VERSION 5.7 ;
BUSBITCHARS "[]" ;
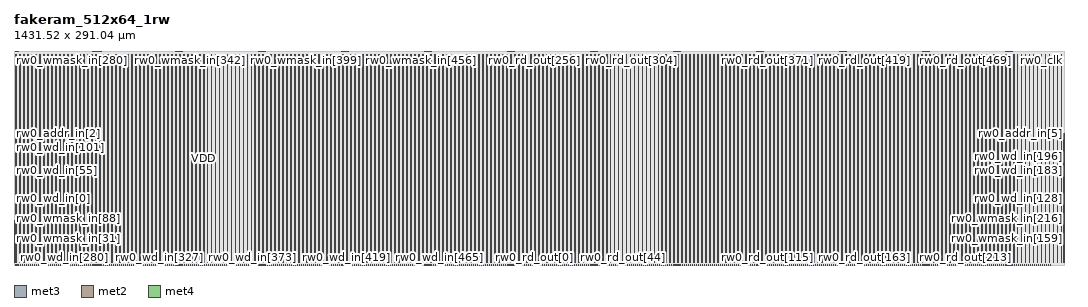
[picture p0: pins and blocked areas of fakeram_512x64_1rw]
MACRO fakeram_512x64_1rw
  FOREIGN fakeram_512x64_1rw 0 0 ;
  SYMMETRY X Y R90 ;
  SIZE 1431.520 BY 291.040 ;
  CLASS BLOCK ;
  PIN rw0_wmask_in[0]
    DIRECTION INPUT ;
    USE SIGNAL ;
    SHAPE ABUTMENT ;
    PORT
      LAYER met3 ;
      RECT 0.000 3.930 0.900 4.230 ;
    END
  END rw0_wmask_in[0]
  PIN rw0_wmask_in[1]
    DIRECTION INPUT ;
    USE SIGNAL ;
    SHAPE ABUTMENT ;
    PORT
      LAYER met3 ;
      RECT 0.000 4.610 0.900 4.910 ;
    END
  END rw0_wmask_in[1]
  PIN rw0_wmask_in[2]
    DIRECTION INPUT ;
    USE SIGNAL ;
    SHAPE ABUTMENT ;
    PORT
      LAYER met3 ;
      RECT 0.000 5.290 0.900 5.590 ;
    END
  END rw0_wmask_in[2]
  PIN rw0_wmask_in[3]
    DIRECTION INPUT ;
    USE SIGNAL ;
    SHAPE ABUTMENT ;
    PORT
      LAYER met3 ;
      RECT 0.000 5.970 0.900 6.270 ;
    END
  END rw0_wmask_in[3]
  PIN rw0_wmask_in[4]
    DIRECTION INPUT ;
    USE SIGNAL ;
    SHAPE ABUTMENT ;
    PORT
      LAYER met3 ;
      RECT 0.000 6.650 0.900 6.950 ;
    END
  END rw0_wmask_in[4]
  PIN rw0_wmask_in[5]
    DIRECTION INPUT ;
    USE SIGNAL ;
    SHAPE ABUTMENT ;
    PORT
      LAYER met3 ;
      RECT 0.000 7.330 0.900 7.630 ;
    END
  END rw0_wmask_in[5]
  PIN rw0_wmask_in[6]
    DIRECTION INPUT ;
    USE SIGNAL ;
    SHAPE ABUTMENT ;
    PORT
      LAYER met3 ;
      RECT 0.000 8.010 0.900 8.310 ;
    END
  END rw0_wmask_in[6]
  PIN rw0_wmask_in[7]
    DIRECTION INPUT ;
    USE SIGNAL ;
    SHAPE ABUTMENT ;
    PORT
      LAYER met3 ;
      RECT 0.000 8.690 0.900 8.990 ;
    END
  END rw0_wmask_in[7]
  PIN rw0_wmask_in[8]
    DIRECTION INPUT ;
    USE SIGNAL ;
    SHAPE ABUTMENT ;
    PORT
      LAYER met3 ;
      RECT 0.000 9.370 0.900 9.670 ;
    END
  END rw0_wmask_in[8]
  PIN rw0_wmask_in[9]
    DIRECTION INPUT ;
    USE SIGNAL ;
    SHAPE ABUTMENT ;
    PORT
      LAYER met3 ;
      RECT 0.000 10.050 0.900 10.350 ;
    END
  END rw0_wmask_in[9]
  PIN rw0_wmask_in[10]
    DIRECTION INPUT ;
    USE SIGNAL ;
    SHAPE ABUTMENT ;
    PORT
      LAYER met3 ;
      RECT 0.000 10.730 0.900 11.030 ;
    END
  END rw0_wmask_in[10]
  PIN rw0_wmask_in[11]
    DIRECTION INPUT ;
    USE SIGNAL ;
    SHAPE ABUTMENT ;
    PORT
      LAYER met3 ;
      RECT 0.000 11.410 0.900 11.710 ;
    END
  END rw0_wmask_in[11]
  PIN rw0_wmask_in[12]
    DIRECTION INPUT ;
    USE SIGNAL ;
    SHAPE ABUTMENT ;
    PORT
      LAYER met3 ;
      RECT 0.000 12.090 0.900 12.390 ;
    END
  END rw0_wmask_in[12]
  PIN rw0_wmask_in[13]
    DIRECTION INPUT ;
    USE SIGNAL ;
    SHAPE ABUTMENT ;
    PORT
      LAYER met3 ;
      RECT 0.000 12.770 0.900 13.070 ;
    END
  END rw0_wmask_in[13]
  PIN rw0_wmask_in[14]
    DIRECTION INPUT ;
    USE SIGNAL ;
    SHAPE ABUTMENT ;
    PORT
      LAYER met3 ;
      RECT 0.000 13.450 0.900 13.750 ;
    END
  END rw0_wmask_in[14]
  PIN rw0_wmask_in[15]
    DIRECTION INPUT ;
    USE SIGNAL ;
    SHAPE ABUTMENT ;
    PORT
      LAYER met3 ;
      RECT 0.000 14.130 0.900 14.430 ;
    END
  END rw0_wmask_in[15]
  PIN rw0_wmask_in[16]
    DIRECTION INPUT ;
    USE SIGNAL ;
    SHAPE ABUTMENT ;
    PORT
      LAYER met3 ;
      RECT 0.000 14.810 0.900 15.110 ;
    END
  END rw0_wmask_in[16]
  PIN rw0_wmask_in[17]
    DIRECTION INPUT ;
    USE SIGNAL ;
    SHAPE ABUTMENT ;
    PORT
      LAYER met3 ;
      RECT 0.000 15.490 0.900 15.790 ;
    END
  END rw0_wmask_in[17]
  PIN rw0_wmask_in[18]
    DIRECTION INPUT ;
    USE SIGNAL ;
    SHAPE ABUTMENT ;
    PORT
      LAYER met3 ;
      RECT 0.000 16.170 0.900 16.470 ;
    END
  END rw0_wmask_in[18]
  PIN rw0_wmask_in[19]
    DIRECTION INPUT ;
    USE SIGNAL ;
    SHAPE ABUTMENT ;
    PORT
      LAYER met3 ;
      RECT 0.000 16.850 0.900 17.150 ;
    END
  END rw0_wmask_in[19]
  PIN rw0_wmask_in[20]
    DIRECTION INPUT ;
    USE SIGNAL ;
    SHAPE ABUTMENT ;
    PORT
      LAYER met3 ;
      RECT 0.000 17.530 0.900 17.830 ;
    END
  END rw0_wmask_in[20]
  PIN rw0_wmask_in[21]
    DIRECTION INPUT ;
    USE SIGNAL ;
    SHAPE ABUTMENT ;
    PORT
      LAYER met3 ;
      RECT 0.000 18.210 0.900 18.510 ;
    END
  END rw0_wmask_in[21]
  PIN rw0_wmask_in[22]
    DIRECTION INPUT ;
    USE SIGNAL ;
    SHAPE ABUTMENT ;
    PORT
      LAYER met3 ;
      RECT 0.000 18.890 0.900 19.190 ;
    END
  END rw0_wmask_in[22]
  PIN rw0_wmask_in[23]
    DIRECTION INPUT ;
    USE SIGNAL ;
    SHAPE ABUTMENT ;
    PORT
      LAYER met3 ;
      RECT 0.000 19.570 0.900 19.870 ;
    END
  END rw0_wmask_in[23]
  PIN rw0_wmask_in[24]
    DIRECTION INPUT ;
    USE SIGNAL ;
    SHAPE ABUTMENT ;
    PORT
      LAYER met3 ;
      RECT 0.000 20.250 0.900 20.550 ;
    END
  END rw0_wmask_in[24]
  PIN rw0_wmask_in[25]
    DIRECTION INPUT ;
    USE SIGNAL ;
    SHAPE ABUTMENT ;
    PORT
      LAYER met3 ;
      RECT 0.000 20.930 0.900 21.230 ;
    END
  END rw0_wmask_in[25]
  PIN rw0_wmask_in[26]
    DIRECTION INPUT ;
    USE SIGNAL ;
    SHAPE ABUTMENT ;
    PORT
      LAYER met3 ;
      RECT 0.000 21.610 0.900 21.910 ;
    END
  END rw0_wmask_in[26]
  PIN rw0_wmask_in[27]
    DIRECTION INPUT ;
    USE SIGNAL ;
    SHAPE ABUTMENT ;
    PORT
      LAYER met3 ;
      RECT 0.000 22.290 0.900 22.590 ;
    END
  END rw0_wmask_in[27]
  PIN rw0_wmask_in[28]
    DIRECTION INPUT ;
    USE SIGNAL ;
    SHAPE ABUTMENT ;
    PORT
      LAYER met3 ;
      RECT 0.000 22.970 0.900 23.270 ;
    END
  END rw0_wmask_in[28]
  PIN rw0_wmask_in[29]
    DIRECTION INPUT ;
    USE SIGNAL ;
    SHAPE ABUTMENT ;
    PORT
      LAYER met3 ;
      RECT 0.000 23.650 0.900 23.950 ;
    END
  END rw0_wmask_in[29]
  PIN rw0_wmask_in[30]
    DIRECTION INPUT ;
    USE SIGNAL ;
    SHAPE ABUTMENT ;
    PORT
      LAYER met3 ;
      RECT 0.000 24.330 0.900 24.630 ;
    END
  END rw0_wmask_in[30]
  PIN rw0_wmask_in[31]
    DIRECTION INPUT ;
    USE SIGNAL ;
    SHAPE ABUTMENT ;
    PORT
      LAYER met3 ;
      RECT 0.000 25.010 0.900 25.310 ;
    END
  END rw0_wmask_in[31]
  PIN rw0_wmask_in[32]
    DIRECTION INPUT ;
    USE SIGNAL ;
    SHAPE ABUTMENT ;
    PORT
      LAYER met3 ;
      RECT 0.000 25.690 0.900 25.990 ;
    END
  END rw0_wmask_in[32]
  PIN rw0_wmask_in[33]
    DIRECTION INPUT ;
    USE SIGNAL ;
    SHAPE ABUTMENT ;
    PORT
      LAYER met3 ;
      RECT 0.000 26.370 0.900 26.670 ;
    END
  END rw0_wmask_in[33]
  PIN rw0_wmask_in[34]
    DIRECTION INPUT ;
    USE SIGNAL ;
    SHAPE ABUTMENT ;
    PORT
      LAYER met3 ;
      RECT 0.000 27.050 0.900 27.350 ;
    END
  END rw0_wmask_in[34]
  PIN rw0_wmask_in[35]
    DIRECTION INPUT ;
    USE SIGNAL ;
    SHAPE ABUTMENT ;
    PORT
      LAYER met3 ;
      RECT 0.000 27.730 0.900 28.030 ;
    END
  END rw0_wmask_in[35]
  PIN rw0_wmask_in[36]
    DIRECTION INPUT ;
    USE SIGNAL ;
    SHAPE ABUTMENT ;
    PORT
      LAYER met3 ;
      RECT 0.000 28.410 0.900 28.710 ;
    END
  END rw0_wmask_in[36]
  PIN rw0_wmask_in[37]
    DIRECTION INPUT ;
    USE SIGNAL ;
    SHAPE ABUTMENT ;
    PORT
      LAYER met3 ;
      RECT 0.000 29.090 0.900 29.390 ;
    END
  END rw0_wmask_in[37]
  PIN rw0_wmask_in[38]
    DIRECTION INPUT ;
    USE SIGNAL ;
    SHAPE ABUTMENT ;
    PORT
      LAYER met3 ;
      RECT 0.000 29.770 0.900 30.070 ;
    END
  END rw0_wmask_in[38]
  PIN rw0_wmask_in[39]
    DIRECTION INPUT ;
    USE SIGNAL ;
    SHAPE ABUTMENT ;
    PORT
      LAYER met3 ;
      RECT 0.000 30.450 0.900 30.750 ;
    END
  END rw0_wmask_in[39]
  PIN rw0_wmask_in[40]
    DIRECTION INPUT ;
    USE SIGNAL ;
    SHAPE ABUTMENT ;
    PORT
      LAYER met3 ;
      RECT 0.000 31.130 0.900 31.430 ;
    END
  END rw0_wmask_in[40]
  PIN rw0_wmask_in[41]
    DIRECTION INPUT ;
    USE SIGNAL ;
    SHAPE ABUTMENT ;
    PORT
      LAYER met3 ;
      RECT 0.000 31.810 0.900 32.110 ;
    END
  END rw0_wmask_in[41]
  PIN rw0_wmask_in[42]
    DIRECTION INPUT ;
    USE SIGNAL ;
    SHAPE ABUTMENT ;
    PORT
      LAYER met3 ;
      RECT 0.000 32.490 0.900 32.790 ;
    END
  END rw0_wmask_in[42]
  PIN rw0_wmask_in[43]
    DIRECTION INPUT ;
    USE SIGNAL ;
    SHAPE ABUTMENT ;
    PORT
      LAYER met3 ;
      RECT 0.000 33.170 0.900 33.470 ;
    END
  END rw0_wmask_in[43]
  PIN rw0_wmask_in[44]
    DIRECTION INPUT ;
    USE SIGNAL ;
    SHAPE ABUTMENT ;
    PORT
      LAYER met3 ;
      RECT 0.000 33.850 0.900 34.150 ;
    END
  END rw0_wmask_in[44]
  PIN rw0_wmask_in[45]
    DIRECTION INPUT ;
    USE SIGNAL ;
    SHAPE ABUTMENT ;
    PORT
      LAYER met3 ;
      RECT 0.000 34.530 0.900 34.830 ;
    END
  END rw0_wmask_in[45]
  PIN rw0_wmask_in[46]
    DIRECTION INPUT ;
    USE SIGNAL ;
    SHAPE ABUTMENT ;
    PORT
      LAYER met3 ;
      RECT 0.000 35.210 0.900 35.510 ;
    END
  END rw0_wmask_in[46]
  PIN rw0_wmask_in[47]
    DIRECTION INPUT ;
    USE SIGNAL ;
    SHAPE ABUTMENT ;
    PORT
      LAYER met3 ;
      RECT 0.000 35.890 0.900 36.190 ;
    END
  END rw0_wmask_in[47]
  PIN rw0_wmask_in[48]
    DIRECTION INPUT ;
    USE SIGNAL ;
    SHAPE ABUTMENT ;
    PORT
      LAYER met3 ;
      RECT 0.000 36.570 0.900 36.870 ;
    END
  END rw0_wmask_in[48]
  PIN rw0_wmask_in[49]
    DIRECTION INPUT ;
    USE SIGNAL ;
    SHAPE ABUTMENT ;
    PORT
      LAYER met3 ;
      RECT 0.000 37.250 0.900 37.550 ;
    END
  END rw0_wmask_in[49]
  PIN rw0_wmask_in[50]
    DIRECTION INPUT ;
    USE SIGNAL ;
    SHAPE ABUTMENT ;
    PORT
      LAYER met3 ;
      RECT 0.000 37.930 0.900 38.230 ;
    END
  END rw0_wmask_in[50]
  PIN rw0_wmask_in[51]
    DIRECTION INPUT ;
    USE SIGNAL ;
    SHAPE ABUTMENT ;
    PORT
      LAYER met3 ;
      RECT 0.000 38.610 0.900 38.910 ;
    END
  END rw0_wmask_in[51]
  PIN rw0_wmask_in[52]
    DIRECTION INPUT ;
    USE SIGNAL ;
    SHAPE ABUTMENT ;
    PORT
      LAYER met3 ;
      RECT 0.000 39.290 0.900 39.590 ;
    END
  END rw0_wmask_in[52]
  PIN rw0_wmask_in[53]
    DIRECTION INPUT ;
    USE SIGNAL ;
    SHAPE ABUTMENT ;
    PORT
      LAYER met3 ;
      RECT 0.000 39.970 0.900 40.270 ;
    END
  END rw0_wmask_in[53]
  PIN rw0_wmask_in[54]
    DIRECTION INPUT ;
    USE SIGNAL ;
    SHAPE ABUTMENT ;
    PORT
      LAYER met3 ;
      RECT 0.000 40.650 0.900 40.950 ;
    END
  END rw0_wmask_in[54]
  PIN rw0_wmask_in[55]
    DIRECTION INPUT ;
    USE SIGNAL ;
    SHAPE ABUTMENT ;
    PORT
      LAYER met3 ;
      RECT 0.000 41.330 0.900 41.630 ;
    END
  END rw0_wmask_in[55]
  PIN rw0_wmask_in[56]
    DIRECTION INPUT ;
    USE SIGNAL ;
    SHAPE ABUTMENT ;
    PORT
      LAYER met3 ;
      RECT 0.000 42.010 0.900 42.310 ;
    END
  END rw0_wmask_in[56]
  PIN rw0_wmask_in[57]
    DIRECTION INPUT ;
    USE SIGNAL ;
    SHAPE ABUTMENT ;
    PORT
      LAYER met3 ;
      RECT 0.000 42.690 0.900 42.990 ;
    END
  END rw0_wmask_in[57]
  PIN rw0_wmask_in[58]
    DIRECTION INPUT ;
    USE SIGNAL ;
    SHAPE ABUTMENT ;
    PORT
      LAYER met3 ;
      RECT 0.000 43.370 0.900 43.670 ;
    END
  END rw0_wmask_in[58]
  PIN rw0_wmask_in[59]
    DIRECTION INPUT ;
    USE SIGNAL ;
    SHAPE ABUTMENT ;
    PORT
      LAYER met3 ;
      RECT 0.000 44.050 0.900 44.350 ;
    END
  END rw0_wmask_in[59]
  PIN rw0_wmask_in[60]
    DIRECTION INPUT ;
    USE SIGNAL ;
    SHAPE ABUTMENT ;
    PORT
      LAYER met3 ;
      RECT 0.000 44.730 0.900 45.030 ;
    END
  END rw0_wmask_in[60]
  PIN rw0_wmask_in[61]
    DIRECTION INPUT ;
    USE SIGNAL ;
    SHAPE ABUTMENT ;
    PORT
      LAYER met3 ;
      RECT 0.000 45.410 0.900 45.710 ;
    END
  END rw0_wmask_in[61]
  PIN rw0_wmask_in[62]
    DIRECTION INPUT ;
    USE SIGNAL ;
    SHAPE ABUTMENT ;
    PORT
      LAYER met3 ;
      RECT 0.000 46.090 0.900 46.390 ;
    END
  END rw0_wmask_in[62]
  PIN rw0_wmask_in[63]
    DIRECTION INPUT ;
    USE SIGNAL ;
    SHAPE ABUTMENT ;
    PORT
      LAYER met3 ;
      RECT 0.000 46.770 0.900 47.070 ;
    END
  END rw0_wmask_in[63]
  PIN rw0_wmask_in[64]
    DIRECTION INPUT ;
    USE SIGNAL ;
    SHAPE ABUTMENT ;
    PORT
      LAYER met3 ;
      RECT 0.000 47.450 0.900 47.750 ;
    END
  END rw0_wmask_in[64]
  PIN rw0_wmask_in[65]
    DIRECTION INPUT ;
    USE SIGNAL ;
    SHAPE ABUTMENT ;
    PORT
      LAYER met3 ;
      RECT 0.000 48.130 0.900 48.430 ;
    END
  END rw0_wmask_in[65]
  PIN rw0_wmask_in[66]
    DIRECTION INPUT ;
    USE SIGNAL ;
    SHAPE ABUTMENT ;
    PORT
      LAYER met3 ;
      RECT 0.000 48.810 0.900 49.110 ;
    END
  END rw0_wmask_in[66]
  PIN rw0_wmask_in[67]
    DIRECTION INPUT ;
    USE SIGNAL ;
    SHAPE ABUTMENT ;
    PORT
      LAYER met3 ;
      RECT 0.000 49.490 0.900 49.790 ;
    END
  END rw0_wmask_in[67]
  PIN rw0_wmask_in[68]
    DIRECTION INPUT ;
    USE SIGNAL ;
    SHAPE ABUTMENT ;
    PORT
      LAYER met3 ;
      RECT 0.000 50.170 0.900 50.470 ;
    END
  END rw0_wmask_in[68]
  PIN rw0_wmask_in[69]
    DIRECTION INPUT ;
    USE SIGNAL ;
    SHAPE ABUTMENT ;
    PORT
      LAYER met3 ;
      RECT 0.000 50.850 0.900 51.150 ;
    END
  END rw0_wmask_in[69]
  PIN rw0_wmask_in[70]
    DIRECTION INPUT ;
    USE SIGNAL ;
    SHAPE ABUTMENT ;
    PORT
      LAYER met3 ;
      RECT 0.000 51.530 0.900 51.830 ;
    END
  END rw0_wmask_in[70]
  PIN rw0_wmask_in[71]
    DIRECTION INPUT ;
    USE SIGNAL ;
    SHAPE ABUTMENT ;
    PORT
      LAYER met3 ;
      RECT 0.000 52.210 0.900 52.510 ;
    END
  END rw0_wmask_in[71]
  PIN rw0_wmask_in[72]
    DIRECTION INPUT ;
    USE SIGNAL ;
    SHAPE ABUTMENT ;
    PORT
      LAYER met3 ;
      RECT 0.000 52.890 0.900 53.190 ;
    END
  END rw0_wmask_in[72]
  PIN rw0_wmask_in[73]
    DIRECTION INPUT ;
    USE SIGNAL ;
    SHAPE ABUTMENT ;
    PORT
      LAYER met3 ;
      RECT 0.000 53.570 0.900 53.870 ;
    END
  END rw0_wmask_in[73]
  PIN rw0_wmask_in[74]
    DIRECTION INPUT ;
    USE SIGNAL ;
    SHAPE ABUTMENT ;
    PORT
      LAYER met3 ;
      RECT 0.000 54.250 0.900 54.550 ;
    END
  END rw0_wmask_in[74]
  PIN rw0_wmask_in[75]
    DIRECTION INPUT ;
    USE SIGNAL ;
    SHAPE ABUTMENT ;
    PORT
      LAYER met3 ;
      RECT 0.000 54.930 0.900 55.230 ;
    END
  END rw0_wmask_in[75]
  PIN rw0_wmask_in[76]
    DIRECTION INPUT ;
    USE SIGNAL ;
    SHAPE ABUTMENT ;
    PORT
      LAYER met3 ;
      RECT 0.000 55.610 0.900 55.910 ;
    END
  END rw0_wmask_in[76]
  PIN rw0_wmask_in[77]
    DIRECTION INPUT ;
    USE SIGNAL ;
    SHAPE ABUTMENT ;
    PORT
      LAYER met3 ;
      RECT 0.000 56.290 0.900 56.590 ;
    END
  END rw0_wmask_in[77]
  PIN rw0_wmask_in[78]
    DIRECTION INPUT ;
    USE SIGNAL ;
    SHAPE ABUTMENT ;
    PORT
      LAYER met3 ;
      RECT 0.000 56.970 0.900 57.270 ;
    END
  END rw0_wmask_in[78]
  PIN rw0_wmask_in[79]
    DIRECTION INPUT ;
    USE SIGNAL ;
    SHAPE ABUTMENT ;
    PORT
      LAYER met3 ;
      RECT 0.000 57.650 0.900 57.950 ;
    END
  END rw0_wmask_in[79]
  PIN rw0_wmask_in[80]
    DIRECTION INPUT ;
    USE SIGNAL ;
    SHAPE ABUTMENT ;
    PORT
      LAYER met3 ;
      RECT 0.000 58.330 0.900 58.630 ;
    END
  END rw0_wmask_in[80]
  PIN rw0_wmask_in[81]
    DIRECTION INPUT ;
    USE SIGNAL ;
    SHAPE ABUTMENT ;
    PORT
      LAYER met3 ;
      RECT 0.000 59.010 0.900 59.310 ;
    END
  END rw0_wmask_in[81]
  PIN rw0_wmask_in[82]
    DIRECTION INPUT ;
    USE SIGNAL ;
    SHAPE ABUTMENT ;
    PORT
      LAYER met3 ;
      RECT 0.000 59.690 0.900 59.990 ;
    END
  END rw0_wmask_in[82]
  PIN rw0_wmask_in[83]
    DIRECTION INPUT ;
    USE SIGNAL ;
    SHAPE ABUTMENT ;
    PORT
      LAYER met3 ;
      RECT 0.000 60.370 0.900 60.670 ;
    END
  END rw0_wmask_in[83]
  PIN rw0_wmask_in[84]
    DIRECTION INPUT ;
    USE SIGNAL ;
    SHAPE ABUTMENT ;
    PORT
      LAYER met3 ;
      RECT 0.000 61.050 0.900 61.350 ;
    END
  END rw0_wmask_in[84]
  PIN rw0_wmask_in[85]
    DIRECTION INPUT ;
    USE SIGNAL ;
    SHAPE ABUTMENT ;
    PORT
      LAYER met3 ;
      RECT 0.000 61.730 0.900 62.030 ;
    END
  END rw0_wmask_in[85]
  PIN rw0_wmask_in[86]
    DIRECTION INPUT ;
    USE SIGNAL ;
    SHAPE ABUTMENT ;
    PORT
      LAYER met3 ;
      RECT 0.000 62.410 0.900 62.710 ;
    END
  END rw0_wmask_in[86]
  PIN rw0_wmask_in[87]
    DIRECTION INPUT ;
    USE SIGNAL ;
    SHAPE ABUTMENT ;
    PORT
      LAYER met3 ;
      RECT 0.000 63.090 0.900 63.390 ;
    END
  END rw0_wmask_in[87]
  PIN rw0_wmask_in[88]
    DIRECTION INPUT ;
    USE SIGNAL ;
    SHAPE ABUTMENT ;
    PORT
      LAYER met3 ;
      RECT 0.000 63.770 0.900 64.070 ;
    END
  END rw0_wmask_in[88]
  PIN rw0_wmask_in[89]
    DIRECTION INPUT ;
    USE SIGNAL ;
    SHAPE ABUTMENT ;
    PORT
      LAYER met3 ;
      RECT 0.000 64.450 0.900 64.750 ;
    END
  END rw0_wmask_in[89]
  PIN rw0_wmask_in[90]
    DIRECTION INPUT ;
    USE SIGNAL ;
    SHAPE ABUTMENT ;
    PORT
      LAYER met3 ;
      RECT 0.000 65.130 0.900 65.430 ;
    END
  END rw0_wmask_in[90]
  PIN rw0_wmask_in[91]
    DIRECTION INPUT ;
    USE SIGNAL ;
    SHAPE ABUTMENT ;
    PORT
      LAYER met3 ;
      RECT 0.000 65.810 0.900 66.110 ;
    END
  END rw0_wmask_in[91]
  PIN rw0_wmask_in[92]
    DIRECTION INPUT ;
    USE SIGNAL ;
    SHAPE ABUTMENT ;
    PORT
      LAYER met3 ;
      RECT 0.000 66.490 0.900 66.790 ;
    END
  END rw0_wmask_in[92]
  PIN rw0_wmask_in[93]
    DIRECTION INPUT ;
    USE SIGNAL ;
    SHAPE ABUTMENT ;
    PORT
      LAYER met3 ;
      RECT 0.000 67.170 0.900 67.470 ;
    END
  END rw0_wmask_in[93]
  PIN rw0_wmask_in[94]
    DIRECTION INPUT ;
    USE SIGNAL ;
    SHAPE ABUTMENT ;
    PORT
      LAYER met3 ;
      RECT 0.000 67.850 0.900 68.150 ;
    END
  END rw0_wmask_in[94]
  PIN rw0_wmask_in[95]
    DIRECTION INPUT ;
    USE SIGNAL ;
    SHAPE ABUTMENT ;
    PORT
      LAYER met3 ;
      RECT 0.000 68.530 0.900 68.830 ;
    END
  END rw0_wmask_in[95]
  PIN rw0_wmask_in[96]
    DIRECTION INPUT ;
    USE SIGNAL ;
    SHAPE ABUTMENT ;
    PORT
      LAYER met3 ;
      RECT 0.000 69.210 0.900 69.510 ;
    END
  END rw0_wmask_in[96]
  PIN rw0_wmask_in[97]
    DIRECTION INPUT ;
    USE SIGNAL ;
    SHAPE ABUTMENT ;
    PORT
      LAYER met3 ;
      RECT 0.000 69.890 0.900 70.190 ;
    END
  END rw0_wmask_in[97]
  PIN rw0_wmask_in[98]
    DIRECTION INPUT ;
    USE SIGNAL ;
    SHAPE ABUTMENT ;
    PORT
      LAYER met3 ;
      RECT 0.000 70.570 0.900 70.870 ;
    END
  END rw0_wmask_in[98]
  PIN rw0_wmask_in[99]
    DIRECTION INPUT ;
    USE SIGNAL ;
    SHAPE ABUTMENT ;
    PORT
      LAYER met3 ;
      RECT 0.000 71.250 0.900 71.550 ;
    END
  END rw0_wmask_in[99]
  PIN rw0_wmask_in[100]
    DIRECTION INPUT ;
    USE SIGNAL ;
    SHAPE ABUTMENT ;
    PORT
      LAYER met3 ;
      RECT 0.000 71.930 0.900 72.230 ;
    END
  END rw0_wmask_in[100]
  PIN rw0_wmask_in[101]
    DIRECTION INPUT ;
    USE SIGNAL ;
    SHAPE ABUTMENT ;
    PORT
      LAYER met3 ;
      RECT 0.000 72.610 0.900 72.910 ;
    END
  END rw0_wmask_in[101]
  PIN rw0_wmask_in[102]
    DIRECTION INPUT ;
    USE SIGNAL ;
    SHAPE ABUTMENT ;
    PORT
      LAYER met3 ;
      RECT 0.000 73.290 0.900 73.590 ;
    END
  END rw0_wmask_in[102]
  PIN rw0_wmask_in[103]
    DIRECTION INPUT ;
    USE SIGNAL ;
    SHAPE ABUTMENT ;
    PORT
      LAYER met3 ;
      RECT 0.000 73.970 0.900 74.270 ;
    END
  END rw0_wmask_in[103]
  PIN rw0_wmask_in[104]
    DIRECTION INPUT ;
    USE SIGNAL ;
    SHAPE ABUTMENT ;
    PORT
      LAYER met3 ;
      RECT 0.000 74.650 0.900 74.950 ;
    END
  END rw0_wmask_in[104]
  PIN rw0_wmask_in[105]
    DIRECTION INPUT ;
    USE SIGNAL ;
    SHAPE ABUTMENT ;
    PORT
      LAYER met3 ;
      RECT 0.000 75.330 0.900 75.630 ;
    END
  END rw0_wmask_in[105]
  PIN rw0_wmask_in[106]
    DIRECTION INPUT ;
    USE SIGNAL ;
    SHAPE ABUTMENT ;
    PORT
      LAYER met3 ;
      RECT 0.000 76.010 0.900 76.310 ;
    END
  END rw0_wmask_in[106]
  PIN rw0_wmask_in[107]
    DIRECTION INPUT ;
    USE SIGNAL ;
    SHAPE ABUTMENT ;
    PORT
      LAYER met3 ;
      RECT 0.000 76.690 0.900 76.990 ;
    END
  END rw0_wmask_in[107]
  PIN rw0_wmask_in[108]
    DIRECTION INPUT ;
    USE SIGNAL ;
    SHAPE ABUTMENT ;
    PORT
      LAYER met3 ;
      RECT 0.000 77.370 0.900 77.670 ;
    END
  END rw0_wmask_in[108]
  PIN rw0_wmask_in[109]
    DIRECTION INPUT ;
    USE SIGNAL ;
    SHAPE ABUTMENT ;
    PORT
      LAYER met3 ;
      RECT 0.000 78.050 0.900 78.350 ;
    END
  END rw0_wmask_in[109]
  PIN rw0_wmask_in[110]
    DIRECTION INPUT ;
    USE SIGNAL ;
    SHAPE ABUTMENT ;
    PORT
      LAYER met3 ;
      RECT 0.000 78.730 0.900 79.030 ;
    END
  END rw0_wmask_in[110]
  PIN rw0_wmask_in[111]
    DIRECTION INPUT ;
    USE SIGNAL ;
    SHAPE ABUTMENT ;
    PORT
      LAYER met3 ;
      RECT 0.000 79.410 0.900 79.710 ;
    END
  END rw0_wmask_in[111]
  PIN rw0_wmask_in[112]
    DIRECTION INPUT ;
    USE SIGNAL ;
    SHAPE ABUTMENT ;
    PORT
      LAYER met3 ;
      RECT 0.000 80.090 0.900 80.390 ;
    END
  END rw0_wmask_in[112]
  PIN rw0_wmask_in[113]
    DIRECTION INPUT ;
    USE SIGNAL ;
    SHAPE ABUTMENT ;
    PORT
      LAYER met3 ;
      RECT 0.000 80.770 0.900 81.070 ;
    END
  END rw0_wmask_in[113]
  PIN rw0_wmask_in[114]
    DIRECTION INPUT ;
    USE SIGNAL ;
    SHAPE ABUTMENT ;
    PORT
      LAYER met3 ;
      RECT 0.000 81.450 0.900 81.750 ;
    END
  END rw0_wmask_in[114]
  PIN rw0_wmask_in[115]
    DIRECTION INPUT ;
    USE SIGNAL ;
    SHAPE ABUTMENT ;
    PORT
      LAYER met3 ;
      RECT 0.000 82.130 0.900 82.430 ;
    END
  END rw0_wmask_in[115]
  PIN rw0_wmask_in[116]
    DIRECTION INPUT ;
    USE SIGNAL ;
    SHAPE ABUTMENT ;
    PORT
      LAYER met3 ;
      RECT 0.000 82.810 0.900 83.110 ;
    END
  END rw0_wmask_in[116]
  PIN rw0_wmask_in[117]
    DIRECTION INPUT ;
    USE SIGNAL ;
    SHAPE ABUTMENT ;
    PORT
      LAYER met3 ;
      RECT 0.000 83.490 0.900 83.790 ;
    END
  END rw0_wmask_in[117]
  PIN rw0_wmask_in[118]
    DIRECTION INPUT ;
    USE SIGNAL ;
    SHAPE ABUTMENT ;
    PORT
      LAYER met3 ;
      RECT 0.000 84.170 0.900 84.470 ;
    END
  END rw0_wmask_in[118]
  PIN rw0_wmask_in[119]
    DIRECTION INPUT ;
    USE SIGNAL ;
    SHAPE ABUTMENT ;
    PORT
      LAYER met3 ;
      RECT 0.000 84.850 0.900 85.150 ;
    END
  END rw0_wmask_in[119]
  PIN rw0_wmask_in[120]
    DIRECTION INPUT ;
    USE SIGNAL ;
    SHAPE ABUTMENT ;
    PORT
      LAYER met3 ;
      RECT 0.000 85.530 0.900 85.830 ;
    END
  END rw0_wmask_in[120]
  PIN rw0_wmask_in[121]
    DIRECTION INPUT ;
    USE SIGNAL ;
    SHAPE ABUTMENT ;
    PORT
      LAYER met3 ;
      RECT 0.000 86.210 0.900 86.510 ;
    END
  END rw0_wmask_in[121]
  PIN rw0_wmask_in[122]
    DIRECTION INPUT ;
    USE SIGNAL ;
    SHAPE ABUTMENT ;
    PORT
      LAYER met3 ;
      RECT 0.000 86.890 0.900 87.190 ;
    END
  END rw0_wmask_in[122]
  PIN rw0_wmask_in[123]
    DIRECTION INPUT ;
    USE SIGNAL ;
    SHAPE ABUTMENT ;
    PORT
      LAYER met3 ;
      RECT 0.000 87.570 0.900 87.870 ;
    END
  END rw0_wmask_in[123]
  PIN rw0_wmask_in[124]
    DIRECTION INPUT ;
    USE SIGNAL ;
    SHAPE ABUTMENT ;
    PORT
      LAYER met3 ;
      RECT 0.000 88.250 0.900 88.550 ;
    END
  END rw0_wmask_in[124]
  PIN rw0_wmask_in[125]
    DIRECTION INPUT ;
    USE SIGNAL ;
    SHAPE ABUTMENT ;
    PORT
      LAYER met3 ;
      RECT 0.000 88.930 0.900 89.230 ;
    END
  END rw0_wmask_in[125]
  PIN rw0_wmask_in[126]
    DIRECTION INPUT ;
    USE SIGNAL ;
    SHAPE ABUTMENT ;
    PORT
      LAYER met3 ;
      RECT 0.000 89.610 0.900 89.910 ;
    END
  END rw0_wmask_in[126]
  PIN rw0_wmask_in[127]
    DIRECTION INPUT ;
    USE SIGNAL ;
    SHAPE ABUTMENT ;
    PORT
      LAYER met3 ;
      RECT 0.000 90.290 0.900 90.590 ;
    END
  END rw0_wmask_in[127]
  PIN rw0_wmask_in[128]
    DIRECTION INPUT ;
    USE SIGNAL ;
    SHAPE ABUTMENT ;
    PORT
      LAYER met3 ;
      RECT 1430.620 3.930 1431.520 4.230 ;
    END
  END rw0_wmask_in[128]
  PIN rw0_wmask_in[129]
    DIRECTION INPUT ;
    USE SIGNAL ;
    SHAPE ABUTMENT ;
    PORT
      LAYER met3 ;
      RECT 1430.620 4.610 1431.520 4.910 ;
    END
  END rw0_wmask_in[129]
  PIN rw0_wmask_in[130]
    DIRECTION INPUT ;
    USE SIGNAL ;
    SHAPE ABUTMENT ;
    PORT
      LAYER met3 ;
      RECT 1430.620 5.290 1431.520 5.590 ;
    END
  END rw0_wmask_in[130]
  PIN rw0_wmask_in[131]
    DIRECTION INPUT ;
    USE SIGNAL ;
    SHAPE ABUTMENT ;
    PORT
      LAYER met3 ;
      RECT 1430.620 5.970 1431.520 6.270 ;
    END
  END rw0_wmask_in[131]
  PIN rw0_wmask_in[132]
    DIRECTION INPUT ;
    USE SIGNAL ;
    SHAPE ABUTMENT ;
    PORT
      LAYER met3 ;
      RECT 1430.620 6.650 1431.520 6.950 ;
    END
  END rw0_wmask_in[132]
  PIN rw0_wmask_in[133]
    DIRECTION INPUT ;
    USE SIGNAL ;
    SHAPE ABUTMENT ;
    PORT
      LAYER met3 ;
      RECT 1430.620 7.330 1431.520 7.630 ;
    END
  END rw0_wmask_in[133]
  PIN rw0_wmask_in[134]
    DIRECTION INPUT ;
    USE SIGNAL ;
    SHAPE ABUTMENT ;
    PORT
      LAYER met3 ;
      RECT 1430.620 8.010 1431.520 8.310 ;
    END
  END rw0_wmask_in[134]
  PIN rw0_wmask_in[135]
    DIRECTION INPUT ;
    USE SIGNAL ;
    SHAPE ABUTMENT ;
    PORT
      LAYER met3 ;
      RECT 1430.620 8.690 1431.520 8.990 ;
    END
  END rw0_wmask_in[135]
  PIN rw0_wmask_in[136]
    DIRECTION INPUT ;
    USE SIGNAL ;
    SHAPE ABUTMENT ;
    PORT
      LAYER met3 ;
      RECT 1430.620 9.370 1431.520 9.670 ;
    END
  END rw0_wmask_in[136]
  PIN rw0_wmask_in[137]
    DIRECTION INPUT ;
    USE SIGNAL ;
    SHAPE ABUTMENT ;
    PORT
      LAYER met3 ;
      RECT 1430.620 10.050 1431.520 10.350 ;
    END
  END rw0_wmask_in[137]
  PIN rw0_wmask_in[138]
    DIRECTION INPUT ;
    USE SIGNAL ;
    SHAPE ABUTMENT ;
    PORT
      LAYER met3 ;
      RECT 1430.620 10.730 1431.520 11.030 ;
    END
  END rw0_wmask_in[138]
  PIN rw0_wmask_in[139]
    DIRECTION INPUT ;
    USE SIGNAL ;
    SHAPE ABUTMENT ;
    PORT
      LAYER met3 ;
      RECT 1430.620 11.410 1431.520 11.710 ;
    END
  END rw0_wmask_in[139]
  PIN rw0_wmask_in[140]
    DIRECTION INPUT ;
    USE SIGNAL ;
    SHAPE ABUTMENT ;
    PORT
      LAYER met3 ;
      RECT 1430.620 12.090 1431.520 12.390 ;
    END
  END rw0_wmask_in[140]
  PIN rw0_wmask_in[141]
    DIRECTION INPUT ;
    USE SIGNAL ;
    SHAPE ABUTMENT ;
    PORT
      LAYER met3 ;
      RECT 1430.620 12.770 1431.520 13.070 ;
    END
  END rw0_wmask_in[141]
  PIN rw0_wmask_in[142]
    DIRECTION INPUT ;
    USE SIGNAL ;
    SHAPE ABUTMENT ;
    PORT
      LAYER met3 ;
      RECT 1430.620 13.450 1431.520 13.750 ;
    END
  END rw0_wmask_in[142]
  PIN rw0_wmask_in[143]
    DIRECTION INPUT ;
    USE SIGNAL ;
    SHAPE ABUTMENT ;
    PORT
      LAYER met3 ;
      RECT 1430.620 14.130 1431.520 14.430 ;
    END
  END rw0_wmask_in[143]
  PIN rw0_wmask_in[144]
    DIRECTION INPUT ;
    USE SIGNAL ;
    SHAPE ABUTMENT ;
    PORT
      LAYER met3 ;
      RECT 1430.620 14.810 1431.520 15.110 ;
    END
  END rw0_wmask_in[144]
  PIN rw0_wmask_in[145]
    DIRECTION INPUT ;
    USE SIGNAL ;
    SHAPE ABUTMENT ;
    PORT
      LAYER met3 ;
      RECT 1430.620 15.490 1431.520 15.790 ;
    END
  END rw0_wmask_in[145]
  PIN rw0_wmask_in[146]
    DIRECTION INPUT ;
    USE SIGNAL ;
    SHAPE ABUTMENT ;
    PORT
      LAYER met3 ;
      RECT 1430.620 16.170 1431.520 16.470 ;
    END
  END rw0_wmask_in[146]
  PIN rw0_wmask_in[147]
    DIRECTION INPUT ;
    USE SIGNAL ;
    SHAPE ABUTMENT ;
    PORT
      LAYER met3 ;
      RECT 1430.620 16.850 1431.520 17.150 ;
    END
  END rw0_wmask_in[147]
  PIN rw0_wmask_in[148]
    DIRECTION INPUT ;
    USE SIGNAL ;
    SHAPE ABUTMENT ;
    PORT
      LAYER met3 ;
      RECT 1430.620 17.530 1431.520 17.830 ;
    END
  END rw0_wmask_in[148]
  PIN rw0_wmask_in[149]
    DIRECTION INPUT ;
    USE SIGNAL ;
    SHAPE ABUTMENT ;
    PORT
      LAYER met3 ;
      RECT 1430.620 18.210 1431.520 18.510 ;
    END
  END rw0_wmask_in[149]
  PIN rw0_wmask_in[150]
    DIRECTION INPUT ;
    USE SIGNAL ;
    SHAPE ABUTMENT ;
    PORT
      LAYER met3 ;
      RECT 1430.620 18.890 1431.520 19.190 ;
    END
  END rw0_wmask_in[150]
  PIN rw0_wmask_in[151]
    DIRECTION INPUT ;
    USE SIGNAL ;
    SHAPE ABUTMENT ;
    PORT
      LAYER met3 ;
      RECT 1430.620 19.570 1431.520 19.870 ;
    END
  END rw0_wmask_in[151]
  PIN rw0_wmask_in[152]
    DIRECTION INPUT ;
    USE SIGNAL ;
    SHAPE ABUTMENT ;
    PORT
      LAYER met3 ;
      RECT 1430.620 20.250 1431.520 20.550 ;
    END
  END rw0_wmask_in[152]
  PIN rw0_wmask_in[153]
    DIRECTION INPUT ;
    USE SIGNAL ;
    SHAPE ABUTMENT ;
    PORT
      LAYER met3 ;
      RECT 1430.620 20.930 1431.520 21.230 ;
    END
  END rw0_wmask_in[153]
  PIN rw0_wmask_in[154]
    DIRECTION INPUT ;
    USE SIGNAL ;
    SHAPE ABUTMENT ;
    PORT
      LAYER met3 ;
      RECT 1430.620 21.610 1431.520 21.910 ;
    END
  END rw0_wmask_in[154]
  PIN rw0_wmask_in[155]
    DIRECTION INPUT ;
    USE SIGNAL ;
    SHAPE ABUTMENT ;
    PORT
      LAYER met3 ;
      RECT 1430.620 22.290 1431.520 22.590 ;
    END
  END rw0_wmask_in[155]
  PIN rw0_wmask_in[156]
    DIRECTION INPUT ;
    USE SIGNAL ;
    SHAPE ABUTMENT ;
    PORT
      LAYER met3 ;
      RECT 1430.620 22.970 1431.520 23.270 ;
    END
  END rw0_wmask_in[156]
  PIN rw0_wmask_in[157]
    DIRECTION INPUT ;
    USE SIGNAL ;
    SHAPE ABUTMENT ;
    PORT
      LAYER met3 ;
      RECT 1430.620 23.650 1431.520 23.950 ;
    END
  END rw0_wmask_in[157]
  PIN rw0_wmask_in[158]
    DIRECTION INPUT ;
    USE SIGNAL ;
    SHAPE ABUTMENT ;
    PORT
      LAYER met3 ;
      RECT 1430.620 24.330 1431.520 24.630 ;
    END
  END rw0_wmask_in[158]
  PIN rw0_wmask_in[159]
    DIRECTION INPUT ;
    USE SIGNAL ;
    SHAPE ABUTMENT ;
    PORT
      LAYER met3 ;
      RECT 1430.620 25.010 1431.520 25.310 ;
    END
  END rw0_wmask_in[159]
  PIN rw0_wmask_in[160]
    DIRECTION INPUT ;
    USE SIGNAL ;
    SHAPE ABUTMENT ;
    PORT
      LAYER met3 ;
      RECT 1430.620 25.690 1431.520 25.990 ;
    END
  END rw0_wmask_in[160]
  PIN rw0_wmask_in[161]
    DIRECTION INPUT ;
    USE SIGNAL ;
    SHAPE ABUTMENT ;
    PORT
      LAYER met3 ;
      RECT 1430.620 26.370 1431.520 26.670 ;
    END
  END rw0_wmask_in[161]
  PIN rw0_wmask_in[162]
    DIRECTION INPUT ;
    USE SIGNAL ;
    SHAPE ABUTMENT ;
    PORT
      LAYER met3 ;
      RECT 1430.620 27.050 1431.520 27.350 ;
    END
  END rw0_wmask_in[162]
  PIN rw0_wmask_in[163]
    DIRECTION INPUT ;
    USE SIGNAL ;
    SHAPE ABUTMENT ;
    PORT
      LAYER met3 ;
      RECT 1430.620 27.730 1431.520 28.030 ;
    END
  END rw0_wmask_in[163]
  PIN rw0_wmask_in[164]
    DIRECTION INPUT ;
    USE SIGNAL ;
    SHAPE ABUTMENT ;
    PORT
      LAYER met3 ;
      RECT 1430.620 28.410 1431.520 28.710 ;
    END
  END rw0_wmask_in[164]
  PIN rw0_wmask_in[165]
    DIRECTION INPUT ;
    USE SIGNAL ;
    SHAPE ABUTMENT ;
    PORT
      LAYER met3 ;
      RECT 1430.620 29.090 1431.520 29.390 ;
    END
  END rw0_wmask_in[165]
  PIN rw0_wmask_in[166]
    DIRECTION INPUT ;
    USE SIGNAL ;
    SHAPE ABUTMENT ;
    PORT
      LAYER met3 ;
      RECT 1430.620 29.770 1431.520 30.070 ;
    END
  END rw0_wmask_in[166]
  PIN rw0_wmask_in[167]
    DIRECTION INPUT ;
    USE SIGNAL ;
    SHAPE ABUTMENT ;
    PORT
      LAYER met3 ;
      RECT 1430.620 30.450 1431.520 30.750 ;
    END
  END rw0_wmask_in[167]
  PIN rw0_wmask_in[168]
    DIRECTION INPUT ;
    USE SIGNAL ;
    SHAPE ABUTMENT ;
    PORT
      LAYER met3 ;
      RECT 1430.620 31.130 1431.520 31.430 ;
    END
  END rw0_wmask_in[168]
  PIN rw0_wmask_in[169]
    DIRECTION INPUT ;
    USE SIGNAL ;
    SHAPE ABUTMENT ;
    PORT
      LAYER met3 ;
      RECT 1430.620 31.810 1431.520 32.110 ;
    END
  END rw0_wmask_in[169]
  PIN rw0_wmask_in[170]
    DIRECTION INPUT ;
    USE SIGNAL ;
    SHAPE ABUTMENT ;
    PORT
      LAYER met3 ;
      RECT 1430.620 32.490 1431.520 32.790 ;
    END
  END rw0_wmask_in[170]
  PIN rw0_wmask_in[171]
    DIRECTION INPUT ;
    USE SIGNAL ;
    SHAPE ABUTMENT ;
    PORT
      LAYER met3 ;
      RECT 1430.620 33.170 1431.520 33.470 ;
    END
  END rw0_wmask_in[171]
  PIN rw0_wmask_in[172]
    DIRECTION INPUT ;
    USE SIGNAL ;
    SHAPE ABUTMENT ;
    PORT
      LAYER met3 ;
      RECT 1430.620 33.850 1431.520 34.150 ;
    END
  END rw0_wmask_in[172]
  PIN rw0_wmask_in[173]
    DIRECTION INPUT ;
    USE SIGNAL ;
    SHAPE ABUTMENT ;
    PORT
      LAYER met3 ;
      RECT 1430.620 34.530 1431.520 34.830 ;
    END
  END rw0_wmask_in[173]
  PIN rw0_wmask_in[174]
    DIRECTION INPUT ;
    USE SIGNAL ;
    SHAPE ABUTMENT ;
    PORT
      LAYER met3 ;
      RECT 1430.620 35.210 1431.520 35.510 ;
    END
  END rw0_wmask_in[174]
  PIN rw0_wmask_in[175]
    DIRECTION INPUT ;
    USE SIGNAL ;
    SHAPE ABUTMENT ;
    PORT
      LAYER met3 ;
      RECT 1430.620 35.890 1431.520 36.190 ;
    END
  END rw0_wmask_in[175]
  PIN rw0_wmask_in[176]
    DIRECTION INPUT ;
    USE SIGNAL ;
    SHAPE ABUTMENT ;
    PORT
      LAYER met3 ;
      RECT 1430.620 36.570 1431.520 36.870 ;
    END
  END rw0_wmask_in[176]
  PIN rw0_wmask_in[177]
    DIRECTION INPUT ;
    USE SIGNAL ;
    SHAPE ABUTMENT ;
    PORT
      LAYER met3 ;
      RECT 1430.620 37.250 1431.520 37.550 ;
    END
  END rw0_wmask_in[177]
  PIN rw0_wmask_in[178]
    DIRECTION INPUT ;
    USE SIGNAL ;
    SHAPE ABUTMENT ;
    PORT
      LAYER met3 ;
      RECT 1430.620 37.930 1431.520 38.230 ;
    END
  END rw0_wmask_in[178]
  PIN rw0_wmask_in[179]
    DIRECTION INPUT ;
    USE SIGNAL ;
    SHAPE ABUTMENT ;
    PORT
      LAYER met3 ;
      RECT 1430.620 38.610 1431.520 38.910 ;
    END
  END rw0_wmask_in[179]
  PIN rw0_wmask_in[180]
    DIRECTION INPUT ;
    USE SIGNAL ;
    SHAPE ABUTMENT ;
    PORT
      LAYER met3 ;
      RECT 1430.620 39.290 1431.520 39.590 ;
    END
  END rw0_wmask_in[180]
  PIN rw0_wmask_in[181]
    DIRECTION INPUT ;
    USE SIGNAL ;
    SHAPE ABUTMENT ;
    PORT
      LAYER met3 ;
      RECT 1430.620 39.970 1431.520 40.270 ;
    END
  END rw0_wmask_in[181]
  PIN rw0_wmask_in[182]
    DIRECTION INPUT ;
    USE SIGNAL ;
    SHAPE ABUTMENT ;
    PORT
      LAYER met3 ;
      RECT 1430.620 40.650 1431.520 40.950 ;
    END
  END rw0_wmask_in[182]
  PIN rw0_wmask_in[183]
    DIRECTION INPUT ;
    USE SIGNAL ;
    SHAPE ABUTMENT ;
    PORT
      LAYER met3 ;
      RECT 1430.620 41.330 1431.520 41.630 ;
    END
  END rw0_wmask_in[183]
  PIN rw0_wmask_in[184]
    DIRECTION INPUT ;
    USE SIGNAL ;
    SHAPE ABUTMENT ;
    PORT
      LAYER met3 ;
      RECT 1430.620 42.010 1431.520 42.310 ;
    END
  END rw0_wmask_in[184]
  PIN rw0_wmask_in[185]
    DIRECTION INPUT ;
    USE SIGNAL ;
    SHAPE ABUTMENT ;
    PORT
      LAYER met3 ;
      RECT 1430.620 42.690 1431.520 42.990 ;
    END
  END rw0_wmask_in[185]
  PIN rw0_wmask_in[186]
    DIRECTION INPUT ;
    USE SIGNAL ;
    SHAPE ABUTMENT ;
    PORT
      LAYER met3 ;
      RECT 1430.620 43.370 1431.520 43.670 ;
    END
  END rw0_wmask_in[186]
  PIN rw0_wmask_in[187]
    DIRECTION INPUT ;
    USE SIGNAL ;
    SHAPE ABUTMENT ;
    PORT
      LAYER met3 ;
      RECT 1430.620 44.050 1431.520 44.350 ;
    END
  END rw0_wmask_in[187]
  PIN rw0_wmask_in[188]
    DIRECTION INPUT ;
    USE SIGNAL ;
    SHAPE ABUTMENT ;
    PORT
      LAYER met3 ;
      RECT 1430.620 44.730 1431.520 45.030 ;
    END
  END rw0_wmask_in[188]
  PIN rw0_wmask_in[189]
    DIRECTION INPUT ;
    USE SIGNAL ;
    SHAPE ABUTMENT ;
    PORT
      LAYER met3 ;
      RECT 1430.620 45.410 1431.520 45.710 ;
    END
  END rw0_wmask_in[189]
  PIN rw0_wmask_in[190]
    DIRECTION INPUT ;
    USE SIGNAL ;
    SHAPE ABUTMENT ;
    PORT
      LAYER met3 ;
      RECT 1430.620 46.090 1431.520 46.390 ;
    END
  END rw0_wmask_in[190]
  PIN rw0_wmask_in[191]
    DIRECTION INPUT ;
    USE SIGNAL ;
    SHAPE ABUTMENT ;
    PORT
      LAYER met3 ;
      RECT 1430.620 46.770 1431.520 47.070 ;
    END
  END rw0_wmask_in[191]
  PIN rw0_wmask_in[192]
    DIRECTION INPUT ;
    USE SIGNAL ;
    SHAPE ABUTMENT ;
    PORT
      LAYER met3 ;
      RECT 1430.620 47.450 1431.520 47.750 ;
    END
  END rw0_wmask_in[192]
  PIN rw0_wmask_in[193]
    DIRECTION INPUT ;
    USE SIGNAL ;
    SHAPE ABUTMENT ;
    PORT
      LAYER met3 ;
      RECT 1430.620 48.130 1431.520 48.430 ;
    END
  END rw0_wmask_in[193]
  PIN rw0_wmask_in[194]
    DIRECTION INPUT ;
    USE SIGNAL ;
    SHAPE ABUTMENT ;
    PORT
      LAYER met3 ;
      RECT 1430.620 48.810 1431.520 49.110 ;
    END
  END rw0_wmask_in[194]
  PIN rw0_wmask_in[195]
    DIRECTION INPUT ;
    USE SIGNAL ;
    SHAPE ABUTMENT ;
    PORT
      LAYER met3 ;
      RECT 1430.620 49.490 1431.520 49.790 ;
    END
  END rw0_wmask_in[195]
  PIN rw0_wmask_in[196]
    DIRECTION INPUT ;
    USE SIGNAL ;
    SHAPE ABUTMENT ;
    PORT
      LAYER met3 ;
      RECT 1430.620 50.170 1431.520 50.470 ;
    END
  END rw0_wmask_in[196]
  PIN rw0_wmask_in[197]
    DIRECTION INPUT ;
    USE SIGNAL ;
    SHAPE ABUTMENT ;
    PORT
      LAYER met3 ;
      RECT 1430.620 50.850 1431.520 51.150 ;
    END
  END rw0_wmask_in[197]
  PIN rw0_wmask_in[198]
    DIRECTION INPUT ;
    USE SIGNAL ;
    SHAPE ABUTMENT ;
    PORT
      LAYER met3 ;
      RECT 1430.620 51.530 1431.520 51.830 ;
    END
  END rw0_wmask_in[198]
  PIN rw0_wmask_in[199]
    DIRECTION INPUT ;
    USE SIGNAL ;
    SHAPE ABUTMENT ;
    PORT
      LAYER met3 ;
      RECT 1430.620 52.210 1431.520 52.510 ;
    END
  END rw0_wmask_in[199]
  PIN rw0_wmask_in[200]
    DIRECTION INPUT ;
    USE SIGNAL ;
    SHAPE ABUTMENT ;
    PORT
      LAYER met3 ;
      RECT 1430.620 52.890 1431.520 53.190 ;
    END
  END rw0_wmask_in[200]
  PIN rw0_wmask_in[201]
    DIRECTION INPUT ;
    USE SIGNAL ;
    SHAPE ABUTMENT ;
    PORT
      LAYER met3 ;
      RECT 1430.620 53.570 1431.520 53.870 ;
    END
  END rw0_wmask_in[201]
  PIN rw0_wmask_in[202]
    DIRECTION INPUT ;
    USE SIGNAL ;
    SHAPE ABUTMENT ;
    PORT
      LAYER met3 ;
      RECT 1430.620 54.250 1431.520 54.550 ;
    END
  END rw0_wmask_in[202]
  PIN rw0_wmask_in[203]
    DIRECTION INPUT ;
    USE SIGNAL ;
    SHAPE ABUTMENT ;
    PORT
      LAYER met3 ;
      RECT 1430.620 54.930 1431.520 55.230 ;
    END
  END rw0_wmask_in[203]
  PIN rw0_wmask_in[204]
    DIRECTION INPUT ;
    USE SIGNAL ;
    SHAPE ABUTMENT ;
    PORT
      LAYER met3 ;
      RECT 1430.620 55.610 1431.520 55.910 ;
    END
  END rw0_wmask_in[204]
  PIN rw0_wmask_in[205]
    DIRECTION INPUT ;
    USE SIGNAL ;
    SHAPE ABUTMENT ;
    PORT
      LAYER met3 ;
      RECT 1430.620 56.290 1431.520 56.590 ;
    END
  END rw0_wmask_in[205]
  PIN rw0_wmask_in[206]
    DIRECTION INPUT ;
    USE SIGNAL ;
    SHAPE ABUTMENT ;
    PORT
      LAYER met3 ;
      RECT 1430.620 56.970 1431.520 57.270 ;
    END
  END rw0_wmask_in[206]
  PIN rw0_wmask_in[207]
    DIRECTION INPUT ;
    USE SIGNAL ;
    SHAPE ABUTMENT ;
    PORT
      LAYER met3 ;
      RECT 1430.620 57.650 1431.520 57.950 ;
    END
  END rw0_wmask_in[207]
  PIN rw0_wmask_in[208]
    DIRECTION INPUT ;
    USE SIGNAL ;
    SHAPE ABUTMENT ;
    PORT
      LAYER met3 ;
      RECT 1430.620 58.330 1431.520 58.630 ;
    END
  END rw0_wmask_in[208]
  PIN rw0_wmask_in[209]
    DIRECTION INPUT ;
    USE SIGNAL ;
    SHAPE ABUTMENT ;
    PORT
      LAYER met3 ;
      RECT 1430.620 59.010 1431.520 59.310 ;
    END
  END rw0_wmask_in[209]
  PIN rw0_wmask_in[210]
    DIRECTION INPUT ;
    USE SIGNAL ;
    SHAPE ABUTMENT ;
    PORT
      LAYER met3 ;
      RECT 1430.620 59.690 1431.520 59.990 ;
    END
  END rw0_wmask_in[210]
  PIN rw0_wmask_in[211]
    DIRECTION INPUT ;
    USE SIGNAL ;
    SHAPE ABUTMENT ;
    PORT
      LAYER met3 ;
      RECT 1430.620 60.370 1431.520 60.670 ;
    END
  END rw0_wmask_in[211]
  PIN rw0_wmask_in[212]
    DIRECTION INPUT ;
    USE SIGNAL ;
    SHAPE ABUTMENT ;
    PORT
      LAYER met3 ;
      RECT 1430.620 61.050 1431.520 61.350 ;
    END
  END rw0_wmask_in[212]
  PIN rw0_wmask_in[213]
    DIRECTION INPUT ;
    USE SIGNAL ;
    SHAPE ABUTMENT ;
    PORT
      LAYER met3 ;
      RECT 1430.620 61.730 1431.520 62.030 ;
    END
  END rw0_wmask_in[213]
  PIN rw0_wmask_in[214]
    DIRECTION INPUT ;
    USE SIGNAL ;
    SHAPE ABUTMENT ;
    PORT
      LAYER met3 ;
      RECT 1430.620 62.410 1431.520 62.710 ;
    END
  END rw0_wmask_in[214]
  PIN rw0_wmask_in[215]
    DIRECTION INPUT ;
    USE SIGNAL ;
    SHAPE ABUTMENT ;
    PORT
      LAYER met3 ;
      RECT 1430.620 63.090 1431.520 63.390 ;
    END
  END rw0_wmask_in[215]
  PIN rw0_wmask_in[216]
    DIRECTION INPUT ;
    USE SIGNAL ;
    SHAPE ABUTMENT ;
    PORT
      LAYER met3 ;
      RECT 1430.620 63.770 1431.520 64.070 ;
    END
  END rw0_wmask_in[216]
  PIN rw0_wmask_in[217]
    DIRECTION INPUT ;
    USE SIGNAL ;
    SHAPE ABUTMENT ;
    PORT
      LAYER met3 ;
      RECT 1430.620 64.450 1431.520 64.750 ;
    END
  END rw0_wmask_in[217]
  PIN rw0_wmask_in[218]
    DIRECTION INPUT ;
    USE SIGNAL ;
    SHAPE ABUTMENT ;
    PORT
      LAYER met3 ;
      RECT 1430.620 65.130 1431.520 65.430 ;
    END
  END rw0_wmask_in[218]
  PIN rw0_wmask_in[219]
    DIRECTION INPUT ;
    USE SIGNAL ;
    SHAPE ABUTMENT ;
    PORT
      LAYER met3 ;
      RECT 1430.620 65.810 1431.520 66.110 ;
    END
  END rw0_wmask_in[219]
  PIN rw0_wmask_in[220]
    DIRECTION INPUT ;
    USE SIGNAL ;
    SHAPE ABUTMENT ;
    PORT
      LAYER met3 ;
      RECT 1430.620 66.490 1431.520 66.790 ;
    END
  END rw0_wmask_in[220]
  PIN rw0_wmask_in[221]
    DIRECTION INPUT ;
    USE SIGNAL ;
    SHAPE ABUTMENT ;
    PORT
      LAYER met3 ;
      RECT 1430.620 67.170 1431.520 67.470 ;
    END
  END rw0_wmask_in[221]
  PIN rw0_wmask_in[222]
    DIRECTION INPUT ;
    USE SIGNAL ;
    SHAPE ABUTMENT ;
    PORT
      LAYER met3 ;
      RECT 1430.620 67.850 1431.520 68.150 ;
    END
  END rw0_wmask_in[222]
  PIN rw0_wmask_in[223]
    DIRECTION INPUT ;
    USE SIGNAL ;
    SHAPE ABUTMENT ;
    PORT
      LAYER met3 ;
      RECT 1430.620 68.530 1431.520 68.830 ;
    END
  END rw0_wmask_in[223]
  PIN rw0_wmask_in[224]
    DIRECTION INPUT ;
    USE SIGNAL ;
    SHAPE ABUTMENT ;
    PORT
      LAYER met3 ;
      RECT 1430.620 69.210 1431.520 69.510 ;
    END
  END rw0_wmask_in[224]
  PIN rw0_wmask_in[225]
    DIRECTION INPUT ;
    USE SIGNAL ;
    SHAPE ABUTMENT ;
    PORT
      LAYER met3 ;
      RECT 1430.620 69.890 1431.520 70.190 ;
    END
  END rw0_wmask_in[225]
  PIN rw0_wmask_in[226]
    DIRECTION INPUT ;
    USE SIGNAL ;
    SHAPE ABUTMENT ;
    PORT
      LAYER met3 ;
      RECT 1430.620 70.570 1431.520 70.870 ;
    END
  END rw0_wmask_in[226]
  PIN rw0_wmask_in[227]
    DIRECTION INPUT ;
    USE SIGNAL ;
    SHAPE ABUTMENT ;
    PORT
      LAYER met3 ;
      RECT 1430.620 71.250 1431.520 71.550 ;
    END
  END rw0_wmask_in[227]
  PIN rw0_wmask_in[228]
    DIRECTION INPUT ;
    USE SIGNAL ;
    SHAPE ABUTMENT ;
    PORT
      LAYER met3 ;
      RECT 1430.620 71.930 1431.520 72.230 ;
    END
  END rw0_wmask_in[228]
  PIN rw0_wmask_in[229]
    DIRECTION INPUT ;
    USE SIGNAL ;
    SHAPE ABUTMENT ;
    PORT
      LAYER met3 ;
      RECT 1430.620 72.610 1431.520 72.910 ;
    END
  END rw0_wmask_in[229]
  PIN rw0_wmask_in[230]
    DIRECTION INPUT ;
    USE SIGNAL ;
    SHAPE ABUTMENT ;
    PORT
      LAYER met3 ;
      RECT 1430.620 73.290 1431.520 73.590 ;
    END
  END rw0_wmask_in[230]
  PIN rw0_wmask_in[231]
    DIRECTION INPUT ;
    USE SIGNAL ;
    SHAPE ABUTMENT ;
    PORT
      LAYER met3 ;
      RECT 1430.620 73.970 1431.520 74.270 ;
    END
  END rw0_wmask_in[231]
  PIN rw0_wmask_in[232]
    DIRECTION INPUT ;
    USE SIGNAL ;
    SHAPE ABUTMENT ;
    PORT
      LAYER met3 ;
      RECT 1430.620 74.650 1431.520 74.950 ;
    END
  END rw0_wmask_in[232]
  PIN rw0_wmask_in[233]
    DIRECTION INPUT ;
    USE SIGNAL ;
    SHAPE ABUTMENT ;
    PORT
      LAYER met3 ;
      RECT 1430.620 75.330 1431.520 75.630 ;
    END
  END rw0_wmask_in[233]
  PIN rw0_wmask_in[234]
    DIRECTION INPUT ;
    USE SIGNAL ;
    SHAPE ABUTMENT ;
    PORT
      LAYER met3 ;
      RECT 1430.620 76.010 1431.520 76.310 ;
    END
  END rw0_wmask_in[234]
  PIN rw0_wmask_in[235]
    DIRECTION INPUT ;
    USE SIGNAL ;
    SHAPE ABUTMENT ;
    PORT
      LAYER met3 ;
      RECT 1430.620 76.690 1431.520 76.990 ;
    END
  END rw0_wmask_in[235]
  PIN rw0_wmask_in[236]
    DIRECTION INPUT ;
    USE SIGNAL ;
    SHAPE ABUTMENT ;
    PORT
      LAYER met3 ;
      RECT 1430.620 77.370 1431.520 77.670 ;
    END
  END rw0_wmask_in[236]
  PIN rw0_wmask_in[237]
    DIRECTION INPUT ;
    USE SIGNAL ;
    SHAPE ABUTMENT ;
    PORT
      LAYER met3 ;
      RECT 1430.620 78.050 1431.520 78.350 ;
    END
  END rw0_wmask_in[237]
  PIN rw0_wmask_in[238]
    DIRECTION INPUT ;
    USE SIGNAL ;
    SHAPE ABUTMENT ;
    PORT
      LAYER met3 ;
      RECT 1430.620 78.730 1431.520 79.030 ;
    END
  END rw0_wmask_in[238]
  PIN rw0_wmask_in[239]
    DIRECTION INPUT ;
    USE SIGNAL ;
    SHAPE ABUTMENT ;
    PORT
      LAYER met3 ;
      RECT 1430.620 79.410 1431.520 79.710 ;
    END
  END rw0_wmask_in[239]
  PIN rw0_wmask_in[240]
    DIRECTION INPUT ;
    USE SIGNAL ;
    SHAPE ABUTMENT ;
    PORT
      LAYER met3 ;
      RECT 1430.620 80.090 1431.520 80.390 ;
    END
  END rw0_wmask_in[240]
  PIN rw0_wmask_in[241]
    DIRECTION INPUT ;
    USE SIGNAL ;
    SHAPE ABUTMENT ;
    PORT
      LAYER met3 ;
      RECT 1430.620 80.770 1431.520 81.070 ;
    END
  END rw0_wmask_in[241]
  PIN rw0_wmask_in[242]
    DIRECTION INPUT ;
    USE SIGNAL ;
    SHAPE ABUTMENT ;
    PORT
      LAYER met3 ;
      RECT 1430.620 81.450 1431.520 81.750 ;
    END
  END rw0_wmask_in[242]
  PIN rw0_wmask_in[243]
    DIRECTION INPUT ;
    USE SIGNAL ;
    SHAPE ABUTMENT ;
    PORT
      LAYER met3 ;
      RECT 1430.620 82.130 1431.520 82.430 ;
    END
  END rw0_wmask_in[243]
  PIN rw0_wmask_in[244]
    DIRECTION INPUT ;
    USE SIGNAL ;
    SHAPE ABUTMENT ;
    PORT
      LAYER met3 ;
      RECT 1430.620 82.810 1431.520 83.110 ;
    END
  END rw0_wmask_in[244]
  PIN rw0_wmask_in[245]
    DIRECTION INPUT ;
    USE SIGNAL ;
    SHAPE ABUTMENT ;
    PORT
      LAYER met3 ;
      RECT 1430.620 83.490 1431.520 83.790 ;
    END
  END rw0_wmask_in[245]
  PIN rw0_wmask_in[246]
    DIRECTION INPUT ;
    USE SIGNAL ;
    SHAPE ABUTMENT ;
    PORT
      LAYER met3 ;
      RECT 1430.620 84.170 1431.520 84.470 ;
    END
  END rw0_wmask_in[246]
  PIN rw0_wmask_in[247]
    DIRECTION INPUT ;
    USE SIGNAL ;
    SHAPE ABUTMENT ;
    PORT
      LAYER met3 ;
      RECT 1430.620 84.850 1431.520 85.150 ;
    END
  END rw0_wmask_in[247]
  PIN rw0_wmask_in[248]
    DIRECTION INPUT ;
    USE SIGNAL ;
    SHAPE ABUTMENT ;
    PORT
      LAYER met3 ;
      RECT 1430.620 85.530 1431.520 85.830 ;
    END
  END rw0_wmask_in[248]
  PIN rw0_wmask_in[249]
    DIRECTION INPUT ;
    USE SIGNAL ;
    SHAPE ABUTMENT ;
    PORT
      LAYER met3 ;
      RECT 1430.620 86.210 1431.520 86.510 ;
    END
  END rw0_wmask_in[249]
  PIN rw0_wmask_in[250]
    DIRECTION INPUT ;
    USE SIGNAL ;
    SHAPE ABUTMENT ;
    PORT
      LAYER met3 ;
      RECT 1430.620 86.890 1431.520 87.190 ;
    END
  END rw0_wmask_in[250]
  PIN rw0_wmask_in[251]
    DIRECTION INPUT ;
    USE SIGNAL ;
    SHAPE ABUTMENT ;
    PORT
      LAYER met3 ;
      RECT 1430.620 87.570 1431.520 87.870 ;
    END
  END rw0_wmask_in[251]
  PIN rw0_wmask_in[252]
    DIRECTION INPUT ;
    USE SIGNAL ;
    SHAPE ABUTMENT ;
    PORT
      LAYER met3 ;
      RECT 1430.620 88.250 1431.520 88.550 ;
    END
  END rw0_wmask_in[252]
  PIN rw0_wmask_in[253]
    DIRECTION INPUT ;
    USE SIGNAL ;
    SHAPE ABUTMENT ;
    PORT
      LAYER met3 ;
      RECT 1430.620 88.930 1431.520 89.230 ;
    END
  END rw0_wmask_in[253]
  PIN rw0_wmask_in[254]
    DIRECTION INPUT ;
    USE SIGNAL ;
    SHAPE ABUTMENT ;
    PORT
      LAYER met3 ;
      RECT 1430.620 89.610 1431.520 89.910 ;
    END
  END rw0_wmask_in[254]
  PIN rw0_wmask_in[255]
    DIRECTION INPUT ;
    USE SIGNAL ;
    SHAPE ABUTMENT ;
    PORT
      LAYER met3 ;
      RECT 1430.620 90.290 1431.520 90.590 ;
    END
  END rw0_wmask_in[255]
  PIN rw0_wmask_in[256]
    DIRECTION INPUT ;
    USE SIGNAL ;
    SHAPE ABUTMENT ;
    PORT
      LAYER met2 ;
      RECT 2.690 290.620 2.830 291.040 ;
    END
  END rw0_wmask_in[256]
  PIN rw0_wmask_in[257]
    DIRECTION INPUT ;
    USE SIGNAL ;
    SHAPE ABUTMENT ;
    PORT
      LAYER met2 ;
      RECT 5.450 290.620 5.590 291.040 ;
    END
  END rw0_wmask_in[257]
  PIN rw0_wmask_in[258]
    DIRECTION INPUT ;
    USE SIGNAL ;
    SHAPE ABUTMENT ;
    PORT
      LAYER met2 ;
      RECT 8.210 290.620 8.350 291.040 ;
    END
  END rw0_wmask_in[258]
  PIN rw0_wmask_in[259]
    DIRECTION INPUT ;
    USE SIGNAL ;
    SHAPE ABUTMENT ;
    PORT
      LAYER met2 ;
      RECT 10.970 290.620 11.110 291.040 ;
    END
  END rw0_wmask_in[259]
  PIN rw0_wmask_in[260]
    DIRECTION INPUT ;
    USE SIGNAL ;
    SHAPE ABUTMENT ;
    PORT
      LAYER met2 ;
      RECT 13.730 290.620 13.870 291.040 ;
    END
  END rw0_wmask_in[260]
  PIN rw0_wmask_in[261]
    DIRECTION INPUT ;
    USE SIGNAL ;
    SHAPE ABUTMENT ;
    PORT
      LAYER met2 ;
      RECT 16.490 290.620 16.630 291.040 ;
    END
  END rw0_wmask_in[261]
  PIN rw0_wmask_in[262]
    DIRECTION INPUT ;
    USE SIGNAL ;
    SHAPE ABUTMENT ;
    PORT
      LAYER met2 ;
      RECT 19.250 290.620 19.390 291.040 ;
    END
  END rw0_wmask_in[262]
  PIN rw0_wmask_in[263]
    DIRECTION INPUT ;
    USE SIGNAL ;
    SHAPE ABUTMENT ;
    PORT
      LAYER met2 ;
      RECT 22.010 290.620 22.150 291.040 ;
    END
  END rw0_wmask_in[263]
  PIN rw0_wmask_in[264]
    DIRECTION INPUT ;
    USE SIGNAL ;
    SHAPE ABUTMENT ;
    PORT
      LAYER met2 ;
      RECT 24.770 290.620 24.910 291.040 ;
    END
  END rw0_wmask_in[264]
  PIN rw0_wmask_in[265]
    DIRECTION INPUT ;
    USE SIGNAL ;
    SHAPE ABUTMENT ;
    PORT
      LAYER met2 ;
      RECT 27.530 290.620 27.670 291.040 ;
    END
  END rw0_wmask_in[265]
  PIN rw0_wmask_in[266]
    DIRECTION INPUT ;
    USE SIGNAL ;
    SHAPE ABUTMENT ;
    PORT
      LAYER met2 ;
      RECT 30.290 290.620 30.430 291.040 ;
    END
  END rw0_wmask_in[266]
  PIN rw0_wmask_in[267]
    DIRECTION INPUT ;
    USE SIGNAL ;
    SHAPE ABUTMENT ;
    PORT
      LAYER met2 ;
      RECT 33.050 290.620 33.190 291.040 ;
    END
  END rw0_wmask_in[267]
  PIN rw0_wmask_in[268]
    DIRECTION INPUT ;
    USE SIGNAL ;
    SHAPE ABUTMENT ;
    PORT
      LAYER met2 ;
      RECT 35.810 290.620 35.950 291.040 ;
    END
  END rw0_wmask_in[268]
  PIN rw0_wmask_in[269]
    DIRECTION INPUT ;
    USE SIGNAL ;
    SHAPE ABUTMENT ;
    PORT
      LAYER met2 ;
      RECT 38.570 290.620 38.710 291.040 ;
    END
  END rw0_wmask_in[269]
  PIN rw0_wmask_in[270]
    DIRECTION INPUT ;
    USE SIGNAL ;
    SHAPE ABUTMENT ;
    PORT
      LAYER met2 ;
      RECT 41.330 290.620 41.470 291.040 ;
    END
  END rw0_wmask_in[270]
  PIN rw0_wmask_in[271]
    DIRECTION INPUT ;
    USE SIGNAL ;
    SHAPE ABUTMENT ;
    PORT
      LAYER met2 ;
      RECT 44.090 290.620 44.230 291.040 ;
    END
  END rw0_wmask_in[271]
  PIN rw0_wmask_in[272]
    DIRECTION INPUT ;
    USE SIGNAL ;
    SHAPE ABUTMENT ;
    PORT
      LAYER met2 ;
      RECT 46.850 290.620 46.990 291.040 ;
    END
  END rw0_wmask_in[272]
  PIN rw0_wmask_in[273]
    DIRECTION INPUT ;
    USE SIGNAL ;
    SHAPE ABUTMENT ;
    PORT
      LAYER met2 ;
      RECT 49.610 290.620 49.750 291.040 ;
    END
  END rw0_wmask_in[273]
  PIN rw0_wmask_in[274]
    DIRECTION INPUT ;
    USE SIGNAL ;
    SHAPE ABUTMENT ;
    PORT
      LAYER met2 ;
      RECT 52.370 290.620 52.510 291.040 ;
    END
  END rw0_wmask_in[274]
  PIN rw0_wmask_in[275]
    DIRECTION INPUT ;
    USE SIGNAL ;
    SHAPE ABUTMENT ;
    PORT
      LAYER met2 ;
      RECT 55.130 290.620 55.270 291.040 ;
    END
  END rw0_wmask_in[275]
  PIN rw0_wmask_in[276]
    DIRECTION INPUT ;
    USE SIGNAL ;
    SHAPE ABUTMENT ;
    PORT
      LAYER met2 ;
      RECT 57.890 290.620 58.030 291.040 ;
    END
  END rw0_wmask_in[276]
  PIN rw0_wmask_in[277]
    DIRECTION INPUT ;
    USE SIGNAL ;
    SHAPE ABUTMENT ;
    PORT
      LAYER met2 ;
      RECT 60.650 290.620 60.790 291.040 ;
    END
  END rw0_wmask_in[277]
  PIN rw0_wmask_in[278]
    DIRECTION INPUT ;
    USE SIGNAL ;
    SHAPE ABUTMENT ;
    PORT
      LAYER met2 ;
      RECT 63.410 290.620 63.550 291.040 ;
    END
  END rw0_wmask_in[278]
  PIN rw0_wmask_in[279]
    DIRECTION INPUT ;
    USE SIGNAL ;
    SHAPE ABUTMENT ;
    PORT
      LAYER met2 ;
      RECT 66.170 290.620 66.310 291.040 ;
    END
  END rw0_wmask_in[279]
  PIN rw0_wmask_in[280]
    DIRECTION INPUT ;
    USE SIGNAL ;
    SHAPE ABUTMENT ;
    PORT
      LAYER met2 ;
      RECT 68.930 290.620 69.070 291.040 ;
    END
  END rw0_wmask_in[280]
  PIN rw0_wmask_in[281]
    DIRECTION INPUT ;
    USE SIGNAL ;
    SHAPE ABUTMENT ;
    PORT
      LAYER met2 ;
      RECT 71.690 290.620 71.830 291.040 ;
    END
  END rw0_wmask_in[281]
  PIN rw0_wmask_in[282]
    DIRECTION INPUT ;
    USE SIGNAL ;
    SHAPE ABUTMENT ;
    PORT
      LAYER met2 ;
      RECT 74.450 290.620 74.590 291.040 ;
    END
  END rw0_wmask_in[282]
  PIN rw0_wmask_in[283]
    DIRECTION INPUT ;
    USE SIGNAL ;
    SHAPE ABUTMENT ;
    PORT
      LAYER met2 ;
      RECT 77.210 290.620 77.350 291.040 ;
    END
  END rw0_wmask_in[283]
  PIN rw0_wmask_in[284]
    DIRECTION INPUT ;
    USE SIGNAL ;
    SHAPE ABUTMENT ;
    PORT
      LAYER met2 ;
      RECT 79.970 290.620 80.110 291.040 ;
    END
  END rw0_wmask_in[284]
  PIN rw0_wmask_in[285]
    DIRECTION INPUT ;
    USE SIGNAL ;
    SHAPE ABUTMENT ;
    PORT
      LAYER met2 ;
      RECT 82.730 290.620 82.870 291.040 ;
    END
  END rw0_wmask_in[285]
  PIN rw0_wmask_in[286]
    DIRECTION INPUT ;
    USE SIGNAL ;
    SHAPE ABUTMENT ;
    PORT
      LAYER met2 ;
      RECT 85.490 290.620 85.630 291.040 ;
    END
  END rw0_wmask_in[286]
  PIN rw0_wmask_in[287]
    DIRECTION INPUT ;
    USE SIGNAL ;
    SHAPE ABUTMENT ;
    PORT
      LAYER met2 ;
      RECT 88.250 290.620 88.390 291.040 ;
    END
  END rw0_wmask_in[287]
  PIN rw0_wmask_in[288]
    DIRECTION INPUT ;
    USE SIGNAL ;
    SHAPE ABUTMENT ;
    PORT
      LAYER met2 ;
      RECT 91.010 290.620 91.150 291.040 ;
    END
  END rw0_wmask_in[288]
  PIN rw0_wmask_in[289]
    DIRECTION INPUT ;
    USE SIGNAL ;
    SHAPE ABUTMENT ;
    PORT
      LAYER met2 ;
      RECT 93.770 290.620 93.910 291.040 ;
    END
  END rw0_wmask_in[289]
  PIN rw0_wmask_in[290]
    DIRECTION INPUT ;
    USE SIGNAL ;
    SHAPE ABUTMENT ;
    PORT
      LAYER met2 ;
      RECT 96.530 290.620 96.670 291.040 ;
    END
  END rw0_wmask_in[290]
  PIN rw0_wmask_in[291]
    DIRECTION INPUT ;
    USE SIGNAL ;
    SHAPE ABUTMENT ;
    PORT
      LAYER met2 ;
      RECT 99.290 290.620 99.430 291.040 ;
    END
  END rw0_wmask_in[291]
  PIN rw0_wmask_in[292]
    DIRECTION INPUT ;
    USE SIGNAL ;
    SHAPE ABUTMENT ;
    PORT
      LAYER met2 ;
      RECT 102.050 290.620 102.190 291.040 ;
    END
  END rw0_wmask_in[292]
  PIN rw0_wmask_in[293]
    DIRECTION INPUT ;
    USE SIGNAL ;
    SHAPE ABUTMENT ;
    PORT
      LAYER met2 ;
      RECT 104.810 290.620 104.950 291.040 ;
    END
  END rw0_wmask_in[293]
  PIN rw0_wmask_in[294]
    DIRECTION INPUT ;
    USE SIGNAL ;
    SHAPE ABUTMENT ;
    PORT
      LAYER met2 ;
      RECT 107.570 290.620 107.710 291.040 ;
    END
  END rw0_wmask_in[294]
  PIN rw0_wmask_in[295]
    DIRECTION INPUT ;
    USE SIGNAL ;
    SHAPE ABUTMENT ;
    PORT
      LAYER met2 ;
      RECT 110.330 290.620 110.470 291.040 ;
    END
  END rw0_wmask_in[295]
  PIN rw0_wmask_in[296]
    DIRECTION INPUT ;
    USE SIGNAL ;
    SHAPE ABUTMENT ;
    PORT
      LAYER met2 ;
      RECT 113.090 290.620 113.230 291.040 ;
    END
  END rw0_wmask_in[296]
  PIN rw0_wmask_in[297]
    DIRECTION INPUT ;
    USE SIGNAL ;
    SHAPE ABUTMENT ;
    PORT
      LAYER met2 ;
      RECT 115.850 290.620 115.990 291.040 ;
    END
  END rw0_wmask_in[297]
  PIN rw0_wmask_in[298]
    DIRECTION INPUT ;
    USE SIGNAL ;
    SHAPE ABUTMENT ;
    PORT
      LAYER met2 ;
      RECT 118.610 290.620 118.750 291.040 ;
    END
  END rw0_wmask_in[298]
  PIN rw0_wmask_in[299]
    DIRECTION INPUT ;
    USE SIGNAL ;
    SHAPE ABUTMENT ;
    PORT
      LAYER met2 ;
      RECT 121.370 290.620 121.510 291.040 ;
    END
  END rw0_wmask_in[299]
  PIN rw0_wmask_in[300]
    DIRECTION INPUT ;
    USE SIGNAL ;
    SHAPE ABUTMENT ;
    PORT
      LAYER met2 ;
      RECT 124.130 290.620 124.270 291.040 ;
    END
  END rw0_wmask_in[300]
  PIN rw0_wmask_in[301]
    DIRECTION INPUT ;
    USE SIGNAL ;
    SHAPE ABUTMENT ;
    PORT
      LAYER met2 ;
      RECT 126.890 290.620 127.030 291.040 ;
    END
  END rw0_wmask_in[301]
  PIN rw0_wmask_in[302]
    DIRECTION INPUT ;
    USE SIGNAL ;
    SHAPE ABUTMENT ;
    PORT
      LAYER met2 ;
      RECT 129.650 290.620 129.790 291.040 ;
    END
  END rw0_wmask_in[302]
  PIN rw0_wmask_in[303]
    DIRECTION INPUT ;
    USE SIGNAL ;
    SHAPE ABUTMENT ;
    PORT
      LAYER met2 ;
      RECT 132.410 290.620 132.550 291.040 ;
    END
  END rw0_wmask_in[303]
  PIN rw0_wmask_in[304]
    DIRECTION INPUT ;
    USE SIGNAL ;
    SHAPE ABUTMENT ;
    PORT
      LAYER met2 ;
      RECT 135.170 290.620 135.310 291.040 ;
    END
  END rw0_wmask_in[304]
  PIN rw0_wmask_in[305]
    DIRECTION INPUT ;
    USE SIGNAL ;
    SHAPE ABUTMENT ;
    PORT
      LAYER met2 ;
      RECT 137.930 290.620 138.070 291.040 ;
    END
  END rw0_wmask_in[305]
  PIN rw0_wmask_in[306]
    DIRECTION INPUT ;
    USE SIGNAL ;
    SHAPE ABUTMENT ;
    PORT
      LAYER met2 ;
      RECT 140.690 290.620 140.830 291.040 ;
    END
  END rw0_wmask_in[306]
  PIN rw0_wmask_in[307]
    DIRECTION INPUT ;
    USE SIGNAL ;
    SHAPE ABUTMENT ;
    PORT
      LAYER met2 ;
      RECT 143.450 290.620 143.590 291.040 ;
    END
  END rw0_wmask_in[307]
  PIN rw0_wmask_in[308]
    DIRECTION INPUT ;
    USE SIGNAL ;
    SHAPE ABUTMENT ;
    PORT
      LAYER met2 ;
      RECT 146.210 290.620 146.350 291.040 ;
    END
  END rw0_wmask_in[308]
  PIN rw0_wmask_in[309]
    DIRECTION INPUT ;
    USE SIGNAL ;
    SHAPE ABUTMENT ;
    PORT
      LAYER met2 ;
      RECT 148.970 290.620 149.110 291.040 ;
    END
  END rw0_wmask_in[309]
  PIN rw0_wmask_in[310]
    DIRECTION INPUT ;
    USE SIGNAL ;
    SHAPE ABUTMENT ;
    PORT
      LAYER met2 ;
      RECT 151.730 290.620 151.870 291.040 ;
    END
  END rw0_wmask_in[310]
  PIN rw0_wmask_in[311]
    DIRECTION INPUT ;
    USE SIGNAL ;
    SHAPE ABUTMENT ;
    PORT
      LAYER met2 ;
      RECT 154.490 290.620 154.630 291.040 ;
    END
  END rw0_wmask_in[311]
  PIN rw0_wmask_in[312]
    DIRECTION INPUT ;
    USE SIGNAL ;
    SHAPE ABUTMENT ;
    PORT
      LAYER met2 ;
      RECT 157.250 290.620 157.390 291.040 ;
    END
  END rw0_wmask_in[312]
  PIN rw0_wmask_in[313]
    DIRECTION INPUT ;
    USE SIGNAL ;
    SHAPE ABUTMENT ;
    PORT
      LAYER met2 ;
      RECT 160.010 290.620 160.150 291.040 ;
    END
  END rw0_wmask_in[313]
  PIN rw0_wmask_in[314]
    DIRECTION INPUT ;
    USE SIGNAL ;
    SHAPE ABUTMENT ;
    PORT
      LAYER met2 ;
      RECT 162.770 290.620 162.910 291.040 ;
    END
  END rw0_wmask_in[314]
  PIN rw0_wmask_in[315]
    DIRECTION INPUT ;
    USE SIGNAL ;
    SHAPE ABUTMENT ;
    PORT
      LAYER met2 ;
      RECT 165.530 290.620 165.670 291.040 ;
    END
  END rw0_wmask_in[315]
  PIN rw0_wmask_in[316]
    DIRECTION INPUT ;
    USE SIGNAL ;
    SHAPE ABUTMENT ;
    PORT
      LAYER met2 ;
      RECT 168.290 290.620 168.430 291.040 ;
    END
  END rw0_wmask_in[316]
  PIN rw0_wmask_in[317]
    DIRECTION INPUT ;
    USE SIGNAL ;
    SHAPE ABUTMENT ;
    PORT
      LAYER met2 ;
      RECT 171.050 290.620 171.190 291.040 ;
    END
  END rw0_wmask_in[317]
  PIN rw0_wmask_in[318]
    DIRECTION INPUT ;
    USE SIGNAL ;
    SHAPE ABUTMENT ;
    PORT
      LAYER met2 ;
      RECT 173.810 290.620 173.950 291.040 ;
    END
  END rw0_wmask_in[318]
  PIN rw0_wmask_in[319]
    DIRECTION INPUT ;
    USE SIGNAL ;
    SHAPE ABUTMENT ;
    PORT
      LAYER met2 ;
      RECT 176.570 290.620 176.710 291.040 ;
    END
  END rw0_wmask_in[319]
  PIN rw0_wmask_in[320]
    DIRECTION INPUT ;
    USE SIGNAL ;
    SHAPE ABUTMENT ;
    PORT
      LAYER met2 ;
      RECT 179.330 290.620 179.470 291.040 ;
    END
  END rw0_wmask_in[320]
  PIN rw0_wmask_in[321]
    DIRECTION INPUT ;
    USE SIGNAL ;
    SHAPE ABUTMENT ;
    PORT
      LAYER met2 ;
      RECT 182.090 290.620 182.230 291.040 ;
    END
  END rw0_wmask_in[321]
  PIN rw0_wmask_in[322]
    DIRECTION INPUT ;
    USE SIGNAL ;
    SHAPE ABUTMENT ;
    PORT
      LAYER met2 ;
      RECT 184.850 290.620 184.990 291.040 ;
    END
  END rw0_wmask_in[322]
  PIN rw0_wmask_in[323]
    DIRECTION INPUT ;
    USE SIGNAL ;
    SHAPE ABUTMENT ;
    PORT
      LAYER met2 ;
      RECT 187.610 290.620 187.750 291.040 ;
    END
  END rw0_wmask_in[323]
  PIN rw0_wmask_in[324]
    DIRECTION INPUT ;
    USE SIGNAL ;
    SHAPE ABUTMENT ;
    PORT
      LAYER met2 ;
      RECT 190.370 290.620 190.510 291.040 ;
    END
  END rw0_wmask_in[324]
  PIN rw0_wmask_in[325]
    DIRECTION INPUT ;
    USE SIGNAL ;
    SHAPE ABUTMENT ;
    PORT
      LAYER met2 ;
      RECT 193.130 290.620 193.270 291.040 ;
    END
  END rw0_wmask_in[325]
  PIN rw0_wmask_in[326]
    DIRECTION INPUT ;
    USE SIGNAL ;
    SHAPE ABUTMENT ;
    PORT
      LAYER met2 ;
      RECT 195.890 290.620 196.030 291.040 ;
    END
  END rw0_wmask_in[326]
  PIN rw0_wmask_in[327]
    DIRECTION INPUT ;
    USE SIGNAL ;
    SHAPE ABUTMENT ;
    PORT
      LAYER met2 ;
      RECT 198.650 290.620 198.790 291.040 ;
    END
  END rw0_wmask_in[327]
  PIN rw0_wmask_in[328]
    DIRECTION INPUT ;
    USE SIGNAL ;
    SHAPE ABUTMENT ;
    PORT
      LAYER met2 ;
      RECT 201.410 290.620 201.550 291.040 ;
    END
  END rw0_wmask_in[328]
  PIN rw0_wmask_in[329]
    DIRECTION INPUT ;
    USE SIGNAL ;
    SHAPE ABUTMENT ;
    PORT
      LAYER met2 ;
      RECT 204.170 290.620 204.310 291.040 ;
    END
  END rw0_wmask_in[329]
  PIN rw0_wmask_in[330]
    DIRECTION INPUT ;
    USE SIGNAL ;
    SHAPE ABUTMENT ;
    PORT
      LAYER met2 ;
      RECT 206.930 290.620 207.070 291.040 ;
    END
  END rw0_wmask_in[330]
  PIN rw0_wmask_in[331]
    DIRECTION INPUT ;
    USE SIGNAL ;
    SHAPE ABUTMENT ;
    PORT
      LAYER met2 ;
      RECT 209.690 290.620 209.830 291.040 ;
    END
  END rw0_wmask_in[331]
  PIN rw0_wmask_in[332]
    DIRECTION INPUT ;
    USE SIGNAL ;
    SHAPE ABUTMENT ;
    PORT
      LAYER met2 ;
      RECT 212.450 290.620 212.590 291.040 ;
    END
  END rw0_wmask_in[332]
  PIN rw0_wmask_in[333]
    DIRECTION INPUT ;
    USE SIGNAL ;
    SHAPE ABUTMENT ;
    PORT
      LAYER met2 ;
      RECT 215.210 290.620 215.350 291.040 ;
    END
  END rw0_wmask_in[333]
  PIN rw0_wmask_in[334]
    DIRECTION INPUT ;
    USE SIGNAL ;
    SHAPE ABUTMENT ;
    PORT
      LAYER met2 ;
      RECT 217.970 290.620 218.110 291.040 ;
    END
  END rw0_wmask_in[334]
  PIN rw0_wmask_in[335]
    DIRECTION INPUT ;
    USE SIGNAL ;
    SHAPE ABUTMENT ;
    PORT
      LAYER met2 ;
      RECT 220.730 290.620 220.870 291.040 ;
    END
  END rw0_wmask_in[335]
  PIN rw0_wmask_in[336]
    DIRECTION INPUT ;
    USE SIGNAL ;
    SHAPE ABUTMENT ;
    PORT
      LAYER met2 ;
      RECT 223.490 290.620 223.630 291.040 ;
    END
  END rw0_wmask_in[336]
  PIN rw0_wmask_in[337]
    DIRECTION INPUT ;
    USE SIGNAL ;
    SHAPE ABUTMENT ;
    PORT
      LAYER met2 ;
      RECT 226.250 290.620 226.390 291.040 ;
    END
  END rw0_wmask_in[337]
  PIN rw0_wmask_in[338]
    DIRECTION INPUT ;
    USE SIGNAL ;
    SHAPE ABUTMENT ;
    PORT
      LAYER met2 ;
      RECT 229.010 290.620 229.150 291.040 ;
    END
  END rw0_wmask_in[338]
  PIN rw0_wmask_in[339]
    DIRECTION INPUT ;
    USE SIGNAL ;
    SHAPE ABUTMENT ;
    PORT
      LAYER met2 ;
      RECT 231.770 290.620 231.910 291.040 ;
    END
  END rw0_wmask_in[339]
  PIN rw0_wmask_in[340]
    DIRECTION INPUT ;
    USE SIGNAL ;
    SHAPE ABUTMENT ;
    PORT
      LAYER met2 ;
      RECT 234.530 290.620 234.670 291.040 ;
    END
  END rw0_wmask_in[340]
  PIN rw0_wmask_in[341]
    DIRECTION INPUT ;
    USE SIGNAL ;
    SHAPE ABUTMENT ;
    PORT
      LAYER met2 ;
      RECT 237.290 290.620 237.430 291.040 ;
    END
  END rw0_wmask_in[341]
  PIN rw0_wmask_in[342]
    DIRECTION INPUT ;
    USE SIGNAL ;
    SHAPE ABUTMENT ;
    PORT
      LAYER met2 ;
      RECT 240.050 290.620 240.190 291.040 ;
    END
  END rw0_wmask_in[342]
  PIN rw0_wmask_in[343]
    DIRECTION INPUT ;
    USE SIGNAL ;
    SHAPE ABUTMENT ;
    PORT
      LAYER met2 ;
      RECT 242.810 290.620 242.950 291.040 ;
    END
  END rw0_wmask_in[343]
  PIN rw0_wmask_in[344]
    DIRECTION INPUT ;
    USE SIGNAL ;
    SHAPE ABUTMENT ;
    PORT
      LAYER met2 ;
      RECT 245.570 290.620 245.710 291.040 ;
    END
  END rw0_wmask_in[344]
  PIN rw0_wmask_in[345]
    DIRECTION INPUT ;
    USE SIGNAL ;
    SHAPE ABUTMENT ;
    PORT
      LAYER met2 ;
      RECT 248.330 290.620 248.470 291.040 ;
    END
  END rw0_wmask_in[345]
  PIN rw0_wmask_in[346]
    DIRECTION INPUT ;
    USE SIGNAL ;
    SHAPE ABUTMENT ;
    PORT
      LAYER met2 ;
      RECT 251.090 290.620 251.230 291.040 ;
    END
  END rw0_wmask_in[346]
  PIN rw0_wmask_in[347]
    DIRECTION INPUT ;
    USE SIGNAL ;
    SHAPE ABUTMENT ;
    PORT
      LAYER met2 ;
      RECT 253.850 290.620 253.990 291.040 ;
    END
  END rw0_wmask_in[347]
  PIN rw0_wmask_in[348]
    DIRECTION INPUT ;
    USE SIGNAL ;
    SHAPE ABUTMENT ;
    PORT
      LAYER met2 ;
      RECT 256.610 290.620 256.750 291.040 ;
    END
  END rw0_wmask_in[348]
  PIN rw0_wmask_in[349]
    DIRECTION INPUT ;
    USE SIGNAL ;
    SHAPE ABUTMENT ;
    PORT
      LAYER met2 ;
      RECT 259.370 290.620 259.510 291.040 ;
    END
  END rw0_wmask_in[349]
  PIN rw0_wmask_in[350]
    DIRECTION INPUT ;
    USE SIGNAL ;
    SHAPE ABUTMENT ;
    PORT
      LAYER met2 ;
      RECT 262.130 290.620 262.270 291.040 ;
    END
  END rw0_wmask_in[350]
  PIN rw0_wmask_in[351]
    DIRECTION INPUT ;
    USE SIGNAL ;
    SHAPE ABUTMENT ;
    PORT
      LAYER met2 ;
      RECT 264.890 290.620 265.030 291.040 ;
    END
  END rw0_wmask_in[351]
  PIN rw0_wmask_in[352]
    DIRECTION INPUT ;
    USE SIGNAL ;
    SHAPE ABUTMENT ;
    PORT
      LAYER met2 ;
      RECT 267.650 290.620 267.790 291.040 ;
    END
  END rw0_wmask_in[352]
  PIN rw0_wmask_in[353]
    DIRECTION INPUT ;
    USE SIGNAL ;
    SHAPE ABUTMENT ;
    PORT
      LAYER met2 ;
      RECT 270.410 290.620 270.550 291.040 ;
    END
  END rw0_wmask_in[353]
  PIN rw0_wmask_in[354]
    DIRECTION INPUT ;
    USE SIGNAL ;
    SHAPE ABUTMENT ;
    PORT
      LAYER met2 ;
      RECT 273.170 290.620 273.310 291.040 ;
    END
  END rw0_wmask_in[354]
  PIN rw0_wmask_in[355]
    DIRECTION INPUT ;
    USE SIGNAL ;
    SHAPE ABUTMENT ;
    PORT
      LAYER met2 ;
      RECT 275.930 290.620 276.070 291.040 ;
    END
  END rw0_wmask_in[355]
  PIN rw0_wmask_in[356]
    DIRECTION INPUT ;
    USE SIGNAL ;
    SHAPE ABUTMENT ;
    PORT
      LAYER met2 ;
      RECT 278.690 290.620 278.830 291.040 ;
    END
  END rw0_wmask_in[356]
  PIN rw0_wmask_in[357]
    DIRECTION INPUT ;
    USE SIGNAL ;
    SHAPE ABUTMENT ;
    PORT
      LAYER met2 ;
      RECT 281.450 290.620 281.590 291.040 ;
    END
  END rw0_wmask_in[357]
  PIN rw0_wmask_in[358]
    DIRECTION INPUT ;
    USE SIGNAL ;
    SHAPE ABUTMENT ;
    PORT
      LAYER met2 ;
      RECT 284.210 290.620 284.350 291.040 ;
    END
  END rw0_wmask_in[358]
  PIN rw0_wmask_in[359]
    DIRECTION INPUT ;
    USE SIGNAL ;
    SHAPE ABUTMENT ;
    PORT
      LAYER met2 ;
      RECT 286.970 290.620 287.110 291.040 ;
    END
  END rw0_wmask_in[359]
  PIN rw0_wmask_in[360]
    DIRECTION INPUT ;
    USE SIGNAL ;
    SHAPE ABUTMENT ;
    PORT
      LAYER met2 ;
      RECT 289.730 290.620 289.870 291.040 ;
    END
  END rw0_wmask_in[360]
  PIN rw0_wmask_in[361]
    DIRECTION INPUT ;
    USE SIGNAL ;
    SHAPE ABUTMENT ;
    PORT
      LAYER met2 ;
      RECT 292.490 290.620 292.630 291.040 ;
    END
  END rw0_wmask_in[361]
  PIN rw0_wmask_in[362]
    DIRECTION INPUT ;
    USE SIGNAL ;
    SHAPE ABUTMENT ;
    PORT
      LAYER met2 ;
      RECT 295.250 290.620 295.390 291.040 ;
    END
  END rw0_wmask_in[362]
  PIN rw0_wmask_in[363]
    DIRECTION INPUT ;
    USE SIGNAL ;
    SHAPE ABUTMENT ;
    PORT
      LAYER met2 ;
      RECT 298.010 290.620 298.150 291.040 ;
    END
  END rw0_wmask_in[363]
  PIN rw0_wmask_in[364]
    DIRECTION INPUT ;
    USE SIGNAL ;
    SHAPE ABUTMENT ;
    PORT
      LAYER met2 ;
      RECT 300.770 290.620 300.910 291.040 ;
    END
  END rw0_wmask_in[364]
  PIN rw0_wmask_in[365]
    DIRECTION INPUT ;
    USE SIGNAL ;
    SHAPE ABUTMENT ;
    PORT
      LAYER met2 ;
      RECT 303.530 290.620 303.670 291.040 ;
    END
  END rw0_wmask_in[365]
  PIN rw0_wmask_in[366]
    DIRECTION INPUT ;
    USE SIGNAL ;
    SHAPE ABUTMENT ;
    PORT
      LAYER met2 ;
      RECT 306.290 290.620 306.430 291.040 ;
    END
  END rw0_wmask_in[366]
  PIN rw0_wmask_in[367]
    DIRECTION INPUT ;
    USE SIGNAL ;
    SHAPE ABUTMENT ;
    PORT
      LAYER met2 ;
      RECT 309.050 290.620 309.190 291.040 ;
    END
  END rw0_wmask_in[367]
  PIN rw0_wmask_in[368]
    DIRECTION INPUT ;
    USE SIGNAL ;
    SHAPE ABUTMENT ;
    PORT
      LAYER met2 ;
      RECT 311.810 290.620 311.950 291.040 ;
    END
  END rw0_wmask_in[368]
  PIN rw0_wmask_in[369]
    DIRECTION INPUT ;
    USE SIGNAL ;
    SHAPE ABUTMENT ;
    PORT
      LAYER met2 ;
      RECT 314.570 290.620 314.710 291.040 ;
    END
  END rw0_wmask_in[369]
  PIN rw0_wmask_in[370]
    DIRECTION INPUT ;
    USE SIGNAL ;
    SHAPE ABUTMENT ;
    PORT
      LAYER met2 ;
      RECT 317.330 290.620 317.470 291.040 ;
    END
  END rw0_wmask_in[370]
  PIN rw0_wmask_in[371]
    DIRECTION INPUT ;
    USE SIGNAL ;
    SHAPE ABUTMENT ;
    PORT
      LAYER met2 ;
      RECT 320.090 290.620 320.230 291.040 ;
    END
  END rw0_wmask_in[371]
  PIN rw0_wmask_in[372]
    DIRECTION INPUT ;
    USE SIGNAL ;
    SHAPE ABUTMENT ;
    PORT
      LAYER met2 ;
      RECT 322.850 290.620 322.990 291.040 ;
    END
  END rw0_wmask_in[372]
  PIN rw0_wmask_in[373]
    DIRECTION INPUT ;
    USE SIGNAL ;
    SHAPE ABUTMENT ;
    PORT
      LAYER met2 ;
      RECT 325.610 290.620 325.750 291.040 ;
    END
  END rw0_wmask_in[373]
  PIN rw0_wmask_in[374]
    DIRECTION INPUT ;
    USE SIGNAL ;
    SHAPE ABUTMENT ;
    PORT
      LAYER met2 ;
      RECT 328.370 290.620 328.510 291.040 ;
    END
  END rw0_wmask_in[374]
  PIN rw0_wmask_in[375]
    DIRECTION INPUT ;
    USE SIGNAL ;
    SHAPE ABUTMENT ;
    PORT
      LAYER met2 ;
      RECT 331.130 290.620 331.270 291.040 ;
    END
  END rw0_wmask_in[375]
  PIN rw0_wmask_in[376]
    DIRECTION INPUT ;
    USE SIGNAL ;
    SHAPE ABUTMENT ;
    PORT
      LAYER met2 ;
      RECT 333.890 290.620 334.030 291.040 ;
    END
  END rw0_wmask_in[376]
  PIN rw0_wmask_in[377]
    DIRECTION INPUT ;
    USE SIGNAL ;
    SHAPE ABUTMENT ;
    PORT
      LAYER met2 ;
      RECT 336.650 290.620 336.790 291.040 ;
    END
  END rw0_wmask_in[377]
  PIN rw0_wmask_in[378]
    DIRECTION INPUT ;
    USE SIGNAL ;
    SHAPE ABUTMENT ;
    PORT
      LAYER met2 ;
      RECT 339.410 290.620 339.550 291.040 ;
    END
  END rw0_wmask_in[378]
  PIN rw0_wmask_in[379]
    DIRECTION INPUT ;
    USE SIGNAL ;
    SHAPE ABUTMENT ;
    PORT
      LAYER met2 ;
      RECT 342.170 290.620 342.310 291.040 ;
    END
  END rw0_wmask_in[379]
  PIN rw0_wmask_in[380]
    DIRECTION INPUT ;
    USE SIGNAL ;
    SHAPE ABUTMENT ;
    PORT
      LAYER met2 ;
      RECT 344.930 290.620 345.070 291.040 ;
    END
  END rw0_wmask_in[380]
  PIN rw0_wmask_in[381]
    DIRECTION INPUT ;
    USE SIGNAL ;
    SHAPE ABUTMENT ;
    PORT
      LAYER met2 ;
      RECT 347.690 290.620 347.830 291.040 ;
    END
  END rw0_wmask_in[381]
  PIN rw0_wmask_in[382]
    DIRECTION INPUT ;
    USE SIGNAL ;
    SHAPE ABUTMENT ;
    PORT
      LAYER met2 ;
      RECT 350.450 290.620 350.590 291.040 ;
    END
  END rw0_wmask_in[382]
  PIN rw0_wmask_in[383]
    DIRECTION INPUT ;
    USE SIGNAL ;
    SHAPE ABUTMENT ;
    PORT
      LAYER met2 ;
      RECT 353.210 290.620 353.350 291.040 ;
    END
  END rw0_wmask_in[383]
  PIN rw0_wmask_in[384]
    DIRECTION INPUT ;
    USE SIGNAL ;
    SHAPE ABUTMENT ;
    PORT
      LAYER met2 ;
      RECT 355.970 290.620 356.110 291.040 ;
    END
  END rw0_wmask_in[384]
  PIN rw0_wmask_in[385]
    DIRECTION INPUT ;
    USE SIGNAL ;
    SHAPE ABUTMENT ;
    PORT
      LAYER met2 ;
      RECT 358.730 290.620 358.870 291.040 ;
    END
  END rw0_wmask_in[385]
  PIN rw0_wmask_in[386]
    DIRECTION INPUT ;
    USE SIGNAL ;
    SHAPE ABUTMENT ;
    PORT
      LAYER met2 ;
      RECT 361.490 290.620 361.630 291.040 ;
    END
  END rw0_wmask_in[386]
  PIN rw0_wmask_in[387]
    DIRECTION INPUT ;
    USE SIGNAL ;
    SHAPE ABUTMENT ;
    PORT
      LAYER met2 ;
      RECT 364.250 290.620 364.390 291.040 ;
    END
  END rw0_wmask_in[387]
  PIN rw0_wmask_in[388]
    DIRECTION INPUT ;
    USE SIGNAL ;
    SHAPE ABUTMENT ;
    PORT
      LAYER met2 ;
      RECT 367.010 290.620 367.150 291.040 ;
    END
  END rw0_wmask_in[388]
  PIN rw0_wmask_in[389]
    DIRECTION INPUT ;
    USE SIGNAL ;
    SHAPE ABUTMENT ;
    PORT
      LAYER met2 ;
      RECT 369.770 290.620 369.910 291.040 ;
    END
  END rw0_wmask_in[389]
  PIN rw0_wmask_in[390]
    DIRECTION INPUT ;
    USE SIGNAL ;
    SHAPE ABUTMENT ;
    PORT
      LAYER met2 ;
      RECT 372.530 290.620 372.670 291.040 ;
    END
  END rw0_wmask_in[390]
  PIN rw0_wmask_in[391]
    DIRECTION INPUT ;
    USE SIGNAL ;
    SHAPE ABUTMENT ;
    PORT
      LAYER met2 ;
      RECT 375.290 290.620 375.430 291.040 ;
    END
  END rw0_wmask_in[391]
  PIN rw0_wmask_in[392]
    DIRECTION INPUT ;
    USE SIGNAL ;
    SHAPE ABUTMENT ;
    PORT
      LAYER met2 ;
      RECT 378.050 290.620 378.190 291.040 ;
    END
  END rw0_wmask_in[392]
  PIN rw0_wmask_in[393]
    DIRECTION INPUT ;
    USE SIGNAL ;
    SHAPE ABUTMENT ;
    PORT
      LAYER met2 ;
      RECT 380.810 290.620 380.950 291.040 ;
    END
  END rw0_wmask_in[393]
  PIN rw0_wmask_in[394]
    DIRECTION INPUT ;
    USE SIGNAL ;
    SHAPE ABUTMENT ;
    PORT
      LAYER met2 ;
      RECT 383.570 290.620 383.710 291.040 ;
    END
  END rw0_wmask_in[394]
  PIN rw0_wmask_in[395]
    DIRECTION INPUT ;
    USE SIGNAL ;
    SHAPE ABUTMENT ;
    PORT
      LAYER met2 ;
      RECT 386.330 290.620 386.470 291.040 ;
    END
  END rw0_wmask_in[395]
  PIN rw0_wmask_in[396]
    DIRECTION INPUT ;
    USE SIGNAL ;
    SHAPE ABUTMENT ;
    PORT
      LAYER met2 ;
      RECT 389.090 290.620 389.230 291.040 ;
    END
  END rw0_wmask_in[396]
  PIN rw0_wmask_in[397]
    DIRECTION INPUT ;
    USE SIGNAL ;
    SHAPE ABUTMENT ;
    PORT
      LAYER met2 ;
      RECT 391.850 290.620 391.990 291.040 ;
    END
  END rw0_wmask_in[397]
  PIN rw0_wmask_in[398]
    DIRECTION INPUT ;
    USE SIGNAL ;
    SHAPE ABUTMENT ;
    PORT
      LAYER met2 ;
      RECT 394.610 290.620 394.750 291.040 ;
    END
  END rw0_wmask_in[398]
  PIN rw0_wmask_in[399]
    DIRECTION INPUT ;
    USE SIGNAL ;
    SHAPE ABUTMENT ;
    PORT
      LAYER met2 ;
      RECT 397.370 290.620 397.510 291.040 ;
    END
  END rw0_wmask_in[399]
  PIN rw0_wmask_in[400]
    DIRECTION INPUT ;
    USE SIGNAL ;
    SHAPE ABUTMENT ;
    PORT
      LAYER met2 ;
      RECT 400.130 290.620 400.270 291.040 ;
    END
  END rw0_wmask_in[400]
  PIN rw0_wmask_in[401]
    DIRECTION INPUT ;
    USE SIGNAL ;
    SHAPE ABUTMENT ;
    PORT
      LAYER met2 ;
      RECT 402.890 290.620 403.030 291.040 ;
    END
  END rw0_wmask_in[401]
  PIN rw0_wmask_in[402]
    DIRECTION INPUT ;
    USE SIGNAL ;
    SHAPE ABUTMENT ;
    PORT
      LAYER met2 ;
      RECT 405.650 290.620 405.790 291.040 ;
    END
  END rw0_wmask_in[402]
  PIN rw0_wmask_in[403]
    DIRECTION INPUT ;
    USE SIGNAL ;
    SHAPE ABUTMENT ;
    PORT
      LAYER met2 ;
      RECT 408.410 290.620 408.550 291.040 ;
    END
  END rw0_wmask_in[403]
  PIN rw0_wmask_in[404]
    DIRECTION INPUT ;
    USE SIGNAL ;
    SHAPE ABUTMENT ;
    PORT
      LAYER met2 ;
      RECT 411.170 290.620 411.310 291.040 ;
    END
  END rw0_wmask_in[404]
  PIN rw0_wmask_in[405]
    DIRECTION INPUT ;
    USE SIGNAL ;
    SHAPE ABUTMENT ;
    PORT
      LAYER met2 ;
      RECT 413.930 290.620 414.070 291.040 ;
    END
  END rw0_wmask_in[405]
  PIN rw0_wmask_in[406]
    DIRECTION INPUT ;
    USE SIGNAL ;
    SHAPE ABUTMENT ;
    PORT
      LAYER met2 ;
      RECT 416.690 290.620 416.830 291.040 ;
    END
  END rw0_wmask_in[406]
  PIN rw0_wmask_in[407]
    DIRECTION INPUT ;
    USE SIGNAL ;
    SHAPE ABUTMENT ;
    PORT
      LAYER met2 ;
      RECT 419.450 290.620 419.590 291.040 ;
    END
  END rw0_wmask_in[407]
  PIN rw0_wmask_in[408]
    DIRECTION INPUT ;
    USE SIGNAL ;
    SHAPE ABUTMENT ;
    PORT
      LAYER met2 ;
      RECT 422.210 290.620 422.350 291.040 ;
    END
  END rw0_wmask_in[408]
  PIN rw0_wmask_in[409]
    DIRECTION INPUT ;
    USE SIGNAL ;
    SHAPE ABUTMENT ;
    PORT
      LAYER met2 ;
      RECT 424.970 290.620 425.110 291.040 ;
    END
  END rw0_wmask_in[409]
  PIN rw0_wmask_in[410]
    DIRECTION INPUT ;
    USE SIGNAL ;
    SHAPE ABUTMENT ;
    PORT
      LAYER met2 ;
      RECT 427.730 290.620 427.870 291.040 ;
    END
  END rw0_wmask_in[410]
  PIN rw0_wmask_in[411]
    DIRECTION INPUT ;
    USE SIGNAL ;
    SHAPE ABUTMENT ;
    PORT
      LAYER met2 ;
      RECT 430.490 290.620 430.630 291.040 ;
    END
  END rw0_wmask_in[411]
  PIN rw0_wmask_in[412]
    DIRECTION INPUT ;
    USE SIGNAL ;
    SHAPE ABUTMENT ;
    PORT
      LAYER met2 ;
      RECT 433.250 290.620 433.390 291.040 ;
    END
  END rw0_wmask_in[412]
  PIN rw0_wmask_in[413]
    DIRECTION INPUT ;
    USE SIGNAL ;
    SHAPE ABUTMENT ;
    PORT
      LAYER met2 ;
      RECT 436.010 290.620 436.150 291.040 ;
    END
  END rw0_wmask_in[413]
  PIN rw0_wmask_in[414]
    DIRECTION INPUT ;
    USE SIGNAL ;
    SHAPE ABUTMENT ;
    PORT
      LAYER met2 ;
      RECT 438.770 290.620 438.910 291.040 ;
    END
  END rw0_wmask_in[414]
  PIN rw0_wmask_in[415]
    DIRECTION INPUT ;
    USE SIGNAL ;
    SHAPE ABUTMENT ;
    PORT
      LAYER met2 ;
      RECT 441.530 290.620 441.670 291.040 ;
    END
  END rw0_wmask_in[415]
  PIN rw0_wmask_in[416]
    DIRECTION INPUT ;
    USE SIGNAL ;
    SHAPE ABUTMENT ;
    PORT
      LAYER met2 ;
      RECT 444.290 290.620 444.430 291.040 ;
    END
  END rw0_wmask_in[416]
  PIN rw0_wmask_in[417]
    DIRECTION INPUT ;
    USE SIGNAL ;
    SHAPE ABUTMENT ;
    PORT
      LAYER met2 ;
      RECT 447.050 290.620 447.190 291.040 ;
    END
  END rw0_wmask_in[417]
  PIN rw0_wmask_in[418]
    DIRECTION INPUT ;
    USE SIGNAL ;
    SHAPE ABUTMENT ;
    PORT
      LAYER met2 ;
      RECT 449.810 290.620 449.950 291.040 ;
    END
  END rw0_wmask_in[418]
  PIN rw0_wmask_in[419]
    DIRECTION INPUT ;
    USE SIGNAL ;
    SHAPE ABUTMENT ;
    PORT
      LAYER met2 ;
      RECT 452.570 290.620 452.710 291.040 ;
    END
  END rw0_wmask_in[419]
  PIN rw0_wmask_in[420]
    DIRECTION INPUT ;
    USE SIGNAL ;
    SHAPE ABUTMENT ;
    PORT
      LAYER met2 ;
      RECT 455.330 290.620 455.470 291.040 ;
    END
  END rw0_wmask_in[420]
  PIN rw0_wmask_in[421]
    DIRECTION INPUT ;
    USE SIGNAL ;
    SHAPE ABUTMENT ;
    PORT
      LAYER met2 ;
      RECT 458.090 290.620 458.230 291.040 ;
    END
  END rw0_wmask_in[421]
  PIN rw0_wmask_in[422]
    DIRECTION INPUT ;
    USE SIGNAL ;
    SHAPE ABUTMENT ;
    PORT
      LAYER met2 ;
      RECT 460.850 290.620 460.990 291.040 ;
    END
  END rw0_wmask_in[422]
  PIN rw0_wmask_in[423]
    DIRECTION INPUT ;
    USE SIGNAL ;
    SHAPE ABUTMENT ;
    PORT
      LAYER met2 ;
      RECT 463.610 290.620 463.750 291.040 ;
    END
  END rw0_wmask_in[423]
  PIN rw0_wmask_in[424]
    DIRECTION INPUT ;
    USE SIGNAL ;
    SHAPE ABUTMENT ;
    PORT
      LAYER met2 ;
      RECT 466.370 290.620 466.510 291.040 ;
    END
  END rw0_wmask_in[424]
  PIN rw0_wmask_in[425]
    DIRECTION INPUT ;
    USE SIGNAL ;
    SHAPE ABUTMENT ;
    PORT
      LAYER met2 ;
      RECT 469.130 290.620 469.270 291.040 ;
    END
  END rw0_wmask_in[425]
  PIN rw0_wmask_in[426]
    DIRECTION INPUT ;
    USE SIGNAL ;
    SHAPE ABUTMENT ;
    PORT
      LAYER met2 ;
      RECT 471.890 290.620 472.030 291.040 ;
    END
  END rw0_wmask_in[426]
  PIN rw0_wmask_in[427]
    DIRECTION INPUT ;
    USE SIGNAL ;
    SHAPE ABUTMENT ;
    PORT
      LAYER met2 ;
      RECT 474.650 290.620 474.790 291.040 ;
    END
  END rw0_wmask_in[427]
  PIN rw0_wmask_in[428]
    DIRECTION INPUT ;
    USE SIGNAL ;
    SHAPE ABUTMENT ;
    PORT
      LAYER met2 ;
      RECT 477.410 290.620 477.550 291.040 ;
    END
  END rw0_wmask_in[428]
  PIN rw0_wmask_in[429]
    DIRECTION INPUT ;
    USE SIGNAL ;
    SHAPE ABUTMENT ;
    PORT
      LAYER met2 ;
      RECT 480.170 290.620 480.310 291.040 ;
    END
  END rw0_wmask_in[429]
  PIN rw0_wmask_in[430]
    DIRECTION INPUT ;
    USE SIGNAL ;
    SHAPE ABUTMENT ;
    PORT
      LAYER met2 ;
      RECT 482.930 290.620 483.070 291.040 ;
    END
  END rw0_wmask_in[430]
  PIN rw0_wmask_in[431]
    DIRECTION INPUT ;
    USE SIGNAL ;
    SHAPE ABUTMENT ;
    PORT
      LAYER met2 ;
      RECT 485.690 290.620 485.830 291.040 ;
    END
  END rw0_wmask_in[431]
  PIN rw0_wmask_in[432]
    DIRECTION INPUT ;
    USE SIGNAL ;
    SHAPE ABUTMENT ;
    PORT
      LAYER met2 ;
      RECT 488.450 290.620 488.590 291.040 ;
    END
  END rw0_wmask_in[432]
  PIN rw0_wmask_in[433]
    DIRECTION INPUT ;
    USE SIGNAL ;
    SHAPE ABUTMENT ;
    PORT
      LAYER met2 ;
      RECT 491.210 290.620 491.350 291.040 ;
    END
  END rw0_wmask_in[433]
  PIN rw0_wmask_in[434]
    DIRECTION INPUT ;
    USE SIGNAL ;
    SHAPE ABUTMENT ;
    PORT
      LAYER met2 ;
      RECT 493.970 290.620 494.110 291.040 ;
    END
  END rw0_wmask_in[434]
  PIN rw0_wmask_in[435]
    DIRECTION INPUT ;
    USE SIGNAL ;
    SHAPE ABUTMENT ;
    PORT
      LAYER met2 ;
      RECT 496.730 290.620 496.870 291.040 ;
    END
  END rw0_wmask_in[435]
  PIN rw0_wmask_in[436]
    DIRECTION INPUT ;
    USE SIGNAL ;
    SHAPE ABUTMENT ;
    PORT
      LAYER met2 ;
      RECT 499.490 290.620 499.630 291.040 ;
    END
  END rw0_wmask_in[436]
  PIN rw0_wmask_in[437]
    DIRECTION INPUT ;
    USE SIGNAL ;
    SHAPE ABUTMENT ;
    PORT
      LAYER met2 ;
      RECT 502.250 290.620 502.390 291.040 ;
    END
  END rw0_wmask_in[437]
  PIN rw0_wmask_in[438]
    DIRECTION INPUT ;
    USE SIGNAL ;
    SHAPE ABUTMENT ;
    PORT
      LAYER met2 ;
      RECT 505.010 290.620 505.150 291.040 ;
    END
  END rw0_wmask_in[438]
  PIN rw0_wmask_in[439]
    DIRECTION INPUT ;
    USE SIGNAL ;
    SHAPE ABUTMENT ;
    PORT
      LAYER met2 ;
      RECT 507.770 290.620 507.910 291.040 ;
    END
  END rw0_wmask_in[439]
  PIN rw0_wmask_in[440]
    DIRECTION INPUT ;
    USE SIGNAL ;
    SHAPE ABUTMENT ;
    PORT
      LAYER met2 ;
      RECT 510.530 290.620 510.670 291.040 ;
    END
  END rw0_wmask_in[440]
  PIN rw0_wmask_in[441]
    DIRECTION INPUT ;
    USE SIGNAL ;
    SHAPE ABUTMENT ;
    PORT
      LAYER met2 ;
      RECT 513.290 290.620 513.430 291.040 ;
    END
  END rw0_wmask_in[441]
  PIN rw0_wmask_in[442]
    DIRECTION INPUT ;
    USE SIGNAL ;
    SHAPE ABUTMENT ;
    PORT
      LAYER met2 ;
      RECT 516.050 290.620 516.190 291.040 ;
    END
  END rw0_wmask_in[442]
  PIN rw0_wmask_in[443]
    DIRECTION INPUT ;
    USE SIGNAL ;
    SHAPE ABUTMENT ;
    PORT
      LAYER met2 ;
      RECT 518.810 290.620 518.950 291.040 ;
    END
  END rw0_wmask_in[443]
  PIN rw0_wmask_in[444]
    DIRECTION INPUT ;
    USE SIGNAL ;
    SHAPE ABUTMENT ;
    PORT
      LAYER met2 ;
      RECT 521.570 290.620 521.710 291.040 ;
    END
  END rw0_wmask_in[444]
  PIN rw0_wmask_in[445]
    DIRECTION INPUT ;
    USE SIGNAL ;
    SHAPE ABUTMENT ;
    PORT
      LAYER met2 ;
      RECT 524.330 290.620 524.470 291.040 ;
    END
  END rw0_wmask_in[445]
  PIN rw0_wmask_in[446]
    DIRECTION INPUT ;
    USE SIGNAL ;
    SHAPE ABUTMENT ;
    PORT
      LAYER met2 ;
      RECT 527.090 290.620 527.230 291.040 ;
    END
  END rw0_wmask_in[446]
  PIN rw0_wmask_in[447]
    DIRECTION INPUT ;
    USE SIGNAL ;
    SHAPE ABUTMENT ;
    PORT
      LAYER met2 ;
      RECT 529.850 290.620 529.990 291.040 ;
    END
  END rw0_wmask_in[447]
  PIN rw0_wmask_in[448]
    DIRECTION INPUT ;
    USE SIGNAL ;
    SHAPE ABUTMENT ;
    PORT
      LAYER met2 ;
      RECT 532.610 290.620 532.750 291.040 ;
    END
  END rw0_wmask_in[448]
  PIN rw0_wmask_in[449]
    DIRECTION INPUT ;
    USE SIGNAL ;
    SHAPE ABUTMENT ;
    PORT
      LAYER met2 ;
      RECT 535.370 290.620 535.510 291.040 ;
    END
  END rw0_wmask_in[449]
  PIN rw0_wmask_in[450]
    DIRECTION INPUT ;
    USE SIGNAL ;
    SHAPE ABUTMENT ;
    PORT
      LAYER met2 ;
      RECT 538.130 290.620 538.270 291.040 ;
    END
  END rw0_wmask_in[450]
  PIN rw0_wmask_in[451]
    DIRECTION INPUT ;
    USE SIGNAL ;
    SHAPE ABUTMENT ;
    PORT
      LAYER met2 ;
      RECT 540.890 290.620 541.030 291.040 ;
    END
  END rw0_wmask_in[451]
  PIN rw0_wmask_in[452]
    DIRECTION INPUT ;
    USE SIGNAL ;
    SHAPE ABUTMENT ;
    PORT
      LAYER met2 ;
      RECT 543.650 290.620 543.790 291.040 ;
    END
  END rw0_wmask_in[452]
  PIN rw0_wmask_in[453]
    DIRECTION INPUT ;
    USE SIGNAL ;
    SHAPE ABUTMENT ;
    PORT
      LAYER met2 ;
      RECT 546.410 290.620 546.550 291.040 ;
    END
  END rw0_wmask_in[453]
  PIN rw0_wmask_in[454]
    DIRECTION INPUT ;
    USE SIGNAL ;
    SHAPE ABUTMENT ;
    PORT
      LAYER met2 ;
      RECT 549.170 290.620 549.310 291.040 ;
    END
  END rw0_wmask_in[454]
  PIN rw0_wmask_in[455]
    DIRECTION INPUT ;
    USE SIGNAL ;
    SHAPE ABUTMENT ;
    PORT
      LAYER met2 ;
      RECT 551.930 290.620 552.070 291.040 ;
    END
  END rw0_wmask_in[455]
  PIN rw0_wmask_in[456]
    DIRECTION INPUT ;
    USE SIGNAL ;
    SHAPE ABUTMENT ;
    PORT
      LAYER met2 ;
      RECT 554.690 290.620 554.830 291.040 ;
    END
  END rw0_wmask_in[456]
  PIN rw0_wmask_in[457]
    DIRECTION INPUT ;
    USE SIGNAL ;
    SHAPE ABUTMENT ;
    PORT
      LAYER met2 ;
      RECT 557.450 290.620 557.590 291.040 ;
    END
  END rw0_wmask_in[457]
  PIN rw0_wmask_in[458]
    DIRECTION INPUT ;
    USE SIGNAL ;
    SHAPE ABUTMENT ;
    PORT
      LAYER met2 ;
      RECT 560.210 290.620 560.350 291.040 ;
    END
  END rw0_wmask_in[458]
  PIN rw0_wmask_in[459]
    DIRECTION INPUT ;
    USE SIGNAL ;
    SHAPE ABUTMENT ;
    PORT
      LAYER met2 ;
      RECT 562.970 290.620 563.110 291.040 ;
    END
  END rw0_wmask_in[459]
  PIN rw0_wmask_in[460]
    DIRECTION INPUT ;
    USE SIGNAL ;
    SHAPE ABUTMENT ;
    PORT
      LAYER met2 ;
      RECT 565.730 290.620 565.870 291.040 ;
    END
  END rw0_wmask_in[460]
  PIN rw0_wmask_in[461]
    DIRECTION INPUT ;
    USE SIGNAL ;
    SHAPE ABUTMENT ;
    PORT
      LAYER met2 ;
      RECT 568.490 290.620 568.630 291.040 ;
    END
  END rw0_wmask_in[461]
  PIN rw0_wmask_in[462]
    DIRECTION INPUT ;
    USE SIGNAL ;
    SHAPE ABUTMENT ;
    PORT
      LAYER met2 ;
      RECT 571.250 290.620 571.390 291.040 ;
    END
  END rw0_wmask_in[462]
  PIN rw0_wmask_in[463]
    DIRECTION INPUT ;
    USE SIGNAL ;
    SHAPE ABUTMENT ;
    PORT
      LAYER met2 ;
      RECT 574.010 290.620 574.150 291.040 ;
    END
  END rw0_wmask_in[463]
  PIN rw0_wmask_in[464]
    DIRECTION INPUT ;
    USE SIGNAL ;
    SHAPE ABUTMENT ;
    PORT
      LAYER met2 ;
      RECT 576.770 290.620 576.910 291.040 ;
    END
  END rw0_wmask_in[464]
  PIN rw0_wmask_in[465]
    DIRECTION INPUT ;
    USE SIGNAL ;
    SHAPE ABUTMENT ;
    PORT
      LAYER met2 ;
      RECT 579.530 290.620 579.670 291.040 ;
    END
  END rw0_wmask_in[465]
  PIN rw0_wmask_in[466]
    DIRECTION INPUT ;
    USE SIGNAL ;
    SHAPE ABUTMENT ;
    PORT
      LAYER met2 ;
      RECT 582.290 290.620 582.430 291.040 ;
    END
  END rw0_wmask_in[466]
  PIN rw0_wmask_in[467]
    DIRECTION INPUT ;
    USE SIGNAL ;
    SHAPE ABUTMENT ;
    PORT
      LAYER met2 ;
      RECT 585.050 290.620 585.190 291.040 ;
    END
  END rw0_wmask_in[467]
  PIN rw0_wmask_in[468]
    DIRECTION INPUT ;
    USE SIGNAL ;
    SHAPE ABUTMENT ;
    PORT
      LAYER met2 ;
      RECT 587.810 290.620 587.950 291.040 ;
    END
  END rw0_wmask_in[468]
  PIN rw0_wmask_in[469]
    DIRECTION INPUT ;
    USE SIGNAL ;
    SHAPE ABUTMENT ;
    PORT
      LAYER met2 ;
      RECT 590.570 290.620 590.710 291.040 ;
    END
  END rw0_wmask_in[469]
  PIN rw0_wmask_in[470]
    DIRECTION INPUT ;
    USE SIGNAL ;
    SHAPE ABUTMENT ;
    PORT
      LAYER met2 ;
      RECT 593.330 290.620 593.470 291.040 ;
    END
  END rw0_wmask_in[470]
  PIN rw0_wmask_in[471]
    DIRECTION INPUT ;
    USE SIGNAL ;
    SHAPE ABUTMENT ;
    PORT
      LAYER met2 ;
      RECT 596.090 290.620 596.230 291.040 ;
    END
  END rw0_wmask_in[471]
  PIN rw0_wmask_in[472]
    DIRECTION INPUT ;
    USE SIGNAL ;
    SHAPE ABUTMENT ;
    PORT
      LAYER met2 ;
      RECT 598.850 290.620 598.990 291.040 ;
    END
  END rw0_wmask_in[472]
  PIN rw0_wmask_in[473]
    DIRECTION INPUT ;
    USE SIGNAL ;
    SHAPE ABUTMENT ;
    PORT
      LAYER met2 ;
      RECT 601.610 290.620 601.750 291.040 ;
    END
  END rw0_wmask_in[473]
  PIN rw0_wmask_in[474]
    DIRECTION INPUT ;
    USE SIGNAL ;
    SHAPE ABUTMENT ;
    PORT
      LAYER met2 ;
      RECT 604.370 290.620 604.510 291.040 ;
    END
  END rw0_wmask_in[474]
  PIN rw0_wmask_in[475]
    DIRECTION INPUT ;
    USE SIGNAL ;
    SHAPE ABUTMENT ;
    PORT
      LAYER met2 ;
      RECT 607.130 290.620 607.270 291.040 ;
    END
  END rw0_wmask_in[475]
  PIN rw0_wmask_in[476]
    DIRECTION INPUT ;
    USE SIGNAL ;
    SHAPE ABUTMENT ;
    PORT
      LAYER met2 ;
      RECT 609.890 290.620 610.030 291.040 ;
    END
  END rw0_wmask_in[476]
  PIN rw0_wmask_in[477]
    DIRECTION INPUT ;
    USE SIGNAL ;
    SHAPE ABUTMENT ;
    PORT
      LAYER met2 ;
      RECT 612.650 290.620 612.790 291.040 ;
    END
  END rw0_wmask_in[477]
  PIN rw0_wmask_in[478]
    DIRECTION INPUT ;
    USE SIGNAL ;
    SHAPE ABUTMENT ;
    PORT
      LAYER met2 ;
      RECT 615.410 290.620 615.550 291.040 ;
    END
  END rw0_wmask_in[478]
  PIN rw0_wmask_in[479]
    DIRECTION INPUT ;
    USE SIGNAL ;
    SHAPE ABUTMENT ;
    PORT
      LAYER met2 ;
      RECT 618.170 290.620 618.310 291.040 ;
    END
  END rw0_wmask_in[479]
  PIN rw0_wmask_in[480]
    DIRECTION INPUT ;
    USE SIGNAL ;
    SHAPE ABUTMENT ;
    PORT
      LAYER met2 ;
      RECT 620.930 290.620 621.070 291.040 ;
    END
  END rw0_wmask_in[480]
  PIN rw0_wmask_in[481]
    DIRECTION INPUT ;
    USE SIGNAL ;
    SHAPE ABUTMENT ;
    PORT
      LAYER met2 ;
      RECT 623.690 290.620 623.830 291.040 ;
    END
  END rw0_wmask_in[481]
  PIN rw0_wmask_in[482]
    DIRECTION INPUT ;
    USE SIGNAL ;
    SHAPE ABUTMENT ;
    PORT
      LAYER met2 ;
      RECT 626.450 290.620 626.590 291.040 ;
    END
  END rw0_wmask_in[482]
  PIN rw0_wmask_in[483]
    DIRECTION INPUT ;
    USE SIGNAL ;
    SHAPE ABUTMENT ;
    PORT
      LAYER met2 ;
      RECT 629.210 290.620 629.350 291.040 ;
    END
  END rw0_wmask_in[483]
  PIN rw0_wmask_in[484]
    DIRECTION INPUT ;
    USE SIGNAL ;
    SHAPE ABUTMENT ;
    PORT
      LAYER met2 ;
      RECT 631.970 290.620 632.110 291.040 ;
    END
  END rw0_wmask_in[484]
  PIN rw0_wmask_in[485]
    DIRECTION INPUT ;
    USE SIGNAL ;
    SHAPE ABUTMENT ;
    PORT
      LAYER met2 ;
      RECT 634.730 290.620 634.870 291.040 ;
    END
  END rw0_wmask_in[485]
  PIN rw0_wmask_in[486]
    DIRECTION INPUT ;
    USE SIGNAL ;
    SHAPE ABUTMENT ;
    PORT
      LAYER met2 ;
      RECT 637.490 290.620 637.630 291.040 ;
    END
  END rw0_wmask_in[486]
  PIN rw0_wmask_in[487]
    DIRECTION INPUT ;
    USE SIGNAL ;
    SHAPE ABUTMENT ;
    PORT
      LAYER met2 ;
      RECT 640.250 290.620 640.390 291.040 ;
    END
  END rw0_wmask_in[487]
  PIN rw0_wmask_in[488]
    DIRECTION INPUT ;
    USE SIGNAL ;
    SHAPE ABUTMENT ;
    PORT
      LAYER met2 ;
      RECT 643.010 290.620 643.150 291.040 ;
    END
  END rw0_wmask_in[488]
  PIN rw0_wmask_in[489]
    DIRECTION INPUT ;
    USE SIGNAL ;
    SHAPE ABUTMENT ;
    PORT
      LAYER met2 ;
      RECT 645.770 290.620 645.910 291.040 ;
    END
  END rw0_wmask_in[489]
  PIN rw0_wmask_in[490]
    DIRECTION INPUT ;
    USE SIGNAL ;
    SHAPE ABUTMENT ;
    PORT
      LAYER met2 ;
      RECT 648.530 290.620 648.670 291.040 ;
    END
  END rw0_wmask_in[490]
  PIN rw0_wmask_in[491]
    DIRECTION INPUT ;
    USE SIGNAL ;
    SHAPE ABUTMENT ;
    PORT
      LAYER met2 ;
      RECT 651.290 290.620 651.430 291.040 ;
    END
  END rw0_wmask_in[491]
  PIN rw0_wmask_in[492]
    DIRECTION INPUT ;
    USE SIGNAL ;
    SHAPE ABUTMENT ;
    PORT
      LAYER met2 ;
      RECT 654.050 290.620 654.190 291.040 ;
    END
  END rw0_wmask_in[492]
  PIN rw0_wmask_in[493]
    DIRECTION INPUT ;
    USE SIGNAL ;
    SHAPE ABUTMENT ;
    PORT
      LAYER met2 ;
      RECT 656.810 290.620 656.950 291.040 ;
    END
  END rw0_wmask_in[493]
  PIN rw0_wmask_in[494]
    DIRECTION INPUT ;
    USE SIGNAL ;
    SHAPE ABUTMENT ;
    PORT
      LAYER met2 ;
      RECT 659.570 290.620 659.710 291.040 ;
    END
  END rw0_wmask_in[494]
  PIN rw0_wmask_in[495]
    DIRECTION INPUT ;
    USE SIGNAL ;
    SHAPE ABUTMENT ;
    PORT
      LAYER met2 ;
      RECT 662.330 290.620 662.470 291.040 ;
    END
  END rw0_wmask_in[495]
  PIN rw0_wmask_in[496]
    DIRECTION INPUT ;
    USE SIGNAL ;
    SHAPE ABUTMENT ;
    PORT
      LAYER met2 ;
      RECT 665.090 290.620 665.230 291.040 ;
    END
  END rw0_wmask_in[496]
  PIN rw0_wmask_in[497]
    DIRECTION INPUT ;
    USE SIGNAL ;
    SHAPE ABUTMENT ;
    PORT
      LAYER met2 ;
      RECT 667.850 290.620 667.990 291.040 ;
    END
  END rw0_wmask_in[497]
  PIN rw0_wmask_in[498]
    DIRECTION INPUT ;
    USE SIGNAL ;
    SHAPE ABUTMENT ;
    PORT
      LAYER met2 ;
      RECT 670.610 290.620 670.750 291.040 ;
    END
  END rw0_wmask_in[498]
  PIN rw0_wmask_in[499]
    DIRECTION INPUT ;
    USE SIGNAL ;
    SHAPE ABUTMENT ;
    PORT
      LAYER met2 ;
      RECT 673.370 290.620 673.510 291.040 ;
    END
  END rw0_wmask_in[499]
  PIN rw0_wmask_in[500]
    DIRECTION INPUT ;
    USE SIGNAL ;
    SHAPE ABUTMENT ;
    PORT
      LAYER met2 ;
      RECT 676.130 290.620 676.270 291.040 ;
    END
  END rw0_wmask_in[500]
  PIN rw0_wmask_in[501]
    DIRECTION INPUT ;
    USE SIGNAL ;
    SHAPE ABUTMENT ;
    PORT
      LAYER met2 ;
      RECT 678.890 290.620 679.030 291.040 ;
    END
  END rw0_wmask_in[501]
  PIN rw0_wmask_in[502]
    DIRECTION INPUT ;
    USE SIGNAL ;
    SHAPE ABUTMENT ;
    PORT
      LAYER met2 ;
      RECT 681.650 290.620 681.790 291.040 ;
    END
  END rw0_wmask_in[502]
  PIN rw0_wmask_in[503]
    DIRECTION INPUT ;
    USE SIGNAL ;
    SHAPE ABUTMENT ;
    PORT
      LAYER met2 ;
      RECT 684.410 290.620 684.550 291.040 ;
    END
  END rw0_wmask_in[503]
  PIN rw0_wmask_in[504]
    DIRECTION INPUT ;
    USE SIGNAL ;
    SHAPE ABUTMENT ;
    PORT
      LAYER met2 ;
      RECT 687.170 290.620 687.310 291.040 ;
    END
  END rw0_wmask_in[504]
  PIN rw0_wmask_in[505]
    DIRECTION INPUT ;
    USE SIGNAL ;
    SHAPE ABUTMENT ;
    PORT
      LAYER met2 ;
      RECT 689.930 290.620 690.070 291.040 ;
    END
  END rw0_wmask_in[505]
  PIN rw0_wmask_in[506]
    DIRECTION INPUT ;
    USE SIGNAL ;
    SHAPE ABUTMENT ;
    PORT
      LAYER met2 ;
      RECT 692.690 290.620 692.830 291.040 ;
    END
  END rw0_wmask_in[506]
  PIN rw0_wmask_in[507]
    DIRECTION INPUT ;
    USE SIGNAL ;
    SHAPE ABUTMENT ;
    PORT
      LAYER met2 ;
      RECT 695.450 290.620 695.590 291.040 ;
    END
  END rw0_wmask_in[507]
  PIN rw0_wmask_in[508]
    DIRECTION INPUT ;
    USE SIGNAL ;
    SHAPE ABUTMENT ;
    PORT
      LAYER met2 ;
      RECT 698.210 290.620 698.350 291.040 ;
    END
  END rw0_wmask_in[508]
  PIN rw0_wmask_in[509]
    DIRECTION INPUT ;
    USE SIGNAL ;
    SHAPE ABUTMENT ;
    PORT
      LAYER met2 ;
      RECT 700.970 290.620 701.110 291.040 ;
    END
  END rw0_wmask_in[509]
  PIN rw0_wmask_in[510]
    DIRECTION INPUT ;
    USE SIGNAL ;
    SHAPE ABUTMENT ;
    PORT
      LAYER met2 ;
      RECT 703.730 290.620 703.870 291.040 ;
    END
  END rw0_wmask_in[510]
  PIN rw0_wmask_in[511]
    DIRECTION INPUT ;
    USE SIGNAL ;
    SHAPE ABUTMENT ;
    PORT
      LAYER met2 ;
      RECT 706.490 290.620 706.630 291.040 ;
    END
  END rw0_wmask_in[511]
  PIN rw0_wd_in[0]
    DIRECTION INPUT ;
    USE SIGNAL ;
    SHAPE ABUTMENT ;
    PORT
      LAYER met3 ;
      RECT 0.000 90.970 0.900 91.270 ;
    END
  END rw0_wd_in[0]
  PIN rw0_wd_in[1]
    DIRECTION INPUT ;
    USE SIGNAL ;
    SHAPE ABUTMENT ;
    PORT
      LAYER met3 ;
      RECT 0.000 91.650 0.900 91.950 ;
    END
  END rw0_wd_in[1]
  PIN rw0_wd_in[2]
    DIRECTION INPUT ;
    USE SIGNAL ;
    SHAPE ABUTMENT ;
    PORT
      LAYER met3 ;
      RECT 0.000 92.330 0.900 92.630 ;
    END
  END rw0_wd_in[2]
  PIN rw0_wd_in[3]
    DIRECTION INPUT ;
    USE SIGNAL ;
    SHAPE ABUTMENT ;
    PORT
      LAYER met3 ;
      RECT 0.000 93.010 0.900 93.310 ;
    END
  END rw0_wd_in[3]
  PIN rw0_wd_in[4]
    DIRECTION INPUT ;
    USE SIGNAL ;
    SHAPE ABUTMENT ;
    PORT
      LAYER met3 ;
      RECT 0.000 93.690 0.900 93.990 ;
    END
  END rw0_wd_in[4]
  PIN rw0_wd_in[5]
    DIRECTION INPUT ;
    USE SIGNAL ;
    SHAPE ABUTMENT ;
    PORT
      LAYER met3 ;
      RECT 0.000 94.370 0.900 94.670 ;
    END
  END rw0_wd_in[5]
  PIN rw0_wd_in[6]
    DIRECTION INPUT ;
    USE SIGNAL ;
    SHAPE ABUTMENT ;
    PORT
      LAYER met3 ;
      RECT 0.000 95.050 0.900 95.350 ;
    END
  END rw0_wd_in[6]
  PIN rw0_wd_in[7]
    DIRECTION INPUT ;
    USE SIGNAL ;
    SHAPE ABUTMENT ;
    PORT
      LAYER met3 ;
      RECT 0.000 95.730 0.900 96.030 ;
    END
  END rw0_wd_in[7]
  PIN rw0_wd_in[8]
    DIRECTION INPUT ;
    USE SIGNAL ;
    SHAPE ABUTMENT ;
    PORT
      LAYER met3 ;
      RECT 0.000 96.410 0.900 96.710 ;
    END
  END rw0_wd_in[8]
  PIN rw0_wd_in[9]
    DIRECTION INPUT ;
    USE SIGNAL ;
    SHAPE ABUTMENT ;
    PORT
      LAYER met3 ;
      RECT 0.000 97.090 0.900 97.390 ;
    END
  END rw0_wd_in[9]
  PIN rw0_wd_in[10]
    DIRECTION INPUT ;
    USE SIGNAL ;
    SHAPE ABUTMENT ;
    PORT
      LAYER met3 ;
      RECT 0.000 97.770 0.900 98.070 ;
    END
  END rw0_wd_in[10]
  PIN rw0_wd_in[11]
    DIRECTION INPUT ;
    USE SIGNAL ;
    SHAPE ABUTMENT ;
    PORT
      LAYER met3 ;
      RECT 0.000 98.450 0.900 98.750 ;
    END
  END rw0_wd_in[11]
  PIN rw0_wd_in[12]
    DIRECTION INPUT ;
    USE SIGNAL ;
    SHAPE ABUTMENT ;
    PORT
      LAYER met3 ;
      RECT 0.000 99.130 0.900 99.430 ;
    END
  END rw0_wd_in[12]
  PIN rw0_wd_in[13]
    DIRECTION INPUT ;
    USE SIGNAL ;
    SHAPE ABUTMENT ;
    PORT
      LAYER met3 ;
      RECT 0.000 99.810 0.900 100.110 ;
    END
  END rw0_wd_in[13]
  PIN rw0_wd_in[14]
    DIRECTION INPUT ;
    USE SIGNAL ;
    SHAPE ABUTMENT ;
    PORT
      LAYER met3 ;
      RECT 0.000 100.490 0.900 100.790 ;
    END
  END rw0_wd_in[14]
  PIN rw0_wd_in[15]
    DIRECTION INPUT ;
    USE SIGNAL ;
    SHAPE ABUTMENT ;
    PORT
      LAYER met3 ;
      RECT 0.000 101.170 0.900 101.470 ;
    END
  END rw0_wd_in[15]
  PIN rw0_wd_in[16]
    DIRECTION INPUT ;
    USE SIGNAL ;
    SHAPE ABUTMENT ;
    PORT
      LAYER met3 ;
      RECT 0.000 101.850 0.900 102.150 ;
    END
  END rw0_wd_in[16]
  PIN rw0_wd_in[17]
    DIRECTION INPUT ;
    USE SIGNAL ;
    SHAPE ABUTMENT ;
    PORT
      LAYER met3 ;
      RECT 0.000 102.530 0.900 102.830 ;
    END
  END rw0_wd_in[17]
  PIN rw0_wd_in[18]
    DIRECTION INPUT ;
    USE SIGNAL ;
    SHAPE ABUTMENT ;
    PORT
      LAYER met3 ;
      RECT 0.000 103.210 0.900 103.510 ;
    END
  END rw0_wd_in[18]
  PIN rw0_wd_in[19]
    DIRECTION INPUT ;
    USE SIGNAL ;
    SHAPE ABUTMENT ;
    PORT
      LAYER met3 ;
      RECT 0.000 103.890 0.900 104.190 ;
    END
  END rw0_wd_in[19]
  PIN rw0_wd_in[20]
    DIRECTION INPUT ;
    USE SIGNAL ;
    SHAPE ABUTMENT ;
    PORT
      LAYER met3 ;
      RECT 0.000 104.570 0.900 104.870 ;
    END
  END rw0_wd_in[20]
  PIN rw0_wd_in[21]
    DIRECTION INPUT ;
    USE SIGNAL ;
    SHAPE ABUTMENT ;
    PORT
      LAYER met3 ;
      RECT 0.000 105.250 0.900 105.550 ;
    END
  END rw0_wd_in[21]
  PIN rw0_wd_in[22]
    DIRECTION INPUT ;
    USE SIGNAL ;
    SHAPE ABUTMENT ;
    PORT
      LAYER met3 ;
      RECT 0.000 105.930 0.900 106.230 ;
    END
  END rw0_wd_in[22]
  PIN rw0_wd_in[23]
    DIRECTION INPUT ;
    USE SIGNAL ;
    SHAPE ABUTMENT ;
    PORT
      LAYER met3 ;
      RECT 0.000 106.610 0.900 106.910 ;
    END
  END rw0_wd_in[23]
  PIN rw0_wd_in[24]
    DIRECTION INPUT ;
    USE SIGNAL ;
    SHAPE ABUTMENT ;
    PORT
      LAYER met3 ;
      RECT 0.000 107.290 0.900 107.590 ;
    END
  END rw0_wd_in[24]
  PIN rw0_wd_in[25]
    DIRECTION INPUT ;
    USE SIGNAL ;
    SHAPE ABUTMENT ;
    PORT
      LAYER met3 ;
      RECT 0.000 107.970 0.900 108.270 ;
    END
  END rw0_wd_in[25]
  PIN rw0_wd_in[26]
    DIRECTION INPUT ;
    USE SIGNAL ;
    SHAPE ABUTMENT ;
    PORT
      LAYER met3 ;
      RECT 0.000 108.650 0.900 108.950 ;
    END
  END rw0_wd_in[26]
  PIN rw0_wd_in[27]
    DIRECTION INPUT ;
    USE SIGNAL ;
    SHAPE ABUTMENT ;
    PORT
      LAYER met3 ;
      RECT 0.000 109.330 0.900 109.630 ;
    END
  END rw0_wd_in[27]
  PIN rw0_wd_in[28]
    DIRECTION INPUT ;
    USE SIGNAL ;
    SHAPE ABUTMENT ;
    PORT
      LAYER met3 ;
      RECT 0.000 110.010 0.900 110.310 ;
    END
  END rw0_wd_in[28]
  PIN rw0_wd_in[29]
    DIRECTION INPUT ;
    USE SIGNAL ;
    SHAPE ABUTMENT ;
    PORT
      LAYER met3 ;
      RECT 0.000 110.690 0.900 110.990 ;
    END
  END rw0_wd_in[29]
  PIN rw0_wd_in[30]
    DIRECTION INPUT ;
    USE SIGNAL ;
    SHAPE ABUTMENT ;
    PORT
      LAYER met3 ;
      RECT 0.000 111.370 0.900 111.670 ;
    END
  END rw0_wd_in[30]
  PIN rw0_wd_in[31]
    DIRECTION INPUT ;
    USE SIGNAL ;
    SHAPE ABUTMENT ;
    PORT
      LAYER met3 ;
      RECT 0.000 112.050 0.900 112.350 ;
    END
  END rw0_wd_in[31]
  PIN rw0_wd_in[32]
    DIRECTION INPUT ;
    USE SIGNAL ;
    SHAPE ABUTMENT ;
    PORT
      LAYER met3 ;
      RECT 0.000 112.730 0.900 113.030 ;
    END
  END rw0_wd_in[32]
  PIN rw0_wd_in[33]
    DIRECTION INPUT ;
    USE SIGNAL ;
    SHAPE ABUTMENT ;
    PORT
      LAYER met3 ;
      RECT 0.000 113.410 0.900 113.710 ;
    END
  END rw0_wd_in[33]
  PIN rw0_wd_in[34]
    DIRECTION INPUT ;
    USE SIGNAL ;
    SHAPE ABUTMENT ;
    PORT
      LAYER met3 ;
      RECT 0.000 114.090 0.900 114.390 ;
    END
  END rw0_wd_in[34]
  PIN rw0_wd_in[35]
    DIRECTION INPUT ;
    USE SIGNAL ;
    SHAPE ABUTMENT ;
    PORT
      LAYER met3 ;
      RECT 0.000 114.770 0.900 115.070 ;
    END
  END rw0_wd_in[35]
  PIN rw0_wd_in[36]
    DIRECTION INPUT ;
    USE SIGNAL ;
    SHAPE ABUTMENT ;
    PORT
      LAYER met3 ;
      RECT 0.000 115.450 0.900 115.750 ;
    END
  END rw0_wd_in[36]
  PIN rw0_wd_in[37]
    DIRECTION INPUT ;
    USE SIGNAL ;
    SHAPE ABUTMENT ;
    PORT
      LAYER met3 ;
      RECT 0.000 116.130 0.900 116.430 ;
    END
  END rw0_wd_in[37]
  PIN rw0_wd_in[38]
    DIRECTION INPUT ;
    USE SIGNAL ;
    SHAPE ABUTMENT ;
    PORT
      LAYER met3 ;
      RECT 0.000 116.810 0.900 117.110 ;
    END
  END rw0_wd_in[38]
  PIN rw0_wd_in[39]
    DIRECTION INPUT ;
    USE SIGNAL ;
    SHAPE ABUTMENT ;
    PORT
      LAYER met3 ;
      RECT 0.000 117.490 0.900 117.790 ;
    END
  END rw0_wd_in[39]
  PIN rw0_wd_in[40]
    DIRECTION INPUT ;
    USE SIGNAL ;
    SHAPE ABUTMENT ;
    PORT
      LAYER met3 ;
      RECT 0.000 118.170 0.900 118.470 ;
    END
  END rw0_wd_in[40]
  PIN rw0_wd_in[41]
    DIRECTION INPUT ;
    USE SIGNAL ;
    SHAPE ABUTMENT ;
    PORT
      LAYER met3 ;
      RECT 0.000 118.850 0.900 119.150 ;
    END
  END rw0_wd_in[41]
  PIN rw0_wd_in[42]
    DIRECTION INPUT ;
    USE SIGNAL ;
    SHAPE ABUTMENT ;
    PORT
      LAYER met3 ;
      RECT 0.000 119.530 0.900 119.830 ;
    END
  END rw0_wd_in[42]
  PIN rw0_wd_in[43]
    DIRECTION INPUT ;
    USE SIGNAL ;
    SHAPE ABUTMENT ;
    PORT
      LAYER met3 ;
      RECT 0.000 120.210 0.900 120.510 ;
    END
  END rw0_wd_in[43]
  PIN rw0_wd_in[44]
    DIRECTION INPUT ;
    USE SIGNAL ;
    SHAPE ABUTMENT ;
    PORT
      LAYER met3 ;
      RECT 0.000 120.890 0.900 121.190 ;
    END
  END rw0_wd_in[44]
  PIN rw0_wd_in[45]
    DIRECTION INPUT ;
    USE SIGNAL ;
    SHAPE ABUTMENT ;
    PORT
      LAYER met3 ;
      RECT 0.000 121.570 0.900 121.870 ;
    END
  END rw0_wd_in[45]
  PIN rw0_wd_in[46]
    DIRECTION INPUT ;
    USE SIGNAL ;
    SHAPE ABUTMENT ;
    PORT
      LAYER met3 ;
      RECT 0.000 122.250 0.900 122.550 ;
    END
  END rw0_wd_in[46]
  PIN rw0_wd_in[47]
    DIRECTION INPUT ;
    USE SIGNAL ;
    SHAPE ABUTMENT ;
    PORT
      LAYER met3 ;
      RECT 0.000 122.930 0.900 123.230 ;
    END
  END rw0_wd_in[47]
  PIN rw0_wd_in[48]
    DIRECTION INPUT ;
    USE SIGNAL ;
    SHAPE ABUTMENT ;
    PORT
      LAYER met3 ;
      RECT 0.000 123.610 0.900 123.910 ;
    END
  END rw0_wd_in[48]
  PIN rw0_wd_in[49]
    DIRECTION INPUT ;
    USE SIGNAL ;
    SHAPE ABUTMENT ;
    PORT
      LAYER met3 ;
      RECT 0.000 124.290 0.900 124.590 ;
    END
  END rw0_wd_in[49]
  PIN rw0_wd_in[50]
    DIRECTION INPUT ;
    USE SIGNAL ;
    SHAPE ABUTMENT ;
    PORT
      LAYER met3 ;
      RECT 0.000 124.970 0.900 125.270 ;
    END
  END rw0_wd_in[50]
  PIN rw0_wd_in[51]
    DIRECTION INPUT ;
    USE SIGNAL ;
    SHAPE ABUTMENT ;
    PORT
      LAYER met3 ;
      RECT 0.000 125.650 0.900 125.950 ;
    END
  END rw0_wd_in[51]
  PIN rw0_wd_in[52]
    DIRECTION INPUT ;
    USE SIGNAL ;
    SHAPE ABUTMENT ;
    PORT
      LAYER met3 ;
      RECT 0.000 126.330 0.900 126.630 ;
    END
  END rw0_wd_in[52]
  PIN rw0_wd_in[53]
    DIRECTION INPUT ;
    USE SIGNAL ;
    SHAPE ABUTMENT ;
    PORT
      LAYER met3 ;
      RECT 0.000 127.010 0.900 127.310 ;
    END
  END rw0_wd_in[53]
  PIN rw0_wd_in[54]
    DIRECTION INPUT ;
    USE SIGNAL ;
    SHAPE ABUTMENT ;
    PORT
      LAYER met3 ;
      RECT 0.000 127.690 0.900 127.990 ;
    END
  END rw0_wd_in[54]
  PIN rw0_wd_in[55]
    DIRECTION INPUT ;
    USE SIGNAL ;
    SHAPE ABUTMENT ;
    PORT
      LAYER met3 ;
      RECT 0.000 128.370 0.900 128.670 ;
    END
  END rw0_wd_in[55]
  PIN rw0_wd_in[56]
    DIRECTION INPUT ;
    USE SIGNAL ;
    SHAPE ABUTMENT ;
    PORT
      LAYER met3 ;
      RECT 0.000 129.050 0.900 129.350 ;
    END
  END rw0_wd_in[56]
  PIN rw0_wd_in[57]
    DIRECTION INPUT ;
    USE SIGNAL ;
    SHAPE ABUTMENT ;
    PORT
      LAYER met3 ;
      RECT 0.000 129.730 0.900 130.030 ;
    END
  END rw0_wd_in[57]
  PIN rw0_wd_in[58]
    DIRECTION INPUT ;
    USE SIGNAL ;
    SHAPE ABUTMENT ;
    PORT
      LAYER met3 ;
      RECT 0.000 130.410 0.900 130.710 ;
    END
  END rw0_wd_in[58]
  PIN rw0_wd_in[59]
    DIRECTION INPUT ;
    USE SIGNAL ;
    SHAPE ABUTMENT ;
    PORT
      LAYER met3 ;
      RECT 0.000 131.090 0.900 131.390 ;
    END
  END rw0_wd_in[59]
  PIN rw0_wd_in[60]
    DIRECTION INPUT ;
    USE SIGNAL ;
    SHAPE ABUTMENT ;
    PORT
      LAYER met3 ;
      RECT 0.000 131.770 0.900 132.070 ;
    END
  END rw0_wd_in[60]
  PIN rw0_wd_in[61]
    DIRECTION INPUT ;
    USE SIGNAL ;
    SHAPE ABUTMENT ;
    PORT
      LAYER met3 ;
      RECT 0.000 132.450 0.900 132.750 ;
    END
  END rw0_wd_in[61]
  PIN rw0_wd_in[62]
    DIRECTION INPUT ;
    USE SIGNAL ;
    SHAPE ABUTMENT ;
    PORT
      LAYER met3 ;
      RECT 0.000 133.130 0.900 133.430 ;
    END
  END rw0_wd_in[62]
  PIN rw0_wd_in[63]
    DIRECTION INPUT ;
    USE SIGNAL ;
    SHAPE ABUTMENT ;
    PORT
      LAYER met3 ;
      RECT 0.000 133.810 0.900 134.110 ;
    END
  END rw0_wd_in[63]
  PIN rw0_wd_in[64]
    DIRECTION INPUT ;
    USE SIGNAL ;
    SHAPE ABUTMENT ;
    PORT
      LAYER met3 ;
      RECT 0.000 134.490 0.900 134.790 ;
    END
  END rw0_wd_in[64]
  PIN rw0_wd_in[65]
    DIRECTION INPUT ;
    USE SIGNAL ;
    SHAPE ABUTMENT ;
    PORT
      LAYER met3 ;
      RECT 0.000 135.170 0.900 135.470 ;
    END
  END rw0_wd_in[65]
  PIN rw0_wd_in[66]
    DIRECTION INPUT ;
    USE SIGNAL ;
    SHAPE ABUTMENT ;
    PORT
      LAYER met3 ;
      RECT 0.000 135.850 0.900 136.150 ;
    END
  END rw0_wd_in[66]
  PIN rw0_wd_in[67]
    DIRECTION INPUT ;
    USE SIGNAL ;
    SHAPE ABUTMENT ;
    PORT
      LAYER met3 ;
      RECT 0.000 136.530 0.900 136.830 ;
    END
  END rw0_wd_in[67]
  PIN rw0_wd_in[68]
    DIRECTION INPUT ;
    USE SIGNAL ;
    SHAPE ABUTMENT ;
    PORT
      LAYER met3 ;
      RECT 0.000 137.210 0.900 137.510 ;
    END
  END rw0_wd_in[68]
  PIN rw0_wd_in[69]
    DIRECTION INPUT ;
    USE SIGNAL ;
    SHAPE ABUTMENT ;
    PORT
      LAYER met3 ;
      RECT 0.000 137.890 0.900 138.190 ;
    END
  END rw0_wd_in[69]
  PIN rw0_wd_in[70]
    DIRECTION INPUT ;
    USE SIGNAL ;
    SHAPE ABUTMENT ;
    PORT
      LAYER met3 ;
      RECT 0.000 138.570 0.900 138.870 ;
    END
  END rw0_wd_in[70]
  PIN rw0_wd_in[71]
    DIRECTION INPUT ;
    USE SIGNAL ;
    SHAPE ABUTMENT ;
    PORT
      LAYER met3 ;
      RECT 0.000 139.250 0.900 139.550 ;
    END
  END rw0_wd_in[71]
  PIN rw0_wd_in[72]
    DIRECTION INPUT ;
    USE SIGNAL ;
    SHAPE ABUTMENT ;
    PORT
      LAYER met3 ;
      RECT 0.000 139.930 0.900 140.230 ;
    END
  END rw0_wd_in[72]
  PIN rw0_wd_in[73]
    DIRECTION INPUT ;
    USE SIGNAL ;
    SHAPE ABUTMENT ;
    PORT
      LAYER met3 ;
      RECT 0.000 140.610 0.900 140.910 ;
    END
  END rw0_wd_in[73]
  PIN rw0_wd_in[74]
    DIRECTION INPUT ;
    USE SIGNAL ;
    SHAPE ABUTMENT ;
    PORT
      LAYER met3 ;
      RECT 0.000 141.290 0.900 141.590 ;
    END
  END rw0_wd_in[74]
  PIN rw0_wd_in[75]
    DIRECTION INPUT ;
    USE SIGNAL ;
    SHAPE ABUTMENT ;
    PORT
      LAYER met3 ;
      RECT 0.000 141.970 0.900 142.270 ;
    END
  END rw0_wd_in[75]
  PIN rw0_wd_in[76]
    DIRECTION INPUT ;
    USE SIGNAL ;
    SHAPE ABUTMENT ;
    PORT
      LAYER met3 ;
      RECT 0.000 142.650 0.900 142.950 ;
    END
  END rw0_wd_in[76]
  PIN rw0_wd_in[77]
    DIRECTION INPUT ;
    USE SIGNAL ;
    SHAPE ABUTMENT ;
    PORT
      LAYER met3 ;
      RECT 0.000 143.330 0.900 143.630 ;
    END
  END rw0_wd_in[77]
  PIN rw0_wd_in[78]
    DIRECTION INPUT ;
    USE SIGNAL ;
    SHAPE ABUTMENT ;
    PORT
      LAYER met3 ;
      RECT 0.000 144.010 0.900 144.310 ;
    END
  END rw0_wd_in[78]
  PIN rw0_wd_in[79]
    DIRECTION INPUT ;
    USE SIGNAL ;
    SHAPE ABUTMENT ;
    PORT
      LAYER met3 ;
      RECT 0.000 144.690 0.900 144.990 ;
    END
  END rw0_wd_in[79]
  PIN rw0_wd_in[80]
    DIRECTION INPUT ;
    USE SIGNAL ;
    SHAPE ABUTMENT ;
    PORT
      LAYER met3 ;
      RECT 0.000 145.370 0.900 145.670 ;
    END
  END rw0_wd_in[80]
  PIN rw0_wd_in[81]
    DIRECTION INPUT ;
    USE SIGNAL ;
    SHAPE ABUTMENT ;
    PORT
      LAYER met3 ;
      RECT 0.000 146.050 0.900 146.350 ;
    END
  END rw0_wd_in[81]
  PIN rw0_wd_in[82]
    DIRECTION INPUT ;
    USE SIGNAL ;
    SHAPE ABUTMENT ;
    PORT
      LAYER met3 ;
      RECT 0.000 146.730 0.900 147.030 ;
    END
  END rw0_wd_in[82]
  PIN rw0_wd_in[83]
    DIRECTION INPUT ;
    USE SIGNAL ;
    SHAPE ABUTMENT ;
    PORT
      LAYER met3 ;
      RECT 0.000 147.410 0.900 147.710 ;
    END
  END rw0_wd_in[83]
  PIN rw0_wd_in[84]
    DIRECTION INPUT ;
    USE SIGNAL ;
    SHAPE ABUTMENT ;
    PORT
      LAYER met3 ;
      RECT 0.000 148.090 0.900 148.390 ;
    END
  END rw0_wd_in[84]
  PIN rw0_wd_in[85]
    DIRECTION INPUT ;
    USE SIGNAL ;
    SHAPE ABUTMENT ;
    PORT
      LAYER met3 ;
      RECT 0.000 148.770 0.900 149.070 ;
    END
  END rw0_wd_in[85]
  PIN rw0_wd_in[86]
    DIRECTION INPUT ;
    USE SIGNAL ;
    SHAPE ABUTMENT ;
    PORT
      LAYER met3 ;
      RECT 0.000 149.450 0.900 149.750 ;
    END
  END rw0_wd_in[86]
  PIN rw0_wd_in[87]
    DIRECTION INPUT ;
    USE SIGNAL ;
    SHAPE ABUTMENT ;
    PORT
      LAYER met3 ;
      RECT 0.000 150.130 0.900 150.430 ;
    END
  END rw0_wd_in[87]
  PIN rw0_wd_in[88]
    DIRECTION INPUT ;
    USE SIGNAL ;
    SHAPE ABUTMENT ;
    PORT
      LAYER met3 ;
      RECT 0.000 150.810 0.900 151.110 ;
    END
  END rw0_wd_in[88]
  PIN rw0_wd_in[89]
    DIRECTION INPUT ;
    USE SIGNAL ;
    SHAPE ABUTMENT ;
    PORT
      LAYER met3 ;
      RECT 0.000 151.490 0.900 151.790 ;
    END
  END rw0_wd_in[89]
  PIN rw0_wd_in[90]
    DIRECTION INPUT ;
    USE SIGNAL ;
    SHAPE ABUTMENT ;
    PORT
      LAYER met3 ;
      RECT 0.000 152.170 0.900 152.470 ;
    END
  END rw0_wd_in[90]
  PIN rw0_wd_in[91]
    DIRECTION INPUT ;
    USE SIGNAL ;
    SHAPE ABUTMENT ;
    PORT
      LAYER met3 ;
      RECT 0.000 152.850 0.900 153.150 ;
    END
  END rw0_wd_in[91]
  PIN rw0_wd_in[92]
    DIRECTION INPUT ;
    USE SIGNAL ;
    SHAPE ABUTMENT ;
    PORT
      LAYER met3 ;
      RECT 0.000 153.530 0.900 153.830 ;
    END
  END rw0_wd_in[92]
  PIN rw0_wd_in[93]
    DIRECTION INPUT ;
    USE SIGNAL ;
    SHAPE ABUTMENT ;
    PORT
      LAYER met3 ;
      RECT 0.000 154.210 0.900 154.510 ;
    END
  END rw0_wd_in[93]
  PIN rw0_wd_in[94]
    DIRECTION INPUT ;
    USE SIGNAL ;
    SHAPE ABUTMENT ;
    PORT
      LAYER met3 ;
      RECT 0.000 154.890 0.900 155.190 ;
    END
  END rw0_wd_in[94]
  PIN rw0_wd_in[95]
    DIRECTION INPUT ;
    USE SIGNAL ;
    SHAPE ABUTMENT ;
    PORT
      LAYER met3 ;
      RECT 0.000 155.570 0.900 155.870 ;
    END
  END rw0_wd_in[95]
  PIN rw0_wd_in[96]
    DIRECTION INPUT ;
    USE SIGNAL ;
    SHAPE ABUTMENT ;
    PORT
      LAYER met3 ;
      RECT 0.000 156.250 0.900 156.550 ;
    END
  END rw0_wd_in[96]
  PIN rw0_wd_in[97]
    DIRECTION INPUT ;
    USE SIGNAL ;
    SHAPE ABUTMENT ;
    PORT
      LAYER met3 ;
      RECT 0.000 156.930 0.900 157.230 ;
    END
  END rw0_wd_in[97]
  PIN rw0_wd_in[98]
    DIRECTION INPUT ;
    USE SIGNAL ;
    SHAPE ABUTMENT ;
    PORT
      LAYER met3 ;
      RECT 0.000 157.610 0.900 157.910 ;
    END
  END rw0_wd_in[98]
  PIN rw0_wd_in[99]
    DIRECTION INPUT ;
    USE SIGNAL ;
    SHAPE ABUTMENT ;
    PORT
      LAYER met3 ;
      RECT 0.000 158.290 0.900 158.590 ;
    END
  END rw0_wd_in[99]
  PIN rw0_wd_in[100]
    DIRECTION INPUT ;
    USE SIGNAL ;
    SHAPE ABUTMENT ;
    PORT
      LAYER met3 ;
      RECT 0.000 158.970 0.900 159.270 ;
    END
  END rw0_wd_in[100]
  PIN rw0_wd_in[101]
    DIRECTION INPUT ;
    USE SIGNAL ;
    SHAPE ABUTMENT ;
    PORT
      LAYER met3 ;
      RECT 0.000 159.650 0.900 159.950 ;
    END
  END rw0_wd_in[101]
  PIN rw0_wd_in[102]
    DIRECTION INPUT ;
    USE SIGNAL ;
    SHAPE ABUTMENT ;
    PORT
      LAYER met3 ;
      RECT 0.000 160.330 0.900 160.630 ;
    END
  END rw0_wd_in[102]
  PIN rw0_wd_in[103]
    DIRECTION INPUT ;
    USE SIGNAL ;
    SHAPE ABUTMENT ;
    PORT
      LAYER met3 ;
      RECT 0.000 161.010 0.900 161.310 ;
    END
  END rw0_wd_in[103]
  PIN rw0_wd_in[104]
    DIRECTION INPUT ;
    USE SIGNAL ;
    SHAPE ABUTMENT ;
    PORT
      LAYER met3 ;
      RECT 0.000 161.690 0.900 161.990 ;
    END
  END rw0_wd_in[104]
  PIN rw0_wd_in[105]
    DIRECTION INPUT ;
    USE SIGNAL ;
    SHAPE ABUTMENT ;
    PORT
      LAYER met3 ;
      RECT 0.000 162.370 0.900 162.670 ;
    END
  END rw0_wd_in[105]
  PIN rw0_wd_in[106]
    DIRECTION INPUT ;
    USE SIGNAL ;
    SHAPE ABUTMENT ;
    PORT
      LAYER met3 ;
      RECT 0.000 163.050 0.900 163.350 ;
    END
  END rw0_wd_in[106]
  PIN rw0_wd_in[107]
    DIRECTION INPUT ;
    USE SIGNAL ;
    SHAPE ABUTMENT ;
    PORT
      LAYER met3 ;
      RECT 0.000 163.730 0.900 164.030 ;
    END
  END rw0_wd_in[107]
  PIN rw0_wd_in[108]
    DIRECTION INPUT ;
    USE SIGNAL ;
    SHAPE ABUTMENT ;
    PORT
      LAYER met3 ;
      RECT 0.000 164.410 0.900 164.710 ;
    END
  END rw0_wd_in[108]
  PIN rw0_wd_in[109]
    DIRECTION INPUT ;
    USE SIGNAL ;
    SHAPE ABUTMENT ;
    PORT
      LAYER met3 ;
      RECT 0.000 165.090 0.900 165.390 ;
    END
  END rw0_wd_in[109]
  PIN rw0_wd_in[110]
    DIRECTION INPUT ;
    USE SIGNAL ;
    SHAPE ABUTMENT ;
    PORT
      LAYER met3 ;
      RECT 0.000 165.770 0.900 166.070 ;
    END
  END rw0_wd_in[110]
  PIN rw0_wd_in[111]
    DIRECTION INPUT ;
    USE SIGNAL ;
    SHAPE ABUTMENT ;
    PORT
      LAYER met3 ;
      RECT 0.000 166.450 0.900 166.750 ;
    END
  END rw0_wd_in[111]
  PIN rw0_wd_in[112]
    DIRECTION INPUT ;
    USE SIGNAL ;
    SHAPE ABUTMENT ;
    PORT
      LAYER met3 ;
      RECT 0.000 167.130 0.900 167.430 ;
    END
  END rw0_wd_in[112]
  PIN rw0_wd_in[113]
    DIRECTION INPUT ;
    USE SIGNAL ;
    SHAPE ABUTMENT ;
    PORT
      LAYER met3 ;
      RECT 0.000 167.810 0.900 168.110 ;
    END
  END rw0_wd_in[113]
  PIN rw0_wd_in[114]
    DIRECTION INPUT ;
    USE SIGNAL ;
    SHAPE ABUTMENT ;
    PORT
      LAYER met3 ;
      RECT 0.000 168.490 0.900 168.790 ;
    END
  END rw0_wd_in[114]
  PIN rw0_wd_in[115]
    DIRECTION INPUT ;
    USE SIGNAL ;
    SHAPE ABUTMENT ;
    PORT
      LAYER met3 ;
      RECT 0.000 169.170 0.900 169.470 ;
    END
  END rw0_wd_in[115]
  PIN rw0_wd_in[116]
    DIRECTION INPUT ;
    USE SIGNAL ;
    SHAPE ABUTMENT ;
    PORT
      LAYER met3 ;
      RECT 0.000 169.850 0.900 170.150 ;
    END
  END rw0_wd_in[116]
  PIN rw0_wd_in[117]
    DIRECTION INPUT ;
    USE SIGNAL ;
    SHAPE ABUTMENT ;
    PORT
      LAYER met3 ;
      RECT 0.000 170.530 0.900 170.830 ;
    END
  END rw0_wd_in[117]
  PIN rw0_wd_in[118]
    DIRECTION INPUT ;
    USE SIGNAL ;
    SHAPE ABUTMENT ;
    PORT
      LAYER met3 ;
      RECT 0.000 171.210 0.900 171.510 ;
    END
  END rw0_wd_in[118]
  PIN rw0_wd_in[119]
    DIRECTION INPUT ;
    USE SIGNAL ;
    SHAPE ABUTMENT ;
    PORT
      LAYER met3 ;
      RECT 0.000 171.890 0.900 172.190 ;
    END
  END rw0_wd_in[119]
  PIN rw0_wd_in[120]
    DIRECTION INPUT ;
    USE SIGNAL ;
    SHAPE ABUTMENT ;
    PORT
      LAYER met3 ;
      RECT 0.000 172.570 0.900 172.870 ;
    END
  END rw0_wd_in[120]
  PIN rw0_wd_in[121]
    DIRECTION INPUT ;
    USE SIGNAL ;
    SHAPE ABUTMENT ;
    PORT
      LAYER met3 ;
      RECT 0.000 173.250 0.900 173.550 ;
    END
  END rw0_wd_in[121]
  PIN rw0_wd_in[122]
    DIRECTION INPUT ;
    USE SIGNAL ;
    SHAPE ABUTMENT ;
    PORT
      LAYER met3 ;
      RECT 0.000 173.930 0.900 174.230 ;
    END
  END rw0_wd_in[122]
  PIN rw0_wd_in[123]
    DIRECTION INPUT ;
    USE SIGNAL ;
    SHAPE ABUTMENT ;
    PORT
      LAYER met3 ;
      RECT 0.000 174.610 0.900 174.910 ;
    END
  END rw0_wd_in[123]
  PIN rw0_wd_in[124]
    DIRECTION INPUT ;
    USE SIGNAL ;
    SHAPE ABUTMENT ;
    PORT
      LAYER met3 ;
      RECT 0.000 175.290 0.900 175.590 ;
    END
  END rw0_wd_in[124]
  PIN rw0_wd_in[125]
    DIRECTION INPUT ;
    USE SIGNAL ;
    SHAPE ABUTMENT ;
    PORT
      LAYER met3 ;
      RECT 0.000 175.970 0.900 176.270 ;
    END
  END rw0_wd_in[125]
  PIN rw0_wd_in[126]
    DIRECTION INPUT ;
    USE SIGNAL ;
    SHAPE ABUTMENT ;
    PORT
      LAYER met3 ;
      RECT 0.000 176.650 0.900 176.950 ;
    END
  END rw0_wd_in[126]
  PIN rw0_wd_in[127]
    DIRECTION INPUT ;
    USE SIGNAL ;
    SHAPE ABUTMENT ;
    PORT
      LAYER met3 ;
      RECT 0.000 177.330 0.900 177.630 ;
    END
  END rw0_wd_in[127]
  PIN rw0_wd_in[128]
    DIRECTION INPUT ;
    USE SIGNAL ;
    SHAPE ABUTMENT ;
    PORT
      LAYER met3 ;
      RECT 1430.620 90.970 1431.520 91.270 ;
    END
  END rw0_wd_in[128]
  PIN rw0_wd_in[129]
    DIRECTION INPUT ;
    USE SIGNAL ;
    SHAPE ABUTMENT ;
    PORT
      LAYER met3 ;
      RECT 1430.620 91.650 1431.520 91.950 ;
    END
  END rw0_wd_in[129]
  PIN rw0_wd_in[130]
    DIRECTION INPUT ;
    USE SIGNAL ;
    SHAPE ABUTMENT ;
    PORT
      LAYER met3 ;
      RECT 1430.620 92.330 1431.520 92.630 ;
    END
  END rw0_wd_in[130]
  PIN rw0_wd_in[131]
    DIRECTION INPUT ;
    USE SIGNAL ;
    SHAPE ABUTMENT ;
    PORT
      LAYER met3 ;
      RECT 1430.620 93.010 1431.520 93.310 ;
    END
  END rw0_wd_in[131]
  PIN rw0_wd_in[132]
    DIRECTION INPUT ;
    USE SIGNAL ;
    SHAPE ABUTMENT ;
    PORT
      LAYER met3 ;
      RECT 1430.620 93.690 1431.520 93.990 ;
    END
  END rw0_wd_in[132]
  PIN rw0_wd_in[133]
    DIRECTION INPUT ;
    USE SIGNAL ;
    SHAPE ABUTMENT ;
    PORT
      LAYER met3 ;
      RECT 1430.620 94.370 1431.520 94.670 ;
    END
  END rw0_wd_in[133]
  PIN rw0_wd_in[134]
    DIRECTION INPUT ;
    USE SIGNAL ;
    SHAPE ABUTMENT ;
    PORT
      LAYER met3 ;
      RECT 1430.620 95.050 1431.520 95.350 ;
    END
  END rw0_wd_in[134]
  PIN rw0_wd_in[135]
    DIRECTION INPUT ;
    USE SIGNAL ;
    SHAPE ABUTMENT ;
    PORT
      LAYER met3 ;
      RECT 1430.620 95.730 1431.520 96.030 ;
    END
  END rw0_wd_in[135]
  PIN rw0_wd_in[136]
    DIRECTION INPUT ;
    USE SIGNAL ;
    SHAPE ABUTMENT ;
    PORT
      LAYER met3 ;
      RECT 1430.620 96.410 1431.520 96.710 ;
    END
  END rw0_wd_in[136]
  PIN rw0_wd_in[137]
    DIRECTION INPUT ;
    USE SIGNAL ;
    SHAPE ABUTMENT ;
    PORT
      LAYER met3 ;
      RECT 1430.620 97.090 1431.520 97.390 ;
    END
  END rw0_wd_in[137]
  PIN rw0_wd_in[138]
    DIRECTION INPUT ;
    USE SIGNAL ;
    SHAPE ABUTMENT ;
    PORT
      LAYER met3 ;
      RECT 1430.620 97.770 1431.520 98.070 ;
    END
  END rw0_wd_in[138]
  PIN rw0_wd_in[139]
    DIRECTION INPUT ;
    USE SIGNAL ;
    SHAPE ABUTMENT ;
    PORT
      LAYER met3 ;
      RECT 1430.620 98.450 1431.520 98.750 ;
    END
  END rw0_wd_in[139]
  PIN rw0_wd_in[140]
    DIRECTION INPUT ;
    USE SIGNAL ;
    SHAPE ABUTMENT ;
    PORT
      LAYER met3 ;
      RECT 1430.620 99.130 1431.520 99.430 ;
    END
  END rw0_wd_in[140]
  PIN rw0_wd_in[141]
    DIRECTION INPUT ;
    USE SIGNAL ;
    SHAPE ABUTMENT ;
    PORT
      LAYER met3 ;
      RECT 1430.620 99.810 1431.520 100.110 ;
    END
  END rw0_wd_in[141]
  PIN rw0_wd_in[142]
    DIRECTION INPUT ;
    USE SIGNAL ;
    SHAPE ABUTMENT ;
    PORT
      LAYER met3 ;
      RECT 1430.620 100.490 1431.520 100.790 ;
    END
  END rw0_wd_in[142]
  PIN rw0_wd_in[143]
    DIRECTION INPUT ;
    USE SIGNAL ;
    SHAPE ABUTMENT ;
    PORT
      LAYER met3 ;
      RECT 1430.620 101.170 1431.520 101.470 ;
    END
  END rw0_wd_in[143]
  PIN rw0_wd_in[144]
    DIRECTION INPUT ;
    USE SIGNAL ;
    SHAPE ABUTMENT ;
    PORT
      LAYER met3 ;
      RECT 1430.620 101.850 1431.520 102.150 ;
    END
  END rw0_wd_in[144]
  PIN rw0_wd_in[145]
    DIRECTION INPUT ;
    USE SIGNAL ;
    SHAPE ABUTMENT ;
    PORT
      LAYER met3 ;
      RECT 1430.620 102.530 1431.520 102.830 ;
    END
  END rw0_wd_in[145]
  PIN rw0_wd_in[146]
    DIRECTION INPUT ;
    USE SIGNAL ;
    SHAPE ABUTMENT ;
    PORT
      LAYER met3 ;
      RECT 1430.620 103.210 1431.520 103.510 ;
    END
  END rw0_wd_in[146]
  PIN rw0_wd_in[147]
    DIRECTION INPUT ;
    USE SIGNAL ;
    SHAPE ABUTMENT ;
    PORT
      LAYER met3 ;
      RECT 1430.620 103.890 1431.520 104.190 ;
    END
  END rw0_wd_in[147]
  PIN rw0_wd_in[148]
    DIRECTION INPUT ;
    USE SIGNAL ;
    SHAPE ABUTMENT ;
    PORT
      LAYER met3 ;
      RECT 1430.620 104.570 1431.520 104.870 ;
    END
  END rw0_wd_in[148]
  PIN rw0_wd_in[149]
    DIRECTION INPUT ;
    USE SIGNAL ;
    SHAPE ABUTMENT ;
    PORT
      LAYER met3 ;
      RECT 1430.620 105.250 1431.520 105.550 ;
    END
  END rw0_wd_in[149]
  PIN rw0_wd_in[150]
    DIRECTION INPUT ;
    USE SIGNAL ;
    SHAPE ABUTMENT ;
    PORT
      LAYER met3 ;
      RECT 1430.620 105.930 1431.520 106.230 ;
    END
  END rw0_wd_in[150]
  PIN rw0_wd_in[151]
    DIRECTION INPUT ;
    USE SIGNAL ;
    SHAPE ABUTMENT ;
    PORT
      LAYER met3 ;
      RECT 1430.620 106.610 1431.520 106.910 ;
    END
  END rw0_wd_in[151]
  PIN rw0_wd_in[152]
    DIRECTION INPUT ;
    USE SIGNAL ;
    SHAPE ABUTMENT ;
    PORT
      LAYER met3 ;
      RECT 1430.620 107.290 1431.520 107.590 ;
    END
  END rw0_wd_in[152]
  PIN rw0_wd_in[153]
    DIRECTION INPUT ;
    USE SIGNAL ;
    SHAPE ABUTMENT ;
    PORT
      LAYER met3 ;
      RECT 1430.620 107.970 1431.520 108.270 ;
    END
  END rw0_wd_in[153]
  PIN rw0_wd_in[154]
    DIRECTION INPUT ;
    USE SIGNAL ;
    SHAPE ABUTMENT ;
    PORT
      LAYER met3 ;
      RECT 1430.620 108.650 1431.520 108.950 ;
    END
  END rw0_wd_in[154]
  PIN rw0_wd_in[155]
    DIRECTION INPUT ;
    USE SIGNAL ;
    SHAPE ABUTMENT ;
    PORT
      LAYER met3 ;
      RECT 1430.620 109.330 1431.520 109.630 ;
    END
  END rw0_wd_in[155]
  PIN rw0_wd_in[156]
    DIRECTION INPUT ;
    USE SIGNAL ;
    SHAPE ABUTMENT ;
    PORT
      LAYER met3 ;
      RECT 1430.620 110.010 1431.520 110.310 ;
    END
  END rw0_wd_in[156]
  PIN rw0_wd_in[157]
    DIRECTION INPUT ;
    USE SIGNAL ;
    SHAPE ABUTMENT ;
    PORT
      LAYER met3 ;
      RECT 1430.620 110.690 1431.520 110.990 ;
    END
  END rw0_wd_in[157]
  PIN rw0_wd_in[158]
    DIRECTION INPUT ;
    USE SIGNAL ;
    SHAPE ABUTMENT ;
    PORT
      LAYER met3 ;
      RECT 1430.620 111.370 1431.520 111.670 ;
    END
  END rw0_wd_in[158]
  PIN rw0_wd_in[159]
    DIRECTION INPUT ;
    USE SIGNAL ;
    SHAPE ABUTMENT ;
    PORT
      LAYER met3 ;
      RECT 1430.620 112.050 1431.520 112.350 ;
    END
  END rw0_wd_in[159]
  PIN rw0_wd_in[160]
    DIRECTION INPUT ;
    USE SIGNAL ;
    SHAPE ABUTMENT ;
    PORT
      LAYER met3 ;
      RECT 1430.620 112.730 1431.520 113.030 ;
    END
  END rw0_wd_in[160]
  PIN rw0_wd_in[161]
    DIRECTION INPUT ;
    USE SIGNAL ;
    SHAPE ABUTMENT ;
    PORT
      LAYER met3 ;
      RECT 1430.620 113.410 1431.520 113.710 ;
    END
  END rw0_wd_in[161]
  PIN rw0_wd_in[162]
    DIRECTION INPUT ;
    USE SIGNAL ;
    SHAPE ABUTMENT ;
    PORT
      LAYER met3 ;
      RECT 1430.620 114.090 1431.520 114.390 ;
    END
  END rw0_wd_in[162]
  PIN rw0_wd_in[163]
    DIRECTION INPUT ;
    USE SIGNAL ;
    SHAPE ABUTMENT ;
    PORT
      LAYER met3 ;
      RECT 1430.620 114.770 1431.520 115.070 ;
    END
  END rw0_wd_in[163]
  PIN rw0_wd_in[164]
    DIRECTION INPUT ;
    USE SIGNAL ;
    SHAPE ABUTMENT ;
    PORT
      LAYER met3 ;
      RECT 1430.620 115.450 1431.520 115.750 ;
    END
  END rw0_wd_in[164]
  PIN rw0_wd_in[165]
    DIRECTION INPUT ;
    USE SIGNAL ;
    SHAPE ABUTMENT ;
    PORT
      LAYER met3 ;
      RECT 1430.620 116.130 1431.520 116.430 ;
    END
  END rw0_wd_in[165]
  PIN rw0_wd_in[166]
    DIRECTION INPUT ;
    USE SIGNAL ;
    SHAPE ABUTMENT ;
    PORT
      LAYER met3 ;
      RECT 1430.620 116.810 1431.520 117.110 ;
    END
  END rw0_wd_in[166]
  PIN rw0_wd_in[167]
    DIRECTION INPUT ;
    USE SIGNAL ;
    SHAPE ABUTMENT ;
    PORT
      LAYER met3 ;
      RECT 1430.620 117.490 1431.520 117.790 ;
    END
  END rw0_wd_in[167]
  PIN rw0_wd_in[168]
    DIRECTION INPUT ;
    USE SIGNAL ;
    SHAPE ABUTMENT ;
    PORT
      LAYER met3 ;
      RECT 1430.620 118.170 1431.520 118.470 ;
    END
  END rw0_wd_in[168]
  PIN rw0_wd_in[169]
    DIRECTION INPUT ;
    USE SIGNAL ;
    SHAPE ABUTMENT ;
    PORT
      LAYER met3 ;
      RECT 1430.620 118.850 1431.520 119.150 ;
    END
  END rw0_wd_in[169]
  PIN rw0_wd_in[170]
    DIRECTION INPUT ;
    USE SIGNAL ;
    SHAPE ABUTMENT ;
    PORT
      LAYER met3 ;
      RECT 1430.620 119.530 1431.520 119.830 ;
    END
  END rw0_wd_in[170]
  PIN rw0_wd_in[171]
    DIRECTION INPUT ;
    USE SIGNAL ;
    SHAPE ABUTMENT ;
    PORT
      LAYER met3 ;
      RECT 1430.620 120.210 1431.520 120.510 ;
    END
  END rw0_wd_in[171]
  PIN rw0_wd_in[172]
    DIRECTION INPUT ;
    USE SIGNAL ;
    SHAPE ABUTMENT ;
    PORT
      LAYER met3 ;
      RECT 1430.620 120.890 1431.520 121.190 ;
    END
  END rw0_wd_in[172]
  PIN rw0_wd_in[173]
    DIRECTION INPUT ;
    USE SIGNAL ;
    SHAPE ABUTMENT ;
    PORT
      LAYER met3 ;
      RECT 1430.620 121.570 1431.520 121.870 ;
    END
  END rw0_wd_in[173]
  PIN rw0_wd_in[174]
    DIRECTION INPUT ;
    USE SIGNAL ;
    SHAPE ABUTMENT ;
    PORT
      LAYER met3 ;
      RECT 1430.620 122.250 1431.520 122.550 ;
    END
  END rw0_wd_in[174]
  PIN rw0_wd_in[175]
    DIRECTION INPUT ;
    USE SIGNAL ;
    SHAPE ABUTMENT ;
    PORT
      LAYER met3 ;
      RECT 1430.620 122.930 1431.520 123.230 ;
    END
  END rw0_wd_in[175]
  PIN rw0_wd_in[176]
    DIRECTION INPUT ;
    USE SIGNAL ;
    SHAPE ABUTMENT ;
    PORT
      LAYER met3 ;
      RECT 1430.620 123.610 1431.520 123.910 ;
    END
  END rw0_wd_in[176]
  PIN rw0_wd_in[177]
    DIRECTION INPUT ;
    USE SIGNAL ;
    SHAPE ABUTMENT ;
    PORT
      LAYER met3 ;
      RECT 1430.620 124.290 1431.520 124.590 ;
    END
  END rw0_wd_in[177]
  PIN rw0_wd_in[178]
    DIRECTION INPUT ;
    USE SIGNAL ;
    SHAPE ABUTMENT ;
    PORT
      LAYER met3 ;
      RECT 1430.620 124.970 1431.520 125.270 ;
    END
  END rw0_wd_in[178]
  PIN rw0_wd_in[179]
    DIRECTION INPUT ;
    USE SIGNAL ;
    SHAPE ABUTMENT ;
    PORT
      LAYER met3 ;
      RECT 1430.620 125.650 1431.520 125.950 ;
    END
  END rw0_wd_in[179]
  PIN rw0_wd_in[180]
    DIRECTION INPUT ;
    USE SIGNAL ;
    SHAPE ABUTMENT ;
    PORT
      LAYER met3 ;
      RECT 1430.620 126.330 1431.520 126.630 ;
    END
  END rw0_wd_in[180]
  PIN rw0_wd_in[181]
    DIRECTION INPUT ;
    USE SIGNAL ;
    SHAPE ABUTMENT ;
    PORT
      LAYER met3 ;
      RECT 1430.620 127.010 1431.520 127.310 ;
    END
  END rw0_wd_in[181]
  PIN rw0_wd_in[182]
    DIRECTION INPUT ;
    USE SIGNAL ;
    SHAPE ABUTMENT ;
    PORT
      LAYER met3 ;
      RECT 1430.620 127.690 1431.520 127.990 ;
    END
  END rw0_wd_in[182]
  PIN rw0_wd_in[183]
    DIRECTION INPUT ;
    USE SIGNAL ;
    SHAPE ABUTMENT ;
    PORT
      LAYER met3 ;
      RECT 1430.620 128.370 1431.520 128.670 ;
    END
  END rw0_wd_in[183]
  PIN rw0_wd_in[184]
    DIRECTION INPUT ;
    USE SIGNAL ;
    SHAPE ABUTMENT ;
    PORT
      LAYER met3 ;
      RECT 1430.620 129.050 1431.520 129.350 ;
    END
  END rw0_wd_in[184]
  PIN rw0_wd_in[185]
    DIRECTION INPUT ;
    USE SIGNAL ;
    SHAPE ABUTMENT ;
    PORT
      LAYER met3 ;
      RECT 1430.620 129.730 1431.520 130.030 ;
    END
  END rw0_wd_in[185]
  PIN rw0_wd_in[186]
    DIRECTION INPUT ;
    USE SIGNAL ;
    SHAPE ABUTMENT ;
    PORT
      LAYER met3 ;
      RECT 1430.620 130.410 1431.520 130.710 ;
    END
  END rw0_wd_in[186]
  PIN rw0_wd_in[187]
    DIRECTION INPUT ;
    USE SIGNAL ;
    SHAPE ABUTMENT ;
    PORT
      LAYER met3 ;
      RECT 1430.620 131.090 1431.520 131.390 ;
    END
  END rw0_wd_in[187]
  PIN rw0_wd_in[188]
    DIRECTION INPUT ;
    USE SIGNAL ;
    SHAPE ABUTMENT ;
    PORT
      LAYER met3 ;
      RECT 1430.620 131.770 1431.520 132.070 ;
    END
  END rw0_wd_in[188]
  PIN rw0_wd_in[189]
    DIRECTION INPUT ;
    USE SIGNAL ;
    SHAPE ABUTMENT ;
    PORT
      LAYER met3 ;
      RECT 1430.620 132.450 1431.520 132.750 ;
    END
  END rw0_wd_in[189]
  PIN rw0_wd_in[190]
    DIRECTION INPUT ;
    USE SIGNAL ;
    SHAPE ABUTMENT ;
    PORT
      LAYER met3 ;
      RECT 1430.620 133.130 1431.520 133.430 ;
    END
  END rw0_wd_in[190]
  PIN rw0_wd_in[191]
    DIRECTION INPUT ;
    USE SIGNAL ;
    SHAPE ABUTMENT ;
    PORT
      LAYER met3 ;
      RECT 1430.620 133.810 1431.520 134.110 ;
    END
  END rw0_wd_in[191]
  PIN rw0_wd_in[192]
    DIRECTION INPUT ;
    USE SIGNAL ;
    SHAPE ABUTMENT ;
    PORT
      LAYER met3 ;
      RECT 1430.620 134.490 1431.520 134.790 ;
    END
  END rw0_wd_in[192]
  PIN rw0_wd_in[193]
    DIRECTION INPUT ;
    USE SIGNAL ;
    SHAPE ABUTMENT ;
    PORT
      LAYER met3 ;
      RECT 1430.620 135.170 1431.520 135.470 ;
    END
  END rw0_wd_in[193]
  PIN rw0_wd_in[194]
    DIRECTION INPUT ;
    USE SIGNAL ;
    SHAPE ABUTMENT ;
    PORT
      LAYER met3 ;
      RECT 1430.620 135.850 1431.520 136.150 ;
    END
  END rw0_wd_in[194]
  PIN rw0_wd_in[195]
    DIRECTION INPUT ;
    USE SIGNAL ;
    SHAPE ABUTMENT ;
    PORT
      LAYER met3 ;
      RECT 1430.620 136.530 1431.520 136.830 ;
    END
  END rw0_wd_in[195]
  PIN rw0_wd_in[196]
    DIRECTION INPUT ;
    USE SIGNAL ;
    SHAPE ABUTMENT ;
    PORT
      LAYER met3 ;
      RECT 1430.620 137.210 1431.520 137.510 ;
    END
  END rw0_wd_in[196]
  PIN rw0_wd_in[197]
    DIRECTION INPUT ;
    USE SIGNAL ;
    SHAPE ABUTMENT ;
    PORT
      LAYER met3 ;
      RECT 1430.620 137.890 1431.520 138.190 ;
    END
  END rw0_wd_in[197]
  PIN rw0_wd_in[198]
    DIRECTION INPUT ;
    USE SIGNAL ;
    SHAPE ABUTMENT ;
    PORT
      LAYER met3 ;
      RECT 1430.620 138.570 1431.520 138.870 ;
    END
  END rw0_wd_in[198]
  PIN rw0_wd_in[199]
    DIRECTION INPUT ;
    USE SIGNAL ;
    SHAPE ABUTMENT ;
    PORT
      LAYER met3 ;
      RECT 1430.620 139.250 1431.520 139.550 ;
    END
  END rw0_wd_in[199]
  PIN rw0_wd_in[200]
    DIRECTION INPUT ;
    USE SIGNAL ;
    SHAPE ABUTMENT ;
    PORT
      LAYER met3 ;
      RECT 1430.620 139.930 1431.520 140.230 ;
    END
  END rw0_wd_in[200]
  PIN rw0_wd_in[201]
    DIRECTION INPUT ;
    USE SIGNAL ;
    SHAPE ABUTMENT ;
    PORT
      LAYER met3 ;
      RECT 1430.620 140.610 1431.520 140.910 ;
    END
  END rw0_wd_in[201]
  PIN rw0_wd_in[202]
    DIRECTION INPUT ;
    USE SIGNAL ;
    SHAPE ABUTMENT ;
    PORT
      LAYER met3 ;
      RECT 1430.620 141.290 1431.520 141.590 ;
    END
  END rw0_wd_in[202]
  PIN rw0_wd_in[203]
    DIRECTION INPUT ;
    USE SIGNAL ;
    SHAPE ABUTMENT ;
    PORT
      LAYER met3 ;
      RECT 1430.620 141.970 1431.520 142.270 ;
    END
  END rw0_wd_in[203]
  PIN rw0_wd_in[204]
    DIRECTION INPUT ;
    USE SIGNAL ;
    SHAPE ABUTMENT ;
    PORT
      LAYER met3 ;
      RECT 1430.620 142.650 1431.520 142.950 ;
    END
  END rw0_wd_in[204]
  PIN rw0_wd_in[205]
    DIRECTION INPUT ;
    USE SIGNAL ;
    SHAPE ABUTMENT ;
    PORT
      LAYER met3 ;
      RECT 1430.620 143.330 1431.520 143.630 ;
    END
  END rw0_wd_in[205]
  PIN rw0_wd_in[206]
    DIRECTION INPUT ;
    USE SIGNAL ;
    SHAPE ABUTMENT ;
    PORT
      LAYER met3 ;
      RECT 1430.620 144.010 1431.520 144.310 ;
    END
  END rw0_wd_in[206]
  PIN rw0_wd_in[207]
    DIRECTION INPUT ;
    USE SIGNAL ;
    SHAPE ABUTMENT ;
    PORT
      LAYER met3 ;
      RECT 1430.620 144.690 1431.520 144.990 ;
    END
  END rw0_wd_in[207]
  PIN rw0_wd_in[208]
    DIRECTION INPUT ;
    USE SIGNAL ;
    SHAPE ABUTMENT ;
    PORT
      LAYER met3 ;
      RECT 1430.620 145.370 1431.520 145.670 ;
    END
  END rw0_wd_in[208]
  PIN rw0_wd_in[209]
    DIRECTION INPUT ;
    USE SIGNAL ;
    SHAPE ABUTMENT ;
    PORT
      LAYER met3 ;
      RECT 1430.620 146.050 1431.520 146.350 ;
    END
  END rw0_wd_in[209]
  PIN rw0_wd_in[210]
    DIRECTION INPUT ;
    USE SIGNAL ;
    SHAPE ABUTMENT ;
    PORT
      LAYER met3 ;
      RECT 1430.620 146.730 1431.520 147.030 ;
    END
  END rw0_wd_in[210]
  PIN rw0_wd_in[211]
    DIRECTION INPUT ;
    USE SIGNAL ;
    SHAPE ABUTMENT ;
    PORT
      LAYER met3 ;
      RECT 1430.620 147.410 1431.520 147.710 ;
    END
  END rw0_wd_in[211]
  PIN rw0_wd_in[212]
    DIRECTION INPUT ;
    USE SIGNAL ;
    SHAPE ABUTMENT ;
    PORT
      LAYER met3 ;
      RECT 1430.620 148.090 1431.520 148.390 ;
    END
  END rw0_wd_in[212]
  PIN rw0_wd_in[213]
    DIRECTION INPUT ;
    USE SIGNAL ;
    SHAPE ABUTMENT ;
    PORT
      LAYER met3 ;
      RECT 1430.620 148.770 1431.520 149.070 ;
    END
  END rw0_wd_in[213]
  PIN rw0_wd_in[214]
    DIRECTION INPUT ;
    USE SIGNAL ;
    SHAPE ABUTMENT ;
    PORT
      LAYER met3 ;
      RECT 1430.620 149.450 1431.520 149.750 ;
    END
  END rw0_wd_in[214]
  PIN rw0_wd_in[215]
    DIRECTION INPUT ;
    USE SIGNAL ;
    SHAPE ABUTMENT ;
    PORT
      LAYER met3 ;
      RECT 1430.620 150.130 1431.520 150.430 ;
    END
  END rw0_wd_in[215]
  PIN rw0_wd_in[216]
    DIRECTION INPUT ;
    USE SIGNAL ;
    SHAPE ABUTMENT ;
    PORT
      LAYER met3 ;
      RECT 1430.620 150.810 1431.520 151.110 ;
    END
  END rw0_wd_in[216]
  PIN rw0_wd_in[217]
    DIRECTION INPUT ;
    USE SIGNAL ;
    SHAPE ABUTMENT ;
    PORT
      LAYER met3 ;
      RECT 1430.620 151.490 1431.520 151.790 ;
    END
  END rw0_wd_in[217]
  PIN rw0_wd_in[218]
    DIRECTION INPUT ;
    USE SIGNAL ;
    SHAPE ABUTMENT ;
    PORT
      LAYER met3 ;
      RECT 1430.620 152.170 1431.520 152.470 ;
    END
  END rw0_wd_in[218]
  PIN rw0_wd_in[219]
    DIRECTION INPUT ;
    USE SIGNAL ;
    SHAPE ABUTMENT ;
    PORT
      LAYER met3 ;
      RECT 1430.620 152.850 1431.520 153.150 ;
    END
  END rw0_wd_in[219]
  PIN rw0_wd_in[220]
    DIRECTION INPUT ;
    USE SIGNAL ;
    SHAPE ABUTMENT ;
    PORT
      LAYER met3 ;
      RECT 1430.620 153.530 1431.520 153.830 ;
    END
  END rw0_wd_in[220]
  PIN rw0_wd_in[221]
    DIRECTION INPUT ;
    USE SIGNAL ;
    SHAPE ABUTMENT ;
    PORT
      LAYER met3 ;
      RECT 1430.620 154.210 1431.520 154.510 ;
    END
  END rw0_wd_in[221]
  PIN rw0_wd_in[222]
    DIRECTION INPUT ;
    USE SIGNAL ;
    SHAPE ABUTMENT ;
    PORT
      LAYER met3 ;
      RECT 1430.620 154.890 1431.520 155.190 ;
    END
  END rw0_wd_in[222]
  PIN rw0_wd_in[223]
    DIRECTION INPUT ;
    USE SIGNAL ;
    SHAPE ABUTMENT ;
    PORT
      LAYER met3 ;
      RECT 1430.620 155.570 1431.520 155.870 ;
    END
  END rw0_wd_in[223]
  PIN rw0_wd_in[224]
    DIRECTION INPUT ;
    USE SIGNAL ;
    SHAPE ABUTMENT ;
    PORT
      LAYER met3 ;
      RECT 1430.620 156.250 1431.520 156.550 ;
    END
  END rw0_wd_in[224]
  PIN rw0_wd_in[225]
    DIRECTION INPUT ;
    USE SIGNAL ;
    SHAPE ABUTMENT ;
    PORT
      LAYER met3 ;
      RECT 1430.620 156.930 1431.520 157.230 ;
    END
  END rw0_wd_in[225]
  PIN rw0_wd_in[226]
    DIRECTION INPUT ;
    USE SIGNAL ;
    SHAPE ABUTMENT ;
    PORT
      LAYER met3 ;
      RECT 1430.620 157.610 1431.520 157.910 ;
    END
  END rw0_wd_in[226]
  PIN rw0_wd_in[227]
    DIRECTION INPUT ;
    USE SIGNAL ;
    SHAPE ABUTMENT ;
    PORT
      LAYER met3 ;
      RECT 1430.620 158.290 1431.520 158.590 ;
    END
  END rw0_wd_in[227]
  PIN rw0_wd_in[228]
    DIRECTION INPUT ;
    USE SIGNAL ;
    SHAPE ABUTMENT ;
    PORT
      LAYER met3 ;
      RECT 1430.620 158.970 1431.520 159.270 ;
    END
  END rw0_wd_in[228]
  PIN rw0_wd_in[229]
    DIRECTION INPUT ;
    USE SIGNAL ;
    SHAPE ABUTMENT ;
    PORT
      LAYER met3 ;
      RECT 1430.620 159.650 1431.520 159.950 ;
    END
  END rw0_wd_in[229]
  PIN rw0_wd_in[230]
    DIRECTION INPUT ;
    USE SIGNAL ;
    SHAPE ABUTMENT ;
    PORT
      LAYER met3 ;
      RECT 1430.620 160.330 1431.520 160.630 ;
    END
  END rw0_wd_in[230]
  PIN rw0_wd_in[231]
    DIRECTION INPUT ;
    USE SIGNAL ;
    SHAPE ABUTMENT ;
    PORT
      LAYER met3 ;
      RECT 1430.620 161.010 1431.520 161.310 ;
    END
  END rw0_wd_in[231]
  PIN rw0_wd_in[232]
    DIRECTION INPUT ;
    USE SIGNAL ;
    SHAPE ABUTMENT ;
    PORT
      LAYER met3 ;
      RECT 1430.620 161.690 1431.520 161.990 ;
    END
  END rw0_wd_in[232]
  PIN rw0_wd_in[233]
    DIRECTION INPUT ;
    USE SIGNAL ;
    SHAPE ABUTMENT ;
    PORT
      LAYER met3 ;
      RECT 1430.620 162.370 1431.520 162.670 ;
    END
  END rw0_wd_in[233]
  PIN rw0_wd_in[234]
    DIRECTION INPUT ;
    USE SIGNAL ;
    SHAPE ABUTMENT ;
    PORT
      LAYER met3 ;
      RECT 1430.620 163.050 1431.520 163.350 ;
    END
  END rw0_wd_in[234]
  PIN rw0_wd_in[235]
    DIRECTION INPUT ;
    USE SIGNAL ;
    SHAPE ABUTMENT ;
    PORT
      LAYER met3 ;
      RECT 1430.620 163.730 1431.520 164.030 ;
    END
  END rw0_wd_in[235]
  PIN rw0_wd_in[236]
    DIRECTION INPUT ;
    USE SIGNAL ;
    SHAPE ABUTMENT ;
    PORT
      LAYER met3 ;
      RECT 1430.620 164.410 1431.520 164.710 ;
    END
  END rw0_wd_in[236]
  PIN rw0_wd_in[237]
    DIRECTION INPUT ;
    USE SIGNAL ;
    SHAPE ABUTMENT ;
    PORT
      LAYER met3 ;
      RECT 1430.620 165.090 1431.520 165.390 ;
    END
  END rw0_wd_in[237]
  PIN rw0_wd_in[238]
    DIRECTION INPUT ;
    USE SIGNAL ;
    SHAPE ABUTMENT ;
    PORT
      LAYER met3 ;
      RECT 1430.620 165.770 1431.520 166.070 ;
    END
  END rw0_wd_in[238]
  PIN rw0_wd_in[239]
    DIRECTION INPUT ;
    USE SIGNAL ;
    SHAPE ABUTMENT ;
    PORT
      LAYER met3 ;
      RECT 1430.620 166.450 1431.520 166.750 ;
    END
  END rw0_wd_in[239]
  PIN rw0_wd_in[240]
    DIRECTION INPUT ;
    USE SIGNAL ;
    SHAPE ABUTMENT ;
    PORT
      LAYER met3 ;
      RECT 1430.620 167.130 1431.520 167.430 ;
    END
  END rw0_wd_in[240]
  PIN rw0_wd_in[241]
    DIRECTION INPUT ;
    USE SIGNAL ;
    SHAPE ABUTMENT ;
    PORT
      LAYER met3 ;
      RECT 1430.620 167.810 1431.520 168.110 ;
    END
  END rw0_wd_in[241]
  PIN rw0_wd_in[242]
    DIRECTION INPUT ;
    USE SIGNAL ;
    SHAPE ABUTMENT ;
    PORT
      LAYER met3 ;
      RECT 1430.620 168.490 1431.520 168.790 ;
    END
  END rw0_wd_in[242]
  PIN rw0_wd_in[243]
    DIRECTION INPUT ;
    USE SIGNAL ;
    SHAPE ABUTMENT ;
    PORT
      LAYER met3 ;
      RECT 1430.620 169.170 1431.520 169.470 ;
    END
  END rw0_wd_in[243]
  PIN rw0_wd_in[244]
    DIRECTION INPUT ;
    USE SIGNAL ;
    SHAPE ABUTMENT ;
    PORT
      LAYER met3 ;
      RECT 1430.620 169.850 1431.520 170.150 ;
    END
  END rw0_wd_in[244]
  PIN rw0_wd_in[245]
    DIRECTION INPUT ;
    USE SIGNAL ;
    SHAPE ABUTMENT ;
    PORT
      LAYER met3 ;
      RECT 1430.620 170.530 1431.520 170.830 ;
    END
  END rw0_wd_in[245]
  PIN rw0_wd_in[246]
    DIRECTION INPUT ;
    USE SIGNAL ;
    SHAPE ABUTMENT ;
    PORT
      LAYER met3 ;
      RECT 1430.620 171.210 1431.520 171.510 ;
    END
  END rw0_wd_in[246]
  PIN rw0_wd_in[247]
    DIRECTION INPUT ;
    USE SIGNAL ;
    SHAPE ABUTMENT ;
    PORT
      LAYER met3 ;
      RECT 1430.620 171.890 1431.520 172.190 ;
    END
  END rw0_wd_in[247]
  PIN rw0_wd_in[248]
    DIRECTION INPUT ;
    USE SIGNAL ;
    SHAPE ABUTMENT ;
    PORT
      LAYER met3 ;
      RECT 1430.620 172.570 1431.520 172.870 ;
    END
  END rw0_wd_in[248]
  PIN rw0_wd_in[249]
    DIRECTION INPUT ;
    USE SIGNAL ;
    SHAPE ABUTMENT ;
    PORT
      LAYER met3 ;
      RECT 1430.620 173.250 1431.520 173.550 ;
    END
  END rw0_wd_in[249]
  PIN rw0_wd_in[250]
    DIRECTION INPUT ;
    USE SIGNAL ;
    SHAPE ABUTMENT ;
    PORT
      LAYER met3 ;
      RECT 1430.620 173.930 1431.520 174.230 ;
    END
  END rw0_wd_in[250]
  PIN rw0_wd_in[251]
    DIRECTION INPUT ;
    USE SIGNAL ;
    SHAPE ABUTMENT ;
    PORT
      LAYER met3 ;
      RECT 1430.620 174.610 1431.520 174.910 ;
    END
  END rw0_wd_in[251]
  PIN rw0_wd_in[252]
    DIRECTION INPUT ;
    USE SIGNAL ;
    SHAPE ABUTMENT ;
    PORT
      LAYER met3 ;
      RECT 1430.620 175.290 1431.520 175.590 ;
    END
  END rw0_wd_in[252]
  PIN rw0_wd_in[253]
    DIRECTION INPUT ;
    USE SIGNAL ;
    SHAPE ABUTMENT ;
    PORT
      LAYER met3 ;
      RECT 1430.620 175.970 1431.520 176.270 ;
    END
  END rw0_wd_in[253]
  PIN rw0_wd_in[254]
    DIRECTION INPUT ;
    USE SIGNAL ;
    SHAPE ABUTMENT ;
    PORT
      LAYER met3 ;
      RECT 1430.620 176.650 1431.520 176.950 ;
    END
  END rw0_wd_in[254]
  PIN rw0_wd_in[255]
    DIRECTION INPUT ;
    USE SIGNAL ;
    SHAPE ABUTMENT ;
    PORT
      LAYER met3 ;
      RECT 1430.620 177.330 1431.520 177.630 ;
    END
  END rw0_wd_in[255]
  PIN rw0_wd_in[256]
    DIRECTION INPUT ;
    USE SIGNAL ;
    SHAPE ABUTMENT ;
    PORT
      LAYER met2 ;
      RECT 2.690 0.000 2.830 0.420 ;
    END
  END rw0_wd_in[256]
  PIN rw0_wd_in[257]
    DIRECTION INPUT ;
    USE SIGNAL ;
    SHAPE ABUTMENT ;
    PORT
      LAYER met2 ;
      RECT 5.450 0.000 5.590 0.420 ;
    END
  END rw0_wd_in[257]
  PIN rw0_wd_in[258]
    DIRECTION INPUT ;
    USE SIGNAL ;
    SHAPE ABUTMENT ;
    PORT
      LAYER met2 ;
      RECT 8.210 0.000 8.350 0.420 ;
    END
  END rw0_wd_in[258]
  PIN rw0_wd_in[259]
    DIRECTION INPUT ;
    USE SIGNAL ;
    SHAPE ABUTMENT ;
    PORT
      LAYER met2 ;
      RECT 10.970 0.000 11.110 0.420 ;
    END
  END rw0_wd_in[259]
  PIN rw0_wd_in[260]
    DIRECTION INPUT ;
    USE SIGNAL ;
    SHAPE ABUTMENT ;
    PORT
      LAYER met2 ;
      RECT 13.730 0.000 13.870 0.420 ;
    END
  END rw0_wd_in[260]
  PIN rw0_wd_in[261]
    DIRECTION INPUT ;
    USE SIGNAL ;
    SHAPE ABUTMENT ;
    PORT
      LAYER met2 ;
      RECT 16.490 0.000 16.630 0.420 ;
    END
  END rw0_wd_in[261]
  PIN rw0_wd_in[262]
    DIRECTION INPUT ;
    USE SIGNAL ;
    SHAPE ABUTMENT ;
    PORT
      LAYER met2 ;
      RECT 19.250 0.000 19.390 0.420 ;
    END
  END rw0_wd_in[262]
  PIN rw0_wd_in[263]
    DIRECTION INPUT ;
    USE SIGNAL ;
    SHAPE ABUTMENT ;
    PORT
      LAYER met2 ;
      RECT 22.010 0.000 22.150 0.420 ;
    END
  END rw0_wd_in[263]
  PIN rw0_wd_in[264]
    DIRECTION INPUT ;
    USE SIGNAL ;
    SHAPE ABUTMENT ;
    PORT
      LAYER met2 ;
      RECT 24.770 0.000 24.910 0.420 ;
    END
  END rw0_wd_in[264]
  PIN rw0_wd_in[265]
    DIRECTION INPUT ;
    USE SIGNAL ;
    SHAPE ABUTMENT ;
    PORT
      LAYER met2 ;
      RECT 27.530 0.000 27.670 0.420 ;
    END
  END rw0_wd_in[265]
  PIN rw0_wd_in[266]
    DIRECTION INPUT ;
    USE SIGNAL ;
    SHAPE ABUTMENT ;
    PORT
      LAYER met2 ;
      RECT 30.290 0.000 30.430 0.420 ;
    END
  END rw0_wd_in[266]
  PIN rw0_wd_in[267]
    DIRECTION INPUT ;
    USE SIGNAL ;
    SHAPE ABUTMENT ;
    PORT
      LAYER met2 ;
      RECT 33.050 0.000 33.190 0.420 ;
    END
  END rw0_wd_in[267]
  PIN rw0_wd_in[268]
    DIRECTION INPUT ;
    USE SIGNAL ;
    SHAPE ABUTMENT ;
    PORT
      LAYER met2 ;
      RECT 35.810 0.000 35.950 0.420 ;
    END
  END rw0_wd_in[268]
  PIN rw0_wd_in[269]
    DIRECTION INPUT ;
    USE SIGNAL ;
    SHAPE ABUTMENT ;
    PORT
      LAYER met2 ;
      RECT 38.570 0.000 38.710 0.420 ;
    END
  END rw0_wd_in[269]
  PIN rw0_wd_in[270]
    DIRECTION INPUT ;
    USE SIGNAL ;
    SHAPE ABUTMENT ;
    PORT
      LAYER met2 ;
      RECT 41.330 0.000 41.470 0.420 ;
    END
  END rw0_wd_in[270]
  PIN rw0_wd_in[271]
    DIRECTION INPUT ;
    USE SIGNAL ;
    SHAPE ABUTMENT ;
    PORT
      LAYER met2 ;
      RECT 44.090 0.000 44.230 0.420 ;
    END
  END rw0_wd_in[271]
  PIN rw0_wd_in[272]
    DIRECTION INPUT ;
    USE SIGNAL ;
    SHAPE ABUTMENT ;
    PORT
      LAYER met2 ;
      RECT 46.850 0.000 46.990 0.420 ;
    END
  END rw0_wd_in[272]
  PIN rw0_wd_in[273]
    DIRECTION INPUT ;
    USE SIGNAL ;
    SHAPE ABUTMENT ;
    PORT
      LAYER met2 ;
      RECT 49.610 0.000 49.750 0.420 ;
    END
  END rw0_wd_in[273]
  PIN rw0_wd_in[274]
    DIRECTION INPUT ;
    USE SIGNAL ;
    SHAPE ABUTMENT ;
    PORT
      LAYER met2 ;
      RECT 52.370 0.000 52.510 0.420 ;
    END
  END rw0_wd_in[274]
  PIN rw0_wd_in[275]
    DIRECTION INPUT ;
    USE SIGNAL ;
    SHAPE ABUTMENT ;
    PORT
      LAYER met2 ;
      RECT 55.130 0.000 55.270 0.420 ;
    END
  END rw0_wd_in[275]
  PIN rw0_wd_in[276]
    DIRECTION INPUT ;
    USE SIGNAL ;
    SHAPE ABUTMENT ;
    PORT
      LAYER met2 ;
      RECT 57.890 0.000 58.030 0.420 ;
    END
  END rw0_wd_in[276]
  PIN rw0_wd_in[277]
    DIRECTION INPUT ;
    USE SIGNAL ;
    SHAPE ABUTMENT ;
    PORT
      LAYER met2 ;
      RECT 60.650 0.000 60.790 0.420 ;
    END
  END rw0_wd_in[277]
  PIN rw0_wd_in[278]
    DIRECTION INPUT ;
    USE SIGNAL ;
    SHAPE ABUTMENT ;
    PORT
      LAYER met2 ;
      RECT 63.410 0.000 63.550 0.420 ;
    END
  END rw0_wd_in[278]
  PIN rw0_wd_in[279]
    DIRECTION INPUT ;
    USE SIGNAL ;
    SHAPE ABUTMENT ;
    PORT
      LAYER met2 ;
      RECT 66.170 0.000 66.310 0.420 ;
    END
  END rw0_wd_in[279]
  PIN rw0_wd_in[280]
    DIRECTION INPUT ;
    USE SIGNAL ;
    SHAPE ABUTMENT ;
    PORT
      LAYER met2 ;
      RECT 68.930 0.000 69.070 0.420 ;
    END
  END rw0_wd_in[280]
  PIN rw0_wd_in[281]
    DIRECTION INPUT ;
    USE SIGNAL ;
    SHAPE ABUTMENT ;
    PORT
      LAYER met2 ;
      RECT 71.690 0.000 71.830 0.420 ;
    END
  END rw0_wd_in[281]
  PIN rw0_wd_in[282]
    DIRECTION INPUT ;
    USE SIGNAL ;
    SHAPE ABUTMENT ;
    PORT
      LAYER met2 ;
      RECT 74.450 0.000 74.590 0.420 ;
    END
  END rw0_wd_in[282]
  PIN rw0_wd_in[283]
    DIRECTION INPUT ;
    USE SIGNAL ;
    SHAPE ABUTMENT ;
    PORT
      LAYER met2 ;
      RECT 77.210 0.000 77.350 0.420 ;
    END
  END rw0_wd_in[283]
  PIN rw0_wd_in[284]
    DIRECTION INPUT ;
    USE SIGNAL ;
    SHAPE ABUTMENT ;
    PORT
      LAYER met2 ;
      RECT 79.970 0.000 80.110 0.420 ;
    END
  END rw0_wd_in[284]
  PIN rw0_wd_in[285]
    DIRECTION INPUT ;
    USE SIGNAL ;
    SHAPE ABUTMENT ;
    PORT
      LAYER met2 ;
      RECT 82.730 0.000 82.870 0.420 ;
    END
  END rw0_wd_in[285]
  PIN rw0_wd_in[286]
    DIRECTION INPUT ;
    USE SIGNAL ;
    SHAPE ABUTMENT ;
    PORT
      LAYER met2 ;
      RECT 85.490 0.000 85.630 0.420 ;
    END
  END rw0_wd_in[286]
  PIN rw0_wd_in[287]
    DIRECTION INPUT ;
    USE SIGNAL ;
    SHAPE ABUTMENT ;
    PORT
      LAYER met2 ;
      RECT 88.250 0.000 88.390 0.420 ;
    END
  END rw0_wd_in[287]
  PIN rw0_wd_in[288]
    DIRECTION INPUT ;
    USE SIGNAL ;
    SHAPE ABUTMENT ;
    PORT
      LAYER met2 ;
      RECT 91.010 0.000 91.150 0.420 ;
    END
  END rw0_wd_in[288]
  PIN rw0_wd_in[289]
    DIRECTION INPUT ;
    USE SIGNAL ;
    SHAPE ABUTMENT ;
    PORT
      LAYER met2 ;
      RECT 93.770 0.000 93.910 0.420 ;
    END
  END rw0_wd_in[289]
  PIN rw0_wd_in[290]
    DIRECTION INPUT ;
    USE SIGNAL ;
    SHAPE ABUTMENT ;
    PORT
      LAYER met2 ;
      RECT 96.530 0.000 96.670 0.420 ;
    END
  END rw0_wd_in[290]
  PIN rw0_wd_in[291]
    DIRECTION INPUT ;
    USE SIGNAL ;
    SHAPE ABUTMENT ;
    PORT
      LAYER met2 ;
      RECT 99.290 0.000 99.430 0.420 ;
    END
  END rw0_wd_in[291]
  PIN rw0_wd_in[292]
    DIRECTION INPUT ;
    USE SIGNAL ;
    SHAPE ABUTMENT ;
    PORT
      LAYER met2 ;
      RECT 102.050 0.000 102.190 0.420 ;
    END
  END rw0_wd_in[292]
  PIN rw0_wd_in[293]
    DIRECTION INPUT ;
    USE SIGNAL ;
    SHAPE ABUTMENT ;
    PORT
      LAYER met2 ;
      RECT 104.810 0.000 104.950 0.420 ;
    END
  END rw0_wd_in[293]
  PIN rw0_wd_in[294]
    DIRECTION INPUT ;
    USE SIGNAL ;
    SHAPE ABUTMENT ;
    PORT
      LAYER met2 ;
      RECT 107.570 0.000 107.710 0.420 ;
    END
  END rw0_wd_in[294]
  PIN rw0_wd_in[295]
    DIRECTION INPUT ;
    USE SIGNAL ;
    SHAPE ABUTMENT ;
    PORT
      LAYER met2 ;
      RECT 110.330 0.000 110.470 0.420 ;
    END
  END rw0_wd_in[295]
  PIN rw0_wd_in[296]
    DIRECTION INPUT ;
    USE SIGNAL ;
    SHAPE ABUTMENT ;
    PORT
      LAYER met2 ;
      RECT 113.090 0.000 113.230 0.420 ;
    END
  END rw0_wd_in[296]
  PIN rw0_wd_in[297]
    DIRECTION INPUT ;
    USE SIGNAL ;
    SHAPE ABUTMENT ;
    PORT
      LAYER met2 ;
      RECT 115.850 0.000 115.990 0.420 ;
    END
  END rw0_wd_in[297]
  PIN rw0_wd_in[298]
    DIRECTION INPUT ;
    USE SIGNAL ;
    SHAPE ABUTMENT ;
    PORT
      LAYER met2 ;
      RECT 118.610 0.000 118.750 0.420 ;
    END
  END rw0_wd_in[298]
  PIN rw0_wd_in[299]
    DIRECTION INPUT ;
    USE SIGNAL ;
    SHAPE ABUTMENT ;
    PORT
      LAYER met2 ;
      RECT 121.370 0.000 121.510 0.420 ;
    END
  END rw0_wd_in[299]
  PIN rw0_wd_in[300]
    DIRECTION INPUT ;
    USE SIGNAL ;
    SHAPE ABUTMENT ;
    PORT
      LAYER met2 ;
      RECT 124.130 0.000 124.270 0.420 ;
    END
  END rw0_wd_in[300]
  PIN rw0_wd_in[301]
    DIRECTION INPUT ;
    USE SIGNAL ;
    SHAPE ABUTMENT ;
    PORT
      LAYER met2 ;
      RECT 126.890 0.000 127.030 0.420 ;
    END
  END rw0_wd_in[301]
  PIN rw0_wd_in[302]
    DIRECTION INPUT ;
    USE SIGNAL ;
    SHAPE ABUTMENT ;
    PORT
      LAYER met2 ;
      RECT 129.650 0.000 129.790 0.420 ;
    END
  END rw0_wd_in[302]
  PIN rw0_wd_in[303]
    DIRECTION INPUT ;
    USE SIGNAL ;
    SHAPE ABUTMENT ;
    PORT
      LAYER met2 ;
      RECT 132.410 0.000 132.550 0.420 ;
    END
  END rw0_wd_in[303]
  PIN rw0_wd_in[304]
    DIRECTION INPUT ;
    USE SIGNAL ;
    SHAPE ABUTMENT ;
    PORT
      LAYER met2 ;
      RECT 135.170 0.000 135.310 0.420 ;
    END
  END rw0_wd_in[304]
  PIN rw0_wd_in[305]
    DIRECTION INPUT ;
    USE SIGNAL ;
    SHAPE ABUTMENT ;
    PORT
      LAYER met2 ;
      RECT 137.930 0.000 138.070 0.420 ;
    END
  END rw0_wd_in[305]
  PIN rw0_wd_in[306]
    DIRECTION INPUT ;
    USE SIGNAL ;
    SHAPE ABUTMENT ;
    PORT
      LAYER met2 ;
      RECT 140.690 0.000 140.830 0.420 ;
    END
  END rw0_wd_in[306]
  PIN rw0_wd_in[307]
    DIRECTION INPUT ;
    USE SIGNAL ;
    SHAPE ABUTMENT ;
    PORT
      LAYER met2 ;
      RECT 143.450 0.000 143.590 0.420 ;
    END
  END rw0_wd_in[307]
  PIN rw0_wd_in[308]
    DIRECTION INPUT ;
    USE SIGNAL ;
    SHAPE ABUTMENT ;
    PORT
      LAYER met2 ;
      RECT 146.210 0.000 146.350 0.420 ;
    END
  END rw0_wd_in[308]
  PIN rw0_wd_in[309]
    DIRECTION INPUT ;
    USE SIGNAL ;
    SHAPE ABUTMENT ;
    PORT
      LAYER met2 ;
      RECT 148.970 0.000 149.110 0.420 ;
    END
  END rw0_wd_in[309]
  PIN rw0_wd_in[310]
    DIRECTION INPUT ;
    USE SIGNAL ;
    SHAPE ABUTMENT ;
    PORT
      LAYER met2 ;
      RECT 151.730 0.000 151.870 0.420 ;
    END
  END rw0_wd_in[310]
  PIN rw0_wd_in[311]
    DIRECTION INPUT ;
    USE SIGNAL ;
    SHAPE ABUTMENT ;
    PORT
      LAYER met2 ;
      RECT 154.490 0.000 154.630 0.420 ;
    END
  END rw0_wd_in[311]
  PIN rw0_wd_in[312]
    DIRECTION INPUT ;
    USE SIGNAL ;
    SHAPE ABUTMENT ;
    PORT
      LAYER met2 ;
      RECT 157.250 0.000 157.390 0.420 ;
    END
  END rw0_wd_in[312]
  PIN rw0_wd_in[313]
    DIRECTION INPUT ;
    USE SIGNAL ;
    SHAPE ABUTMENT ;
    PORT
      LAYER met2 ;
      RECT 160.010 0.000 160.150 0.420 ;
    END
  END rw0_wd_in[313]
  PIN rw0_wd_in[314]
    DIRECTION INPUT ;
    USE SIGNAL ;
    SHAPE ABUTMENT ;
    PORT
      LAYER met2 ;
      RECT 162.770 0.000 162.910 0.420 ;
    END
  END rw0_wd_in[314]
  PIN rw0_wd_in[315]
    DIRECTION INPUT ;
    USE SIGNAL ;
    SHAPE ABUTMENT ;
    PORT
      LAYER met2 ;
      RECT 165.530 0.000 165.670 0.420 ;
    END
  END rw0_wd_in[315]
  PIN rw0_wd_in[316]
    DIRECTION INPUT ;
    USE SIGNAL ;
    SHAPE ABUTMENT ;
    PORT
      LAYER met2 ;
      RECT 168.290 0.000 168.430 0.420 ;
    END
  END rw0_wd_in[316]
  PIN rw0_wd_in[317]
    DIRECTION INPUT ;
    USE SIGNAL ;
    SHAPE ABUTMENT ;
    PORT
      LAYER met2 ;
      RECT 171.050 0.000 171.190 0.420 ;
    END
  END rw0_wd_in[317]
  PIN rw0_wd_in[318]
    DIRECTION INPUT ;
    USE SIGNAL ;
    SHAPE ABUTMENT ;
    PORT
      LAYER met2 ;
      RECT 173.810 0.000 173.950 0.420 ;
    END
  END rw0_wd_in[318]
  PIN rw0_wd_in[319]
    DIRECTION INPUT ;
    USE SIGNAL ;
    SHAPE ABUTMENT ;
    PORT
      LAYER met2 ;
      RECT 176.570 0.000 176.710 0.420 ;
    END
  END rw0_wd_in[319]
  PIN rw0_wd_in[320]
    DIRECTION INPUT ;
    USE SIGNAL ;
    SHAPE ABUTMENT ;
    PORT
      LAYER met2 ;
      RECT 179.330 0.000 179.470 0.420 ;
    END
  END rw0_wd_in[320]
  PIN rw0_wd_in[321]
    DIRECTION INPUT ;
    USE SIGNAL ;
    SHAPE ABUTMENT ;
    PORT
      LAYER met2 ;
      RECT 182.090 0.000 182.230 0.420 ;
    END
  END rw0_wd_in[321]
  PIN rw0_wd_in[322]
    DIRECTION INPUT ;
    USE SIGNAL ;
    SHAPE ABUTMENT ;
    PORT
      LAYER met2 ;
      RECT 184.850 0.000 184.990 0.420 ;
    END
  END rw0_wd_in[322]
  PIN rw0_wd_in[323]
    DIRECTION INPUT ;
    USE SIGNAL ;
    SHAPE ABUTMENT ;
    PORT
      LAYER met2 ;
      RECT 187.610 0.000 187.750 0.420 ;
    END
  END rw0_wd_in[323]
  PIN rw0_wd_in[324]
    DIRECTION INPUT ;
    USE SIGNAL ;
    SHAPE ABUTMENT ;
    PORT
      LAYER met2 ;
      RECT 190.370 0.000 190.510 0.420 ;
    END
  END rw0_wd_in[324]
  PIN rw0_wd_in[325]
    DIRECTION INPUT ;
    USE SIGNAL ;
    SHAPE ABUTMENT ;
    PORT
      LAYER met2 ;
      RECT 193.130 0.000 193.270 0.420 ;
    END
  END rw0_wd_in[325]
  PIN rw0_wd_in[326]
    DIRECTION INPUT ;
    USE SIGNAL ;
    SHAPE ABUTMENT ;
    PORT
      LAYER met2 ;
      RECT 195.890 0.000 196.030 0.420 ;
    END
  END rw0_wd_in[326]
  PIN rw0_wd_in[327]
    DIRECTION INPUT ;
    USE SIGNAL ;
    SHAPE ABUTMENT ;
    PORT
      LAYER met2 ;
      RECT 198.650 0.000 198.790 0.420 ;
    END
  END rw0_wd_in[327]
  PIN rw0_wd_in[328]
    DIRECTION INPUT ;
    USE SIGNAL ;
    SHAPE ABUTMENT ;
    PORT
      LAYER met2 ;
      RECT 201.410 0.000 201.550 0.420 ;
    END
  END rw0_wd_in[328]
  PIN rw0_wd_in[329]
    DIRECTION INPUT ;
    USE SIGNAL ;
    SHAPE ABUTMENT ;
    PORT
      LAYER met2 ;
      RECT 204.170 0.000 204.310 0.420 ;
    END
  END rw0_wd_in[329]
  PIN rw0_wd_in[330]
    DIRECTION INPUT ;
    USE SIGNAL ;
    SHAPE ABUTMENT ;
    PORT
      LAYER met2 ;
      RECT 206.930 0.000 207.070 0.420 ;
    END
  END rw0_wd_in[330]
  PIN rw0_wd_in[331]
    DIRECTION INPUT ;
    USE SIGNAL ;
    SHAPE ABUTMENT ;
    PORT
      LAYER met2 ;
      RECT 209.690 0.000 209.830 0.420 ;
    END
  END rw0_wd_in[331]
  PIN rw0_wd_in[332]
    DIRECTION INPUT ;
    USE SIGNAL ;
    SHAPE ABUTMENT ;
    PORT
      LAYER met2 ;
      RECT 212.450 0.000 212.590 0.420 ;
    END
  END rw0_wd_in[332]
  PIN rw0_wd_in[333]
    DIRECTION INPUT ;
    USE SIGNAL ;
    SHAPE ABUTMENT ;
    PORT
      LAYER met2 ;
      RECT 215.210 0.000 215.350 0.420 ;
    END
  END rw0_wd_in[333]
  PIN rw0_wd_in[334]
    DIRECTION INPUT ;
    USE SIGNAL ;
    SHAPE ABUTMENT ;
    PORT
      LAYER met2 ;
      RECT 217.970 0.000 218.110 0.420 ;
    END
  END rw0_wd_in[334]
  PIN rw0_wd_in[335]
    DIRECTION INPUT ;
    USE SIGNAL ;
    SHAPE ABUTMENT ;
    PORT
      LAYER met2 ;
      RECT 220.730 0.000 220.870 0.420 ;
    END
  END rw0_wd_in[335]
  PIN rw0_wd_in[336]
    DIRECTION INPUT ;
    USE SIGNAL ;
    SHAPE ABUTMENT ;
    PORT
      LAYER met2 ;
      RECT 223.490 0.000 223.630 0.420 ;
    END
  END rw0_wd_in[336]
  PIN rw0_wd_in[337]
    DIRECTION INPUT ;
    USE SIGNAL ;
    SHAPE ABUTMENT ;
    PORT
      LAYER met2 ;
      RECT 226.250 0.000 226.390 0.420 ;
    END
  END rw0_wd_in[337]
  PIN rw0_wd_in[338]
    DIRECTION INPUT ;
    USE SIGNAL ;
    SHAPE ABUTMENT ;
    PORT
      LAYER met2 ;
      RECT 229.010 0.000 229.150 0.420 ;
    END
  END rw0_wd_in[338]
  PIN rw0_wd_in[339]
    DIRECTION INPUT ;
    USE SIGNAL ;
    SHAPE ABUTMENT ;
    PORT
      LAYER met2 ;
      RECT 231.770 0.000 231.910 0.420 ;
    END
  END rw0_wd_in[339]
  PIN rw0_wd_in[340]
    DIRECTION INPUT ;
    USE SIGNAL ;
    SHAPE ABUTMENT ;
    PORT
      LAYER met2 ;
      RECT 234.530 0.000 234.670 0.420 ;
    END
  END rw0_wd_in[340]
  PIN rw0_wd_in[341]
    DIRECTION INPUT ;
    USE SIGNAL ;
    SHAPE ABUTMENT ;
    PORT
      LAYER met2 ;
      RECT 237.290 0.000 237.430 0.420 ;
    END
  END rw0_wd_in[341]
  PIN rw0_wd_in[342]
    DIRECTION INPUT ;
    USE SIGNAL ;
    SHAPE ABUTMENT ;
    PORT
      LAYER met2 ;
      RECT 240.050 0.000 240.190 0.420 ;
    END
  END rw0_wd_in[342]
  PIN rw0_wd_in[343]
    DIRECTION INPUT ;
    USE SIGNAL ;
    SHAPE ABUTMENT ;
    PORT
      LAYER met2 ;
      RECT 242.810 0.000 242.950 0.420 ;
    END
  END rw0_wd_in[343]
  PIN rw0_wd_in[344]
    DIRECTION INPUT ;
    USE SIGNAL ;
    SHAPE ABUTMENT ;
    PORT
      LAYER met2 ;
      RECT 245.570 0.000 245.710 0.420 ;
    END
  END rw0_wd_in[344]
  PIN rw0_wd_in[345]
    DIRECTION INPUT ;
    USE SIGNAL ;
    SHAPE ABUTMENT ;
    PORT
      LAYER met2 ;
      RECT 248.330 0.000 248.470 0.420 ;
    END
  END rw0_wd_in[345]
  PIN rw0_wd_in[346]
    DIRECTION INPUT ;
    USE SIGNAL ;
    SHAPE ABUTMENT ;
    PORT
      LAYER met2 ;
      RECT 251.090 0.000 251.230 0.420 ;
    END
  END rw0_wd_in[346]
  PIN rw0_wd_in[347]
    DIRECTION INPUT ;
    USE SIGNAL ;
    SHAPE ABUTMENT ;
    PORT
      LAYER met2 ;
      RECT 253.850 0.000 253.990 0.420 ;
    END
  END rw0_wd_in[347]
  PIN rw0_wd_in[348]
    DIRECTION INPUT ;
    USE SIGNAL ;
    SHAPE ABUTMENT ;
    PORT
      LAYER met2 ;
      RECT 256.610 0.000 256.750 0.420 ;
    END
  END rw0_wd_in[348]
  PIN rw0_wd_in[349]
    DIRECTION INPUT ;
    USE SIGNAL ;
    SHAPE ABUTMENT ;
    PORT
      LAYER met2 ;
      RECT 259.370 0.000 259.510 0.420 ;
    END
  END rw0_wd_in[349]
  PIN rw0_wd_in[350]
    DIRECTION INPUT ;
    USE SIGNAL ;
    SHAPE ABUTMENT ;
    PORT
      LAYER met2 ;
      RECT 262.130 0.000 262.270 0.420 ;
    END
  END rw0_wd_in[350]
  PIN rw0_wd_in[351]
    DIRECTION INPUT ;
    USE SIGNAL ;
    SHAPE ABUTMENT ;
    PORT
      LAYER met2 ;
      RECT 264.890 0.000 265.030 0.420 ;
    END
  END rw0_wd_in[351]
  PIN rw0_wd_in[352]
    DIRECTION INPUT ;
    USE SIGNAL ;
    SHAPE ABUTMENT ;
    PORT
      LAYER met2 ;
      RECT 267.650 0.000 267.790 0.420 ;
    END
  END rw0_wd_in[352]
  PIN rw0_wd_in[353]
    DIRECTION INPUT ;
    USE SIGNAL ;
    SHAPE ABUTMENT ;
    PORT
      LAYER met2 ;
      RECT 270.410 0.000 270.550 0.420 ;
    END
  END rw0_wd_in[353]
  PIN rw0_wd_in[354]
    DIRECTION INPUT ;
    USE SIGNAL ;
    SHAPE ABUTMENT ;
    PORT
      LAYER met2 ;
      RECT 273.170 0.000 273.310 0.420 ;
    END
  END rw0_wd_in[354]
  PIN rw0_wd_in[355]
    DIRECTION INPUT ;
    USE SIGNAL ;
    SHAPE ABUTMENT ;
    PORT
      LAYER met2 ;
      RECT 275.930 0.000 276.070 0.420 ;
    END
  END rw0_wd_in[355]
  PIN rw0_wd_in[356]
    DIRECTION INPUT ;
    USE SIGNAL ;
    SHAPE ABUTMENT ;
    PORT
      LAYER met2 ;
      RECT 278.690 0.000 278.830 0.420 ;
    END
  END rw0_wd_in[356]
  PIN rw0_wd_in[357]
    DIRECTION INPUT ;
    USE SIGNAL ;
    SHAPE ABUTMENT ;
    PORT
      LAYER met2 ;
      RECT 281.450 0.000 281.590 0.420 ;
    END
  END rw0_wd_in[357]
  PIN rw0_wd_in[358]
    DIRECTION INPUT ;
    USE SIGNAL ;
    SHAPE ABUTMENT ;
    PORT
      LAYER met2 ;
      RECT 284.210 0.000 284.350 0.420 ;
    END
  END rw0_wd_in[358]
  PIN rw0_wd_in[359]
    DIRECTION INPUT ;
    USE SIGNAL ;
    SHAPE ABUTMENT ;
    PORT
      LAYER met2 ;
      RECT 286.970 0.000 287.110 0.420 ;
    END
  END rw0_wd_in[359]
  PIN rw0_wd_in[360]
    DIRECTION INPUT ;
    USE SIGNAL ;
    SHAPE ABUTMENT ;
    PORT
      LAYER met2 ;
      RECT 289.730 0.000 289.870 0.420 ;
    END
  END rw0_wd_in[360]
  PIN rw0_wd_in[361]
    DIRECTION INPUT ;
    USE SIGNAL ;
    SHAPE ABUTMENT ;
    PORT
      LAYER met2 ;
      RECT 292.490 0.000 292.630 0.420 ;
    END
  END rw0_wd_in[361]
  PIN rw0_wd_in[362]
    DIRECTION INPUT ;
    USE SIGNAL ;
    SHAPE ABUTMENT ;
    PORT
      LAYER met2 ;
      RECT 295.250 0.000 295.390 0.420 ;
    END
  END rw0_wd_in[362]
  PIN rw0_wd_in[363]
    DIRECTION INPUT ;
    USE SIGNAL ;
    SHAPE ABUTMENT ;
    PORT
      LAYER met2 ;
      RECT 298.010 0.000 298.150 0.420 ;
    END
  END rw0_wd_in[363]
  PIN rw0_wd_in[364]
    DIRECTION INPUT ;
    USE SIGNAL ;
    SHAPE ABUTMENT ;
    PORT
      LAYER met2 ;
      RECT 300.770 0.000 300.910 0.420 ;
    END
  END rw0_wd_in[364]
  PIN rw0_wd_in[365]
    DIRECTION INPUT ;
    USE SIGNAL ;
    SHAPE ABUTMENT ;
    PORT
      LAYER met2 ;
      RECT 303.530 0.000 303.670 0.420 ;
    END
  END rw0_wd_in[365]
  PIN rw0_wd_in[366]
    DIRECTION INPUT ;
    USE SIGNAL ;
    SHAPE ABUTMENT ;
    PORT
      LAYER met2 ;
      RECT 306.290 0.000 306.430 0.420 ;
    END
  END rw0_wd_in[366]
  PIN rw0_wd_in[367]
    DIRECTION INPUT ;
    USE SIGNAL ;
    SHAPE ABUTMENT ;
    PORT
      LAYER met2 ;
      RECT 309.050 0.000 309.190 0.420 ;
    END
  END rw0_wd_in[367]
  PIN rw0_wd_in[368]
    DIRECTION INPUT ;
    USE SIGNAL ;
    SHAPE ABUTMENT ;
    PORT
      LAYER met2 ;
      RECT 311.810 0.000 311.950 0.420 ;
    END
  END rw0_wd_in[368]
  PIN rw0_wd_in[369]
    DIRECTION INPUT ;
    USE SIGNAL ;
    SHAPE ABUTMENT ;
    PORT
      LAYER met2 ;
      RECT 314.570 0.000 314.710 0.420 ;
    END
  END rw0_wd_in[369]
  PIN rw0_wd_in[370]
    DIRECTION INPUT ;
    USE SIGNAL ;
    SHAPE ABUTMENT ;
    PORT
      LAYER met2 ;
      RECT 317.330 0.000 317.470 0.420 ;
    END
  END rw0_wd_in[370]
  PIN rw0_wd_in[371]
    DIRECTION INPUT ;
    USE SIGNAL ;
    SHAPE ABUTMENT ;
    PORT
      LAYER met2 ;
      RECT 320.090 0.000 320.230 0.420 ;
    END
  END rw0_wd_in[371]
  PIN rw0_wd_in[372]
    DIRECTION INPUT ;
    USE SIGNAL ;
    SHAPE ABUTMENT ;
    PORT
      LAYER met2 ;
      RECT 322.850 0.000 322.990 0.420 ;
    END
  END rw0_wd_in[372]
  PIN rw0_wd_in[373]
    DIRECTION INPUT ;
    USE SIGNAL ;
    SHAPE ABUTMENT ;
    PORT
      LAYER met2 ;
      RECT 325.610 0.000 325.750 0.420 ;
    END
  END rw0_wd_in[373]
  PIN rw0_wd_in[374]
    DIRECTION INPUT ;
    USE SIGNAL ;
    SHAPE ABUTMENT ;
    PORT
      LAYER met2 ;
      RECT 328.370 0.000 328.510 0.420 ;
    END
  END rw0_wd_in[374]
  PIN rw0_wd_in[375]
    DIRECTION INPUT ;
    USE SIGNAL ;
    SHAPE ABUTMENT ;
    PORT
      LAYER met2 ;
      RECT 331.130 0.000 331.270 0.420 ;
    END
  END rw0_wd_in[375]
  PIN rw0_wd_in[376]
    DIRECTION INPUT ;
    USE SIGNAL ;
    SHAPE ABUTMENT ;
    PORT
      LAYER met2 ;
      RECT 333.890 0.000 334.030 0.420 ;
    END
  END rw0_wd_in[376]
  PIN rw0_wd_in[377]
    DIRECTION INPUT ;
    USE SIGNAL ;
    SHAPE ABUTMENT ;
    PORT
      LAYER met2 ;
      RECT 336.650 0.000 336.790 0.420 ;
    END
  END rw0_wd_in[377]
  PIN rw0_wd_in[378]
    DIRECTION INPUT ;
    USE SIGNAL ;
    SHAPE ABUTMENT ;
    PORT
      LAYER met2 ;
      RECT 339.410 0.000 339.550 0.420 ;
    END
  END rw0_wd_in[378]
  PIN rw0_wd_in[379]
    DIRECTION INPUT ;
    USE SIGNAL ;
    SHAPE ABUTMENT ;
    PORT
      LAYER met2 ;
      RECT 342.170 0.000 342.310 0.420 ;
    END
  END rw0_wd_in[379]
  PIN rw0_wd_in[380]
    DIRECTION INPUT ;
    USE SIGNAL ;
    SHAPE ABUTMENT ;
    PORT
      LAYER met2 ;
      RECT 344.930 0.000 345.070 0.420 ;
    END
  END rw0_wd_in[380]
  PIN rw0_wd_in[381]
    DIRECTION INPUT ;
    USE SIGNAL ;
    SHAPE ABUTMENT ;
    PORT
      LAYER met2 ;
      RECT 347.690 0.000 347.830 0.420 ;
    END
  END rw0_wd_in[381]
  PIN rw0_wd_in[382]
    DIRECTION INPUT ;
    USE SIGNAL ;
    SHAPE ABUTMENT ;
    PORT
      LAYER met2 ;
      RECT 350.450 0.000 350.590 0.420 ;
    END
  END rw0_wd_in[382]
  PIN rw0_wd_in[383]
    DIRECTION INPUT ;
    USE SIGNAL ;
    SHAPE ABUTMENT ;
    PORT
      LAYER met2 ;
      RECT 353.210 0.000 353.350 0.420 ;
    END
  END rw0_wd_in[383]
  PIN rw0_wd_in[384]
    DIRECTION INPUT ;
    USE SIGNAL ;
    SHAPE ABUTMENT ;
    PORT
      LAYER met2 ;
      RECT 355.970 0.000 356.110 0.420 ;
    END
  END rw0_wd_in[384]
  PIN rw0_wd_in[385]
    DIRECTION INPUT ;
    USE SIGNAL ;
    SHAPE ABUTMENT ;
    PORT
      LAYER met2 ;
      RECT 358.730 0.000 358.870 0.420 ;
    END
  END rw0_wd_in[385]
  PIN rw0_wd_in[386]
    DIRECTION INPUT ;
    USE SIGNAL ;
    SHAPE ABUTMENT ;
    PORT
      LAYER met2 ;
      RECT 361.490 0.000 361.630 0.420 ;
    END
  END rw0_wd_in[386]
  PIN rw0_wd_in[387]
    DIRECTION INPUT ;
    USE SIGNAL ;
    SHAPE ABUTMENT ;
    PORT
      LAYER met2 ;
      RECT 364.250 0.000 364.390 0.420 ;
    END
  END rw0_wd_in[387]
  PIN rw0_wd_in[388]
    DIRECTION INPUT ;
    USE SIGNAL ;
    SHAPE ABUTMENT ;
    PORT
      LAYER met2 ;
      RECT 367.010 0.000 367.150 0.420 ;
    END
  END rw0_wd_in[388]
  PIN rw0_wd_in[389]
    DIRECTION INPUT ;
    USE SIGNAL ;
    SHAPE ABUTMENT ;
    PORT
      LAYER met2 ;
      RECT 369.770 0.000 369.910 0.420 ;
    END
  END rw0_wd_in[389]
  PIN rw0_wd_in[390]
    DIRECTION INPUT ;
    USE SIGNAL ;
    SHAPE ABUTMENT ;
    PORT
      LAYER met2 ;
      RECT 372.530 0.000 372.670 0.420 ;
    END
  END rw0_wd_in[390]
  PIN rw0_wd_in[391]
    DIRECTION INPUT ;
    USE SIGNAL ;
    SHAPE ABUTMENT ;
    PORT
      LAYER met2 ;
      RECT 375.290 0.000 375.430 0.420 ;
    END
  END rw0_wd_in[391]
  PIN rw0_wd_in[392]
    DIRECTION INPUT ;
    USE SIGNAL ;
    SHAPE ABUTMENT ;
    PORT
      LAYER met2 ;
      RECT 378.050 0.000 378.190 0.420 ;
    END
  END rw0_wd_in[392]
  PIN rw0_wd_in[393]
    DIRECTION INPUT ;
    USE SIGNAL ;
    SHAPE ABUTMENT ;
    PORT
      LAYER met2 ;
      RECT 380.810 0.000 380.950 0.420 ;
    END
  END rw0_wd_in[393]
  PIN rw0_wd_in[394]
    DIRECTION INPUT ;
    USE SIGNAL ;
    SHAPE ABUTMENT ;
    PORT
      LAYER met2 ;
      RECT 383.570 0.000 383.710 0.420 ;
    END
  END rw0_wd_in[394]
  PIN rw0_wd_in[395]
    DIRECTION INPUT ;
    USE SIGNAL ;
    SHAPE ABUTMENT ;
    PORT
      LAYER met2 ;
      RECT 386.330 0.000 386.470 0.420 ;
    END
  END rw0_wd_in[395]
  PIN rw0_wd_in[396]
    DIRECTION INPUT ;
    USE SIGNAL ;
    SHAPE ABUTMENT ;
    PORT
      LAYER met2 ;
      RECT 389.090 0.000 389.230 0.420 ;
    END
  END rw0_wd_in[396]
  PIN rw0_wd_in[397]
    DIRECTION INPUT ;
    USE SIGNAL ;
    SHAPE ABUTMENT ;
    PORT
      LAYER met2 ;
      RECT 391.850 0.000 391.990 0.420 ;
    END
  END rw0_wd_in[397]
  PIN rw0_wd_in[398]
    DIRECTION INPUT ;
    USE SIGNAL ;
    SHAPE ABUTMENT ;
    PORT
      LAYER met2 ;
      RECT 394.610 0.000 394.750 0.420 ;
    END
  END rw0_wd_in[398]
  PIN rw0_wd_in[399]
    DIRECTION INPUT ;
    USE SIGNAL ;
    SHAPE ABUTMENT ;
    PORT
      LAYER met2 ;
      RECT 397.370 0.000 397.510 0.420 ;
    END
  END rw0_wd_in[399]
  PIN rw0_wd_in[400]
    DIRECTION INPUT ;
    USE SIGNAL ;
    SHAPE ABUTMENT ;
    PORT
      LAYER met2 ;
      RECT 400.130 0.000 400.270 0.420 ;
    END
  END rw0_wd_in[400]
  PIN rw0_wd_in[401]
    DIRECTION INPUT ;
    USE SIGNAL ;
    SHAPE ABUTMENT ;
    PORT
      LAYER met2 ;
      RECT 402.890 0.000 403.030 0.420 ;
    END
  END rw0_wd_in[401]
  PIN rw0_wd_in[402]
    DIRECTION INPUT ;
    USE SIGNAL ;
    SHAPE ABUTMENT ;
    PORT
      LAYER met2 ;
      RECT 405.650 0.000 405.790 0.420 ;
    END
  END rw0_wd_in[402]
  PIN rw0_wd_in[403]
    DIRECTION INPUT ;
    USE SIGNAL ;
    SHAPE ABUTMENT ;
    PORT
      LAYER met2 ;
      RECT 408.410 0.000 408.550 0.420 ;
    END
  END rw0_wd_in[403]
  PIN rw0_wd_in[404]
    DIRECTION INPUT ;
    USE SIGNAL ;
    SHAPE ABUTMENT ;
    PORT
      LAYER met2 ;
      RECT 411.170 0.000 411.310 0.420 ;
    END
  END rw0_wd_in[404]
  PIN rw0_wd_in[405]
    DIRECTION INPUT ;
    USE SIGNAL ;
    SHAPE ABUTMENT ;
    PORT
      LAYER met2 ;
      RECT 413.930 0.000 414.070 0.420 ;
    END
  END rw0_wd_in[405]
  PIN rw0_wd_in[406]
    DIRECTION INPUT ;
    USE SIGNAL ;
    SHAPE ABUTMENT ;
    PORT
      LAYER met2 ;
      RECT 416.690 0.000 416.830 0.420 ;
    END
  END rw0_wd_in[406]
  PIN rw0_wd_in[407]
    DIRECTION INPUT ;
    USE SIGNAL ;
    SHAPE ABUTMENT ;
    PORT
      LAYER met2 ;
      RECT 419.450 0.000 419.590 0.420 ;
    END
  END rw0_wd_in[407]
  PIN rw0_wd_in[408]
    DIRECTION INPUT ;
    USE SIGNAL ;
    SHAPE ABUTMENT ;
    PORT
      LAYER met2 ;
      RECT 422.210 0.000 422.350 0.420 ;
    END
  END rw0_wd_in[408]
  PIN rw0_wd_in[409]
    DIRECTION INPUT ;
    USE SIGNAL ;
    SHAPE ABUTMENT ;
    PORT
      LAYER met2 ;
      RECT 424.970 0.000 425.110 0.420 ;
    END
  END rw0_wd_in[409]
  PIN rw0_wd_in[410]
    DIRECTION INPUT ;
    USE SIGNAL ;
    SHAPE ABUTMENT ;
    PORT
      LAYER met2 ;
      RECT 427.730 0.000 427.870 0.420 ;
    END
  END rw0_wd_in[410]
  PIN rw0_wd_in[411]
    DIRECTION INPUT ;
    USE SIGNAL ;
    SHAPE ABUTMENT ;
    PORT
      LAYER met2 ;
      RECT 430.490 0.000 430.630 0.420 ;
    END
  END rw0_wd_in[411]
  PIN rw0_wd_in[412]
    DIRECTION INPUT ;
    USE SIGNAL ;
    SHAPE ABUTMENT ;
    PORT
      LAYER met2 ;
      RECT 433.250 0.000 433.390 0.420 ;
    END
  END rw0_wd_in[412]
  PIN rw0_wd_in[413]
    DIRECTION INPUT ;
    USE SIGNAL ;
    SHAPE ABUTMENT ;
    PORT
      LAYER met2 ;
      RECT 436.010 0.000 436.150 0.420 ;
    END
  END rw0_wd_in[413]
  PIN rw0_wd_in[414]
    DIRECTION INPUT ;
    USE SIGNAL ;
    SHAPE ABUTMENT ;
    PORT
      LAYER met2 ;
      RECT 438.770 0.000 438.910 0.420 ;
    END
  END rw0_wd_in[414]
  PIN rw0_wd_in[415]
    DIRECTION INPUT ;
    USE SIGNAL ;
    SHAPE ABUTMENT ;
    PORT
      LAYER met2 ;
      RECT 441.530 0.000 441.670 0.420 ;
    END
  END rw0_wd_in[415]
  PIN rw0_wd_in[416]
    DIRECTION INPUT ;
    USE SIGNAL ;
    SHAPE ABUTMENT ;
    PORT
      LAYER met2 ;
      RECT 444.290 0.000 444.430 0.420 ;
    END
  END rw0_wd_in[416]
  PIN rw0_wd_in[417]
    DIRECTION INPUT ;
    USE SIGNAL ;
    SHAPE ABUTMENT ;
    PORT
      LAYER met2 ;
      RECT 447.050 0.000 447.190 0.420 ;
    END
  END rw0_wd_in[417]
  PIN rw0_wd_in[418]
    DIRECTION INPUT ;
    USE SIGNAL ;
    SHAPE ABUTMENT ;
    PORT
      LAYER met2 ;
      RECT 449.810 0.000 449.950 0.420 ;
    END
  END rw0_wd_in[418]
  PIN rw0_wd_in[419]
    DIRECTION INPUT ;
    USE SIGNAL ;
    SHAPE ABUTMENT ;
    PORT
      LAYER met2 ;
      RECT 452.570 0.000 452.710 0.420 ;
    END
  END rw0_wd_in[419]
  PIN rw0_wd_in[420]
    DIRECTION INPUT ;
    USE SIGNAL ;
    SHAPE ABUTMENT ;
    PORT
      LAYER met2 ;
      RECT 455.330 0.000 455.470 0.420 ;
    END
  END rw0_wd_in[420]
  PIN rw0_wd_in[421]
    DIRECTION INPUT ;
    USE SIGNAL ;
    SHAPE ABUTMENT ;
    PORT
      LAYER met2 ;
      RECT 458.090 0.000 458.230 0.420 ;
    END
  END rw0_wd_in[421]
  PIN rw0_wd_in[422]
    DIRECTION INPUT ;
    USE SIGNAL ;
    SHAPE ABUTMENT ;
    PORT
      LAYER met2 ;
      RECT 460.850 0.000 460.990 0.420 ;
    END
  END rw0_wd_in[422]
  PIN rw0_wd_in[423]
    DIRECTION INPUT ;
    USE SIGNAL ;
    SHAPE ABUTMENT ;
    PORT
      LAYER met2 ;
      RECT 463.610 0.000 463.750 0.420 ;
    END
  END rw0_wd_in[423]
  PIN rw0_wd_in[424]
    DIRECTION INPUT ;
    USE SIGNAL ;
    SHAPE ABUTMENT ;
    PORT
      LAYER met2 ;
      RECT 466.370 0.000 466.510 0.420 ;
    END
  END rw0_wd_in[424]
  PIN rw0_wd_in[425]
    DIRECTION INPUT ;
    USE SIGNAL ;
    SHAPE ABUTMENT ;
    PORT
      LAYER met2 ;
      RECT 469.130 0.000 469.270 0.420 ;
    END
  END rw0_wd_in[425]
  PIN rw0_wd_in[426]
    DIRECTION INPUT ;
    USE SIGNAL ;
    SHAPE ABUTMENT ;
    PORT
      LAYER met2 ;
      RECT 471.890 0.000 472.030 0.420 ;
    END
  END rw0_wd_in[426]
  PIN rw0_wd_in[427]
    DIRECTION INPUT ;
    USE SIGNAL ;
    SHAPE ABUTMENT ;
    PORT
      LAYER met2 ;
      RECT 474.650 0.000 474.790 0.420 ;
    END
  END rw0_wd_in[427]
  PIN rw0_wd_in[428]
    DIRECTION INPUT ;
    USE SIGNAL ;
    SHAPE ABUTMENT ;
    PORT
      LAYER met2 ;
      RECT 477.410 0.000 477.550 0.420 ;
    END
  END rw0_wd_in[428]
  PIN rw0_wd_in[429]
    DIRECTION INPUT ;
    USE SIGNAL ;
    SHAPE ABUTMENT ;
    PORT
      LAYER met2 ;
      RECT 480.170 0.000 480.310 0.420 ;
    END
  END rw0_wd_in[429]
  PIN rw0_wd_in[430]
    DIRECTION INPUT ;
    USE SIGNAL ;
    SHAPE ABUTMENT ;
    PORT
      LAYER met2 ;
      RECT 482.930 0.000 483.070 0.420 ;
    END
  END rw0_wd_in[430]
  PIN rw0_wd_in[431]
    DIRECTION INPUT ;
    USE SIGNAL ;
    SHAPE ABUTMENT ;
    PORT
      LAYER met2 ;
      RECT 485.690 0.000 485.830 0.420 ;
    END
  END rw0_wd_in[431]
  PIN rw0_wd_in[432]
    DIRECTION INPUT ;
    USE SIGNAL ;
    SHAPE ABUTMENT ;
    PORT
      LAYER met2 ;
      RECT 488.450 0.000 488.590 0.420 ;
    END
  END rw0_wd_in[432]
  PIN rw0_wd_in[433]
    DIRECTION INPUT ;
    USE SIGNAL ;
    SHAPE ABUTMENT ;
    PORT
      LAYER met2 ;
      RECT 491.210 0.000 491.350 0.420 ;
    END
  END rw0_wd_in[433]
  PIN rw0_wd_in[434]
    DIRECTION INPUT ;
    USE SIGNAL ;
    SHAPE ABUTMENT ;
    PORT
      LAYER met2 ;
      RECT 493.970 0.000 494.110 0.420 ;
    END
  END rw0_wd_in[434]
  PIN rw0_wd_in[435]
    DIRECTION INPUT ;
    USE SIGNAL ;
    SHAPE ABUTMENT ;
    PORT
      LAYER met2 ;
      RECT 496.730 0.000 496.870 0.420 ;
    END
  END rw0_wd_in[435]
  PIN rw0_wd_in[436]
    DIRECTION INPUT ;
    USE SIGNAL ;
    SHAPE ABUTMENT ;
    PORT
      LAYER met2 ;
      RECT 499.490 0.000 499.630 0.420 ;
    END
  END rw0_wd_in[436]
  PIN rw0_wd_in[437]
    DIRECTION INPUT ;
    USE SIGNAL ;
    SHAPE ABUTMENT ;
    PORT
      LAYER met2 ;
      RECT 502.250 0.000 502.390 0.420 ;
    END
  END rw0_wd_in[437]
  PIN rw0_wd_in[438]
    DIRECTION INPUT ;
    USE SIGNAL ;
    SHAPE ABUTMENT ;
    PORT
      LAYER met2 ;
      RECT 505.010 0.000 505.150 0.420 ;
    END
  END rw0_wd_in[438]
  PIN rw0_wd_in[439]
    DIRECTION INPUT ;
    USE SIGNAL ;
    SHAPE ABUTMENT ;
    PORT
      LAYER met2 ;
      RECT 507.770 0.000 507.910 0.420 ;
    END
  END rw0_wd_in[439]
  PIN rw0_wd_in[440]
    DIRECTION INPUT ;
    USE SIGNAL ;
    SHAPE ABUTMENT ;
    PORT
      LAYER met2 ;
      RECT 510.530 0.000 510.670 0.420 ;
    END
  END rw0_wd_in[440]
  PIN rw0_wd_in[441]
    DIRECTION INPUT ;
    USE SIGNAL ;
    SHAPE ABUTMENT ;
    PORT
      LAYER met2 ;
      RECT 513.290 0.000 513.430 0.420 ;
    END
  END rw0_wd_in[441]
  PIN rw0_wd_in[442]
    DIRECTION INPUT ;
    USE SIGNAL ;
    SHAPE ABUTMENT ;
    PORT
      LAYER met2 ;
      RECT 516.050 0.000 516.190 0.420 ;
    END
  END rw0_wd_in[442]
  PIN rw0_wd_in[443]
    DIRECTION INPUT ;
    USE SIGNAL ;
    SHAPE ABUTMENT ;
    PORT
      LAYER met2 ;
      RECT 518.810 0.000 518.950 0.420 ;
    END
  END rw0_wd_in[443]
  PIN rw0_wd_in[444]
    DIRECTION INPUT ;
    USE SIGNAL ;
    SHAPE ABUTMENT ;
    PORT
      LAYER met2 ;
      RECT 521.570 0.000 521.710 0.420 ;
    END
  END rw0_wd_in[444]
  PIN rw0_wd_in[445]
    DIRECTION INPUT ;
    USE SIGNAL ;
    SHAPE ABUTMENT ;
    PORT
      LAYER met2 ;
      RECT 524.330 0.000 524.470 0.420 ;
    END
  END rw0_wd_in[445]
  PIN rw0_wd_in[446]
    DIRECTION INPUT ;
    USE SIGNAL ;
    SHAPE ABUTMENT ;
    PORT
      LAYER met2 ;
      RECT 527.090 0.000 527.230 0.420 ;
    END
  END rw0_wd_in[446]
  PIN rw0_wd_in[447]
    DIRECTION INPUT ;
    USE SIGNAL ;
    SHAPE ABUTMENT ;
    PORT
      LAYER met2 ;
      RECT 529.850 0.000 529.990 0.420 ;
    END
  END rw0_wd_in[447]
  PIN rw0_wd_in[448]
    DIRECTION INPUT ;
    USE SIGNAL ;
    SHAPE ABUTMENT ;
    PORT
      LAYER met2 ;
      RECT 532.610 0.000 532.750 0.420 ;
    END
  END rw0_wd_in[448]
  PIN rw0_wd_in[449]
    DIRECTION INPUT ;
    USE SIGNAL ;
    SHAPE ABUTMENT ;
    PORT
      LAYER met2 ;
      RECT 535.370 0.000 535.510 0.420 ;
    END
  END rw0_wd_in[449]
  PIN rw0_wd_in[450]
    DIRECTION INPUT ;
    USE SIGNAL ;
    SHAPE ABUTMENT ;
    PORT
      LAYER met2 ;
      RECT 538.130 0.000 538.270 0.420 ;
    END
  END rw0_wd_in[450]
  PIN rw0_wd_in[451]
    DIRECTION INPUT ;
    USE SIGNAL ;
    SHAPE ABUTMENT ;
    PORT
      LAYER met2 ;
      RECT 540.890 0.000 541.030 0.420 ;
    END
  END rw0_wd_in[451]
  PIN rw0_wd_in[452]
    DIRECTION INPUT ;
    USE SIGNAL ;
    SHAPE ABUTMENT ;
    PORT
      LAYER met2 ;
      RECT 543.650 0.000 543.790 0.420 ;
    END
  END rw0_wd_in[452]
  PIN rw0_wd_in[453]
    DIRECTION INPUT ;
    USE SIGNAL ;
    SHAPE ABUTMENT ;
    PORT
      LAYER met2 ;
      RECT 546.410 0.000 546.550 0.420 ;
    END
  END rw0_wd_in[453]
  PIN rw0_wd_in[454]
    DIRECTION INPUT ;
    USE SIGNAL ;
    SHAPE ABUTMENT ;
    PORT
      LAYER met2 ;
      RECT 549.170 0.000 549.310 0.420 ;
    END
  END rw0_wd_in[454]
  PIN rw0_wd_in[455]
    DIRECTION INPUT ;
    USE SIGNAL ;
    SHAPE ABUTMENT ;
    PORT
      LAYER met2 ;
      RECT 551.930 0.000 552.070 0.420 ;
    END
  END rw0_wd_in[455]
  PIN rw0_wd_in[456]
    DIRECTION INPUT ;
    USE SIGNAL ;
    SHAPE ABUTMENT ;
    PORT
      LAYER met2 ;
      RECT 554.690 0.000 554.830 0.420 ;
    END
  END rw0_wd_in[456]
  PIN rw0_wd_in[457]
    DIRECTION INPUT ;
    USE SIGNAL ;
    SHAPE ABUTMENT ;
    PORT
      LAYER met2 ;
      RECT 557.450 0.000 557.590 0.420 ;
    END
  END rw0_wd_in[457]
  PIN rw0_wd_in[458]
    DIRECTION INPUT ;
    USE SIGNAL ;
    SHAPE ABUTMENT ;
    PORT
      LAYER met2 ;
      RECT 560.210 0.000 560.350 0.420 ;
    END
  END rw0_wd_in[458]
  PIN rw0_wd_in[459]
    DIRECTION INPUT ;
    USE SIGNAL ;
    SHAPE ABUTMENT ;
    PORT
      LAYER met2 ;
      RECT 562.970 0.000 563.110 0.420 ;
    END
  END rw0_wd_in[459]
  PIN rw0_wd_in[460]
    DIRECTION INPUT ;
    USE SIGNAL ;
    SHAPE ABUTMENT ;
    PORT
      LAYER met2 ;
      RECT 565.730 0.000 565.870 0.420 ;
    END
  END rw0_wd_in[460]
  PIN rw0_wd_in[461]
    DIRECTION INPUT ;
    USE SIGNAL ;
    SHAPE ABUTMENT ;
    PORT
      LAYER met2 ;
      RECT 568.490 0.000 568.630 0.420 ;
    END
  END rw0_wd_in[461]
  PIN rw0_wd_in[462]
    DIRECTION INPUT ;
    USE SIGNAL ;
    SHAPE ABUTMENT ;
    PORT
      LAYER met2 ;
      RECT 571.250 0.000 571.390 0.420 ;
    END
  END rw0_wd_in[462]
  PIN rw0_wd_in[463]
    DIRECTION INPUT ;
    USE SIGNAL ;
    SHAPE ABUTMENT ;
    PORT
      LAYER met2 ;
      RECT 574.010 0.000 574.150 0.420 ;
    END
  END rw0_wd_in[463]
  PIN rw0_wd_in[464]
    DIRECTION INPUT ;
    USE SIGNAL ;
    SHAPE ABUTMENT ;
    PORT
      LAYER met2 ;
      RECT 576.770 0.000 576.910 0.420 ;
    END
  END rw0_wd_in[464]
  PIN rw0_wd_in[465]
    DIRECTION INPUT ;
    USE SIGNAL ;
    SHAPE ABUTMENT ;
    PORT
      LAYER met2 ;
      RECT 579.530 0.000 579.670 0.420 ;
    END
  END rw0_wd_in[465]
  PIN rw0_wd_in[466]
    DIRECTION INPUT ;
    USE SIGNAL ;
    SHAPE ABUTMENT ;
    PORT
      LAYER met2 ;
      RECT 582.290 0.000 582.430 0.420 ;
    END
  END rw0_wd_in[466]
  PIN rw0_wd_in[467]
    DIRECTION INPUT ;
    USE SIGNAL ;
    SHAPE ABUTMENT ;
    PORT
      LAYER met2 ;
      RECT 585.050 0.000 585.190 0.420 ;
    END
  END rw0_wd_in[467]
  PIN rw0_wd_in[468]
    DIRECTION INPUT ;
    USE SIGNAL ;
    SHAPE ABUTMENT ;
    PORT
      LAYER met2 ;
      RECT 587.810 0.000 587.950 0.420 ;
    END
  END rw0_wd_in[468]
  PIN rw0_wd_in[469]
    DIRECTION INPUT ;
    USE SIGNAL ;
    SHAPE ABUTMENT ;
    PORT
      LAYER met2 ;
      RECT 590.570 0.000 590.710 0.420 ;
    END
  END rw0_wd_in[469]
  PIN rw0_wd_in[470]
    DIRECTION INPUT ;
    USE SIGNAL ;
    SHAPE ABUTMENT ;
    PORT
      LAYER met2 ;
      RECT 593.330 0.000 593.470 0.420 ;
    END
  END rw0_wd_in[470]
  PIN rw0_wd_in[471]
    DIRECTION INPUT ;
    USE SIGNAL ;
    SHAPE ABUTMENT ;
    PORT
      LAYER met2 ;
      RECT 596.090 0.000 596.230 0.420 ;
    END
  END rw0_wd_in[471]
  PIN rw0_wd_in[472]
    DIRECTION INPUT ;
    USE SIGNAL ;
    SHAPE ABUTMENT ;
    PORT
      LAYER met2 ;
      RECT 598.850 0.000 598.990 0.420 ;
    END
  END rw0_wd_in[472]
  PIN rw0_wd_in[473]
    DIRECTION INPUT ;
    USE SIGNAL ;
    SHAPE ABUTMENT ;
    PORT
      LAYER met2 ;
      RECT 601.610 0.000 601.750 0.420 ;
    END
  END rw0_wd_in[473]
  PIN rw0_wd_in[474]
    DIRECTION INPUT ;
    USE SIGNAL ;
    SHAPE ABUTMENT ;
    PORT
      LAYER met2 ;
      RECT 604.370 0.000 604.510 0.420 ;
    END
  END rw0_wd_in[474]
  PIN rw0_wd_in[475]
    DIRECTION INPUT ;
    USE SIGNAL ;
    SHAPE ABUTMENT ;
    PORT
      LAYER met2 ;
      RECT 607.130 0.000 607.270 0.420 ;
    END
  END rw0_wd_in[475]
  PIN rw0_wd_in[476]
    DIRECTION INPUT ;
    USE SIGNAL ;
    SHAPE ABUTMENT ;
    PORT
      LAYER met2 ;
      RECT 609.890 0.000 610.030 0.420 ;
    END
  END rw0_wd_in[476]
  PIN rw0_wd_in[477]
    DIRECTION INPUT ;
    USE SIGNAL ;
    SHAPE ABUTMENT ;
    PORT
      LAYER met2 ;
      RECT 612.650 0.000 612.790 0.420 ;
    END
  END rw0_wd_in[477]
  PIN rw0_wd_in[478]
    DIRECTION INPUT ;
    USE SIGNAL ;
    SHAPE ABUTMENT ;
    PORT
      LAYER met2 ;
      RECT 615.410 0.000 615.550 0.420 ;
    END
  END rw0_wd_in[478]
  PIN rw0_wd_in[479]
    DIRECTION INPUT ;
    USE SIGNAL ;
    SHAPE ABUTMENT ;
    PORT
      LAYER met2 ;
      RECT 618.170 0.000 618.310 0.420 ;
    END
  END rw0_wd_in[479]
  PIN rw0_wd_in[480]
    DIRECTION INPUT ;
    USE SIGNAL ;
    SHAPE ABUTMENT ;
    PORT
      LAYER met2 ;
      RECT 620.930 0.000 621.070 0.420 ;
    END
  END rw0_wd_in[480]
  PIN rw0_wd_in[481]
    DIRECTION INPUT ;
    USE SIGNAL ;
    SHAPE ABUTMENT ;
    PORT
      LAYER met2 ;
      RECT 623.690 0.000 623.830 0.420 ;
    END
  END rw0_wd_in[481]
  PIN rw0_wd_in[482]
    DIRECTION INPUT ;
    USE SIGNAL ;
    SHAPE ABUTMENT ;
    PORT
      LAYER met2 ;
      RECT 626.450 0.000 626.590 0.420 ;
    END
  END rw0_wd_in[482]
  PIN rw0_wd_in[483]
    DIRECTION INPUT ;
    USE SIGNAL ;
    SHAPE ABUTMENT ;
    PORT
      LAYER met2 ;
      RECT 629.210 0.000 629.350 0.420 ;
    END
  END rw0_wd_in[483]
  PIN rw0_wd_in[484]
    DIRECTION INPUT ;
    USE SIGNAL ;
    SHAPE ABUTMENT ;
    PORT
      LAYER met2 ;
      RECT 631.970 0.000 632.110 0.420 ;
    END
  END rw0_wd_in[484]
  PIN rw0_wd_in[485]
    DIRECTION INPUT ;
    USE SIGNAL ;
    SHAPE ABUTMENT ;
    PORT
      LAYER met2 ;
      RECT 634.730 0.000 634.870 0.420 ;
    END
  END rw0_wd_in[485]
  PIN rw0_wd_in[486]
    DIRECTION INPUT ;
    USE SIGNAL ;
    SHAPE ABUTMENT ;
    PORT
      LAYER met2 ;
      RECT 637.490 0.000 637.630 0.420 ;
    END
  END rw0_wd_in[486]
  PIN rw0_wd_in[487]
    DIRECTION INPUT ;
    USE SIGNAL ;
    SHAPE ABUTMENT ;
    PORT
      LAYER met2 ;
      RECT 640.250 0.000 640.390 0.420 ;
    END
  END rw0_wd_in[487]
  PIN rw0_wd_in[488]
    DIRECTION INPUT ;
    USE SIGNAL ;
    SHAPE ABUTMENT ;
    PORT
      LAYER met2 ;
      RECT 643.010 0.000 643.150 0.420 ;
    END
  END rw0_wd_in[488]
  PIN rw0_wd_in[489]
    DIRECTION INPUT ;
    USE SIGNAL ;
    SHAPE ABUTMENT ;
    PORT
      LAYER met2 ;
      RECT 645.770 0.000 645.910 0.420 ;
    END
  END rw0_wd_in[489]
  PIN rw0_wd_in[490]
    DIRECTION INPUT ;
    USE SIGNAL ;
    SHAPE ABUTMENT ;
    PORT
      LAYER met2 ;
      RECT 648.530 0.000 648.670 0.420 ;
    END
  END rw0_wd_in[490]
  PIN rw0_wd_in[491]
    DIRECTION INPUT ;
    USE SIGNAL ;
    SHAPE ABUTMENT ;
    PORT
      LAYER met2 ;
      RECT 651.290 0.000 651.430 0.420 ;
    END
  END rw0_wd_in[491]
  PIN rw0_wd_in[492]
    DIRECTION INPUT ;
    USE SIGNAL ;
    SHAPE ABUTMENT ;
    PORT
      LAYER met2 ;
      RECT 654.050 0.000 654.190 0.420 ;
    END
  END rw0_wd_in[492]
  PIN rw0_wd_in[493]
    DIRECTION INPUT ;
    USE SIGNAL ;
    SHAPE ABUTMENT ;
    PORT
      LAYER met2 ;
      RECT 656.810 0.000 656.950 0.420 ;
    END
  END rw0_wd_in[493]
  PIN rw0_wd_in[494]
    DIRECTION INPUT ;
    USE SIGNAL ;
    SHAPE ABUTMENT ;
    PORT
      LAYER met2 ;
      RECT 659.570 0.000 659.710 0.420 ;
    END
  END rw0_wd_in[494]
  PIN rw0_wd_in[495]
    DIRECTION INPUT ;
    USE SIGNAL ;
    SHAPE ABUTMENT ;
    PORT
      LAYER met2 ;
      RECT 662.330 0.000 662.470 0.420 ;
    END
  END rw0_wd_in[495]
  PIN rw0_wd_in[496]
    DIRECTION INPUT ;
    USE SIGNAL ;
    SHAPE ABUTMENT ;
    PORT
      LAYER met2 ;
      RECT 665.090 0.000 665.230 0.420 ;
    END
  END rw0_wd_in[496]
  PIN rw0_wd_in[497]
    DIRECTION INPUT ;
    USE SIGNAL ;
    SHAPE ABUTMENT ;
    PORT
      LAYER met2 ;
      RECT 667.850 0.000 667.990 0.420 ;
    END
  END rw0_wd_in[497]
  PIN rw0_wd_in[498]
    DIRECTION INPUT ;
    USE SIGNAL ;
    SHAPE ABUTMENT ;
    PORT
      LAYER met2 ;
      RECT 670.610 0.000 670.750 0.420 ;
    END
  END rw0_wd_in[498]
  PIN rw0_wd_in[499]
    DIRECTION INPUT ;
    USE SIGNAL ;
    SHAPE ABUTMENT ;
    PORT
      LAYER met2 ;
      RECT 673.370 0.000 673.510 0.420 ;
    END
  END rw0_wd_in[499]
  PIN rw0_wd_in[500]
    DIRECTION INPUT ;
    USE SIGNAL ;
    SHAPE ABUTMENT ;
    PORT
      LAYER met2 ;
      RECT 676.130 0.000 676.270 0.420 ;
    END
  END rw0_wd_in[500]
  PIN rw0_wd_in[501]
    DIRECTION INPUT ;
    USE SIGNAL ;
    SHAPE ABUTMENT ;
    PORT
      LAYER met2 ;
      RECT 678.890 0.000 679.030 0.420 ;
    END
  END rw0_wd_in[501]
  PIN rw0_wd_in[502]
    DIRECTION INPUT ;
    USE SIGNAL ;
    SHAPE ABUTMENT ;
    PORT
      LAYER met2 ;
      RECT 681.650 0.000 681.790 0.420 ;
    END
  END rw0_wd_in[502]
  PIN rw0_wd_in[503]
    DIRECTION INPUT ;
    USE SIGNAL ;
    SHAPE ABUTMENT ;
    PORT
      LAYER met2 ;
      RECT 684.410 0.000 684.550 0.420 ;
    END
  END rw0_wd_in[503]
  PIN rw0_wd_in[504]
    DIRECTION INPUT ;
    USE SIGNAL ;
    SHAPE ABUTMENT ;
    PORT
      LAYER met2 ;
      RECT 687.170 0.000 687.310 0.420 ;
    END
  END rw0_wd_in[504]
  PIN rw0_wd_in[505]
    DIRECTION INPUT ;
    USE SIGNAL ;
    SHAPE ABUTMENT ;
    PORT
      LAYER met2 ;
      RECT 689.930 0.000 690.070 0.420 ;
    END
  END rw0_wd_in[505]
  PIN rw0_wd_in[506]
    DIRECTION INPUT ;
    USE SIGNAL ;
    SHAPE ABUTMENT ;
    PORT
      LAYER met2 ;
      RECT 692.690 0.000 692.830 0.420 ;
    END
  END rw0_wd_in[506]
  PIN rw0_wd_in[507]
    DIRECTION INPUT ;
    USE SIGNAL ;
    SHAPE ABUTMENT ;
    PORT
      LAYER met2 ;
      RECT 695.450 0.000 695.590 0.420 ;
    END
  END rw0_wd_in[507]
  PIN rw0_wd_in[508]
    DIRECTION INPUT ;
    USE SIGNAL ;
    SHAPE ABUTMENT ;
    PORT
      LAYER met2 ;
      RECT 698.210 0.000 698.350 0.420 ;
    END
  END rw0_wd_in[508]
  PIN rw0_wd_in[509]
    DIRECTION INPUT ;
    USE SIGNAL ;
    SHAPE ABUTMENT ;
    PORT
      LAYER met2 ;
      RECT 700.970 0.000 701.110 0.420 ;
    END
  END rw0_wd_in[509]
  PIN rw0_wd_in[510]
    DIRECTION INPUT ;
    USE SIGNAL ;
    SHAPE ABUTMENT ;
    PORT
      LAYER met2 ;
      RECT 703.730 0.000 703.870 0.420 ;
    END
  END rw0_wd_in[510]
  PIN rw0_wd_in[511]
    DIRECTION INPUT ;
    USE SIGNAL ;
    SHAPE ABUTMENT ;
    PORT
      LAYER met2 ;
      RECT 706.490 0.000 706.630 0.420 ;
    END
  END rw0_wd_in[511]
  PIN rw0_rd_out[0]
    DIRECTION OUTPUT ;
    USE SIGNAL ;
    SHAPE ABUTMENT ;
    PORT
      LAYER met2 ;
      RECT 709.250 0.000 709.390 0.420 ;
    END
  END rw0_rd_out[0]
  PIN rw0_rd_out[1]
    DIRECTION OUTPUT ;
    USE SIGNAL ;
    SHAPE ABUTMENT ;
    PORT
      LAYER met2 ;
      RECT 712.010 0.000 712.150 0.420 ;
    END
  END rw0_rd_out[1]
  PIN rw0_rd_out[2]
    DIRECTION OUTPUT ;
    USE SIGNAL ;
    SHAPE ABUTMENT ;
    PORT
      LAYER met2 ;
      RECT 714.770 0.000 714.910 0.420 ;
    END
  END rw0_rd_out[2]
  PIN rw0_rd_out[3]
    DIRECTION OUTPUT ;
    USE SIGNAL ;
    SHAPE ABUTMENT ;
    PORT
      LAYER met2 ;
      RECT 717.530 0.000 717.670 0.420 ;
    END
  END rw0_rd_out[3]
  PIN rw0_rd_out[4]
    DIRECTION OUTPUT ;
    USE SIGNAL ;
    SHAPE ABUTMENT ;
    PORT
      LAYER met2 ;
      RECT 720.290 0.000 720.430 0.420 ;
    END
  END rw0_rd_out[4]
  PIN rw0_rd_out[5]
    DIRECTION OUTPUT ;
    USE SIGNAL ;
    SHAPE ABUTMENT ;
    PORT
      LAYER met2 ;
      RECT 723.050 0.000 723.190 0.420 ;
    END
  END rw0_rd_out[5]
  PIN rw0_rd_out[6]
    DIRECTION OUTPUT ;
    USE SIGNAL ;
    SHAPE ABUTMENT ;
    PORT
      LAYER met2 ;
      RECT 725.810 0.000 725.950 0.420 ;
    END
  END rw0_rd_out[6]
  PIN rw0_rd_out[7]
    DIRECTION OUTPUT ;
    USE SIGNAL ;
    SHAPE ABUTMENT ;
    PORT
      LAYER met2 ;
      RECT 728.570 0.000 728.710 0.420 ;
    END
  END rw0_rd_out[7]
  PIN rw0_rd_out[8]
    DIRECTION OUTPUT ;
    USE SIGNAL ;
    SHAPE ABUTMENT ;
    PORT
      LAYER met2 ;
      RECT 731.330 0.000 731.470 0.420 ;
    END
  END rw0_rd_out[8]
  PIN rw0_rd_out[9]
    DIRECTION OUTPUT ;
    USE SIGNAL ;
    SHAPE ABUTMENT ;
    PORT
      LAYER met2 ;
      RECT 734.090 0.000 734.230 0.420 ;
    END
  END rw0_rd_out[9]
  PIN rw0_rd_out[10]
    DIRECTION OUTPUT ;
    USE SIGNAL ;
    SHAPE ABUTMENT ;
    PORT
      LAYER met2 ;
      RECT 736.850 0.000 736.990 0.420 ;
    END
  END rw0_rd_out[10]
  PIN rw0_rd_out[11]
    DIRECTION OUTPUT ;
    USE SIGNAL ;
    SHAPE ABUTMENT ;
    PORT
      LAYER met2 ;
      RECT 739.610 0.000 739.750 0.420 ;
    END
  END rw0_rd_out[11]
  PIN rw0_rd_out[12]
    DIRECTION OUTPUT ;
    USE SIGNAL ;
    SHAPE ABUTMENT ;
    PORT
      LAYER met2 ;
      RECT 742.370 0.000 742.510 0.420 ;
    END
  END rw0_rd_out[12]
  PIN rw0_rd_out[13]
    DIRECTION OUTPUT ;
    USE SIGNAL ;
    SHAPE ABUTMENT ;
    PORT
      LAYER met2 ;
      RECT 745.130 0.000 745.270 0.420 ;
    END
  END rw0_rd_out[13]
  PIN rw0_rd_out[14]
    DIRECTION OUTPUT ;
    USE SIGNAL ;
    SHAPE ABUTMENT ;
    PORT
      LAYER met2 ;
      RECT 747.890 0.000 748.030 0.420 ;
    END
  END rw0_rd_out[14]
  PIN rw0_rd_out[15]
    DIRECTION OUTPUT ;
    USE SIGNAL ;
    SHAPE ABUTMENT ;
    PORT
      LAYER met2 ;
      RECT 750.650 0.000 750.790 0.420 ;
    END
  END rw0_rd_out[15]
  PIN rw0_rd_out[16]
    DIRECTION OUTPUT ;
    USE SIGNAL ;
    SHAPE ABUTMENT ;
    PORT
      LAYER met2 ;
      RECT 753.410 0.000 753.550 0.420 ;
    END
  END rw0_rd_out[16]
  PIN rw0_rd_out[17]
    DIRECTION OUTPUT ;
    USE SIGNAL ;
    SHAPE ABUTMENT ;
    PORT
      LAYER met2 ;
      RECT 756.170 0.000 756.310 0.420 ;
    END
  END rw0_rd_out[17]
  PIN rw0_rd_out[18]
    DIRECTION OUTPUT ;
    USE SIGNAL ;
    SHAPE ABUTMENT ;
    PORT
      LAYER met2 ;
      RECT 758.930 0.000 759.070 0.420 ;
    END
  END rw0_rd_out[18]
  PIN rw0_rd_out[19]
    DIRECTION OUTPUT ;
    USE SIGNAL ;
    SHAPE ABUTMENT ;
    PORT
      LAYER met2 ;
      RECT 761.690 0.000 761.830 0.420 ;
    END
  END rw0_rd_out[19]
  PIN rw0_rd_out[20]
    DIRECTION OUTPUT ;
    USE SIGNAL ;
    SHAPE ABUTMENT ;
    PORT
      LAYER met2 ;
      RECT 764.450 0.000 764.590 0.420 ;
    END
  END rw0_rd_out[20]
  PIN rw0_rd_out[21]
    DIRECTION OUTPUT ;
    USE SIGNAL ;
    SHAPE ABUTMENT ;
    PORT
      LAYER met2 ;
      RECT 767.210 0.000 767.350 0.420 ;
    END
  END rw0_rd_out[21]
  PIN rw0_rd_out[22]
    DIRECTION OUTPUT ;
    USE SIGNAL ;
    SHAPE ABUTMENT ;
    PORT
      LAYER met2 ;
      RECT 769.970 0.000 770.110 0.420 ;
    END
  END rw0_rd_out[22]
  PIN rw0_rd_out[23]
    DIRECTION OUTPUT ;
    USE SIGNAL ;
    SHAPE ABUTMENT ;
    PORT
      LAYER met2 ;
      RECT 772.730 0.000 772.870 0.420 ;
    END
  END rw0_rd_out[23]
  PIN rw0_rd_out[24]
    DIRECTION OUTPUT ;
    USE SIGNAL ;
    SHAPE ABUTMENT ;
    PORT
      LAYER met2 ;
      RECT 775.490 0.000 775.630 0.420 ;
    END
  END rw0_rd_out[24]
  PIN rw0_rd_out[25]
    DIRECTION OUTPUT ;
    USE SIGNAL ;
    SHAPE ABUTMENT ;
    PORT
      LAYER met2 ;
      RECT 778.250 0.000 778.390 0.420 ;
    END
  END rw0_rd_out[25]
  PIN rw0_rd_out[26]
    DIRECTION OUTPUT ;
    USE SIGNAL ;
    SHAPE ABUTMENT ;
    PORT
      LAYER met2 ;
      RECT 781.010 0.000 781.150 0.420 ;
    END
  END rw0_rd_out[26]
  PIN rw0_rd_out[27]
    DIRECTION OUTPUT ;
    USE SIGNAL ;
    SHAPE ABUTMENT ;
    PORT
      LAYER met2 ;
      RECT 783.770 0.000 783.910 0.420 ;
    END
  END rw0_rd_out[27]
  PIN rw0_rd_out[28]
    DIRECTION OUTPUT ;
    USE SIGNAL ;
    SHAPE ABUTMENT ;
    PORT
      LAYER met2 ;
      RECT 786.530 0.000 786.670 0.420 ;
    END
  END rw0_rd_out[28]
  PIN rw0_rd_out[29]
    DIRECTION OUTPUT ;
    USE SIGNAL ;
    SHAPE ABUTMENT ;
    PORT
      LAYER met2 ;
      RECT 789.290 0.000 789.430 0.420 ;
    END
  END rw0_rd_out[29]
  PIN rw0_rd_out[30]
    DIRECTION OUTPUT ;
    USE SIGNAL ;
    SHAPE ABUTMENT ;
    PORT
      LAYER met2 ;
      RECT 792.050 0.000 792.190 0.420 ;
    END
  END rw0_rd_out[30]
  PIN rw0_rd_out[31]
    DIRECTION OUTPUT ;
    USE SIGNAL ;
    SHAPE ABUTMENT ;
    PORT
      LAYER met2 ;
      RECT 794.810 0.000 794.950 0.420 ;
    END
  END rw0_rd_out[31]
  PIN rw0_rd_out[32]
    DIRECTION OUTPUT ;
    USE SIGNAL ;
    SHAPE ABUTMENT ;
    PORT
      LAYER met2 ;
      RECT 797.570 0.000 797.710 0.420 ;
    END
  END rw0_rd_out[32]
  PIN rw0_rd_out[33]
    DIRECTION OUTPUT ;
    USE SIGNAL ;
    SHAPE ABUTMENT ;
    PORT
      LAYER met2 ;
      RECT 800.330 0.000 800.470 0.420 ;
    END
  END rw0_rd_out[33]
  PIN rw0_rd_out[34]
    DIRECTION OUTPUT ;
    USE SIGNAL ;
    SHAPE ABUTMENT ;
    PORT
      LAYER met2 ;
      RECT 803.090 0.000 803.230 0.420 ;
    END
  END rw0_rd_out[34]
  PIN rw0_rd_out[35]
    DIRECTION OUTPUT ;
    USE SIGNAL ;
    SHAPE ABUTMENT ;
    PORT
      LAYER met2 ;
      RECT 805.850 0.000 805.990 0.420 ;
    END
  END rw0_rd_out[35]
  PIN rw0_rd_out[36]
    DIRECTION OUTPUT ;
    USE SIGNAL ;
    SHAPE ABUTMENT ;
    PORT
      LAYER met2 ;
      RECT 808.610 0.000 808.750 0.420 ;
    END
  END rw0_rd_out[36]
  PIN rw0_rd_out[37]
    DIRECTION OUTPUT ;
    USE SIGNAL ;
    SHAPE ABUTMENT ;
    PORT
      LAYER met2 ;
      RECT 811.370 0.000 811.510 0.420 ;
    END
  END rw0_rd_out[37]
  PIN rw0_rd_out[38]
    DIRECTION OUTPUT ;
    USE SIGNAL ;
    SHAPE ABUTMENT ;
    PORT
      LAYER met2 ;
      RECT 814.130 0.000 814.270 0.420 ;
    END
  END rw0_rd_out[38]
  PIN rw0_rd_out[39]
    DIRECTION OUTPUT ;
    USE SIGNAL ;
    SHAPE ABUTMENT ;
    PORT
      LAYER met2 ;
      RECT 816.890 0.000 817.030 0.420 ;
    END
  END rw0_rd_out[39]
  PIN rw0_rd_out[40]
    DIRECTION OUTPUT ;
    USE SIGNAL ;
    SHAPE ABUTMENT ;
    PORT
      LAYER met2 ;
      RECT 819.650 0.000 819.790 0.420 ;
    END
  END rw0_rd_out[40]
  PIN rw0_rd_out[41]
    DIRECTION OUTPUT ;
    USE SIGNAL ;
    SHAPE ABUTMENT ;
    PORT
      LAYER met2 ;
      RECT 822.410 0.000 822.550 0.420 ;
    END
  END rw0_rd_out[41]
  PIN rw0_rd_out[42]
    DIRECTION OUTPUT ;
    USE SIGNAL ;
    SHAPE ABUTMENT ;
    PORT
      LAYER met2 ;
      RECT 825.170 0.000 825.310 0.420 ;
    END
  END rw0_rd_out[42]
  PIN rw0_rd_out[43]
    DIRECTION OUTPUT ;
    USE SIGNAL ;
    SHAPE ABUTMENT ;
    PORT
      LAYER met2 ;
      RECT 827.930 0.000 828.070 0.420 ;
    END
  END rw0_rd_out[43]
  PIN rw0_rd_out[44]
    DIRECTION OUTPUT ;
    USE SIGNAL ;
    SHAPE ABUTMENT ;
    PORT
      LAYER met2 ;
      RECT 830.690 0.000 830.830 0.420 ;
    END
  END rw0_rd_out[44]
  PIN rw0_rd_out[45]
    DIRECTION OUTPUT ;
    USE SIGNAL ;
    SHAPE ABUTMENT ;
    PORT
      LAYER met2 ;
      RECT 833.450 0.000 833.590 0.420 ;
    END
  END rw0_rd_out[45]
  PIN rw0_rd_out[46]
    DIRECTION OUTPUT ;
    USE SIGNAL ;
    SHAPE ABUTMENT ;
    PORT
      LAYER met2 ;
      RECT 836.210 0.000 836.350 0.420 ;
    END
  END rw0_rd_out[46]
  PIN rw0_rd_out[47]
    DIRECTION OUTPUT ;
    USE SIGNAL ;
    SHAPE ABUTMENT ;
    PORT
      LAYER met2 ;
      RECT 838.970 0.000 839.110 0.420 ;
    END
  END rw0_rd_out[47]
  PIN rw0_rd_out[48]
    DIRECTION OUTPUT ;
    USE SIGNAL ;
    SHAPE ABUTMENT ;
    PORT
      LAYER met2 ;
      RECT 841.730 0.000 841.870 0.420 ;
    END
  END rw0_rd_out[48]
  PIN rw0_rd_out[49]
    DIRECTION OUTPUT ;
    USE SIGNAL ;
    SHAPE ABUTMENT ;
    PORT
      LAYER met2 ;
      RECT 844.490 0.000 844.630 0.420 ;
    END
  END rw0_rd_out[49]
  PIN rw0_rd_out[50]
    DIRECTION OUTPUT ;
    USE SIGNAL ;
    SHAPE ABUTMENT ;
    PORT
      LAYER met2 ;
      RECT 847.250 0.000 847.390 0.420 ;
    END
  END rw0_rd_out[50]
  PIN rw0_rd_out[51]
    DIRECTION OUTPUT ;
    USE SIGNAL ;
    SHAPE ABUTMENT ;
    PORT
      LAYER met2 ;
      RECT 850.010 0.000 850.150 0.420 ;
    END
  END rw0_rd_out[51]
  PIN rw0_rd_out[52]
    DIRECTION OUTPUT ;
    USE SIGNAL ;
    SHAPE ABUTMENT ;
    PORT
      LAYER met2 ;
      RECT 852.770 0.000 852.910 0.420 ;
    END
  END rw0_rd_out[52]
  PIN rw0_rd_out[53]
    DIRECTION OUTPUT ;
    USE SIGNAL ;
    SHAPE ABUTMENT ;
    PORT
      LAYER met2 ;
      RECT 855.530 0.000 855.670 0.420 ;
    END
  END rw0_rd_out[53]
  PIN rw0_rd_out[54]
    DIRECTION OUTPUT ;
    USE SIGNAL ;
    SHAPE ABUTMENT ;
    PORT
      LAYER met2 ;
      RECT 858.290 0.000 858.430 0.420 ;
    END
  END rw0_rd_out[54]
  PIN rw0_rd_out[55]
    DIRECTION OUTPUT ;
    USE SIGNAL ;
    SHAPE ABUTMENT ;
    PORT
      LAYER met2 ;
      RECT 861.050 0.000 861.190 0.420 ;
    END
  END rw0_rd_out[55]
  PIN rw0_rd_out[56]
    DIRECTION OUTPUT ;
    USE SIGNAL ;
    SHAPE ABUTMENT ;
    PORT
      LAYER met2 ;
      RECT 863.810 0.000 863.950 0.420 ;
    END
  END rw0_rd_out[56]
  PIN rw0_rd_out[57]
    DIRECTION OUTPUT ;
    USE SIGNAL ;
    SHAPE ABUTMENT ;
    PORT
      LAYER met2 ;
      RECT 866.570 0.000 866.710 0.420 ;
    END
  END rw0_rd_out[57]
  PIN rw0_rd_out[58]
    DIRECTION OUTPUT ;
    USE SIGNAL ;
    SHAPE ABUTMENT ;
    PORT
      LAYER met2 ;
      RECT 869.330 0.000 869.470 0.420 ;
    END
  END rw0_rd_out[58]
  PIN rw0_rd_out[59]
    DIRECTION OUTPUT ;
    USE SIGNAL ;
    SHAPE ABUTMENT ;
    PORT
      LAYER met2 ;
      RECT 872.090 0.000 872.230 0.420 ;
    END
  END rw0_rd_out[59]
  PIN rw0_rd_out[60]
    DIRECTION OUTPUT ;
    USE SIGNAL ;
    SHAPE ABUTMENT ;
    PORT
      LAYER met2 ;
      RECT 874.850 0.000 874.990 0.420 ;
    END
  END rw0_rd_out[60]
  PIN rw0_rd_out[61]
    DIRECTION OUTPUT ;
    USE SIGNAL ;
    SHAPE ABUTMENT ;
    PORT
      LAYER met2 ;
      RECT 877.610 0.000 877.750 0.420 ;
    END
  END rw0_rd_out[61]
  PIN rw0_rd_out[62]
    DIRECTION OUTPUT ;
    USE SIGNAL ;
    SHAPE ABUTMENT ;
    PORT
      LAYER met2 ;
      RECT 880.370 0.000 880.510 0.420 ;
    END
  END rw0_rd_out[62]
  PIN rw0_rd_out[63]
    DIRECTION OUTPUT ;
    USE SIGNAL ;
    SHAPE ABUTMENT ;
    PORT
      LAYER met2 ;
      RECT 883.130 0.000 883.270 0.420 ;
    END
  END rw0_rd_out[63]
  PIN rw0_rd_out[64]
    DIRECTION OUTPUT ;
    USE SIGNAL ;
    SHAPE ABUTMENT ;
    PORT
      LAYER met2 ;
      RECT 885.890 0.000 886.030 0.420 ;
    END
  END rw0_rd_out[64]
  PIN rw0_rd_out[65]
    DIRECTION OUTPUT ;
    USE SIGNAL ;
    SHAPE ABUTMENT ;
    PORT
      LAYER met2 ;
      RECT 888.650 0.000 888.790 0.420 ;
    END
  END rw0_rd_out[65]
  PIN rw0_rd_out[66]
    DIRECTION OUTPUT ;
    USE SIGNAL ;
    SHAPE ABUTMENT ;
    PORT
      LAYER met2 ;
      RECT 891.410 0.000 891.550 0.420 ;
    END
  END rw0_rd_out[66]
  PIN rw0_rd_out[67]
    DIRECTION OUTPUT ;
    USE SIGNAL ;
    SHAPE ABUTMENT ;
    PORT
      LAYER met2 ;
      RECT 894.170 0.000 894.310 0.420 ;
    END
  END rw0_rd_out[67]
  PIN rw0_rd_out[68]
    DIRECTION OUTPUT ;
    USE SIGNAL ;
    SHAPE ABUTMENT ;
    PORT
      LAYER met2 ;
      RECT 896.930 0.000 897.070 0.420 ;
    END
  END rw0_rd_out[68]
  PIN rw0_rd_out[69]
    DIRECTION OUTPUT ;
    USE SIGNAL ;
    SHAPE ABUTMENT ;
    PORT
      LAYER met2 ;
      RECT 899.690 0.000 899.830 0.420 ;
    END
  END rw0_rd_out[69]
  PIN rw0_rd_out[70]
    DIRECTION OUTPUT ;
    USE SIGNAL ;
    SHAPE ABUTMENT ;
    PORT
      LAYER met2 ;
      RECT 902.450 0.000 902.590 0.420 ;
    END
  END rw0_rd_out[70]
  PIN rw0_rd_out[71]
    DIRECTION OUTPUT ;
    USE SIGNAL ;
    SHAPE ABUTMENT ;
    PORT
      LAYER met2 ;
      RECT 905.210 0.000 905.350 0.420 ;
    END
  END rw0_rd_out[71]
  PIN rw0_rd_out[72]
    DIRECTION OUTPUT ;
    USE SIGNAL ;
    SHAPE ABUTMENT ;
    PORT
      LAYER met2 ;
      RECT 907.970 0.000 908.110 0.420 ;
    END
  END rw0_rd_out[72]
  PIN rw0_rd_out[73]
    DIRECTION OUTPUT ;
    USE SIGNAL ;
    SHAPE ABUTMENT ;
    PORT
      LAYER met2 ;
      RECT 910.730 0.000 910.870 0.420 ;
    END
  END rw0_rd_out[73]
  PIN rw0_rd_out[74]
    DIRECTION OUTPUT ;
    USE SIGNAL ;
    SHAPE ABUTMENT ;
    PORT
      LAYER met2 ;
      RECT 913.490 0.000 913.630 0.420 ;
    END
  END rw0_rd_out[74]
  PIN rw0_rd_out[75]
    DIRECTION OUTPUT ;
    USE SIGNAL ;
    SHAPE ABUTMENT ;
    PORT
      LAYER met2 ;
      RECT 916.250 0.000 916.390 0.420 ;
    END
  END rw0_rd_out[75]
  PIN rw0_rd_out[76]
    DIRECTION OUTPUT ;
    USE SIGNAL ;
    SHAPE ABUTMENT ;
    PORT
      LAYER met2 ;
      RECT 919.010 0.000 919.150 0.420 ;
    END
  END rw0_rd_out[76]
  PIN rw0_rd_out[77]
    DIRECTION OUTPUT ;
    USE SIGNAL ;
    SHAPE ABUTMENT ;
    PORT
      LAYER met2 ;
      RECT 921.770 0.000 921.910 0.420 ;
    END
  END rw0_rd_out[77]
  PIN rw0_rd_out[78]
    DIRECTION OUTPUT ;
    USE SIGNAL ;
    SHAPE ABUTMENT ;
    PORT
      LAYER met2 ;
      RECT 924.530 0.000 924.670 0.420 ;
    END
  END rw0_rd_out[78]
  PIN rw0_rd_out[79]
    DIRECTION OUTPUT ;
    USE SIGNAL ;
    SHAPE ABUTMENT ;
    PORT
      LAYER met2 ;
      RECT 927.290 0.000 927.430 0.420 ;
    END
  END rw0_rd_out[79]
  PIN rw0_rd_out[80]
    DIRECTION OUTPUT ;
    USE SIGNAL ;
    SHAPE ABUTMENT ;
    PORT
      LAYER met2 ;
      RECT 930.050 0.000 930.190 0.420 ;
    END
  END rw0_rd_out[80]
  PIN rw0_rd_out[81]
    DIRECTION OUTPUT ;
    USE SIGNAL ;
    SHAPE ABUTMENT ;
    PORT
      LAYER met2 ;
      RECT 932.810 0.000 932.950 0.420 ;
    END
  END rw0_rd_out[81]
  PIN rw0_rd_out[82]
    DIRECTION OUTPUT ;
    USE SIGNAL ;
    SHAPE ABUTMENT ;
    PORT
      LAYER met2 ;
      RECT 935.570 0.000 935.710 0.420 ;
    END
  END rw0_rd_out[82]
  PIN rw0_rd_out[83]
    DIRECTION OUTPUT ;
    USE SIGNAL ;
    SHAPE ABUTMENT ;
    PORT
      LAYER met2 ;
      RECT 938.330 0.000 938.470 0.420 ;
    END
  END rw0_rd_out[83]
  PIN rw0_rd_out[84]
    DIRECTION OUTPUT ;
    USE SIGNAL ;
    SHAPE ABUTMENT ;
    PORT
      LAYER met2 ;
      RECT 941.090 0.000 941.230 0.420 ;
    END
  END rw0_rd_out[84]
  PIN rw0_rd_out[85]
    DIRECTION OUTPUT ;
    USE SIGNAL ;
    SHAPE ABUTMENT ;
    PORT
      LAYER met2 ;
      RECT 943.850 0.000 943.990 0.420 ;
    END
  END rw0_rd_out[85]
  PIN rw0_rd_out[86]
    DIRECTION OUTPUT ;
    USE SIGNAL ;
    SHAPE ABUTMENT ;
    PORT
      LAYER met2 ;
      RECT 946.610 0.000 946.750 0.420 ;
    END
  END rw0_rd_out[86]
  PIN rw0_rd_out[87]
    DIRECTION OUTPUT ;
    USE SIGNAL ;
    SHAPE ABUTMENT ;
    PORT
      LAYER met2 ;
      RECT 949.370 0.000 949.510 0.420 ;
    END
  END rw0_rd_out[87]
  PIN rw0_rd_out[88]
    DIRECTION OUTPUT ;
    USE SIGNAL ;
    SHAPE ABUTMENT ;
    PORT
      LAYER met2 ;
      RECT 952.130 0.000 952.270 0.420 ;
    END
  END rw0_rd_out[88]
  PIN rw0_rd_out[89]
    DIRECTION OUTPUT ;
    USE SIGNAL ;
    SHAPE ABUTMENT ;
    PORT
      LAYER met2 ;
      RECT 954.890 0.000 955.030 0.420 ;
    END
  END rw0_rd_out[89]
  PIN rw0_rd_out[90]
    DIRECTION OUTPUT ;
    USE SIGNAL ;
    SHAPE ABUTMENT ;
    PORT
      LAYER met2 ;
      RECT 957.650 0.000 957.790 0.420 ;
    END
  END rw0_rd_out[90]
  PIN rw0_rd_out[91]
    DIRECTION OUTPUT ;
    USE SIGNAL ;
    SHAPE ABUTMENT ;
    PORT
      LAYER met2 ;
      RECT 960.410 0.000 960.550 0.420 ;
    END
  END rw0_rd_out[91]
  PIN rw0_rd_out[92]
    DIRECTION OUTPUT ;
    USE SIGNAL ;
    SHAPE ABUTMENT ;
    PORT
      LAYER met2 ;
      RECT 963.170 0.000 963.310 0.420 ;
    END
  END rw0_rd_out[92]
  PIN rw0_rd_out[93]
    DIRECTION OUTPUT ;
    USE SIGNAL ;
    SHAPE ABUTMENT ;
    PORT
      LAYER met2 ;
      RECT 965.930 0.000 966.070 0.420 ;
    END
  END rw0_rd_out[93]
  PIN rw0_rd_out[94]
    DIRECTION OUTPUT ;
    USE SIGNAL ;
    SHAPE ABUTMENT ;
    PORT
      LAYER met2 ;
      RECT 968.690 0.000 968.830 0.420 ;
    END
  END rw0_rd_out[94]
  PIN rw0_rd_out[95]
    DIRECTION OUTPUT ;
    USE SIGNAL ;
    SHAPE ABUTMENT ;
    PORT
      LAYER met2 ;
      RECT 971.450 0.000 971.590 0.420 ;
    END
  END rw0_rd_out[95]
  PIN rw0_rd_out[96]
    DIRECTION OUTPUT ;
    USE SIGNAL ;
    SHAPE ABUTMENT ;
    PORT
      LAYER met2 ;
      RECT 974.210 0.000 974.350 0.420 ;
    END
  END rw0_rd_out[96]
  PIN rw0_rd_out[97]
    DIRECTION OUTPUT ;
    USE SIGNAL ;
    SHAPE ABUTMENT ;
    PORT
      LAYER met2 ;
      RECT 976.970 0.000 977.110 0.420 ;
    END
  END rw0_rd_out[97]
  PIN rw0_rd_out[98]
    DIRECTION OUTPUT ;
    USE SIGNAL ;
    SHAPE ABUTMENT ;
    PORT
      LAYER met2 ;
      RECT 979.730 0.000 979.870 0.420 ;
    END
  END rw0_rd_out[98]
  PIN rw0_rd_out[99]
    DIRECTION OUTPUT ;
    USE SIGNAL ;
    SHAPE ABUTMENT ;
    PORT
      LAYER met2 ;
      RECT 982.490 0.000 982.630 0.420 ;
    END
  END rw0_rd_out[99]
  PIN rw0_rd_out[100]
    DIRECTION OUTPUT ;
    USE SIGNAL ;
    SHAPE ABUTMENT ;
    PORT
      LAYER met2 ;
      RECT 985.250 0.000 985.390 0.420 ;
    END
  END rw0_rd_out[100]
  PIN rw0_rd_out[101]
    DIRECTION OUTPUT ;
    USE SIGNAL ;
    SHAPE ABUTMENT ;
    PORT
      LAYER met2 ;
      RECT 988.010 0.000 988.150 0.420 ;
    END
  END rw0_rd_out[101]
  PIN rw0_rd_out[102]
    DIRECTION OUTPUT ;
    USE SIGNAL ;
    SHAPE ABUTMENT ;
    PORT
      LAYER met2 ;
      RECT 990.770 0.000 990.910 0.420 ;
    END
  END rw0_rd_out[102]
  PIN rw0_rd_out[103]
    DIRECTION OUTPUT ;
    USE SIGNAL ;
    SHAPE ABUTMENT ;
    PORT
      LAYER met2 ;
      RECT 993.530 0.000 993.670 0.420 ;
    END
  END rw0_rd_out[103]
  PIN rw0_rd_out[104]
    DIRECTION OUTPUT ;
    USE SIGNAL ;
    SHAPE ABUTMENT ;
    PORT
      LAYER met2 ;
      RECT 996.290 0.000 996.430 0.420 ;
    END
  END rw0_rd_out[104]
  PIN rw0_rd_out[105]
    DIRECTION OUTPUT ;
    USE SIGNAL ;
    SHAPE ABUTMENT ;
    PORT
      LAYER met2 ;
      RECT 999.050 0.000 999.190 0.420 ;
    END
  END rw0_rd_out[105]
  PIN rw0_rd_out[106]
    DIRECTION OUTPUT ;
    USE SIGNAL ;
    SHAPE ABUTMENT ;
    PORT
      LAYER met2 ;
      RECT 1001.810 0.000 1001.950 0.420 ;
    END
  END rw0_rd_out[106]
  PIN rw0_rd_out[107]
    DIRECTION OUTPUT ;
    USE SIGNAL ;
    SHAPE ABUTMENT ;
    PORT
      LAYER met2 ;
      RECT 1004.570 0.000 1004.710 0.420 ;
    END
  END rw0_rd_out[107]
  PIN rw0_rd_out[108]
    DIRECTION OUTPUT ;
    USE SIGNAL ;
    SHAPE ABUTMENT ;
    PORT
      LAYER met2 ;
      RECT 1007.330 0.000 1007.470 0.420 ;
    END
  END rw0_rd_out[108]
  PIN rw0_rd_out[109]
    DIRECTION OUTPUT ;
    USE SIGNAL ;
    SHAPE ABUTMENT ;
    PORT
      LAYER met2 ;
      RECT 1010.090 0.000 1010.230 0.420 ;
    END
  END rw0_rd_out[109]
  PIN rw0_rd_out[110]
    DIRECTION OUTPUT ;
    USE SIGNAL ;
    SHAPE ABUTMENT ;
    PORT
      LAYER met2 ;
      RECT 1012.850 0.000 1012.990 0.420 ;
    END
  END rw0_rd_out[110]
  PIN rw0_rd_out[111]
    DIRECTION OUTPUT ;
    USE SIGNAL ;
    SHAPE ABUTMENT ;
    PORT
      LAYER met2 ;
      RECT 1015.610 0.000 1015.750 0.420 ;
    END
  END rw0_rd_out[111]
  PIN rw0_rd_out[112]
    DIRECTION OUTPUT ;
    USE SIGNAL ;
    SHAPE ABUTMENT ;
    PORT
      LAYER met2 ;
      RECT 1018.370 0.000 1018.510 0.420 ;
    END
  END rw0_rd_out[112]
  PIN rw0_rd_out[113]
    DIRECTION OUTPUT ;
    USE SIGNAL ;
    SHAPE ABUTMENT ;
    PORT
      LAYER met2 ;
      RECT 1021.130 0.000 1021.270 0.420 ;
    END
  END rw0_rd_out[113]
  PIN rw0_rd_out[114]
    DIRECTION OUTPUT ;
    USE SIGNAL ;
    SHAPE ABUTMENT ;
    PORT
      LAYER met2 ;
      RECT 1023.890 0.000 1024.030 0.420 ;
    END
  END rw0_rd_out[114]
  PIN rw0_rd_out[115]
    DIRECTION OUTPUT ;
    USE SIGNAL ;
    SHAPE ABUTMENT ;
    PORT
      LAYER met2 ;
      RECT 1026.650 0.000 1026.790 0.420 ;
    END
  END rw0_rd_out[115]
  PIN rw0_rd_out[116]
    DIRECTION OUTPUT ;
    USE SIGNAL ;
    SHAPE ABUTMENT ;
    PORT
      LAYER met2 ;
      RECT 1029.410 0.000 1029.550 0.420 ;
    END
  END rw0_rd_out[116]
  PIN rw0_rd_out[117]
    DIRECTION OUTPUT ;
    USE SIGNAL ;
    SHAPE ABUTMENT ;
    PORT
      LAYER met2 ;
      RECT 1032.170 0.000 1032.310 0.420 ;
    END
  END rw0_rd_out[117]
  PIN rw0_rd_out[118]
    DIRECTION OUTPUT ;
    USE SIGNAL ;
    SHAPE ABUTMENT ;
    PORT
      LAYER met2 ;
      RECT 1034.930 0.000 1035.070 0.420 ;
    END
  END rw0_rd_out[118]
  PIN rw0_rd_out[119]
    DIRECTION OUTPUT ;
    USE SIGNAL ;
    SHAPE ABUTMENT ;
    PORT
      LAYER met2 ;
      RECT 1037.690 0.000 1037.830 0.420 ;
    END
  END rw0_rd_out[119]
  PIN rw0_rd_out[120]
    DIRECTION OUTPUT ;
    USE SIGNAL ;
    SHAPE ABUTMENT ;
    PORT
      LAYER met2 ;
      RECT 1040.450 0.000 1040.590 0.420 ;
    END
  END rw0_rd_out[120]
  PIN rw0_rd_out[121]
    DIRECTION OUTPUT ;
    USE SIGNAL ;
    SHAPE ABUTMENT ;
    PORT
      LAYER met2 ;
      RECT 1043.210 0.000 1043.350 0.420 ;
    END
  END rw0_rd_out[121]
  PIN rw0_rd_out[122]
    DIRECTION OUTPUT ;
    USE SIGNAL ;
    SHAPE ABUTMENT ;
    PORT
      LAYER met2 ;
      RECT 1045.970 0.000 1046.110 0.420 ;
    END
  END rw0_rd_out[122]
  PIN rw0_rd_out[123]
    DIRECTION OUTPUT ;
    USE SIGNAL ;
    SHAPE ABUTMENT ;
    PORT
      LAYER met2 ;
      RECT 1048.730 0.000 1048.870 0.420 ;
    END
  END rw0_rd_out[123]
  PIN rw0_rd_out[124]
    DIRECTION OUTPUT ;
    USE SIGNAL ;
    SHAPE ABUTMENT ;
    PORT
      LAYER met2 ;
      RECT 1051.490 0.000 1051.630 0.420 ;
    END
  END rw0_rd_out[124]
  PIN rw0_rd_out[125]
    DIRECTION OUTPUT ;
    USE SIGNAL ;
    SHAPE ABUTMENT ;
    PORT
      LAYER met2 ;
      RECT 1054.250 0.000 1054.390 0.420 ;
    END
  END rw0_rd_out[125]
  PIN rw0_rd_out[126]
    DIRECTION OUTPUT ;
    USE SIGNAL ;
    SHAPE ABUTMENT ;
    PORT
      LAYER met2 ;
      RECT 1057.010 0.000 1057.150 0.420 ;
    END
  END rw0_rd_out[126]
  PIN rw0_rd_out[127]
    DIRECTION OUTPUT ;
    USE SIGNAL ;
    SHAPE ABUTMENT ;
    PORT
      LAYER met2 ;
      RECT 1059.770 0.000 1059.910 0.420 ;
    END
  END rw0_rd_out[127]
  PIN rw0_rd_out[128]
    DIRECTION OUTPUT ;
    USE SIGNAL ;
    SHAPE ABUTMENT ;
    PORT
      LAYER met2 ;
      RECT 1062.530 0.000 1062.670 0.420 ;
    END
  END rw0_rd_out[128]
  PIN rw0_rd_out[129]
    DIRECTION OUTPUT ;
    USE SIGNAL ;
    SHAPE ABUTMENT ;
    PORT
      LAYER met2 ;
      RECT 1065.290 0.000 1065.430 0.420 ;
    END
  END rw0_rd_out[129]
  PIN rw0_rd_out[130]
    DIRECTION OUTPUT ;
    USE SIGNAL ;
    SHAPE ABUTMENT ;
    PORT
      LAYER met2 ;
      RECT 1068.050 0.000 1068.190 0.420 ;
    END
  END rw0_rd_out[130]
  PIN rw0_rd_out[131]
    DIRECTION OUTPUT ;
    USE SIGNAL ;
    SHAPE ABUTMENT ;
    PORT
      LAYER met2 ;
      RECT 1070.810 0.000 1070.950 0.420 ;
    END
  END rw0_rd_out[131]
  PIN rw0_rd_out[132]
    DIRECTION OUTPUT ;
    USE SIGNAL ;
    SHAPE ABUTMENT ;
    PORT
      LAYER met2 ;
      RECT 1073.570 0.000 1073.710 0.420 ;
    END
  END rw0_rd_out[132]
  PIN rw0_rd_out[133]
    DIRECTION OUTPUT ;
    USE SIGNAL ;
    SHAPE ABUTMENT ;
    PORT
      LAYER met2 ;
      RECT 1076.330 0.000 1076.470 0.420 ;
    END
  END rw0_rd_out[133]
  PIN rw0_rd_out[134]
    DIRECTION OUTPUT ;
    USE SIGNAL ;
    SHAPE ABUTMENT ;
    PORT
      LAYER met2 ;
      RECT 1079.090 0.000 1079.230 0.420 ;
    END
  END rw0_rd_out[134]
  PIN rw0_rd_out[135]
    DIRECTION OUTPUT ;
    USE SIGNAL ;
    SHAPE ABUTMENT ;
    PORT
      LAYER met2 ;
      RECT 1081.850 0.000 1081.990 0.420 ;
    END
  END rw0_rd_out[135]
  PIN rw0_rd_out[136]
    DIRECTION OUTPUT ;
    USE SIGNAL ;
    SHAPE ABUTMENT ;
    PORT
      LAYER met2 ;
      RECT 1084.610 0.000 1084.750 0.420 ;
    END
  END rw0_rd_out[136]
  PIN rw0_rd_out[137]
    DIRECTION OUTPUT ;
    USE SIGNAL ;
    SHAPE ABUTMENT ;
    PORT
      LAYER met2 ;
      RECT 1087.370 0.000 1087.510 0.420 ;
    END
  END rw0_rd_out[137]
  PIN rw0_rd_out[138]
    DIRECTION OUTPUT ;
    USE SIGNAL ;
    SHAPE ABUTMENT ;
    PORT
      LAYER met2 ;
      RECT 1090.130 0.000 1090.270 0.420 ;
    END
  END rw0_rd_out[138]
  PIN rw0_rd_out[139]
    DIRECTION OUTPUT ;
    USE SIGNAL ;
    SHAPE ABUTMENT ;
    PORT
      LAYER met2 ;
      RECT 1092.890 0.000 1093.030 0.420 ;
    END
  END rw0_rd_out[139]
  PIN rw0_rd_out[140]
    DIRECTION OUTPUT ;
    USE SIGNAL ;
    SHAPE ABUTMENT ;
    PORT
      LAYER met2 ;
      RECT 1095.650 0.000 1095.790 0.420 ;
    END
  END rw0_rd_out[140]
  PIN rw0_rd_out[141]
    DIRECTION OUTPUT ;
    USE SIGNAL ;
    SHAPE ABUTMENT ;
    PORT
      LAYER met2 ;
      RECT 1098.410 0.000 1098.550 0.420 ;
    END
  END rw0_rd_out[141]
  PIN rw0_rd_out[142]
    DIRECTION OUTPUT ;
    USE SIGNAL ;
    SHAPE ABUTMENT ;
    PORT
      LAYER met2 ;
      RECT 1101.170 0.000 1101.310 0.420 ;
    END
  END rw0_rd_out[142]
  PIN rw0_rd_out[143]
    DIRECTION OUTPUT ;
    USE SIGNAL ;
    SHAPE ABUTMENT ;
    PORT
      LAYER met2 ;
      RECT 1103.930 0.000 1104.070 0.420 ;
    END
  END rw0_rd_out[143]
  PIN rw0_rd_out[144]
    DIRECTION OUTPUT ;
    USE SIGNAL ;
    SHAPE ABUTMENT ;
    PORT
      LAYER met2 ;
      RECT 1106.690 0.000 1106.830 0.420 ;
    END
  END rw0_rd_out[144]
  PIN rw0_rd_out[145]
    DIRECTION OUTPUT ;
    USE SIGNAL ;
    SHAPE ABUTMENT ;
    PORT
      LAYER met2 ;
      RECT 1109.450 0.000 1109.590 0.420 ;
    END
  END rw0_rd_out[145]
  PIN rw0_rd_out[146]
    DIRECTION OUTPUT ;
    USE SIGNAL ;
    SHAPE ABUTMENT ;
    PORT
      LAYER met2 ;
      RECT 1112.210 0.000 1112.350 0.420 ;
    END
  END rw0_rd_out[146]
  PIN rw0_rd_out[147]
    DIRECTION OUTPUT ;
    USE SIGNAL ;
    SHAPE ABUTMENT ;
    PORT
      LAYER met2 ;
      RECT 1114.970 0.000 1115.110 0.420 ;
    END
  END rw0_rd_out[147]
  PIN rw0_rd_out[148]
    DIRECTION OUTPUT ;
    USE SIGNAL ;
    SHAPE ABUTMENT ;
    PORT
      LAYER met2 ;
      RECT 1117.730 0.000 1117.870 0.420 ;
    END
  END rw0_rd_out[148]
  PIN rw0_rd_out[149]
    DIRECTION OUTPUT ;
    USE SIGNAL ;
    SHAPE ABUTMENT ;
    PORT
      LAYER met2 ;
      RECT 1120.490 0.000 1120.630 0.420 ;
    END
  END rw0_rd_out[149]
  PIN rw0_rd_out[150]
    DIRECTION OUTPUT ;
    USE SIGNAL ;
    SHAPE ABUTMENT ;
    PORT
      LAYER met2 ;
      RECT 1123.250 0.000 1123.390 0.420 ;
    END
  END rw0_rd_out[150]
  PIN rw0_rd_out[151]
    DIRECTION OUTPUT ;
    USE SIGNAL ;
    SHAPE ABUTMENT ;
    PORT
      LAYER met2 ;
      RECT 1126.010 0.000 1126.150 0.420 ;
    END
  END rw0_rd_out[151]
  PIN rw0_rd_out[152]
    DIRECTION OUTPUT ;
    USE SIGNAL ;
    SHAPE ABUTMENT ;
    PORT
      LAYER met2 ;
      RECT 1128.770 0.000 1128.910 0.420 ;
    END
  END rw0_rd_out[152]
  PIN rw0_rd_out[153]
    DIRECTION OUTPUT ;
    USE SIGNAL ;
    SHAPE ABUTMENT ;
    PORT
      LAYER met2 ;
      RECT 1131.530 0.000 1131.670 0.420 ;
    END
  END rw0_rd_out[153]
  PIN rw0_rd_out[154]
    DIRECTION OUTPUT ;
    USE SIGNAL ;
    SHAPE ABUTMENT ;
    PORT
      LAYER met2 ;
      RECT 1134.290 0.000 1134.430 0.420 ;
    END
  END rw0_rd_out[154]
  PIN rw0_rd_out[155]
    DIRECTION OUTPUT ;
    USE SIGNAL ;
    SHAPE ABUTMENT ;
    PORT
      LAYER met2 ;
      RECT 1137.050 0.000 1137.190 0.420 ;
    END
  END rw0_rd_out[155]
  PIN rw0_rd_out[156]
    DIRECTION OUTPUT ;
    USE SIGNAL ;
    SHAPE ABUTMENT ;
    PORT
      LAYER met2 ;
      RECT 1139.810 0.000 1139.950 0.420 ;
    END
  END rw0_rd_out[156]
  PIN rw0_rd_out[157]
    DIRECTION OUTPUT ;
    USE SIGNAL ;
    SHAPE ABUTMENT ;
    PORT
      LAYER met2 ;
      RECT 1142.570 0.000 1142.710 0.420 ;
    END
  END rw0_rd_out[157]
  PIN rw0_rd_out[158]
    DIRECTION OUTPUT ;
    USE SIGNAL ;
    SHAPE ABUTMENT ;
    PORT
      LAYER met2 ;
      RECT 1145.330 0.000 1145.470 0.420 ;
    END
  END rw0_rd_out[158]
  PIN rw0_rd_out[159]
    DIRECTION OUTPUT ;
    USE SIGNAL ;
    SHAPE ABUTMENT ;
    PORT
      LAYER met2 ;
      RECT 1148.090 0.000 1148.230 0.420 ;
    END
  END rw0_rd_out[159]
  PIN rw0_rd_out[160]
    DIRECTION OUTPUT ;
    USE SIGNAL ;
    SHAPE ABUTMENT ;
    PORT
      LAYER met2 ;
      RECT 1150.850 0.000 1150.990 0.420 ;
    END
  END rw0_rd_out[160]
  PIN rw0_rd_out[161]
    DIRECTION OUTPUT ;
    USE SIGNAL ;
    SHAPE ABUTMENT ;
    PORT
      LAYER met2 ;
      RECT 1153.610 0.000 1153.750 0.420 ;
    END
  END rw0_rd_out[161]
  PIN rw0_rd_out[162]
    DIRECTION OUTPUT ;
    USE SIGNAL ;
    SHAPE ABUTMENT ;
    PORT
      LAYER met2 ;
      RECT 1156.370 0.000 1156.510 0.420 ;
    END
  END rw0_rd_out[162]
  PIN rw0_rd_out[163]
    DIRECTION OUTPUT ;
    USE SIGNAL ;
    SHAPE ABUTMENT ;
    PORT
      LAYER met2 ;
      RECT 1159.130 0.000 1159.270 0.420 ;
    END
  END rw0_rd_out[163]
  PIN rw0_rd_out[164]
    DIRECTION OUTPUT ;
    USE SIGNAL ;
    SHAPE ABUTMENT ;
    PORT
      LAYER met2 ;
      RECT 1161.890 0.000 1162.030 0.420 ;
    END
  END rw0_rd_out[164]
  PIN rw0_rd_out[165]
    DIRECTION OUTPUT ;
    USE SIGNAL ;
    SHAPE ABUTMENT ;
    PORT
      LAYER met2 ;
      RECT 1164.650 0.000 1164.790 0.420 ;
    END
  END rw0_rd_out[165]
  PIN rw0_rd_out[166]
    DIRECTION OUTPUT ;
    USE SIGNAL ;
    SHAPE ABUTMENT ;
    PORT
      LAYER met2 ;
      RECT 1167.410 0.000 1167.550 0.420 ;
    END
  END rw0_rd_out[166]
  PIN rw0_rd_out[167]
    DIRECTION OUTPUT ;
    USE SIGNAL ;
    SHAPE ABUTMENT ;
    PORT
      LAYER met2 ;
      RECT 1170.170 0.000 1170.310 0.420 ;
    END
  END rw0_rd_out[167]
  PIN rw0_rd_out[168]
    DIRECTION OUTPUT ;
    USE SIGNAL ;
    SHAPE ABUTMENT ;
    PORT
      LAYER met2 ;
      RECT 1172.930 0.000 1173.070 0.420 ;
    END
  END rw0_rd_out[168]
  PIN rw0_rd_out[169]
    DIRECTION OUTPUT ;
    USE SIGNAL ;
    SHAPE ABUTMENT ;
    PORT
      LAYER met2 ;
      RECT 1175.690 0.000 1175.830 0.420 ;
    END
  END rw0_rd_out[169]
  PIN rw0_rd_out[170]
    DIRECTION OUTPUT ;
    USE SIGNAL ;
    SHAPE ABUTMENT ;
    PORT
      LAYER met2 ;
      RECT 1178.450 0.000 1178.590 0.420 ;
    END
  END rw0_rd_out[170]
  PIN rw0_rd_out[171]
    DIRECTION OUTPUT ;
    USE SIGNAL ;
    SHAPE ABUTMENT ;
    PORT
      LAYER met2 ;
      RECT 1181.210 0.000 1181.350 0.420 ;
    END
  END rw0_rd_out[171]
  PIN rw0_rd_out[172]
    DIRECTION OUTPUT ;
    USE SIGNAL ;
    SHAPE ABUTMENT ;
    PORT
      LAYER met2 ;
      RECT 1183.970 0.000 1184.110 0.420 ;
    END
  END rw0_rd_out[172]
  PIN rw0_rd_out[173]
    DIRECTION OUTPUT ;
    USE SIGNAL ;
    SHAPE ABUTMENT ;
    PORT
      LAYER met2 ;
      RECT 1186.730 0.000 1186.870 0.420 ;
    END
  END rw0_rd_out[173]
  PIN rw0_rd_out[174]
    DIRECTION OUTPUT ;
    USE SIGNAL ;
    SHAPE ABUTMENT ;
    PORT
      LAYER met2 ;
      RECT 1189.490 0.000 1189.630 0.420 ;
    END
  END rw0_rd_out[174]
  PIN rw0_rd_out[175]
    DIRECTION OUTPUT ;
    USE SIGNAL ;
    SHAPE ABUTMENT ;
    PORT
      LAYER met2 ;
      RECT 1192.250 0.000 1192.390 0.420 ;
    END
  END rw0_rd_out[175]
  PIN rw0_rd_out[176]
    DIRECTION OUTPUT ;
    USE SIGNAL ;
    SHAPE ABUTMENT ;
    PORT
      LAYER met2 ;
      RECT 1195.010 0.000 1195.150 0.420 ;
    END
  END rw0_rd_out[176]
  PIN rw0_rd_out[177]
    DIRECTION OUTPUT ;
    USE SIGNAL ;
    SHAPE ABUTMENT ;
    PORT
      LAYER met2 ;
      RECT 1197.770 0.000 1197.910 0.420 ;
    END
  END rw0_rd_out[177]
  PIN rw0_rd_out[178]
    DIRECTION OUTPUT ;
    USE SIGNAL ;
    SHAPE ABUTMENT ;
    PORT
      LAYER met2 ;
      RECT 1200.530 0.000 1200.670 0.420 ;
    END
  END rw0_rd_out[178]
  PIN rw0_rd_out[179]
    DIRECTION OUTPUT ;
    USE SIGNAL ;
    SHAPE ABUTMENT ;
    PORT
      LAYER met2 ;
      RECT 1203.290 0.000 1203.430 0.420 ;
    END
  END rw0_rd_out[179]
  PIN rw0_rd_out[180]
    DIRECTION OUTPUT ;
    USE SIGNAL ;
    SHAPE ABUTMENT ;
    PORT
      LAYER met2 ;
      RECT 1206.050 0.000 1206.190 0.420 ;
    END
  END rw0_rd_out[180]
  PIN rw0_rd_out[181]
    DIRECTION OUTPUT ;
    USE SIGNAL ;
    SHAPE ABUTMENT ;
    PORT
      LAYER met2 ;
      RECT 1208.810 0.000 1208.950 0.420 ;
    END
  END rw0_rd_out[181]
  PIN rw0_rd_out[182]
    DIRECTION OUTPUT ;
    USE SIGNAL ;
    SHAPE ABUTMENT ;
    PORT
      LAYER met2 ;
      RECT 1211.570 0.000 1211.710 0.420 ;
    END
  END rw0_rd_out[182]
  PIN rw0_rd_out[183]
    DIRECTION OUTPUT ;
    USE SIGNAL ;
    SHAPE ABUTMENT ;
    PORT
      LAYER met2 ;
      RECT 1214.330 0.000 1214.470 0.420 ;
    END
  END rw0_rd_out[183]
  PIN rw0_rd_out[184]
    DIRECTION OUTPUT ;
    USE SIGNAL ;
    SHAPE ABUTMENT ;
    PORT
      LAYER met2 ;
      RECT 1217.090 0.000 1217.230 0.420 ;
    END
  END rw0_rd_out[184]
  PIN rw0_rd_out[185]
    DIRECTION OUTPUT ;
    USE SIGNAL ;
    SHAPE ABUTMENT ;
    PORT
      LAYER met2 ;
      RECT 1219.850 0.000 1219.990 0.420 ;
    END
  END rw0_rd_out[185]
  PIN rw0_rd_out[186]
    DIRECTION OUTPUT ;
    USE SIGNAL ;
    SHAPE ABUTMENT ;
    PORT
      LAYER met2 ;
      RECT 1222.610 0.000 1222.750 0.420 ;
    END
  END rw0_rd_out[186]
  PIN rw0_rd_out[187]
    DIRECTION OUTPUT ;
    USE SIGNAL ;
    SHAPE ABUTMENT ;
    PORT
      LAYER met2 ;
      RECT 1225.370 0.000 1225.510 0.420 ;
    END
  END rw0_rd_out[187]
  PIN rw0_rd_out[188]
    DIRECTION OUTPUT ;
    USE SIGNAL ;
    SHAPE ABUTMENT ;
    PORT
      LAYER met2 ;
      RECT 1228.130 0.000 1228.270 0.420 ;
    END
  END rw0_rd_out[188]
  PIN rw0_rd_out[189]
    DIRECTION OUTPUT ;
    USE SIGNAL ;
    SHAPE ABUTMENT ;
    PORT
      LAYER met2 ;
      RECT 1230.890 0.000 1231.030 0.420 ;
    END
  END rw0_rd_out[189]
  PIN rw0_rd_out[190]
    DIRECTION OUTPUT ;
    USE SIGNAL ;
    SHAPE ABUTMENT ;
    PORT
      LAYER met2 ;
      RECT 1233.650 0.000 1233.790 0.420 ;
    END
  END rw0_rd_out[190]
  PIN rw0_rd_out[191]
    DIRECTION OUTPUT ;
    USE SIGNAL ;
    SHAPE ABUTMENT ;
    PORT
      LAYER met2 ;
      RECT 1236.410 0.000 1236.550 0.420 ;
    END
  END rw0_rd_out[191]
  PIN rw0_rd_out[192]
    DIRECTION OUTPUT ;
    USE SIGNAL ;
    SHAPE ABUTMENT ;
    PORT
      LAYER met2 ;
      RECT 1239.170 0.000 1239.310 0.420 ;
    END
  END rw0_rd_out[192]
  PIN rw0_rd_out[193]
    DIRECTION OUTPUT ;
    USE SIGNAL ;
    SHAPE ABUTMENT ;
    PORT
      LAYER met2 ;
      RECT 1241.930 0.000 1242.070 0.420 ;
    END
  END rw0_rd_out[193]
  PIN rw0_rd_out[194]
    DIRECTION OUTPUT ;
    USE SIGNAL ;
    SHAPE ABUTMENT ;
    PORT
      LAYER met2 ;
      RECT 1244.690 0.000 1244.830 0.420 ;
    END
  END rw0_rd_out[194]
  PIN rw0_rd_out[195]
    DIRECTION OUTPUT ;
    USE SIGNAL ;
    SHAPE ABUTMENT ;
    PORT
      LAYER met2 ;
      RECT 1247.450 0.000 1247.590 0.420 ;
    END
  END rw0_rd_out[195]
  PIN rw0_rd_out[196]
    DIRECTION OUTPUT ;
    USE SIGNAL ;
    SHAPE ABUTMENT ;
    PORT
      LAYER met2 ;
      RECT 1250.210 0.000 1250.350 0.420 ;
    END
  END rw0_rd_out[196]
  PIN rw0_rd_out[197]
    DIRECTION OUTPUT ;
    USE SIGNAL ;
    SHAPE ABUTMENT ;
    PORT
      LAYER met2 ;
      RECT 1252.970 0.000 1253.110 0.420 ;
    END
  END rw0_rd_out[197]
  PIN rw0_rd_out[198]
    DIRECTION OUTPUT ;
    USE SIGNAL ;
    SHAPE ABUTMENT ;
    PORT
      LAYER met2 ;
      RECT 1255.730 0.000 1255.870 0.420 ;
    END
  END rw0_rd_out[198]
  PIN rw0_rd_out[199]
    DIRECTION OUTPUT ;
    USE SIGNAL ;
    SHAPE ABUTMENT ;
    PORT
      LAYER met2 ;
      RECT 1258.490 0.000 1258.630 0.420 ;
    END
  END rw0_rd_out[199]
  PIN rw0_rd_out[200]
    DIRECTION OUTPUT ;
    USE SIGNAL ;
    SHAPE ABUTMENT ;
    PORT
      LAYER met2 ;
      RECT 1261.250 0.000 1261.390 0.420 ;
    END
  END rw0_rd_out[200]
  PIN rw0_rd_out[201]
    DIRECTION OUTPUT ;
    USE SIGNAL ;
    SHAPE ABUTMENT ;
    PORT
      LAYER met2 ;
      RECT 1264.010 0.000 1264.150 0.420 ;
    END
  END rw0_rd_out[201]
  PIN rw0_rd_out[202]
    DIRECTION OUTPUT ;
    USE SIGNAL ;
    SHAPE ABUTMENT ;
    PORT
      LAYER met2 ;
      RECT 1266.770 0.000 1266.910 0.420 ;
    END
  END rw0_rd_out[202]
  PIN rw0_rd_out[203]
    DIRECTION OUTPUT ;
    USE SIGNAL ;
    SHAPE ABUTMENT ;
    PORT
      LAYER met2 ;
      RECT 1269.530 0.000 1269.670 0.420 ;
    END
  END rw0_rd_out[203]
  PIN rw0_rd_out[204]
    DIRECTION OUTPUT ;
    USE SIGNAL ;
    SHAPE ABUTMENT ;
    PORT
      LAYER met2 ;
      RECT 1272.290 0.000 1272.430 0.420 ;
    END
  END rw0_rd_out[204]
  PIN rw0_rd_out[205]
    DIRECTION OUTPUT ;
    USE SIGNAL ;
    SHAPE ABUTMENT ;
    PORT
      LAYER met2 ;
      RECT 1275.050 0.000 1275.190 0.420 ;
    END
  END rw0_rd_out[205]
  PIN rw0_rd_out[206]
    DIRECTION OUTPUT ;
    USE SIGNAL ;
    SHAPE ABUTMENT ;
    PORT
      LAYER met2 ;
      RECT 1277.810 0.000 1277.950 0.420 ;
    END
  END rw0_rd_out[206]
  PIN rw0_rd_out[207]
    DIRECTION OUTPUT ;
    USE SIGNAL ;
    SHAPE ABUTMENT ;
    PORT
      LAYER met2 ;
      RECT 1280.570 0.000 1280.710 0.420 ;
    END
  END rw0_rd_out[207]
  PIN rw0_rd_out[208]
    DIRECTION OUTPUT ;
    USE SIGNAL ;
    SHAPE ABUTMENT ;
    PORT
      LAYER met2 ;
      RECT 1283.330 0.000 1283.470 0.420 ;
    END
  END rw0_rd_out[208]
  PIN rw0_rd_out[209]
    DIRECTION OUTPUT ;
    USE SIGNAL ;
    SHAPE ABUTMENT ;
    PORT
      LAYER met2 ;
      RECT 1286.090 0.000 1286.230 0.420 ;
    END
  END rw0_rd_out[209]
  PIN rw0_rd_out[210]
    DIRECTION OUTPUT ;
    USE SIGNAL ;
    SHAPE ABUTMENT ;
    PORT
      LAYER met2 ;
      RECT 1288.850 0.000 1288.990 0.420 ;
    END
  END rw0_rd_out[210]
  PIN rw0_rd_out[211]
    DIRECTION OUTPUT ;
    USE SIGNAL ;
    SHAPE ABUTMENT ;
    PORT
      LAYER met2 ;
      RECT 1291.610 0.000 1291.750 0.420 ;
    END
  END rw0_rd_out[211]
  PIN rw0_rd_out[212]
    DIRECTION OUTPUT ;
    USE SIGNAL ;
    SHAPE ABUTMENT ;
    PORT
      LAYER met2 ;
      RECT 1294.370 0.000 1294.510 0.420 ;
    END
  END rw0_rd_out[212]
  PIN rw0_rd_out[213]
    DIRECTION OUTPUT ;
    USE SIGNAL ;
    SHAPE ABUTMENT ;
    PORT
      LAYER met2 ;
      RECT 1297.130 0.000 1297.270 0.420 ;
    END
  END rw0_rd_out[213]
  PIN rw0_rd_out[214]
    DIRECTION OUTPUT ;
    USE SIGNAL ;
    SHAPE ABUTMENT ;
    PORT
      LAYER met2 ;
      RECT 1299.890 0.000 1300.030 0.420 ;
    END
  END rw0_rd_out[214]
  PIN rw0_rd_out[215]
    DIRECTION OUTPUT ;
    USE SIGNAL ;
    SHAPE ABUTMENT ;
    PORT
      LAYER met2 ;
      RECT 1302.650 0.000 1302.790 0.420 ;
    END
  END rw0_rd_out[215]
  PIN rw0_rd_out[216]
    DIRECTION OUTPUT ;
    USE SIGNAL ;
    SHAPE ABUTMENT ;
    PORT
      LAYER met2 ;
      RECT 1305.410 0.000 1305.550 0.420 ;
    END
  END rw0_rd_out[216]
  PIN rw0_rd_out[217]
    DIRECTION OUTPUT ;
    USE SIGNAL ;
    SHAPE ABUTMENT ;
    PORT
      LAYER met2 ;
      RECT 1308.170 0.000 1308.310 0.420 ;
    END
  END rw0_rd_out[217]
  PIN rw0_rd_out[218]
    DIRECTION OUTPUT ;
    USE SIGNAL ;
    SHAPE ABUTMENT ;
    PORT
      LAYER met2 ;
      RECT 1310.930 0.000 1311.070 0.420 ;
    END
  END rw0_rd_out[218]
  PIN rw0_rd_out[219]
    DIRECTION OUTPUT ;
    USE SIGNAL ;
    SHAPE ABUTMENT ;
    PORT
      LAYER met2 ;
      RECT 1313.690 0.000 1313.830 0.420 ;
    END
  END rw0_rd_out[219]
  PIN rw0_rd_out[220]
    DIRECTION OUTPUT ;
    USE SIGNAL ;
    SHAPE ABUTMENT ;
    PORT
      LAYER met2 ;
      RECT 1316.450 0.000 1316.590 0.420 ;
    END
  END rw0_rd_out[220]
  PIN rw0_rd_out[221]
    DIRECTION OUTPUT ;
    USE SIGNAL ;
    SHAPE ABUTMENT ;
    PORT
      LAYER met2 ;
      RECT 1319.210 0.000 1319.350 0.420 ;
    END
  END rw0_rd_out[221]
  PIN rw0_rd_out[222]
    DIRECTION OUTPUT ;
    USE SIGNAL ;
    SHAPE ABUTMENT ;
    PORT
      LAYER met2 ;
      RECT 1321.970 0.000 1322.110 0.420 ;
    END
  END rw0_rd_out[222]
  PIN rw0_rd_out[223]
    DIRECTION OUTPUT ;
    USE SIGNAL ;
    SHAPE ABUTMENT ;
    PORT
      LAYER met2 ;
      RECT 1324.730 0.000 1324.870 0.420 ;
    END
  END rw0_rd_out[223]
  PIN rw0_rd_out[224]
    DIRECTION OUTPUT ;
    USE SIGNAL ;
    SHAPE ABUTMENT ;
    PORT
      LAYER met2 ;
      RECT 1327.490 0.000 1327.630 0.420 ;
    END
  END rw0_rd_out[224]
  PIN rw0_rd_out[225]
    DIRECTION OUTPUT ;
    USE SIGNAL ;
    SHAPE ABUTMENT ;
    PORT
      LAYER met2 ;
      RECT 1330.250 0.000 1330.390 0.420 ;
    END
  END rw0_rd_out[225]
  PIN rw0_rd_out[226]
    DIRECTION OUTPUT ;
    USE SIGNAL ;
    SHAPE ABUTMENT ;
    PORT
      LAYER met2 ;
      RECT 1333.010 0.000 1333.150 0.420 ;
    END
  END rw0_rd_out[226]
  PIN rw0_rd_out[227]
    DIRECTION OUTPUT ;
    USE SIGNAL ;
    SHAPE ABUTMENT ;
    PORT
      LAYER met2 ;
      RECT 1335.770 0.000 1335.910 0.420 ;
    END
  END rw0_rd_out[227]
  PIN rw0_rd_out[228]
    DIRECTION OUTPUT ;
    USE SIGNAL ;
    SHAPE ABUTMENT ;
    PORT
      LAYER met2 ;
      RECT 1338.530 0.000 1338.670 0.420 ;
    END
  END rw0_rd_out[228]
  PIN rw0_rd_out[229]
    DIRECTION OUTPUT ;
    USE SIGNAL ;
    SHAPE ABUTMENT ;
    PORT
      LAYER met2 ;
      RECT 1341.290 0.000 1341.430 0.420 ;
    END
  END rw0_rd_out[229]
  PIN rw0_rd_out[230]
    DIRECTION OUTPUT ;
    USE SIGNAL ;
    SHAPE ABUTMENT ;
    PORT
      LAYER met2 ;
      RECT 1344.050 0.000 1344.190 0.420 ;
    END
  END rw0_rd_out[230]
  PIN rw0_rd_out[231]
    DIRECTION OUTPUT ;
    USE SIGNAL ;
    SHAPE ABUTMENT ;
    PORT
      LAYER met2 ;
      RECT 1346.810 0.000 1346.950 0.420 ;
    END
  END rw0_rd_out[231]
  PIN rw0_rd_out[232]
    DIRECTION OUTPUT ;
    USE SIGNAL ;
    SHAPE ABUTMENT ;
    PORT
      LAYER met2 ;
      RECT 1349.570 0.000 1349.710 0.420 ;
    END
  END rw0_rd_out[232]
  PIN rw0_rd_out[233]
    DIRECTION OUTPUT ;
    USE SIGNAL ;
    SHAPE ABUTMENT ;
    PORT
      LAYER met2 ;
      RECT 1352.330 0.000 1352.470 0.420 ;
    END
  END rw0_rd_out[233]
  PIN rw0_rd_out[234]
    DIRECTION OUTPUT ;
    USE SIGNAL ;
    SHAPE ABUTMENT ;
    PORT
      LAYER met2 ;
      RECT 1355.090 0.000 1355.230 0.420 ;
    END
  END rw0_rd_out[234]
  PIN rw0_rd_out[235]
    DIRECTION OUTPUT ;
    USE SIGNAL ;
    SHAPE ABUTMENT ;
    PORT
      LAYER met2 ;
      RECT 1357.850 0.000 1357.990 0.420 ;
    END
  END rw0_rd_out[235]
  PIN rw0_rd_out[236]
    DIRECTION OUTPUT ;
    USE SIGNAL ;
    SHAPE ABUTMENT ;
    PORT
      LAYER met2 ;
      RECT 1360.610 0.000 1360.750 0.420 ;
    END
  END rw0_rd_out[236]
  PIN rw0_rd_out[237]
    DIRECTION OUTPUT ;
    USE SIGNAL ;
    SHAPE ABUTMENT ;
    PORT
      LAYER met2 ;
      RECT 1363.370 0.000 1363.510 0.420 ;
    END
  END rw0_rd_out[237]
  PIN rw0_rd_out[238]
    DIRECTION OUTPUT ;
    USE SIGNAL ;
    SHAPE ABUTMENT ;
    PORT
      LAYER met2 ;
      RECT 1366.130 0.000 1366.270 0.420 ;
    END
  END rw0_rd_out[238]
  PIN rw0_rd_out[239]
    DIRECTION OUTPUT ;
    USE SIGNAL ;
    SHAPE ABUTMENT ;
    PORT
      LAYER met2 ;
      RECT 1368.890 0.000 1369.030 0.420 ;
    END
  END rw0_rd_out[239]
  PIN rw0_rd_out[240]
    DIRECTION OUTPUT ;
    USE SIGNAL ;
    SHAPE ABUTMENT ;
    PORT
      LAYER met2 ;
      RECT 1371.650 0.000 1371.790 0.420 ;
    END
  END rw0_rd_out[240]
  PIN rw0_rd_out[241]
    DIRECTION OUTPUT ;
    USE SIGNAL ;
    SHAPE ABUTMENT ;
    PORT
      LAYER met2 ;
      RECT 1374.410 0.000 1374.550 0.420 ;
    END
  END rw0_rd_out[241]
  PIN rw0_rd_out[242]
    DIRECTION OUTPUT ;
    USE SIGNAL ;
    SHAPE ABUTMENT ;
    PORT
      LAYER met2 ;
      RECT 1377.170 0.000 1377.310 0.420 ;
    END
  END rw0_rd_out[242]
  PIN rw0_rd_out[243]
    DIRECTION OUTPUT ;
    USE SIGNAL ;
    SHAPE ABUTMENT ;
    PORT
      LAYER met2 ;
      RECT 1379.930 0.000 1380.070 0.420 ;
    END
  END rw0_rd_out[243]
  PIN rw0_rd_out[244]
    DIRECTION OUTPUT ;
    USE SIGNAL ;
    SHAPE ABUTMENT ;
    PORT
      LAYER met2 ;
      RECT 1382.690 0.000 1382.830 0.420 ;
    END
  END rw0_rd_out[244]
  PIN rw0_rd_out[245]
    DIRECTION OUTPUT ;
    USE SIGNAL ;
    SHAPE ABUTMENT ;
    PORT
      LAYER met2 ;
      RECT 1385.450 0.000 1385.590 0.420 ;
    END
  END rw0_rd_out[245]
  PIN rw0_rd_out[246]
    DIRECTION OUTPUT ;
    USE SIGNAL ;
    SHAPE ABUTMENT ;
    PORT
      LAYER met2 ;
      RECT 1388.210 0.000 1388.350 0.420 ;
    END
  END rw0_rd_out[246]
  PIN rw0_rd_out[247]
    DIRECTION OUTPUT ;
    USE SIGNAL ;
    SHAPE ABUTMENT ;
    PORT
      LAYER met2 ;
      RECT 1390.970 0.000 1391.110 0.420 ;
    END
  END rw0_rd_out[247]
  PIN rw0_rd_out[248]
    DIRECTION OUTPUT ;
    USE SIGNAL ;
    SHAPE ABUTMENT ;
    PORT
      LAYER met2 ;
      RECT 1393.730 0.000 1393.870 0.420 ;
    END
  END rw0_rd_out[248]
  PIN rw0_rd_out[249]
    DIRECTION OUTPUT ;
    USE SIGNAL ;
    SHAPE ABUTMENT ;
    PORT
      LAYER met2 ;
      RECT 1396.490 0.000 1396.630 0.420 ;
    END
  END rw0_rd_out[249]
  PIN rw0_rd_out[250]
    DIRECTION OUTPUT ;
    USE SIGNAL ;
    SHAPE ABUTMENT ;
    PORT
      LAYER met2 ;
      RECT 1399.250 0.000 1399.390 0.420 ;
    END
  END rw0_rd_out[250]
  PIN rw0_rd_out[251]
    DIRECTION OUTPUT ;
    USE SIGNAL ;
    SHAPE ABUTMENT ;
    PORT
      LAYER met2 ;
      RECT 1402.010 0.000 1402.150 0.420 ;
    END
  END rw0_rd_out[251]
  PIN rw0_rd_out[252]
    DIRECTION OUTPUT ;
    USE SIGNAL ;
    SHAPE ABUTMENT ;
    PORT
      LAYER met2 ;
      RECT 1404.770 0.000 1404.910 0.420 ;
    END
  END rw0_rd_out[252]
  PIN rw0_rd_out[253]
    DIRECTION OUTPUT ;
    USE SIGNAL ;
    SHAPE ABUTMENT ;
    PORT
      LAYER met2 ;
      RECT 1407.530 0.000 1407.670 0.420 ;
    END
  END rw0_rd_out[253]
  PIN rw0_rd_out[254]
    DIRECTION OUTPUT ;
    USE SIGNAL ;
    SHAPE ABUTMENT ;
    PORT
      LAYER met2 ;
      RECT 1410.290 0.000 1410.430 0.420 ;
    END
  END rw0_rd_out[254]
  PIN rw0_rd_out[255]
    DIRECTION OUTPUT ;
    USE SIGNAL ;
    SHAPE ABUTMENT ;
    PORT
      LAYER met2 ;
      RECT 1413.050 0.000 1413.190 0.420 ;
    END
  END rw0_rd_out[255]
  PIN rw0_rd_out[256]
    DIRECTION OUTPUT ;
    USE SIGNAL ;
    SHAPE ABUTMENT ;
    PORT
      LAYER met2 ;
      RECT 709.250 290.620 709.390 291.040 ;
    END
  END rw0_rd_out[256]
  PIN rw0_rd_out[257]
    DIRECTION OUTPUT ;
    USE SIGNAL ;
    SHAPE ABUTMENT ;
    PORT
      LAYER met2 ;
      RECT 712.010 290.620 712.150 291.040 ;
    END
  END rw0_rd_out[257]
  PIN rw0_rd_out[258]
    DIRECTION OUTPUT ;
    USE SIGNAL ;
    SHAPE ABUTMENT ;
    PORT
      LAYER met2 ;
      RECT 714.770 290.620 714.910 291.040 ;
    END
  END rw0_rd_out[258]
  PIN rw0_rd_out[259]
    DIRECTION OUTPUT ;
    USE SIGNAL ;
    SHAPE ABUTMENT ;
    PORT
      LAYER met2 ;
      RECT 717.530 290.620 717.670 291.040 ;
    END
  END rw0_rd_out[259]
  PIN rw0_rd_out[260]
    DIRECTION OUTPUT ;
    USE SIGNAL ;
    SHAPE ABUTMENT ;
    PORT
      LAYER met2 ;
      RECT 720.290 290.620 720.430 291.040 ;
    END
  END rw0_rd_out[260]
  PIN rw0_rd_out[261]
    DIRECTION OUTPUT ;
    USE SIGNAL ;
    SHAPE ABUTMENT ;
    PORT
      LAYER met2 ;
      RECT 723.050 290.620 723.190 291.040 ;
    END
  END rw0_rd_out[261]
  PIN rw0_rd_out[262]
    DIRECTION OUTPUT ;
    USE SIGNAL ;
    SHAPE ABUTMENT ;
    PORT
      LAYER met2 ;
      RECT 725.810 290.620 725.950 291.040 ;
    END
  END rw0_rd_out[262]
  PIN rw0_rd_out[263]
    DIRECTION OUTPUT ;
    USE SIGNAL ;
    SHAPE ABUTMENT ;
    PORT
      LAYER met2 ;
      RECT 728.570 290.620 728.710 291.040 ;
    END
  END rw0_rd_out[263]
  PIN rw0_rd_out[264]
    DIRECTION OUTPUT ;
    USE SIGNAL ;
    SHAPE ABUTMENT ;
    PORT
      LAYER met2 ;
      RECT 731.330 290.620 731.470 291.040 ;
    END
  END rw0_rd_out[264]
  PIN rw0_rd_out[265]
    DIRECTION OUTPUT ;
    USE SIGNAL ;
    SHAPE ABUTMENT ;
    PORT
      LAYER met2 ;
      RECT 734.090 290.620 734.230 291.040 ;
    END
  END rw0_rd_out[265]
  PIN rw0_rd_out[266]
    DIRECTION OUTPUT ;
    USE SIGNAL ;
    SHAPE ABUTMENT ;
    PORT
      LAYER met2 ;
      RECT 736.850 290.620 736.990 291.040 ;
    END
  END rw0_rd_out[266]
  PIN rw0_rd_out[267]
    DIRECTION OUTPUT ;
    USE SIGNAL ;
    SHAPE ABUTMENT ;
    PORT
      LAYER met2 ;
      RECT 739.610 290.620 739.750 291.040 ;
    END
  END rw0_rd_out[267]
  PIN rw0_rd_out[268]
    DIRECTION OUTPUT ;
    USE SIGNAL ;
    SHAPE ABUTMENT ;
    PORT
      LAYER met2 ;
      RECT 742.370 290.620 742.510 291.040 ;
    END
  END rw0_rd_out[268]
  PIN rw0_rd_out[269]
    DIRECTION OUTPUT ;
    USE SIGNAL ;
    SHAPE ABUTMENT ;
    PORT
      LAYER met2 ;
      RECT 745.130 290.620 745.270 291.040 ;
    END
  END rw0_rd_out[269]
  PIN rw0_rd_out[270]
    DIRECTION OUTPUT ;
    USE SIGNAL ;
    SHAPE ABUTMENT ;
    PORT
      LAYER met2 ;
      RECT 747.890 290.620 748.030 291.040 ;
    END
  END rw0_rd_out[270]
  PIN rw0_rd_out[271]
    DIRECTION OUTPUT ;
    USE SIGNAL ;
    SHAPE ABUTMENT ;
    PORT
      LAYER met2 ;
      RECT 750.650 290.620 750.790 291.040 ;
    END
  END rw0_rd_out[271]
  PIN rw0_rd_out[272]
    DIRECTION OUTPUT ;
    USE SIGNAL ;
    SHAPE ABUTMENT ;
    PORT
      LAYER met2 ;
      RECT 753.410 290.620 753.550 291.040 ;
    END
  END rw0_rd_out[272]
  PIN rw0_rd_out[273]
    DIRECTION OUTPUT ;
    USE SIGNAL ;
    SHAPE ABUTMENT ;
    PORT
      LAYER met2 ;
      RECT 756.170 290.620 756.310 291.040 ;
    END
  END rw0_rd_out[273]
  PIN rw0_rd_out[274]
    DIRECTION OUTPUT ;
    USE SIGNAL ;
    SHAPE ABUTMENT ;
    PORT
      LAYER met2 ;
      RECT 758.930 290.620 759.070 291.040 ;
    END
  END rw0_rd_out[274]
  PIN rw0_rd_out[275]
    DIRECTION OUTPUT ;
    USE SIGNAL ;
    SHAPE ABUTMENT ;
    PORT
      LAYER met2 ;
      RECT 761.690 290.620 761.830 291.040 ;
    END
  END rw0_rd_out[275]
  PIN rw0_rd_out[276]
    DIRECTION OUTPUT ;
    USE SIGNAL ;
    SHAPE ABUTMENT ;
    PORT
      LAYER met2 ;
      RECT 764.450 290.620 764.590 291.040 ;
    END
  END rw0_rd_out[276]
  PIN rw0_rd_out[277]
    DIRECTION OUTPUT ;
    USE SIGNAL ;
    SHAPE ABUTMENT ;
    PORT
      LAYER met2 ;
      RECT 767.210 290.620 767.350 291.040 ;
    END
  END rw0_rd_out[277]
  PIN rw0_rd_out[278]
    DIRECTION OUTPUT ;
    USE SIGNAL ;
    SHAPE ABUTMENT ;
    PORT
      LAYER met2 ;
      RECT 769.970 290.620 770.110 291.040 ;
    END
  END rw0_rd_out[278]
  PIN rw0_rd_out[279]
    DIRECTION OUTPUT ;
    USE SIGNAL ;
    SHAPE ABUTMENT ;
    PORT
      LAYER met2 ;
      RECT 772.730 290.620 772.870 291.040 ;
    END
  END rw0_rd_out[279]
  PIN rw0_rd_out[280]
    DIRECTION OUTPUT ;
    USE SIGNAL ;
    SHAPE ABUTMENT ;
    PORT
      LAYER met2 ;
      RECT 775.490 290.620 775.630 291.040 ;
    END
  END rw0_rd_out[280]
  PIN rw0_rd_out[281]
    DIRECTION OUTPUT ;
    USE SIGNAL ;
    SHAPE ABUTMENT ;
    PORT
      LAYER met2 ;
      RECT 778.250 290.620 778.390 291.040 ;
    END
  END rw0_rd_out[281]
  PIN rw0_rd_out[282]
    DIRECTION OUTPUT ;
    USE SIGNAL ;
    SHAPE ABUTMENT ;
    PORT
      LAYER met2 ;
      RECT 781.010 290.620 781.150 291.040 ;
    END
  END rw0_rd_out[282]
  PIN rw0_rd_out[283]
    DIRECTION OUTPUT ;
    USE SIGNAL ;
    SHAPE ABUTMENT ;
    PORT
      LAYER met2 ;
      RECT 783.770 290.620 783.910 291.040 ;
    END
  END rw0_rd_out[283]
  PIN rw0_rd_out[284]
    DIRECTION OUTPUT ;
    USE SIGNAL ;
    SHAPE ABUTMENT ;
    PORT
      LAYER met2 ;
      RECT 786.530 290.620 786.670 291.040 ;
    END
  END rw0_rd_out[284]
  PIN rw0_rd_out[285]
    DIRECTION OUTPUT ;
    USE SIGNAL ;
    SHAPE ABUTMENT ;
    PORT
      LAYER met2 ;
      RECT 789.290 290.620 789.430 291.040 ;
    END
  END rw0_rd_out[285]
  PIN rw0_rd_out[286]
    DIRECTION OUTPUT ;
    USE SIGNAL ;
    SHAPE ABUTMENT ;
    PORT
      LAYER met2 ;
      RECT 792.050 290.620 792.190 291.040 ;
    END
  END rw0_rd_out[286]
  PIN rw0_rd_out[287]
    DIRECTION OUTPUT ;
    USE SIGNAL ;
    SHAPE ABUTMENT ;
    PORT
      LAYER met2 ;
      RECT 794.810 290.620 794.950 291.040 ;
    END
  END rw0_rd_out[287]
  PIN rw0_rd_out[288]
    DIRECTION OUTPUT ;
    USE SIGNAL ;
    SHAPE ABUTMENT ;
    PORT
      LAYER met2 ;
      RECT 797.570 290.620 797.710 291.040 ;
    END
  END rw0_rd_out[288]
  PIN rw0_rd_out[289]
    DIRECTION OUTPUT ;
    USE SIGNAL ;
    SHAPE ABUTMENT ;
    PORT
      LAYER met2 ;
      RECT 800.330 290.620 800.470 291.040 ;
    END
  END rw0_rd_out[289]
  PIN rw0_rd_out[290]
    DIRECTION OUTPUT ;
    USE SIGNAL ;
    SHAPE ABUTMENT ;
    PORT
      LAYER met2 ;
      RECT 803.090 290.620 803.230 291.040 ;
    END
  END rw0_rd_out[290]
  PIN rw0_rd_out[291]
    DIRECTION OUTPUT ;
    USE SIGNAL ;
    SHAPE ABUTMENT ;
    PORT
      LAYER met2 ;
      RECT 805.850 290.620 805.990 291.040 ;
    END
  END rw0_rd_out[291]
  PIN rw0_rd_out[292]
    DIRECTION OUTPUT ;
    USE SIGNAL ;
    SHAPE ABUTMENT ;
    PORT
      LAYER met2 ;
      RECT 808.610 290.620 808.750 291.040 ;
    END
  END rw0_rd_out[292]
  PIN rw0_rd_out[293]
    DIRECTION OUTPUT ;
    USE SIGNAL ;
    SHAPE ABUTMENT ;
    PORT
      LAYER met2 ;
      RECT 811.370 290.620 811.510 291.040 ;
    END
  END rw0_rd_out[293]
  PIN rw0_rd_out[294]
    DIRECTION OUTPUT ;
    USE SIGNAL ;
    SHAPE ABUTMENT ;
    PORT
      LAYER met2 ;
      RECT 814.130 290.620 814.270 291.040 ;
    END
  END rw0_rd_out[294]
  PIN rw0_rd_out[295]
    DIRECTION OUTPUT ;
    USE SIGNAL ;
    SHAPE ABUTMENT ;
    PORT
      LAYER met2 ;
      RECT 816.890 290.620 817.030 291.040 ;
    END
  END rw0_rd_out[295]
  PIN rw0_rd_out[296]
    DIRECTION OUTPUT ;
    USE SIGNAL ;
    SHAPE ABUTMENT ;
    PORT
      LAYER met2 ;
      RECT 819.650 290.620 819.790 291.040 ;
    END
  END rw0_rd_out[296]
  PIN rw0_rd_out[297]
    DIRECTION OUTPUT ;
    USE SIGNAL ;
    SHAPE ABUTMENT ;
    PORT
      LAYER met2 ;
      RECT 822.410 290.620 822.550 291.040 ;
    END
  END rw0_rd_out[297]
  PIN rw0_rd_out[298]
    DIRECTION OUTPUT ;
    USE SIGNAL ;
    SHAPE ABUTMENT ;
    PORT
      LAYER met2 ;
      RECT 825.170 290.620 825.310 291.040 ;
    END
  END rw0_rd_out[298]
  PIN rw0_rd_out[299]
    DIRECTION OUTPUT ;
    USE SIGNAL ;
    SHAPE ABUTMENT ;
    PORT
      LAYER met2 ;
      RECT 827.930 290.620 828.070 291.040 ;
    END
  END rw0_rd_out[299]
  PIN rw0_rd_out[300]
    DIRECTION OUTPUT ;
    USE SIGNAL ;
    SHAPE ABUTMENT ;
    PORT
      LAYER met2 ;
      RECT 830.690 290.620 830.830 291.040 ;
    END
  END rw0_rd_out[300]
  PIN rw0_rd_out[301]
    DIRECTION OUTPUT ;
    USE SIGNAL ;
    SHAPE ABUTMENT ;
    PORT
      LAYER met2 ;
      RECT 833.450 290.620 833.590 291.040 ;
    END
  END rw0_rd_out[301]
  PIN rw0_rd_out[302]
    DIRECTION OUTPUT ;
    USE SIGNAL ;
    SHAPE ABUTMENT ;
    PORT
      LAYER met2 ;
      RECT 836.210 290.620 836.350 291.040 ;
    END
  END rw0_rd_out[302]
  PIN rw0_rd_out[303]
    DIRECTION OUTPUT ;
    USE SIGNAL ;
    SHAPE ABUTMENT ;
    PORT
      LAYER met2 ;
      RECT 838.970 290.620 839.110 291.040 ;
    END
  END rw0_rd_out[303]
  PIN rw0_rd_out[304]
    DIRECTION OUTPUT ;
    USE SIGNAL ;
    SHAPE ABUTMENT ;
    PORT
      LAYER met2 ;
      RECT 841.730 290.620 841.870 291.040 ;
    END
  END rw0_rd_out[304]
  PIN rw0_rd_out[305]
    DIRECTION OUTPUT ;
    USE SIGNAL ;
    SHAPE ABUTMENT ;
    PORT
      LAYER met2 ;
      RECT 844.490 290.620 844.630 291.040 ;
    END
  END rw0_rd_out[305]
  PIN rw0_rd_out[306]
    DIRECTION OUTPUT ;
    USE SIGNAL ;
    SHAPE ABUTMENT ;
    PORT
      LAYER met2 ;
      RECT 847.250 290.620 847.390 291.040 ;
    END
  END rw0_rd_out[306]
  PIN rw0_rd_out[307]
    DIRECTION OUTPUT ;
    USE SIGNAL ;
    SHAPE ABUTMENT ;
    PORT
      LAYER met2 ;
      RECT 850.010 290.620 850.150 291.040 ;
    END
  END rw0_rd_out[307]
  PIN rw0_rd_out[308]
    DIRECTION OUTPUT ;
    USE SIGNAL ;
    SHAPE ABUTMENT ;
    PORT
      LAYER met2 ;
      RECT 852.770 290.620 852.910 291.040 ;
    END
  END rw0_rd_out[308]
  PIN rw0_rd_out[309]
    DIRECTION OUTPUT ;
    USE SIGNAL ;
    SHAPE ABUTMENT ;
    PORT
      LAYER met2 ;
      RECT 855.530 290.620 855.670 291.040 ;
    END
  END rw0_rd_out[309]
  PIN rw0_rd_out[310]
    DIRECTION OUTPUT ;
    USE SIGNAL ;
    SHAPE ABUTMENT ;
    PORT
      LAYER met2 ;
      RECT 858.290 290.620 858.430 291.040 ;
    END
  END rw0_rd_out[310]
  PIN rw0_rd_out[311]
    DIRECTION OUTPUT ;
    USE SIGNAL ;
    SHAPE ABUTMENT ;
    PORT
      LAYER met2 ;
      RECT 861.050 290.620 861.190 291.040 ;
    END
  END rw0_rd_out[311]
  PIN rw0_rd_out[312]
    DIRECTION OUTPUT ;
    USE SIGNAL ;
    SHAPE ABUTMENT ;
    PORT
      LAYER met2 ;
      RECT 863.810 290.620 863.950 291.040 ;
    END
  END rw0_rd_out[312]
  PIN rw0_rd_out[313]
    DIRECTION OUTPUT ;
    USE SIGNAL ;
    SHAPE ABUTMENT ;
    PORT
      LAYER met2 ;
      RECT 866.570 290.620 866.710 291.040 ;
    END
  END rw0_rd_out[313]
  PIN rw0_rd_out[314]
    DIRECTION OUTPUT ;
    USE SIGNAL ;
    SHAPE ABUTMENT ;
    PORT
      LAYER met2 ;
      RECT 869.330 290.620 869.470 291.040 ;
    END
  END rw0_rd_out[314]
  PIN rw0_rd_out[315]
    DIRECTION OUTPUT ;
    USE SIGNAL ;
    SHAPE ABUTMENT ;
    PORT
      LAYER met2 ;
      RECT 872.090 290.620 872.230 291.040 ;
    END
  END rw0_rd_out[315]
  PIN rw0_rd_out[316]
    DIRECTION OUTPUT ;
    USE SIGNAL ;
    SHAPE ABUTMENT ;
    PORT
      LAYER met2 ;
      RECT 874.850 290.620 874.990 291.040 ;
    END
  END rw0_rd_out[316]
  PIN rw0_rd_out[317]
    DIRECTION OUTPUT ;
    USE SIGNAL ;
    SHAPE ABUTMENT ;
    PORT
      LAYER met2 ;
      RECT 877.610 290.620 877.750 291.040 ;
    END
  END rw0_rd_out[317]
  PIN rw0_rd_out[318]
    DIRECTION OUTPUT ;
    USE SIGNAL ;
    SHAPE ABUTMENT ;
    PORT
      LAYER met2 ;
      RECT 880.370 290.620 880.510 291.040 ;
    END
  END rw0_rd_out[318]
  PIN rw0_rd_out[319]
    DIRECTION OUTPUT ;
    USE SIGNAL ;
    SHAPE ABUTMENT ;
    PORT
      LAYER met2 ;
      RECT 883.130 290.620 883.270 291.040 ;
    END
  END rw0_rd_out[319]
  PIN rw0_rd_out[320]
    DIRECTION OUTPUT ;
    USE SIGNAL ;
    SHAPE ABUTMENT ;
    PORT
      LAYER met2 ;
      RECT 885.890 290.620 886.030 291.040 ;
    END
  END rw0_rd_out[320]
  PIN rw0_rd_out[321]
    DIRECTION OUTPUT ;
    USE SIGNAL ;
    SHAPE ABUTMENT ;
    PORT
      LAYER met2 ;
      RECT 888.650 290.620 888.790 291.040 ;
    END
  END rw0_rd_out[321]
  PIN rw0_rd_out[322]
    DIRECTION OUTPUT ;
    USE SIGNAL ;
    SHAPE ABUTMENT ;
    PORT
      LAYER met2 ;
      RECT 891.410 290.620 891.550 291.040 ;
    END
  END rw0_rd_out[322]
  PIN rw0_rd_out[323]
    DIRECTION OUTPUT ;
    USE SIGNAL ;
    SHAPE ABUTMENT ;
    PORT
      LAYER met2 ;
      RECT 894.170 290.620 894.310 291.040 ;
    END
  END rw0_rd_out[323]
  PIN rw0_rd_out[324]
    DIRECTION OUTPUT ;
    USE SIGNAL ;
    SHAPE ABUTMENT ;
    PORT
      LAYER met2 ;
      RECT 896.930 290.620 897.070 291.040 ;
    END
  END rw0_rd_out[324]
  PIN rw0_rd_out[325]
    DIRECTION OUTPUT ;
    USE SIGNAL ;
    SHAPE ABUTMENT ;
    PORT
      LAYER met2 ;
      RECT 899.690 290.620 899.830 291.040 ;
    END
  END rw0_rd_out[325]
  PIN rw0_rd_out[326]
    DIRECTION OUTPUT ;
    USE SIGNAL ;
    SHAPE ABUTMENT ;
    PORT
      LAYER met2 ;
      RECT 902.450 290.620 902.590 291.040 ;
    END
  END rw0_rd_out[326]
  PIN rw0_rd_out[327]
    DIRECTION OUTPUT ;
    USE SIGNAL ;
    SHAPE ABUTMENT ;
    PORT
      LAYER met2 ;
      RECT 905.210 290.620 905.350 291.040 ;
    END
  END rw0_rd_out[327]
  PIN rw0_rd_out[328]
    DIRECTION OUTPUT ;
    USE SIGNAL ;
    SHAPE ABUTMENT ;
    PORT
      LAYER met2 ;
      RECT 907.970 290.620 908.110 291.040 ;
    END
  END rw0_rd_out[328]
  PIN rw0_rd_out[329]
    DIRECTION OUTPUT ;
    USE SIGNAL ;
    SHAPE ABUTMENT ;
    PORT
      LAYER met2 ;
      RECT 910.730 290.620 910.870 291.040 ;
    END
  END rw0_rd_out[329]
  PIN rw0_rd_out[330]
    DIRECTION OUTPUT ;
    USE SIGNAL ;
    SHAPE ABUTMENT ;
    PORT
      LAYER met2 ;
      RECT 913.490 290.620 913.630 291.040 ;
    END
  END rw0_rd_out[330]
  PIN rw0_rd_out[331]
    DIRECTION OUTPUT ;
    USE SIGNAL ;
    SHAPE ABUTMENT ;
    PORT
      LAYER met2 ;
      RECT 916.250 290.620 916.390 291.040 ;
    END
  END rw0_rd_out[331]
  PIN rw0_rd_out[332]
    DIRECTION OUTPUT ;
    USE SIGNAL ;
    SHAPE ABUTMENT ;
    PORT
      LAYER met2 ;
      RECT 919.010 290.620 919.150 291.040 ;
    END
  END rw0_rd_out[332]
  PIN rw0_rd_out[333]
    DIRECTION OUTPUT ;
    USE SIGNAL ;
    SHAPE ABUTMENT ;
    PORT
      LAYER met2 ;
      RECT 921.770 290.620 921.910 291.040 ;
    END
  END rw0_rd_out[333]
  PIN rw0_rd_out[334]
    DIRECTION OUTPUT ;
    USE SIGNAL ;
    SHAPE ABUTMENT ;
    PORT
      LAYER met2 ;
      RECT 924.530 290.620 924.670 291.040 ;
    END
  END rw0_rd_out[334]
  PIN rw0_rd_out[335]
    DIRECTION OUTPUT ;
    USE SIGNAL ;
    SHAPE ABUTMENT ;
    PORT
      LAYER met2 ;
      RECT 927.290 290.620 927.430 291.040 ;
    END
  END rw0_rd_out[335]
  PIN rw0_rd_out[336]
    DIRECTION OUTPUT ;
    USE SIGNAL ;
    SHAPE ABUTMENT ;
    PORT
      LAYER met2 ;
      RECT 930.050 290.620 930.190 291.040 ;
    END
  END rw0_rd_out[336]
  PIN rw0_rd_out[337]
    DIRECTION OUTPUT ;
    USE SIGNAL ;
    SHAPE ABUTMENT ;
    PORT
      LAYER met2 ;
      RECT 932.810 290.620 932.950 291.040 ;
    END
  END rw0_rd_out[337]
  PIN rw0_rd_out[338]
    DIRECTION OUTPUT ;
    USE SIGNAL ;
    SHAPE ABUTMENT ;
    PORT
      LAYER met2 ;
      RECT 935.570 290.620 935.710 291.040 ;
    END
  END rw0_rd_out[338]
  PIN rw0_rd_out[339]
    DIRECTION OUTPUT ;
    USE SIGNAL ;
    SHAPE ABUTMENT ;
    PORT
      LAYER met2 ;
      RECT 938.330 290.620 938.470 291.040 ;
    END
  END rw0_rd_out[339]
  PIN rw0_rd_out[340]
    DIRECTION OUTPUT ;
    USE SIGNAL ;
    SHAPE ABUTMENT ;
    PORT
      LAYER met2 ;
      RECT 941.090 290.620 941.230 291.040 ;
    END
  END rw0_rd_out[340]
  PIN rw0_rd_out[341]
    DIRECTION OUTPUT ;
    USE SIGNAL ;
    SHAPE ABUTMENT ;
    PORT
      LAYER met2 ;
      RECT 943.850 290.620 943.990 291.040 ;
    END
  END rw0_rd_out[341]
  PIN rw0_rd_out[342]
    DIRECTION OUTPUT ;
    USE SIGNAL ;
    SHAPE ABUTMENT ;
    PORT
      LAYER met2 ;
      RECT 946.610 290.620 946.750 291.040 ;
    END
  END rw0_rd_out[342]
  PIN rw0_rd_out[343]
    DIRECTION OUTPUT ;
    USE SIGNAL ;
    SHAPE ABUTMENT ;
    PORT
      LAYER met2 ;
      RECT 949.370 290.620 949.510 291.040 ;
    END
  END rw0_rd_out[343]
  PIN rw0_rd_out[344]
    DIRECTION OUTPUT ;
    USE SIGNAL ;
    SHAPE ABUTMENT ;
    PORT
      LAYER met2 ;
      RECT 952.130 290.620 952.270 291.040 ;
    END
  END rw0_rd_out[344]
  PIN rw0_rd_out[345]
    DIRECTION OUTPUT ;
    USE SIGNAL ;
    SHAPE ABUTMENT ;
    PORT
      LAYER met2 ;
      RECT 954.890 290.620 955.030 291.040 ;
    END
  END rw0_rd_out[345]
  PIN rw0_rd_out[346]
    DIRECTION OUTPUT ;
    USE SIGNAL ;
    SHAPE ABUTMENT ;
    PORT
      LAYER met2 ;
      RECT 957.650 290.620 957.790 291.040 ;
    END
  END rw0_rd_out[346]
  PIN rw0_rd_out[347]
    DIRECTION OUTPUT ;
    USE SIGNAL ;
    SHAPE ABUTMENT ;
    PORT
      LAYER met2 ;
      RECT 960.410 290.620 960.550 291.040 ;
    END
  END rw0_rd_out[347]
  PIN rw0_rd_out[348]
    DIRECTION OUTPUT ;
    USE SIGNAL ;
    SHAPE ABUTMENT ;
    PORT
      LAYER met2 ;
      RECT 963.170 290.620 963.310 291.040 ;
    END
  END rw0_rd_out[348]
  PIN rw0_rd_out[349]
    DIRECTION OUTPUT ;
    USE SIGNAL ;
    SHAPE ABUTMENT ;
    PORT
      LAYER met2 ;
      RECT 965.930 290.620 966.070 291.040 ;
    END
  END rw0_rd_out[349]
  PIN rw0_rd_out[350]
    DIRECTION OUTPUT ;
    USE SIGNAL ;
    SHAPE ABUTMENT ;
    PORT
      LAYER met2 ;
      RECT 968.690 290.620 968.830 291.040 ;
    END
  END rw0_rd_out[350]
  PIN rw0_rd_out[351]
    DIRECTION OUTPUT ;
    USE SIGNAL ;
    SHAPE ABUTMENT ;
    PORT
      LAYER met2 ;
      RECT 971.450 290.620 971.590 291.040 ;
    END
  END rw0_rd_out[351]
  PIN rw0_rd_out[352]
    DIRECTION OUTPUT ;
    USE SIGNAL ;
    SHAPE ABUTMENT ;
    PORT
      LAYER met2 ;
      RECT 974.210 290.620 974.350 291.040 ;
    END
  END rw0_rd_out[352]
  PIN rw0_rd_out[353]
    DIRECTION OUTPUT ;
    USE SIGNAL ;
    SHAPE ABUTMENT ;
    PORT
      LAYER met2 ;
      RECT 976.970 290.620 977.110 291.040 ;
    END
  END rw0_rd_out[353]
  PIN rw0_rd_out[354]
    DIRECTION OUTPUT ;
    USE SIGNAL ;
    SHAPE ABUTMENT ;
    PORT
      LAYER met2 ;
      RECT 979.730 290.620 979.870 291.040 ;
    END
  END rw0_rd_out[354]
  PIN rw0_rd_out[355]
    DIRECTION OUTPUT ;
    USE SIGNAL ;
    SHAPE ABUTMENT ;
    PORT
      LAYER met2 ;
      RECT 982.490 290.620 982.630 291.040 ;
    END
  END rw0_rd_out[355]
  PIN rw0_rd_out[356]
    DIRECTION OUTPUT ;
    USE SIGNAL ;
    SHAPE ABUTMENT ;
    PORT
      LAYER met2 ;
      RECT 985.250 290.620 985.390 291.040 ;
    END
  END rw0_rd_out[356]
  PIN rw0_rd_out[357]
    DIRECTION OUTPUT ;
    USE SIGNAL ;
    SHAPE ABUTMENT ;
    PORT
      LAYER met2 ;
      RECT 988.010 290.620 988.150 291.040 ;
    END
  END rw0_rd_out[357]
  PIN rw0_rd_out[358]
    DIRECTION OUTPUT ;
    USE SIGNAL ;
    SHAPE ABUTMENT ;
    PORT
      LAYER met2 ;
      RECT 990.770 290.620 990.910 291.040 ;
    END
  END rw0_rd_out[358]
  PIN rw0_rd_out[359]
    DIRECTION OUTPUT ;
    USE SIGNAL ;
    SHAPE ABUTMENT ;
    PORT
      LAYER met2 ;
      RECT 993.530 290.620 993.670 291.040 ;
    END
  END rw0_rd_out[359]
  PIN rw0_rd_out[360]
    DIRECTION OUTPUT ;
    USE SIGNAL ;
    SHAPE ABUTMENT ;
    PORT
      LAYER met2 ;
      RECT 996.290 290.620 996.430 291.040 ;
    END
  END rw0_rd_out[360]
  PIN rw0_rd_out[361]
    DIRECTION OUTPUT ;
    USE SIGNAL ;
    SHAPE ABUTMENT ;
    PORT
      LAYER met2 ;
      RECT 999.050 290.620 999.190 291.040 ;
    END
  END rw0_rd_out[361]
  PIN rw0_rd_out[362]
    DIRECTION OUTPUT ;
    USE SIGNAL ;
    SHAPE ABUTMENT ;
    PORT
      LAYER met2 ;
      RECT 1001.810 290.620 1001.950 291.040 ;
    END
  END rw0_rd_out[362]
  PIN rw0_rd_out[363]
    DIRECTION OUTPUT ;
    USE SIGNAL ;
    SHAPE ABUTMENT ;
    PORT
      LAYER met2 ;
      RECT 1004.570 290.620 1004.710 291.040 ;
    END
  END rw0_rd_out[363]
  PIN rw0_rd_out[364]
    DIRECTION OUTPUT ;
    USE SIGNAL ;
    SHAPE ABUTMENT ;
    PORT
      LAYER met2 ;
      RECT 1007.330 290.620 1007.470 291.040 ;
    END
  END rw0_rd_out[364]
  PIN rw0_rd_out[365]
    DIRECTION OUTPUT ;
    USE SIGNAL ;
    SHAPE ABUTMENT ;
    PORT
      LAYER met2 ;
      RECT 1010.090 290.620 1010.230 291.040 ;
    END
  END rw0_rd_out[365]
  PIN rw0_rd_out[366]
    DIRECTION OUTPUT ;
    USE SIGNAL ;
    SHAPE ABUTMENT ;
    PORT
      LAYER met2 ;
      RECT 1012.850 290.620 1012.990 291.040 ;
    END
  END rw0_rd_out[366]
  PIN rw0_rd_out[367]
    DIRECTION OUTPUT ;
    USE SIGNAL ;
    SHAPE ABUTMENT ;
    PORT
      LAYER met2 ;
      RECT 1015.610 290.620 1015.750 291.040 ;
    END
  END rw0_rd_out[367]
  PIN rw0_rd_out[368]
    DIRECTION OUTPUT ;
    USE SIGNAL ;
    SHAPE ABUTMENT ;
    PORT
      LAYER met2 ;
      RECT 1018.370 290.620 1018.510 291.040 ;
    END
  END rw0_rd_out[368]
  PIN rw0_rd_out[369]
    DIRECTION OUTPUT ;
    USE SIGNAL ;
    SHAPE ABUTMENT ;
    PORT
      LAYER met2 ;
      RECT 1021.130 290.620 1021.270 291.040 ;
    END
  END rw0_rd_out[369]
  PIN rw0_rd_out[370]
    DIRECTION OUTPUT ;
    USE SIGNAL ;
    SHAPE ABUTMENT ;
    PORT
      LAYER met2 ;
      RECT 1023.890 290.620 1024.030 291.040 ;
    END
  END rw0_rd_out[370]
  PIN rw0_rd_out[371]
    DIRECTION OUTPUT ;
    USE SIGNAL ;
    SHAPE ABUTMENT ;
    PORT
      LAYER met2 ;
      RECT 1026.650 290.620 1026.790 291.040 ;
    END
  END rw0_rd_out[371]
  PIN rw0_rd_out[372]
    DIRECTION OUTPUT ;
    USE SIGNAL ;
    SHAPE ABUTMENT ;
    PORT
      LAYER met2 ;
      RECT 1029.410 290.620 1029.550 291.040 ;
    END
  END rw0_rd_out[372]
  PIN rw0_rd_out[373]
    DIRECTION OUTPUT ;
    USE SIGNAL ;
    SHAPE ABUTMENT ;
    PORT
      LAYER met2 ;
      RECT 1032.170 290.620 1032.310 291.040 ;
    END
  END rw0_rd_out[373]
  PIN rw0_rd_out[374]
    DIRECTION OUTPUT ;
    USE SIGNAL ;
    SHAPE ABUTMENT ;
    PORT
      LAYER met2 ;
      RECT 1034.930 290.620 1035.070 291.040 ;
    END
  END rw0_rd_out[374]
  PIN rw0_rd_out[375]
    DIRECTION OUTPUT ;
    USE SIGNAL ;
    SHAPE ABUTMENT ;
    PORT
      LAYER met2 ;
      RECT 1037.690 290.620 1037.830 291.040 ;
    END
  END rw0_rd_out[375]
  PIN rw0_rd_out[376]
    DIRECTION OUTPUT ;
    USE SIGNAL ;
    SHAPE ABUTMENT ;
    PORT
      LAYER met2 ;
      RECT 1040.450 290.620 1040.590 291.040 ;
    END
  END rw0_rd_out[376]
  PIN rw0_rd_out[377]
    DIRECTION OUTPUT ;
    USE SIGNAL ;
    SHAPE ABUTMENT ;
    PORT
      LAYER met2 ;
      RECT 1043.210 290.620 1043.350 291.040 ;
    END
  END rw0_rd_out[377]
  PIN rw0_rd_out[378]
    DIRECTION OUTPUT ;
    USE SIGNAL ;
    SHAPE ABUTMENT ;
    PORT
      LAYER met2 ;
      RECT 1045.970 290.620 1046.110 291.040 ;
    END
  END rw0_rd_out[378]
  PIN rw0_rd_out[379]
    DIRECTION OUTPUT ;
    USE SIGNAL ;
    SHAPE ABUTMENT ;
    PORT
      LAYER met2 ;
      RECT 1048.730 290.620 1048.870 291.040 ;
    END
  END rw0_rd_out[379]
  PIN rw0_rd_out[380]
    DIRECTION OUTPUT ;
    USE SIGNAL ;
    SHAPE ABUTMENT ;
    PORT
      LAYER met2 ;
      RECT 1051.490 290.620 1051.630 291.040 ;
    END
  END rw0_rd_out[380]
  PIN rw0_rd_out[381]
    DIRECTION OUTPUT ;
    USE SIGNAL ;
    SHAPE ABUTMENT ;
    PORT
      LAYER met2 ;
      RECT 1054.250 290.620 1054.390 291.040 ;
    END
  END rw0_rd_out[381]
  PIN rw0_rd_out[382]
    DIRECTION OUTPUT ;
    USE SIGNAL ;
    SHAPE ABUTMENT ;
    PORT
      LAYER met2 ;
      RECT 1057.010 290.620 1057.150 291.040 ;
    END
  END rw0_rd_out[382]
  PIN rw0_rd_out[383]
    DIRECTION OUTPUT ;
    USE SIGNAL ;
    SHAPE ABUTMENT ;
    PORT
      LAYER met2 ;
      RECT 1059.770 290.620 1059.910 291.040 ;
    END
  END rw0_rd_out[383]
  PIN rw0_rd_out[384]
    DIRECTION OUTPUT ;
    USE SIGNAL ;
    SHAPE ABUTMENT ;
    PORT
      LAYER met2 ;
      RECT 1062.530 290.620 1062.670 291.040 ;
    END
  END rw0_rd_out[384]
  PIN rw0_rd_out[385]
    DIRECTION OUTPUT ;
    USE SIGNAL ;
    SHAPE ABUTMENT ;
    PORT
      LAYER met2 ;
      RECT 1065.290 290.620 1065.430 291.040 ;
    END
  END rw0_rd_out[385]
  PIN rw0_rd_out[386]
    DIRECTION OUTPUT ;
    USE SIGNAL ;
    SHAPE ABUTMENT ;
    PORT
      LAYER met2 ;
      RECT 1068.050 290.620 1068.190 291.040 ;
    END
  END rw0_rd_out[386]
  PIN rw0_rd_out[387]
    DIRECTION OUTPUT ;
    USE SIGNAL ;
    SHAPE ABUTMENT ;
    PORT
      LAYER met2 ;
      RECT 1070.810 290.620 1070.950 291.040 ;
    END
  END rw0_rd_out[387]
  PIN rw0_rd_out[388]
    DIRECTION OUTPUT ;
    USE SIGNAL ;
    SHAPE ABUTMENT ;
    PORT
      LAYER met2 ;
      RECT 1073.570 290.620 1073.710 291.040 ;
    END
  END rw0_rd_out[388]
  PIN rw0_rd_out[389]
    DIRECTION OUTPUT ;
    USE SIGNAL ;
    SHAPE ABUTMENT ;
    PORT
      LAYER met2 ;
      RECT 1076.330 290.620 1076.470 291.040 ;
    END
  END rw0_rd_out[389]
  PIN rw0_rd_out[390]
    DIRECTION OUTPUT ;
    USE SIGNAL ;
    SHAPE ABUTMENT ;
    PORT
      LAYER met2 ;
      RECT 1079.090 290.620 1079.230 291.040 ;
    END
  END rw0_rd_out[390]
  PIN rw0_rd_out[391]
    DIRECTION OUTPUT ;
    USE SIGNAL ;
    SHAPE ABUTMENT ;
    PORT
      LAYER met2 ;
      RECT 1081.850 290.620 1081.990 291.040 ;
    END
  END rw0_rd_out[391]
  PIN rw0_rd_out[392]
    DIRECTION OUTPUT ;
    USE SIGNAL ;
    SHAPE ABUTMENT ;
    PORT
      LAYER met2 ;
      RECT 1084.610 290.620 1084.750 291.040 ;
    END
  END rw0_rd_out[392]
  PIN rw0_rd_out[393]
    DIRECTION OUTPUT ;
    USE SIGNAL ;
    SHAPE ABUTMENT ;
    PORT
      LAYER met2 ;
      RECT 1087.370 290.620 1087.510 291.040 ;
    END
  END rw0_rd_out[393]
  PIN rw0_rd_out[394]
    DIRECTION OUTPUT ;
    USE SIGNAL ;
    SHAPE ABUTMENT ;
    PORT
      LAYER met2 ;
      RECT 1090.130 290.620 1090.270 291.040 ;
    END
  END rw0_rd_out[394]
  PIN rw0_rd_out[395]
    DIRECTION OUTPUT ;
    USE SIGNAL ;
    SHAPE ABUTMENT ;
    PORT
      LAYER met2 ;
      RECT 1092.890 290.620 1093.030 291.040 ;
    END
  END rw0_rd_out[395]
  PIN rw0_rd_out[396]
    DIRECTION OUTPUT ;
    USE SIGNAL ;
    SHAPE ABUTMENT ;
    PORT
      LAYER met2 ;
      RECT 1095.650 290.620 1095.790 291.040 ;
    END
  END rw0_rd_out[396]
  PIN rw0_rd_out[397]
    DIRECTION OUTPUT ;
    USE SIGNAL ;
    SHAPE ABUTMENT ;
    PORT
      LAYER met2 ;
      RECT 1098.410 290.620 1098.550 291.040 ;
    END
  END rw0_rd_out[397]
  PIN rw0_rd_out[398]
    DIRECTION OUTPUT ;
    USE SIGNAL ;
    SHAPE ABUTMENT ;
    PORT
      LAYER met2 ;
      RECT 1101.170 290.620 1101.310 291.040 ;
    END
  END rw0_rd_out[398]
  PIN rw0_rd_out[399]
    DIRECTION OUTPUT ;
    USE SIGNAL ;
    SHAPE ABUTMENT ;
    PORT
      LAYER met2 ;
      RECT 1103.930 290.620 1104.070 291.040 ;
    END
  END rw0_rd_out[399]
  PIN rw0_rd_out[400]
    DIRECTION OUTPUT ;
    USE SIGNAL ;
    SHAPE ABUTMENT ;
    PORT
      LAYER met2 ;
      RECT 1106.690 290.620 1106.830 291.040 ;
    END
  END rw0_rd_out[400]
  PIN rw0_rd_out[401]
    DIRECTION OUTPUT ;
    USE SIGNAL ;
    SHAPE ABUTMENT ;
    PORT
      LAYER met2 ;
      RECT 1109.450 290.620 1109.590 291.040 ;
    END
  END rw0_rd_out[401]
  PIN rw0_rd_out[402]
    DIRECTION OUTPUT ;
    USE SIGNAL ;
    SHAPE ABUTMENT ;
    PORT
      LAYER met2 ;
      RECT 1112.210 290.620 1112.350 291.040 ;
    END
  END rw0_rd_out[402]
  PIN rw0_rd_out[403]
    DIRECTION OUTPUT ;
    USE SIGNAL ;
    SHAPE ABUTMENT ;
    PORT
      LAYER met2 ;
      RECT 1114.970 290.620 1115.110 291.040 ;
    END
  END rw0_rd_out[403]
  PIN rw0_rd_out[404]
    DIRECTION OUTPUT ;
    USE SIGNAL ;
    SHAPE ABUTMENT ;
    PORT
      LAYER met2 ;
      RECT 1117.730 290.620 1117.870 291.040 ;
    END
  END rw0_rd_out[404]
  PIN rw0_rd_out[405]
    DIRECTION OUTPUT ;
    USE SIGNAL ;
    SHAPE ABUTMENT ;
    PORT
      LAYER met2 ;
      RECT 1120.490 290.620 1120.630 291.040 ;
    END
  END rw0_rd_out[405]
  PIN rw0_rd_out[406]
    DIRECTION OUTPUT ;
    USE SIGNAL ;
    SHAPE ABUTMENT ;
    PORT
      LAYER met2 ;
      RECT 1123.250 290.620 1123.390 291.040 ;
    END
  END rw0_rd_out[406]
  PIN rw0_rd_out[407]
    DIRECTION OUTPUT ;
    USE SIGNAL ;
    SHAPE ABUTMENT ;
    PORT
      LAYER met2 ;
      RECT 1126.010 290.620 1126.150 291.040 ;
    END
  END rw0_rd_out[407]
  PIN rw0_rd_out[408]
    DIRECTION OUTPUT ;
    USE SIGNAL ;
    SHAPE ABUTMENT ;
    PORT
      LAYER met2 ;
      RECT 1128.770 290.620 1128.910 291.040 ;
    END
  END rw0_rd_out[408]
  PIN rw0_rd_out[409]
    DIRECTION OUTPUT ;
    USE SIGNAL ;
    SHAPE ABUTMENT ;
    PORT
      LAYER met2 ;
      RECT 1131.530 290.620 1131.670 291.040 ;
    END
  END rw0_rd_out[409]
  PIN rw0_rd_out[410]
    DIRECTION OUTPUT ;
    USE SIGNAL ;
    SHAPE ABUTMENT ;
    PORT
      LAYER met2 ;
      RECT 1134.290 290.620 1134.430 291.040 ;
    END
  END rw0_rd_out[410]
  PIN rw0_rd_out[411]
    DIRECTION OUTPUT ;
    USE SIGNAL ;
    SHAPE ABUTMENT ;
    PORT
      LAYER met2 ;
      RECT 1137.050 290.620 1137.190 291.040 ;
    END
  END rw0_rd_out[411]
  PIN rw0_rd_out[412]
    DIRECTION OUTPUT ;
    USE SIGNAL ;
    SHAPE ABUTMENT ;
    PORT
      LAYER met2 ;
      RECT 1139.810 290.620 1139.950 291.040 ;
    END
  END rw0_rd_out[412]
  PIN rw0_rd_out[413]
    DIRECTION OUTPUT ;
    USE SIGNAL ;
    SHAPE ABUTMENT ;
    PORT
      LAYER met2 ;
      RECT 1142.570 290.620 1142.710 291.040 ;
    END
  END rw0_rd_out[413]
  PIN rw0_rd_out[414]
    DIRECTION OUTPUT ;
    USE SIGNAL ;
    SHAPE ABUTMENT ;
    PORT
      LAYER met2 ;
      RECT 1145.330 290.620 1145.470 291.040 ;
    END
  END rw0_rd_out[414]
  PIN rw0_rd_out[415]
    DIRECTION OUTPUT ;
    USE SIGNAL ;
    SHAPE ABUTMENT ;
    PORT
      LAYER met2 ;
      RECT 1148.090 290.620 1148.230 291.040 ;
    END
  END rw0_rd_out[415]
  PIN rw0_rd_out[416]
    DIRECTION OUTPUT ;
    USE SIGNAL ;
    SHAPE ABUTMENT ;
    PORT
      LAYER met2 ;
      RECT 1150.850 290.620 1150.990 291.040 ;
    END
  END rw0_rd_out[416]
  PIN rw0_rd_out[417]
    DIRECTION OUTPUT ;
    USE SIGNAL ;
    SHAPE ABUTMENT ;
    PORT
      LAYER met2 ;
      RECT 1153.610 290.620 1153.750 291.040 ;
    END
  END rw0_rd_out[417]
  PIN rw0_rd_out[418]
    DIRECTION OUTPUT ;
    USE SIGNAL ;
    SHAPE ABUTMENT ;
    PORT
      LAYER met2 ;
      RECT 1156.370 290.620 1156.510 291.040 ;
    END
  END rw0_rd_out[418]
  PIN rw0_rd_out[419]
    DIRECTION OUTPUT ;
    USE SIGNAL ;
    SHAPE ABUTMENT ;
    PORT
      LAYER met2 ;
      RECT 1159.130 290.620 1159.270 291.040 ;
    END
  END rw0_rd_out[419]
  PIN rw0_rd_out[420]
    DIRECTION OUTPUT ;
    USE SIGNAL ;
    SHAPE ABUTMENT ;
    PORT
      LAYER met2 ;
      RECT 1161.890 290.620 1162.030 291.040 ;
    END
  END rw0_rd_out[420]
  PIN rw0_rd_out[421]
    DIRECTION OUTPUT ;
    USE SIGNAL ;
    SHAPE ABUTMENT ;
    PORT
      LAYER met2 ;
      RECT 1164.650 290.620 1164.790 291.040 ;
    END
  END rw0_rd_out[421]
  PIN rw0_rd_out[422]
    DIRECTION OUTPUT ;
    USE SIGNAL ;
    SHAPE ABUTMENT ;
    PORT
      LAYER met2 ;
      RECT 1167.410 290.620 1167.550 291.040 ;
    END
  END rw0_rd_out[422]
  PIN rw0_rd_out[423]
    DIRECTION OUTPUT ;
    USE SIGNAL ;
    SHAPE ABUTMENT ;
    PORT
      LAYER met2 ;
      RECT 1170.170 290.620 1170.310 291.040 ;
    END
  END rw0_rd_out[423]
  PIN rw0_rd_out[424]
    DIRECTION OUTPUT ;
    USE SIGNAL ;
    SHAPE ABUTMENT ;
    PORT
      LAYER met2 ;
      RECT 1172.930 290.620 1173.070 291.040 ;
    END
  END rw0_rd_out[424]
  PIN rw0_rd_out[425]
    DIRECTION OUTPUT ;
    USE SIGNAL ;
    SHAPE ABUTMENT ;
    PORT
      LAYER met2 ;
      RECT 1175.690 290.620 1175.830 291.040 ;
    END
  END rw0_rd_out[425]
  PIN rw0_rd_out[426]
    DIRECTION OUTPUT ;
    USE SIGNAL ;
    SHAPE ABUTMENT ;
    PORT
      LAYER met2 ;
      RECT 1178.450 290.620 1178.590 291.040 ;
    END
  END rw0_rd_out[426]
  PIN rw0_rd_out[427]
    DIRECTION OUTPUT ;
    USE SIGNAL ;
    SHAPE ABUTMENT ;
    PORT
      LAYER met2 ;
      RECT 1181.210 290.620 1181.350 291.040 ;
    END
  END rw0_rd_out[427]
  PIN rw0_rd_out[428]
    DIRECTION OUTPUT ;
    USE SIGNAL ;
    SHAPE ABUTMENT ;
    PORT
      LAYER met2 ;
      RECT 1183.970 290.620 1184.110 291.040 ;
    END
  END rw0_rd_out[428]
  PIN rw0_rd_out[429]
    DIRECTION OUTPUT ;
    USE SIGNAL ;
    SHAPE ABUTMENT ;
    PORT
      LAYER met2 ;
      RECT 1186.730 290.620 1186.870 291.040 ;
    END
  END rw0_rd_out[429]
  PIN rw0_rd_out[430]
    DIRECTION OUTPUT ;
    USE SIGNAL ;
    SHAPE ABUTMENT ;
    PORT
      LAYER met2 ;
      RECT 1189.490 290.620 1189.630 291.040 ;
    END
  END rw0_rd_out[430]
  PIN rw0_rd_out[431]
    DIRECTION OUTPUT ;
    USE SIGNAL ;
    SHAPE ABUTMENT ;
    PORT
      LAYER met2 ;
      RECT 1192.250 290.620 1192.390 291.040 ;
    END
  END rw0_rd_out[431]
  PIN rw0_rd_out[432]
    DIRECTION OUTPUT ;
    USE SIGNAL ;
    SHAPE ABUTMENT ;
    PORT
      LAYER met2 ;
      RECT 1195.010 290.620 1195.150 291.040 ;
    END
  END rw0_rd_out[432]
  PIN rw0_rd_out[433]
    DIRECTION OUTPUT ;
    USE SIGNAL ;
    SHAPE ABUTMENT ;
    PORT
      LAYER met2 ;
      RECT 1197.770 290.620 1197.910 291.040 ;
    END
  END rw0_rd_out[433]
  PIN rw0_rd_out[434]
    DIRECTION OUTPUT ;
    USE SIGNAL ;
    SHAPE ABUTMENT ;
    PORT
      LAYER met2 ;
      RECT 1200.530 290.620 1200.670 291.040 ;
    END
  END rw0_rd_out[434]
  PIN rw0_rd_out[435]
    DIRECTION OUTPUT ;
    USE SIGNAL ;
    SHAPE ABUTMENT ;
    PORT
      LAYER met2 ;
      RECT 1203.290 290.620 1203.430 291.040 ;
    END
  END rw0_rd_out[435]
  PIN rw0_rd_out[436]
    DIRECTION OUTPUT ;
    USE SIGNAL ;
    SHAPE ABUTMENT ;
    PORT
      LAYER met2 ;
      RECT 1206.050 290.620 1206.190 291.040 ;
    END
  END rw0_rd_out[436]
  PIN rw0_rd_out[437]
    DIRECTION OUTPUT ;
    USE SIGNAL ;
    SHAPE ABUTMENT ;
    PORT
      LAYER met2 ;
      RECT 1208.810 290.620 1208.950 291.040 ;
    END
  END rw0_rd_out[437]
  PIN rw0_rd_out[438]
    DIRECTION OUTPUT ;
    USE SIGNAL ;
    SHAPE ABUTMENT ;
    PORT
      LAYER met2 ;
      RECT 1211.570 290.620 1211.710 291.040 ;
    END
  END rw0_rd_out[438]
  PIN rw0_rd_out[439]
    DIRECTION OUTPUT ;
    USE SIGNAL ;
    SHAPE ABUTMENT ;
    PORT
      LAYER met2 ;
      RECT 1214.330 290.620 1214.470 291.040 ;
    END
  END rw0_rd_out[439]
  PIN rw0_rd_out[440]
    DIRECTION OUTPUT ;
    USE SIGNAL ;
    SHAPE ABUTMENT ;
    PORT
      LAYER met2 ;
      RECT 1217.090 290.620 1217.230 291.040 ;
    END
  END rw0_rd_out[440]
  PIN rw0_rd_out[441]
    DIRECTION OUTPUT ;
    USE SIGNAL ;
    SHAPE ABUTMENT ;
    PORT
      LAYER met2 ;
      RECT 1219.850 290.620 1219.990 291.040 ;
    END
  END rw0_rd_out[441]
  PIN rw0_rd_out[442]
    DIRECTION OUTPUT ;
    USE SIGNAL ;
    SHAPE ABUTMENT ;
    PORT
      LAYER met2 ;
      RECT 1222.610 290.620 1222.750 291.040 ;
    END
  END rw0_rd_out[442]
  PIN rw0_rd_out[443]
    DIRECTION OUTPUT ;
    USE SIGNAL ;
    SHAPE ABUTMENT ;
    PORT
      LAYER met2 ;
      RECT 1225.370 290.620 1225.510 291.040 ;
    END
  END rw0_rd_out[443]
  PIN rw0_rd_out[444]
    DIRECTION OUTPUT ;
    USE SIGNAL ;
    SHAPE ABUTMENT ;
    PORT
      LAYER met2 ;
      RECT 1228.130 290.620 1228.270 291.040 ;
    END
  END rw0_rd_out[444]
  PIN rw0_rd_out[445]
    DIRECTION OUTPUT ;
    USE SIGNAL ;
    SHAPE ABUTMENT ;
    PORT
      LAYER met2 ;
      RECT 1230.890 290.620 1231.030 291.040 ;
    END
  END rw0_rd_out[445]
  PIN rw0_rd_out[446]
    DIRECTION OUTPUT ;
    USE SIGNAL ;
    SHAPE ABUTMENT ;
    PORT
      LAYER met2 ;
      RECT 1233.650 290.620 1233.790 291.040 ;
    END
  END rw0_rd_out[446]
  PIN rw0_rd_out[447]
    DIRECTION OUTPUT ;
    USE SIGNAL ;
    SHAPE ABUTMENT ;
    PORT
      LAYER met2 ;
      RECT 1236.410 290.620 1236.550 291.040 ;
    END
  END rw0_rd_out[447]
  PIN rw0_rd_out[448]
    DIRECTION OUTPUT ;
    USE SIGNAL ;
    SHAPE ABUTMENT ;
    PORT
      LAYER met2 ;
      RECT 1239.170 290.620 1239.310 291.040 ;
    END
  END rw0_rd_out[448]
  PIN rw0_rd_out[449]
    DIRECTION OUTPUT ;
    USE SIGNAL ;
    SHAPE ABUTMENT ;
    PORT
      LAYER met2 ;
      RECT 1241.930 290.620 1242.070 291.040 ;
    END
  END rw0_rd_out[449]
  PIN rw0_rd_out[450]
    DIRECTION OUTPUT ;
    USE SIGNAL ;
    SHAPE ABUTMENT ;
    PORT
      LAYER met2 ;
      RECT 1244.690 290.620 1244.830 291.040 ;
    END
  END rw0_rd_out[450]
  PIN rw0_rd_out[451]
    DIRECTION OUTPUT ;
    USE SIGNAL ;
    SHAPE ABUTMENT ;
    PORT
      LAYER met2 ;
      RECT 1247.450 290.620 1247.590 291.040 ;
    END
  END rw0_rd_out[451]
  PIN rw0_rd_out[452]
    DIRECTION OUTPUT ;
    USE SIGNAL ;
    SHAPE ABUTMENT ;
    PORT
      LAYER met2 ;
      RECT 1250.210 290.620 1250.350 291.040 ;
    END
  END rw0_rd_out[452]
  PIN rw0_rd_out[453]
    DIRECTION OUTPUT ;
    USE SIGNAL ;
    SHAPE ABUTMENT ;
    PORT
      LAYER met2 ;
      RECT 1252.970 290.620 1253.110 291.040 ;
    END
  END rw0_rd_out[453]
  PIN rw0_rd_out[454]
    DIRECTION OUTPUT ;
    USE SIGNAL ;
    SHAPE ABUTMENT ;
    PORT
      LAYER met2 ;
      RECT 1255.730 290.620 1255.870 291.040 ;
    END
  END rw0_rd_out[454]
  PIN rw0_rd_out[455]
    DIRECTION OUTPUT ;
    USE SIGNAL ;
    SHAPE ABUTMENT ;
    PORT
      LAYER met2 ;
      RECT 1258.490 290.620 1258.630 291.040 ;
    END
  END rw0_rd_out[455]
  PIN rw0_rd_out[456]
    DIRECTION OUTPUT ;
    USE SIGNAL ;
    SHAPE ABUTMENT ;
    PORT
      LAYER met2 ;
      RECT 1261.250 290.620 1261.390 291.040 ;
    END
  END rw0_rd_out[456]
  PIN rw0_rd_out[457]
    DIRECTION OUTPUT ;
    USE SIGNAL ;
    SHAPE ABUTMENT ;
    PORT
      LAYER met2 ;
      RECT 1264.010 290.620 1264.150 291.040 ;
    END
  END rw0_rd_out[457]
  PIN rw0_rd_out[458]
    DIRECTION OUTPUT ;
    USE SIGNAL ;
    SHAPE ABUTMENT ;
    PORT
      LAYER met2 ;
      RECT 1266.770 290.620 1266.910 291.040 ;
    END
  END rw0_rd_out[458]
  PIN rw0_rd_out[459]
    DIRECTION OUTPUT ;
    USE SIGNAL ;
    SHAPE ABUTMENT ;
    PORT
      LAYER met2 ;
      RECT 1269.530 290.620 1269.670 291.040 ;
    END
  END rw0_rd_out[459]
  PIN rw0_rd_out[460]
    DIRECTION OUTPUT ;
    USE SIGNAL ;
    SHAPE ABUTMENT ;
    PORT
      LAYER met2 ;
      RECT 1272.290 290.620 1272.430 291.040 ;
    END
  END rw0_rd_out[460]
  PIN rw0_rd_out[461]
    DIRECTION OUTPUT ;
    USE SIGNAL ;
    SHAPE ABUTMENT ;
    PORT
      LAYER met2 ;
      RECT 1275.050 290.620 1275.190 291.040 ;
    END
  END rw0_rd_out[461]
  PIN rw0_rd_out[462]
    DIRECTION OUTPUT ;
    USE SIGNAL ;
    SHAPE ABUTMENT ;
    PORT
      LAYER met2 ;
      RECT 1277.810 290.620 1277.950 291.040 ;
    END
  END rw0_rd_out[462]
  PIN rw0_rd_out[463]
    DIRECTION OUTPUT ;
    USE SIGNAL ;
    SHAPE ABUTMENT ;
    PORT
      LAYER met2 ;
      RECT 1280.570 290.620 1280.710 291.040 ;
    END
  END rw0_rd_out[463]
  PIN rw0_rd_out[464]
    DIRECTION OUTPUT ;
    USE SIGNAL ;
    SHAPE ABUTMENT ;
    PORT
      LAYER met2 ;
      RECT 1283.330 290.620 1283.470 291.040 ;
    END
  END rw0_rd_out[464]
  PIN rw0_rd_out[465]
    DIRECTION OUTPUT ;
    USE SIGNAL ;
    SHAPE ABUTMENT ;
    PORT
      LAYER met2 ;
      RECT 1286.090 290.620 1286.230 291.040 ;
    END
  END rw0_rd_out[465]
  PIN rw0_rd_out[466]
    DIRECTION OUTPUT ;
    USE SIGNAL ;
    SHAPE ABUTMENT ;
    PORT
      LAYER met2 ;
      RECT 1288.850 290.620 1288.990 291.040 ;
    END
  END rw0_rd_out[466]
  PIN rw0_rd_out[467]
    DIRECTION OUTPUT ;
    USE SIGNAL ;
    SHAPE ABUTMENT ;
    PORT
      LAYER met2 ;
      RECT 1291.610 290.620 1291.750 291.040 ;
    END
  END rw0_rd_out[467]
  PIN rw0_rd_out[468]
    DIRECTION OUTPUT ;
    USE SIGNAL ;
    SHAPE ABUTMENT ;
    PORT
      LAYER met2 ;
      RECT 1294.370 290.620 1294.510 291.040 ;
    END
  END rw0_rd_out[468]
  PIN rw0_rd_out[469]
    DIRECTION OUTPUT ;
    USE SIGNAL ;
    SHAPE ABUTMENT ;
    PORT
      LAYER met2 ;
      RECT 1297.130 290.620 1297.270 291.040 ;
    END
  END rw0_rd_out[469]
  PIN rw0_rd_out[470]
    DIRECTION OUTPUT ;
    USE SIGNAL ;
    SHAPE ABUTMENT ;
    PORT
      LAYER met2 ;
      RECT 1299.890 290.620 1300.030 291.040 ;
    END
  END rw0_rd_out[470]
  PIN rw0_rd_out[471]
    DIRECTION OUTPUT ;
    USE SIGNAL ;
    SHAPE ABUTMENT ;
    PORT
      LAYER met2 ;
      RECT 1302.650 290.620 1302.790 291.040 ;
    END
  END rw0_rd_out[471]
  PIN rw0_rd_out[472]
    DIRECTION OUTPUT ;
    USE SIGNAL ;
    SHAPE ABUTMENT ;
    PORT
      LAYER met2 ;
      RECT 1305.410 290.620 1305.550 291.040 ;
    END
  END rw0_rd_out[472]
  PIN rw0_rd_out[473]
    DIRECTION OUTPUT ;
    USE SIGNAL ;
    SHAPE ABUTMENT ;
    PORT
      LAYER met2 ;
      RECT 1308.170 290.620 1308.310 291.040 ;
    END
  END rw0_rd_out[473]
  PIN rw0_rd_out[474]
    DIRECTION OUTPUT ;
    USE SIGNAL ;
    SHAPE ABUTMENT ;
    PORT
      LAYER met2 ;
      RECT 1310.930 290.620 1311.070 291.040 ;
    END
  END rw0_rd_out[474]
  PIN rw0_rd_out[475]
    DIRECTION OUTPUT ;
    USE SIGNAL ;
    SHAPE ABUTMENT ;
    PORT
      LAYER met2 ;
      RECT 1313.690 290.620 1313.830 291.040 ;
    END
  END rw0_rd_out[475]
  PIN rw0_rd_out[476]
    DIRECTION OUTPUT ;
    USE SIGNAL ;
    SHAPE ABUTMENT ;
    PORT
      LAYER met2 ;
      RECT 1316.450 290.620 1316.590 291.040 ;
    END
  END rw0_rd_out[476]
  PIN rw0_rd_out[477]
    DIRECTION OUTPUT ;
    USE SIGNAL ;
    SHAPE ABUTMENT ;
    PORT
      LAYER met2 ;
      RECT 1319.210 290.620 1319.350 291.040 ;
    END
  END rw0_rd_out[477]
  PIN rw0_rd_out[478]
    DIRECTION OUTPUT ;
    USE SIGNAL ;
    SHAPE ABUTMENT ;
    PORT
      LAYER met2 ;
      RECT 1321.970 290.620 1322.110 291.040 ;
    END
  END rw0_rd_out[478]
  PIN rw0_rd_out[479]
    DIRECTION OUTPUT ;
    USE SIGNAL ;
    SHAPE ABUTMENT ;
    PORT
      LAYER met2 ;
      RECT 1324.730 290.620 1324.870 291.040 ;
    END
  END rw0_rd_out[479]
  PIN rw0_rd_out[480]
    DIRECTION OUTPUT ;
    USE SIGNAL ;
    SHAPE ABUTMENT ;
    PORT
      LAYER met2 ;
      RECT 1327.490 290.620 1327.630 291.040 ;
    END
  END rw0_rd_out[480]
  PIN rw0_rd_out[481]
    DIRECTION OUTPUT ;
    USE SIGNAL ;
    SHAPE ABUTMENT ;
    PORT
      LAYER met2 ;
      RECT 1330.250 290.620 1330.390 291.040 ;
    END
  END rw0_rd_out[481]
  PIN rw0_rd_out[482]
    DIRECTION OUTPUT ;
    USE SIGNAL ;
    SHAPE ABUTMENT ;
    PORT
      LAYER met2 ;
      RECT 1333.010 290.620 1333.150 291.040 ;
    END
  END rw0_rd_out[482]
  PIN rw0_rd_out[483]
    DIRECTION OUTPUT ;
    USE SIGNAL ;
    SHAPE ABUTMENT ;
    PORT
      LAYER met2 ;
      RECT 1335.770 290.620 1335.910 291.040 ;
    END
  END rw0_rd_out[483]
  PIN rw0_rd_out[484]
    DIRECTION OUTPUT ;
    USE SIGNAL ;
    SHAPE ABUTMENT ;
    PORT
      LAYER met2 ;
      RECT 1338.530 290.620 1338.670 291.040 ;
    END
  END rw0_rd_out[484]
  PIN rw0_rd_out[485]
    DIRECTION OUTPUT ;
    USE SIGNAL ;
    SHAPE ABUTMENT ;
    PORT
      LAYER met2 ;
      RECT 1341.290 290.620 1341.430 291.040 ;
    END
  END rw0_rd_out[485]
  PIN rw0_rd_out[486]
    DIRECTION OUTPUT ;
    USE SIGNAL ;
    SHAPE ABUTMENT ;
    PORT
      LAYER met2 ;
      RECT 1344.050 290.620 1344.190 291.040 ;
    END
  END rw0_rd_out[486]
  PIN rw0_rd_out[487]
    DIRECTION OUTPUT ;
    USE SIGNAL ;
    SHAPE ABUTMENT ;
    PORT
      LAYER met2 ;
      RECT 1346.810 290.620 1346.950 291.040 ;
    END
  END rw0_rd_out[487]
  PIN rw0_rd_out[488]
    DIRECTION OUTPUT ;
    USE SIGNAL ;
    SHAPE ABUTMENT ;
    PORT
      LAYER met2 ;
      RECT 1349.570 290.620 1349.710 291.040 ;
    END
  END rw0_rd_out[488]
  PIN rw0_rd_out[489]
    DIRECTION OUTPUT ;
    USE SIGNAL ;
    SHAPE ABUTMENT ;
    PORT
      LAYER met2 ;
      RECT 1352.330 290.620 1352.470 291.040 ;
    END
  END rw0_rd_out[489]
  PIN rw0_rd_out[490]
    DIRECTION OUTPUT ;
    USE SIGNAL ;
    SHAPE ABUTMENT ;
    PORT
      LAYER met2 ;
      RECT 1355.090 290.620 1355.230 291.040 ;
    END
  END rw0_rd_out[490]
  PIN rw0_rd_out[491]
    DIRECTION OUTPUT ;
    USE SIGNAL ;
    SHAPE ABUTMENT ;
    PORT
      LAYER met2 ;
      RECT 1357.850 290.620 1357.990 291.040 ;
    END
  END rw0_rd_out[491]
  PIN rw0_rd_out[492]
    DIRECTION OUTPUT ;
    USE SIGNAL ;
    SHAPE ABUTMENT ;
    PORT
      LAYER met2 ;
      RECT 1360.610 290.620 1360.750 291.040 ;
    END
  END rw0_rd_out[492]
  PIN rw0_rd_out[493]
    DIRECTION OUTPUT ;
    USE SIGNAL ;
    SHAPE ABUTMENT ;
    PORT
      LAYER met2 ;
      RECT 1363.370 290.620 1363.510 291.040 ;
    END
  END rw0_rd_out[493]
  PIN rw0_rd_out[494]
    DIRECTION OUTPUT ;
    USE SIGNAL ;
    SHAPE ABUTMENT ;
    PORT
      LAYER met2 ;
      RECT 1366.130 290.620 1366.270 291.040 ;
    END
  END rw0_rd_out[494]
  PIN rw0_rd_out[495]
    DIRECTION OUTPUT ;
    USE SIGNAL ;
    SHAPE ABUTMENT ;
    PORT
      LAYER met2 ;
      RECT 1368.890 290.620 1369.030 291.040 ;
    END
  END rw0_rd_out[495]
  PIN rw0_rd_out[496]
    DIRECTION OUTPUT ;
    USE SIGNAL ;
    SHAPE ABUTMENT ;
    PORT
      LAYER met2 ;
      RECT 1371.650 290.620 1371.790 291.040 ;
    END
  END rw0_rd_out[496]
  PIN rw0_rd_out[497]
    DIRECTION OUTPUT ;
    USE SIGNAL ;
    SHAPE ABUTMENT ;
    PORT
      LAYER met2 ;
      RECT 1374.410 290.620 1374.550 291.040 ;
    END
  END rw0_rd_out[497]
  PIN rw0_rd_out[498]
    DIRECTION OUTPUT ;
    USE SIGNAL ;
    SHAPE ABUTMENT ;
    PORT
      LAYER met2 ;
      RECT 1377.170 290.620 1377.310 291.040 ;
    END
  END rw0_rd_out[498]
  PIN rw0_rd_out[499]
    DIRECTION OUTPUT ;
    USE SIGNAL ;
    SHAPE ABUTMENT ;
    PORT
      LAYER met2 ;
      RECT 1379.930 290.620 1380.070 291.040 ;
    END
  END rw0_rd_out[499]
  PIN rw0_rd_out[500]
    DIRECTION OUTPUT ;
    USE SIGNAL ;
    SHAPE ABUTMENT ;
    PORT
      LAYER met2 ;
      RECT 1382.690 290.620 1382.830 291.040 ;
    END
  END rw0_rd_out[500]
  PIN rw0_rd_out[501]
    DIRECTION OUTPUT ;
    USE SIGNAL ;
    SHAPE ABUTMENT ;
    PORT
      LAYER met2 ;
      RECT 1385.450 290.620 1385.590 291.040 ;
    END
  END rw0_rd_out[501]
  PIN rw0_rd_out[502]
    DIRECTION OUTPUT ;
    USE SIGNAL ;
    SHAPE ABUTMENT ;
    PORT
      LAYER met2 ;
      RECT 1388.210 290.620 1388.350 291.040 ;
    END
  END rw0_rd_out[502]
  PIN rw0_rd_out[503]
    DIRECTION OUTPUT ;
    USE SIGNAL ;
    SHAPE ABUTMENT ;
    PORT
      LAYER met2 ;
      RECT 1390.970 290.620 1391.110 291.040 ;
    END
  END rw0_rd_out[503]
  PIN rw0_rd_out[504]
    DIRECTION OUTPUT ;
    USE SIGNAL ;
    SHAPE ABUTMENT ;
    PORT
      LAYER met2 ;
      RECT 1393.730 290.620 1393.870 291.040 ;
    END
  END rw0_rd_out[504]
  PIN rw0_rd_out[505]
    DIRECTION OUTPUT ;
    USE SIGNAL ;
    SHAPE ABUTMENT ;
    PORT
      LAYER met2 ;
      RECT 1396.490 290.620 1396.630 291.040 ;
    END
  END rw0_rd_out[505]
  PIN rw0_rd_out[506]
    DIRECTION OUTPUT ;
    USE SIGNAL ;
    SHAPE ABUTMENT ;
    PORT
      LAYER met2 ;
      RECT 1399.250 290.620 1399.390 291.040 ;
    END
  END rw0_rd_out[506]
  PIN rw0_rd_out[507]
    DIRECTION OUTPUT ;
    USE SIGNAL ;
    SHAPE ABUTMENT ;
    PORT
      LAYER met2 ;
      RECT 1402.010 290.620 1402.150 291.040 ;
    END
  END rw0_rd_out[507]
  PIN rw0_rd_out[508]
    DIRECTION OUTPUT ;
    USE SIGNAL ;
    SHAPE ABUTMENT ;
    PORT
      LAYER met2 ;
      RECT 1404.770 290.620 1404.910 291.040 ;
    END
  END rw0_rd_out[508]
  PIN rw0_rd_out[509]
    DIRECTION OUTPUT ;
    USE SIGNAL ;
    SHAPE ABUTMENT ;
    PORT
      LAYER met2 ;
      RECT 1407.530 290.620 1407.670 291.040 ;
    END
  END rw0_rd_out[509]
  PIN rw0_rd_out[510]
    DIRECTION OUTPUT ;
    USE SIGNAL ;
    SHAPE ABUTMENT ;
    PORT
      LAYER met2 ;
      RECT 1410.290 290.620 1410.430 291.040 ;
    END
  END rw0_rd_out[510]
  PIN rw0_rd_out[511]
    DIRECTION OUTPUT ;
    USE SIGNAL ;
    SHAPE ABUTMENT ;
    PORT
      LAYER met2 ;
      RECT 1413.050 290.620 1413.190 291.040 ;
    END
  END rw0_rd_out[511]
  PIN rw0_addr_in[0]
    DIRECTION INPUT ;
    USE SIGNAL ;
    SHAPE ABUTMENT ;
    PORT
      LAYER met3 ;
      RECT 0.000 178.010 0.900 178.310 ;
    END
  END rw0_addr_in[0]
  PIN rw0_addr_in[1]
    DIRECTION INPUT ;
    USE SIGNAL ;
    SHAPE ABUTMENT ;
    PORT
      LAYER met3 ;
      RECT 0.000 178.690 0.900 178.990 ;
    END
  END rw0_addr_in[1]
  PIN rw0_addr_in[2]
    DIRECTION INPUT ;
    USE SIGNAL ;
    SHAPE ABUTMENT ;
    PORT
      LAYER met3 ;
      RECT 0.000 179.370 0.900 179.670 ;
    END
  END rw0_addr_in[2]
  PIN rw0_addr_in[3]
    DIRECTION INPUT ;
    USE SIGNAL ;
    SHAPE ABUTMENT ;
    PORT
      LAYER met3 ;
      RECT 1430.620 178.010 1431.520 178.310 ;
    END
  END rw0_addr_in[3]
  PIN rw0_addr_in[4]
    DIRECTION INPUT ;
    USE SIGNAL ;
    SHAPE ABUTMENT ;
    PORT
      LAYER met3 ;
      RECT 1430.620 178.690 1431.520 178.990 ;
    END
  END rw0_addr_in[4]
  PIN rw0_addr_in[5]
    DIRECTION INPUT ;
    USE SIGNAL ;
    SHAPE ABUTMENT ;
    PORT
      LAYER met3 ;
      RECT 1430.620 179.370 1431.520 179.670 ;
    END
  END rw0_addr_in[5]
  PIN rw0_we_in
    DIRECTION INPUT ;
    USE SIGNAL ;
    SHAPE ABUTMENT ;
    PORT
      LAYER met2 ;
      RECT 1415.810 290.620 1415.950 291.040 ;
    END
  END rw0_we_in
  PIN rw0_ce_in
    DIRECTION INPUT ;
    USE SIGNAL ;
    SHAPE ABUTMENT ;
    PORT
      LAYER met2 ;
      RECT 1418.570 290.620 1418.710 291.040 ;
    END
  END rw0_ce_in
  PIN rw0_clk
    DIRECTION INPUT ;
    USE SIGNAL ;
    SHAPE ABUTMENT ;
    PORT
      LAYER met2 ;
      RECT 1421.330 290.620 1421.470 291.040 ;
    END
  END rw0_clk
  PIN VSS
    DIRECTION INOUT ;
    USE GROUND ;
    PORT
      LAYER met4 ;
      RECT 2.160 4.080 3.360 286.960 ;
      RECT 13.040 4.080 14.240 286.960 ;
      RECT 23.920 4.080 25.120 286.960 ;
      RECT 34.800 4.080 36.000 286.960 ;
      RECT 45.680 4.080 46.880 286.960 ;
      RECT 56.560 4.080 57.760 286.960 ;
      RECT 67.440 4.080 68.640 286.960 ;
      RECT 78.320 4.080 79.520 286.960 ;
      RECT 89.200 4.080 90.400 286.960 ;
      RECT 100.080 4.080 101.280 286.960 ;
      RECT 110.960 4.080 112.160 286.960 ;
      RECT 121.840 4.080 123.040 286.960 ;
      RECT 132.720 4.080 133.920 286.960 ;
      RECT 143.600 4.080 144.800 286.960 ;
      RECT 154.480 4.080 155.680 286.960 ;
      RECT 165.360 4.080 166.560 286.960 ;
      RECT 176.240 4.080 177.440 286.960 ;
      RECT 187.120 4.080 188.320 286.960 ;
      RECT 198.000 4.080 199.200 286.960 ;
      RECT 208.880 4.080 210.080 286.960 ;
      RECT 219.760 4.080 220.960 286.960 ;
      RECT 230.640 4.080 231.840 286.960 ;
      RECT 241.520 4.080 242.720 286.960 ;
      RECT 252.400 4.080 253.600 286.960 ;
      RECT 263.280 4.080 264.480 286.960 ;
      RECT 274.160 4.080 275.360 286.960 ;
      RECT 285.040 4.080 286.240 286.960 ;
      RECT 295.920 4.080 297.120 286.960 ;
      RECT 306.800 4.080 308.000 286.960 ;
      RECT 317.680 4.080 318.880 286.960 ;
      RECT 328.560 4.080 329.760 286.960 ;
      RECT 339.440 4.080 340.640 286.960 ;
      RECT 350.320 4.080 351.520 286.960 ;
      RECT 361.200 4.080 362.400 286.960 ;
      RECT 372.080 4.080 373.280 286.960 ;
      RECT 382.960 4.080 384.160 286.960 ;
      RECT 393.840 4.080 395.040 286.960 ;
      RECT 404.720 4.080 405.920 286.960 ;
      RECT 415.600 4.080 416.800 286.960 ;
      RECT 426.480 4.080 427.680 286.960 ;
      RECT 437.360 4.080 438.560 286.960 ;
      RECT 448.240 4.080 449.440 286.960 ;
      RECT 459.120 4.080 460.320 286.960 ;
      RECT 470.000 4.080 471.200 286.960 ;
      RECT 480.880 4.080 482.080 286.960 ;
      RECT 491.760 4.080 492.960 286.960 ;
      RECT 502.640 4.080 503.840 286.960 ;
      RECT 513.520 4.080 514.720 286.960 ;
      RECT 524.400 4.080 525.600 286.960 ;
      RECT 535.280 4.080 536.480 286.960 ;
      RECT 546.160 4.080 547.360 286.960 ;
      RECT 557.040 4.080 558.240 286.960 ;
      RECT 567.920 4.080 569.120 286.960 ;
      RECT 578.800 4.080 580.000 286.960 ;
      RECT 589.680 4.080 590.880 286.960 ;
      RECT 600.560 4.080 601.760 286.960 ;
      RECT 611.440 4.080 612.640 286.960 ;
      RECT 622.320 4.080 623.520 286.960 ;
      RECT 633.200 4.080 634.400 286.960 ;
      RECT 644.080 4.080 645.280 286.960 ;
      RECT 654.960 4.080 656.160 286.960 ;
      RECT 665.840 4.080 667.040 286.960 ;
      RECT 676.720 4.080 677.920 286.960 ;
      RECT 687.600 4.080 688.800 286.960 ;
      RECT 698.480 4.080 699.680 286.960 ;
      RECT 709.360 4.080 710.560 286.960 ;
      RECT 720.240 4.080 721.440 286.960 ;
      RECT 731.120 4.080 732.320 286.960 ;
      RECT 742.000 4.080 743.200 286.960 ;
      RECT 752.880 4.080 754.080 286.960 ;
      RECT 763.760 4.080 764.960 286.960 ;
      RECT 774.640 4.080 775.840 286.960 ;
      RECT 785.520 4.080 786.720 286.960 ;
      RECT 796.400 4.080 797.600 286.960 ;
      RECT 807.280 4.080 808.480 286.960 ;
      RECT 818.160 4.080 819.360 286.960 ;
      RECT 829.040 4.080 830.240 286.960 ;
      RECT 839.920 4.080 841.120 286.960 ;
      RECT 850.800 4.080 852.000 286.960 ;
      RECT 861.680 4.080 862.880 286.960 ;
      RECT 872.560 4.080 873.760 286.960 ;
      RECT 883.440 4.080 884.640 286.960 ;
      RECT 894.320 4.080 895.520 286.960 ;
      RECT 905.200 4.080 906.400 286.960 ;
      RECT 916.080 4.080 917.280 286.960 ;
      RECT 926.960 4.080 928.160 286.960 ;
      RECT 937.840 4.080 939.040 286.960 ;
      RECT 948.720 4.080 949.920 286.960 ;
      RECT 959.600 4.080 960.800 286.960 ;
      RECT 970.480 4.080 971.680 286.960 ;
      RECT 981.360 4.080 982.560 286.960 ;
      RECT 992.240 4.080 993.440 286.960 ;
      RECT 1003.120 4.080 1004.320 286.960 ;
      RECT 1014.000 4.080 1015.200 286.960 ;
      RECT 1024.880 4.080 1026.080 286.960 ;
      RECT 1035.760 4.080 1036.960 286.960 ;
      RECT 1046.640 4.080 1047.840 286.960 ;
      RECT 1057.520 4.080 1058.720 286.960 ;
      RECT 1068.400 4.080 1069.600 286.960 ;
      RECT 1079.280 4.080 1080.480 286.960 ;
      RECT 1090.160 4.080 1091.360 286.960 ;
      RECT 1101.040 4.080 1102.240 286.960 ;
      RECT 1111.920 4.080 1113.120 286.960 ;
      RECT 1122.800 4.080 1124.000 286.960 ;
      RECT 1133.680 4.080 1134.880 286.960 ;
      RECT 1144.560 4.080 1145.760 286.960 ;
      RECT 1155.440 4.080 1156.640 286.960 ;
      RECT 1166.320 4.080 1167.520 286.960 ;
      RECT 1177.200 4.080 1178.400 286.960 ;
      RECT 1188.080 4.080 1189.280 286.960 ;
      RECT 1198.960 4.080 1200.160 286.960 ;
      RECT 1209.840 4.080 1211.040 286.960 ;
      RECT 1220.720 4.080 1221.920 286.960 ;
      RECT 1231.600 4.080 1232.800 286.960 ;
      RECT 1242.480 4.080 1243.680 286.960 ;
      RECT 1253.360 4.080 1254.560 286.960 ;
      RECT 1264.240 4.080 1265.440 286.960 ;
      RECT 1275.120 4.080 1276.320 286.960 ;
      RECT 1286.000 4.080 1287.200 286.960 ;
      RECT 1296.880 4.080 1298.080 286.960 ;
      RECT 1307.760 4.080 1308.960 286.960 ;
      RECT 1318.640 4.080 1319.840 286.960 ;
      RECT 1329.520 4.080 1330.720 286.960 ;
      RECT 1340.400 4.080 1341.600 286.960 ;
      RECT 1351.280 4.080 1352.480 286.960 ;
      RECT 1362.160 4.080 1363.360 286.960 ;
      RECT 1373.040 4.080 1374.240 286.960 ;
      RECT 1383.920 4.080 1385.120 286.960 ;
      RECT 1394.800 4.080 1396.000 286.960 ;
      RECT 1405.680 4.080 1406.880 286.960 ;
      RECT 1416.560 4.080 1417.760 286.960 ;
      RECT 1427.440 4.080 1428.640 286.960 ;
    END
  END VSS
  PIN VDD
    DIRECTION INOUT ;
    USE POWER ;
    PORT
      LAYER met4 ;
      RECT 7.600 4.080 8.800 286.960 ;
      RECT 18.480 4.080 19.680 286.960 ;
      RECT 29.360 4.080 30.560 286.960 ;
      RECT 40.240 4.080 41.440 286.960 ;
      RECT 51.120 4.080 52.320 286.960 ;
      RECT 62.000 4.080 63.200 286.960 ;
      RECT 72.880 4.080 74.080 286.960 ;
      RECT 83.760 4.080 84.960 286.960 ;
      RECT 94.640 4.080 95.840 286.960 ;
      RECT 105.520 4.080 106.720 286.960 ;
      RECT 116.400 4.080 117.600 286.960 ;
      RECT 127.280 4.080 128.480 286.960 ;
      RECT 138.160 4.080 139.360 286.960 ;
      RECT 149.040 4.080 150.240 286.960 ;
      RECT 159.920 4.080 161.120 286.960 ;
      RECT 170.800 4.080 172.000 286.960 ;
      RECT 181.680 4.080 182.880 286.960 ;
      RECT 192.560 4.080 193.760 286.960 ;
      RECT 203.440 4.080 204.640 286.960 ;
      RECT 214.320 4.080 215.520 286.960 ;
      RECT 225.200 4.080 226.400 286.960 ;
      RECT 236.080 4.080 237.280 286.960 ;
      RECT 246.960 4.080 248.160 286.960 ;
      RECT 257.840 4.080 259.040 286.960 ;
      RECT 268.720 4.080 269.920 286.960 ;
      RECT 279.600 4.080 280.800 286.960 ;
      RECT 290.480 4.080 291.680 286.960 ;
      RECT 301.360 4.080 302.560 286.960 ;
      RECT 312.240 4.080 313.440 286.960 ;
      RECT 323.120 4.080 324.320 286.960 ;
      RECT 334.000 4.080 335.200 286.960 ;
      RECT 344.880 4.080 346.080 286.960 ;
      RECT 355.760 4.080 356.960 286.960 ;
      RECT 366.640 4.080 367.840 286.960 ;
      RECT 377.520 4.080 378.720 286.960 ;
      RECT 388.400 4.080 389.600 286.960 ;
      RECT 399.280 4.080 400.480 286.960 ;
      RECT 410.160 4.080 411.360 286.960 ;
      RECT 421.040 4.080 422.240 286.960 ;
      RECT 431.920 4.080 433.120 286.960 ;
      RECT 442.800 4.080 444.000 286.960 ;
      RECT 453.680 4.080 454.880 286.960 ;
      RECT 464.560 4.080 465.760 286.960 ;
      RECT 475.440 4.080 476.640 286.960 ;
      RECT 486.320 4.080 487.520 286.960 ;
      RECT 497.200 4.080 498.400 286.960 ;
      RECT 508.080 4.080 509.280 286.960 ;
      RECT 518.960 4.080 520.160 286.960 ;
      RECT 529.840 4.080 531.040 286.960 ;
      RECT 540.720 4.080 541.920 286.960 ;
      RECT 551.600 4.080 552.800 286.960 ;
      RECT 562.480 4.080 563.680 286.960 ;
      RECT 573.360 4.080 574.560 286.960 ;
      RECT 584.240 4.080 585.440 286.960 ;
      RECT 595.120 4.080 596.320 286.960 ;
      RECT 606.000 4.080 607.200 286.960 ;
      RECT 616.880 4.080 618.080 286.960 ;
      RECT 627.760 4.080 628.960 286.960 ;
      RECT 638.640 4.080 639.840 286.960 ;
      RECT 649.520 4.080 650.720 286.960 ;
      RECT 660.400 4.080 661.600 286.960 ;
      RECT 671.280 4.080 672.480 286.960 ;
      RECT 682.160 4.080 683.360 286.960 ;
      RECT 693.040 4.080 694.240 286.960 ;
      RECT 703.920 4.080 705.120 286.960 ;
      RECT 714.800 4.080 716.000 286.960 ;
      RECT 725.680 4.080 726.880 286.960 ;
      RECT 736.560 4.080 737.760 286.960 ;
      RECT 747.440 4.080 748.640 286.960 ;
      RECT 758.320 4.080 759.520 286.960 ;
      RECT 769.200 4.080 770.400 286.960 ;
      RECT 780.080 4.080 781.280 286.960 ;
      RECT 790.960 4.080 792.160 286.960 ;
      RECT 801.840 4.080 803.040 286.960 ;
      RECT 812.720 4.080 813.920 286.960 ;
      RECT 823.600 4.080 824.800 286.960 ;
      RECT 834.480 4.080 835.680 286.960 ;
      RECT 845.360 4.080 846.560 286.960 ;
      RECT 856.240 4.080 857.440 286.960 ;
      RECT 867.120 4.080 868.320 286.960 ;
      RECT 878.000 4.080 879.200 286.960 ;
      RECT 888.880 4.080 890.080 286.960 ;
      RECT 899.760 4.080 900.960 286.960 ;
      RECT 910.640 4.080 911.840 286.960 ;
      RECT 921.520 4.080 922.720 286.960 ;
      RECT 932.400 4.080 933.600 286.960 ;
      RECT 943.280 4.080 944.480 286.960 ;
      RECT 954.160 4.080 955.360 286.960 ;
      RECT 965.040 4.080 966.240 286.960 ;
      RECT 975.920 4.080 977.120 286.960 ;
      RECT 986.800 4.080 988.000 286.960 ;
      RECT 997.680 4.080 998.880 286.960 ;
      RECT 1008.560 4.080 1009.760 286.960 ;
      RECT 1019.440 4.080 1020.640 286.960 ;
      RECT 1030.320 4.080 1031.520 286.960 ;
      RECT 1041.200 4.080 1042.400 286.960 ;
      RECT 1052.080 4.080 1053.280 286.960 ;
      RECT 1062.960 4.080 1064.160 286.960 ;
      RECT 1073.840 4.080 1075.040 286.960 ;
      RECT 1084.720 4.080 1085.920 286.960 ;
      RECT 1095.600 4.080 1096.800 286.960 ;
      RECT 1106.480 4.080 1107.680 286.960 ;
      RECT 1117.360 4.080 1118.560 286.960 ;
      RECT 1128.240 4.080 1129.440 286.960 ;
      RECT 1139.120 4.080 1140.320 286.960 ;
      RECT 1150.000 4.080 1151.200 286.960 ;
      RECT 1160.880 4.080 1162.080 286.960 ;
      RECT 1171.760 4.080 1172.960 286.960 ;
      RECT 1182.640 4.080 1183.840 286.960 ;
      RECT 1193.520 4.080 1194.720 286.960 ;
      RECT 1204.400 4.080 1205.600 286.960 ;
      RECT 1215.280 4.080 1216.480 286.960 ;
      RECT 1226.160 4.080 1227.360 286.960 ;
      RECT 1237.040 4.080 1238.240 286.960 ;
      RECT 1247.920 4.080 1249.120 286.960 ;
      RECT 1258.800 4.080 1260.000 286.960 ;
      RECT 1269.680 4.080 1270.880 286.960 ;
      RECT 1280.560 4.080 1281.760 286.960 ;
      RECT 1291.440 4.080 1292.640 286.960 ;
      RECT 1302.320 4.080 1303.520 286.960 ;
      RECT 1313.200 4.080 1314.400 286.960 ;
      RECT 1324.080 4.080 1325.280 286.960 ;
      RECT 1334.960 4.080 1336.160 286.960 ;
      RECT 1345.840 4.080 1347.040 286.960 ;
      RECT 1356.720 4.080 1357.920 286.960 ;
      RECT 1367.600 4.080 1368.800 286.960 ;
      RECT 1378.480 4.080 1379.680 286.960 ;
      RECT 1389.360 4.080 1390.560 286.960 ;
      RECT 1400.240 4.080 1401.440 286.960 ;
      RECT 1411.120 4.080 1412.320 286.960 ;
      RECT 1422.000 4.080 1423.200 286.960 ;
    END
  END VDD
  OBS
    LAYER met1 ;
    RECT 0 0 1431.520 291.040 ;
    LAYER met2 ;
    RECT 0 0 1431.520 291.040 ;
    LAYER met3 ;
    RECT 0 0 1431.520 291.040 ;
    LAYER met4 ;
    RECT 0 0 1431.520 291.040 ;
  END
END fakeram_512x64_1rw

END LIBRARY
